NAMESCASESENSITIVE ON ;

UNITS
DATABASE MICRONS 1000 ;
END UNITS

LAYER NWELL
	TYPE MASTERSLICE ;
END NWELL
LAYER PP
	TYPE MASTERSLICE ;
END PP
LAYER NP
	TYPE MASTERSLICE ;
END NP
LAYER OD
	TYPE MASTERSLICE ;
END OD
LAYER POLY
	TYPE MASTERSLICE ;
END POLY
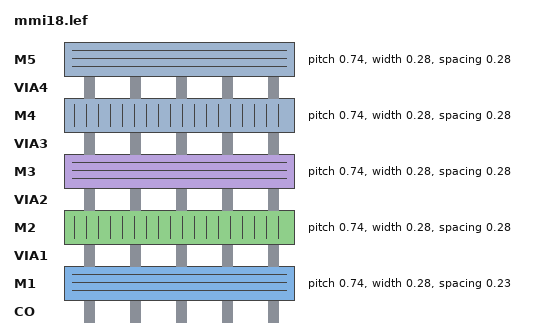
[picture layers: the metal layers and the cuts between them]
LAYER CO
	TYPE CUT ;
END CO
LAYER M1
	TYPE ROUTING ;
	PITCH 0.74 ;
	WIDTH 0.28 ;
	SPACING 0.23 ;
	DIRECTION HORIZONTAL ;
	RESISTANCE RPERSQ 0.11 ;
	CAPACITANCE CPERSQDIST .000389 ;
END M1
LAYER VIA1 
	TYPE CUT ;
END VIA1
LAYER M2
	TYPE ROUTING ;
	PITCH 0.74 ;
	WIDTH 0.28 ;
	SPACING 0.28 ;
	DIRECTION VERTICAL ;
	RESISTANCE RPERSQ 0.11 ;
	CAPACITANCE CPERSQDIST .000353 ;
END M2
LAYER VIA2
	TYPE CUT ;
END VIA2
LAYER M3
	TYPE ROUTING ;
	PITCH 0.74 ;
	WIDTH 0.28 ;
	SPACING 0.28 ;
	DIRECTION HORIZONTAL ;
	RESISTANCE RPERSQ 0.11 ;
	CAPACITANCE CPERSQDIST .000320 ;
END M3
LAYER VIA3
	TYPE CUT ;
END VIA3
LAYER M4
	TYPE ROUTING ;
	PITCH 0.74 ;
	WIDTH 0.28 ;
	SPACING 0.28 ;
	DIRECTION VERTICAL ;
	RESISTANCE RPERSQ 0.11 ;
	CAPACITANCE CPERSQDIST .000296 ;
END M4
LAYER VIA4
	TYPE CUT ;
END VIA4
LAYER M5
	TYPE ROUTING ;
	PITCH 0.74 ;
	WIDTH 0.28 ;
	SPACING 0.28 ;
	DIRECTION HORIZONTAL ;
	RESISTANCE RPERSQ 0.06 ;
	CAPACITANCE CPERSQDIST .000296 ;
END M5
VIA VIA12 DEFAULT
	RESISTANCE 1.21 ;
	LAYER M1 ; RECT -0.19 -0.19 0.19 0.19 ;
	LAYER VIA1 ; RECT -0.13 -0.13 0.13 0.13 ;
	LAYER M2 ; RECT -0.23 -0.23 0.23 0.23 ;
END VIA12
VIA VIA23 DEFAULT
	RESISTANCE 1.07 ;
	LAYER M2 ; RECT -0.23 -0.23 0.23 0.23 ;
	LAYER VIA2 ; RECT -0.13 -0.13 0.13 0.13 ;
	LAYER M3 ; RECT -0.23 -0.23 0.23 0.23 ;
END VIA23
VIA VIA34 DEFAULT
	RESISTANCE 1.19 ;
	LAYER M3 ; RECT -0.23 -0.23 0.23 0.23 ;
	LAYER VIA3 ; RECT -0.13 -0.13 0.13 0.13 ;
	LAYER M4 ; RECT -0.23 -0.23 0.23 0.23 ;
END VIA34
VIA VIA45 DEFAULT
	RESISTANCE 1.19 ;
	LAYER M4 ; RECT -0.23 -0.23 0.23 0.23 ;
	LAYER VIA4 ; RECT -0.13 -0.13 0.13 0.13 ;
	LAYER M5 ; RECT -0.23 -0.23 0.23 0.23 ;
END VIA45
VIARULE TURN1 GENERATE
	LAYER M1 ; DIRECTION HORIZONTAL ;
	LAYER M1 ; DIRECTION VERTICAL ;
END TURN1
VIARULE TURN2 GENERATE
	LAYER M2 ; DIRECTION VERTICAL ;
	LAYER M2 ; DIRECTION HORIZONTAL ;
END TURN2
VIARULE TURN3 GENERATE
	LAYER M3 ; DIRECTION HORIZONTAL ;
	LAYER M3 ; DIRECTION VERTICAL ;
END TURN3
VIARULE TURN4 GENERATE
	LAYER M4 ; DIRECTION VERTICAL ;
	LAYER M4 ; DIRECTION HORIZONTAL ;
END TURN4
VIARULE TURN5 GENERATE
	LAYER M5 ; DIRECTION HORIZONTAL ;
	LAYER M5 ; DIRECTION VERTICAL ;
END TURN5
VIARULE ONEVIA12
	LAYER M1 ; DIRECTION HORIZONTAL ; WIDTH 0.5 TO 0.9 ;
	LAYER M2 ; DIRECTION VERTICAL ; WIDTH 0.6 TO 0.9 ;
	VIA VIA12 ;
END ONEVIA12
VIARULE ONEVIA23
	LAYER M2 ; DIRECTION VERTICAL ; WIDTH 0.6 TO 0.9 ;
	LAYER M3 ; DIRECTION HORIZONTAL ; WIDTH 0.6 TO 0.9 ;
	VIA VIA23 ;
END ONEVIA23
VIARULE ONEVIA34
	LAYER M3 ; DIRECTION HORIZONTAL ; WIDTH 0.6 TO 0.9 ;
	LAYER M4 ; DIRECTION VERTICAL ; WIDTH 0.6 TO 0.9 ;
	VIA VIA34 ;
END ONEVIA34
VIARULE ONEVIA45
	LAYER M4 ; DIRECTION VERTICAL ; WIDTH 0.6 TO 0.9 ;
	LAYER M5 ; DIRECTION HORIZONTAL ; WIDTH 0.6 TO 0.9 ;
	VIA VIA45 ;
END ONEVIA45
VIARULE VIAGEN12 GENERATE
	LAYER M1 ; DIRECTION HORIZONTAL ; OVERHANG 0.06 ; METALOVERHANG 0.06 ;
	LAYER M2 ; DIRECTION VERTICAL ; OVERHANG 0.06 ; METALOVERHANG 0.06 ;
	LAYER VIA1 ; RECT  -0.13 -0.13 0.13 0.13 ; SPACING 0.74 BY 0.74 ;
END VIAGEN12
VIARULE VIAGEN23 GENERATE
	LAYER M2 ; DIRECTION VERTICAL ; OVERHANG 0.06 ; METALOVERHANG 0.06 ;
	LAYER M3 ; DIRECTION HORIZONTAL ; OVERHANG 0.06 ; METALOVERHANG 0.06 ;
	LAYER VIA2 ; RECT  -0.13 -0.13 0.13 0.13 ; SPACING 0.74 BY 0.74 ;
END VIAGEN23
VIARULE VIAGEN34 GENERATE
	LAYER M3 ; DIRECTION HORIZONTAL ; OVERHANG 0.06 ; METALOVERHANG 0.06 ;
	LAYER M4 ; DIRECTION VERTICAL ; OVERHANG 0.06 ; METALOVERHANG 0.06 ;
	LAYER VIA3 ; RECT  -0.13 -0.13 0.13 0.13 ; SPACING 0.74 BY 0.74 ;
END VIAGEN34
VIARULE VIAGEN45 GENERATE
	LAYER M4 ; DIRECTION VERTICAL ; OVERHANG 0.06 ; METALOVERHANG 0.06 ;
	LAYER M5 ; DIRECTION HORIZONTAL ; OVERHANG 0.06 ; METALOVERHANG 0.06 ;
	LAYER VIA4 ; RECT  -0.13 -0.13 0.13 0.13 ; SPACING 0.74 BY 0.74 ;
END VIAGEN45
SPACING
        SAMENET M1 M1 0.23 STACK ;
        SAMENET M2 M2 0.28 STACK ;
        SAMENET M3 M3 0.28 STACK ;
        SAMENET M4 M4 0.28 STACK ;
        SAMENET M5 M5 0.28 ;
	SAMENET VIA1 VIA1 0.26 STACK ;
        SAMENET VIA1 VIA2 0.00 STACK ;
	SAMENET VIA2 VIA2 0.26 STACK ;
        SAMENET VIA2 VIA3 0.00 STACK ;
	SAMENET VIA3 VIA3 0.26 STACK ;
        SAMENET VIA3 VIA4 0.00 STACK ;
	SAMENET VIA4 VIA4 0.26 STACK ;
END SPACING
MINFEATURE 0.005 0.005 ;
SITE CORE1
	SIZE 1.0 BY 7.4 ;
	CLASS CORE ;
	SYMMETRY Y ;
END CORE1
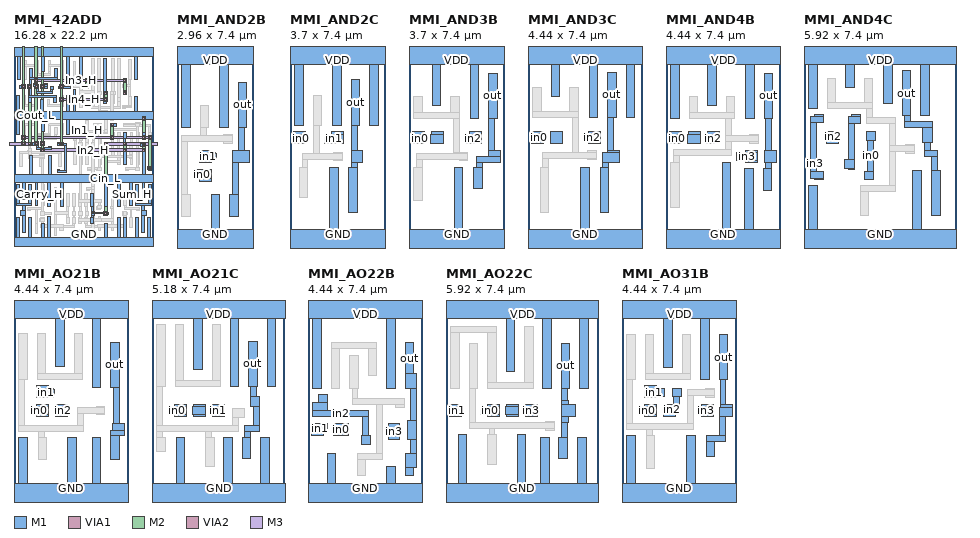
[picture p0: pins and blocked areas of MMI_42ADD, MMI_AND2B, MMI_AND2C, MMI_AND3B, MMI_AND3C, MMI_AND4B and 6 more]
MACRO MMI_42ADD
	CLASS CORE ;
	FOREIGN MMI_42ADD 0 0 ;
	SIZE 16.28 BY 22.2 ;
	SYMMETRY X Y ;
	SITE CORE1 ;
	PIN Sum_H
		DIRECTION output ;
		USE SIGNAL ;
		PORT
			LAYER M1 ;
			RECT 14.24 4.525 14.58 6.67 ;
			LAYER M1 ;
			RECT 15.68 4.525 16.02 6.67 ;
			LAYER M1 ;
			RECT 14.24 4.295 16.02 4.525 ;
			LAYER M1 ;
			RECT 14.91 3.64 15.25 4.295 ;
			LAYER M1 ;
			RECT 14.91 3.09 15.505 3.64 ;
			LAYER M1 ;
			RECT 14.91 1.1 15.25 3.09 ;
		END
		AntennaDiffArea 3.4977 ;
	END Sum_H
	PIN Carry_H
		DIRECTION output ;
		USE SIGNAL ;
		PORT
			LAYER M1 ;
			RECT 0.26 4.525 0.6 6.67 ;
			LAYER M1 ;
			RECT 1.7 4.525 2.04 6.67 ;
			LAYER M1 ;
			RECT 0.26 4.295 2.04 4.525 ;
			LAYER M1 ;
			RECT 1.03 3.64 1.37 4.295 ;
			LAYER M1 ;
			RECT 0.775 3.09 1.37 3.64 ;
			LAYER M1 ;
			RECT 1.03 1.1 1.37 3.09 ;
		END
		AntennaDiffArea 3.4977 ;
	END Carry_H
	PIN In2_H
		DIRECTION input ;
		USE SIGNAL ;
		PORT
			LAYER M1 ;
			RECT 3.59 18.355 3.93 18.51 ;
			LAYER M1 ;
			RECT 3.105 18.17 3.93 18.355 ;
			LAYER M1 ;
			RECT 3.105 17.905 3.92 18.17 ;
			LAYER M1 ;
			RECT 12.84 12.075 13.18 12.795 ;
			LAYER M1 ;
			RECT 3.105 11.245 3.555 11.695 ;
			LAYER M1 ;
			RECT 12.84 11.66 13.07 12.075 ;
			LAYER M1 ;
			RECT 12.76 11.28 13.14 11.66 ;
			LAYER M1 ;
			RECT 14.98 11.595 15.36 11.66 ;
			LAYER M1 ;
			RECT 14.97 11.545 15.375 11.595 ;
			LAYER M1 ;
			RECT 12.84 10.63 13.07 11.28 ;
			LAYER M1 ;
			RECT 14.81 11.205 15.375 11.545 ;
			LAYER M1 ;
			RECT 14.97 11.16 15.375 11.205 ;
			LAYER M1 ;
			RECT 12.84 9.11 13.18 10.63 ;
			LAYER VIA1 ;
			RECT 3.2 18 3.46 18.26 ;
			LAYER VIA1 ;
			RECT 3.2 11.34 3.46 11.6 ;
			LAYER VIA1 ;
			RECT 12.82 11.34 13.08 11.6 ;
			LAYER VIA1 ;
			RECT 15.04 11.34 15.3 11.6 ;
			LAYER M2 ;
			RECT 3.19 18.32 3.47 23.82 ;
			LAYER M2 ;
			RECT 3.14 17.94 3.52 18.32 ;
			LAYER M2 ;
			RECT 3.19 11.66 3.47 17.94 ;
			LAYER M2 ;
			RECT 3.14 11.28 3.52 11.66 ;
			LAYER M2 ;
			RECT 12.76 11.28 13.14 11.66 ;
			LAYER M2 ;
			RECT 14.98 11.28 15.36 11.66 ;
			LAYER M2 ;
			RECT 3.19 10.92 3.47 11.28 ;
			LAYER M2 ;
			RECT 12.81 10.92 13.09 11.28 ;
			LAYER M2 ;
			RECT 15.03 10.92 15.31 11.28 ;
			LAYER M2 ;
			RECT 3.14 10.54 3.52 10.92 ;
			LAYER M2 ;
			RECT 12.76 10.54 13.14 10.92 ;
			LAYER M2 ;
			RECT 14.98 10.54 15.36 10.92 ;
			LAYER VIA2 ;
			RECT 3.2 10.6 3.46 10.86 ;
			LAYER VIA2 ;
			RECT 12.82 10.6 13.08 10.86 ;
			LAYER VIA2 ;
			RECT 15.04 10.6 15.3 10.86 ;
			LAYER M3 ;
			RECT 3.14 10.87 3.52 10.92 ;
			LAYER M3 ;
			RECT 12.76 10.87 13.14 10.92 ;
			LAYER M3 ;
			RECT 14.98 10.87 15.36 10.92 ;
			LAYER M3 ;
			RECT 3.14 10.59 15.36 10.87 ;
			LAYER M3 ;
			RECT 3.14 10.54 3.52 10.59 ;
			LAYER M3 ;
			RECT 12.76 10.54 13.14 10.59 ;
			LAYER M3 ;
			RECT 14.98 10.54 15.36 10.59 ;
		END
		AntennaGateArea 2.7432 ;
		AntennaDiffArea 1.296 ;
	END In2_H
	PIN GND
		DIRECTION inout ;
		USE GROUND ;
		PORT
			LAYER M1 ;
			RECT 0.31 0.5 0.65 2.86 ;
			LAYER M1 ;
			RECT 1.75 0.5 2.09 2.86 ;
			LAYER M1 ;
			RECT 3.18 0.5 3.52 2.12 ;
			LAYER M1 ;
			RECT 3.96 0.5 4.3 2.925 ;
			LAYER M1 ;
			RECT 10.62 0.5 10.96 2.165 ;
			LAYER M1 ;
			RECT 12.06 0.5 12.4 2.875 ;
			LAYER M1 ;
			RECT 12.76 0.5 13.1 2.86 ;
			LAYER M1 ;
			RECT 14.19 0.5 14.53 2.86 ;
			LAYER M1 ;
			RECT 15.63 0.5 15.97 2.86 ;
			LAYER M1 ;
			RECT 0 -0.5 16.28 0.5 ;
			LAYER M1 ;
			RECT 0.26 15.3 0.6 17.13 ;
			LAYER M1 ;
			RECT 3.14 15.3 3.48 16.64 ;
			LAYER M1 ;
			RECT 6.14 15.3 6.48 17.13 ;
			LAYER M1 ;
			RECT 6.9 15.3 7.24 17.795 ;
			LAYER M1 ;
			RECT 14.08 15.3 14.42 16.965 ;
			LAYER M1 ;
			RECT 0 14.3 16.28 15.3 ;
			LAYER M1 ;
			RECT 0.3 12.555 0.64 14.3 ;
			LAYER M1 ;
			RECT 3.22 12.955 3.56 14.3 ;
			LAYER M1 ;
			RECT 6.14 12.555 6.48 14.3 ;
			LAYER M1 ;
			RECT 14.98 14.24 15.36 14.3 ;
			LAYER M1 ;
			RECT 15 12.4 15.34 12.795 ;
			LAYER M1 ;
			RECT 14.98 12.02 15.36 12.4 ;
			LAYER VIA1 ;
			RECT 15.04 14.3 15.3 14.56 ;
			LAYER VIA1 ;
			RECT 15.04 12.08 15.3 12.34 ;
			LAYER M2 ;
			RECT 14.98 14.24 15.36 14.62 ;
			LAYER M2 ;
			RECT 15.03 12.4 15.31 14.24 ;
			LAYER M2 ;
			RECT 14.98 12.02 15.36 12.4 ;
		END
	END GND
	PIN Cin_L
		DIRECTION input ;
		USE SIGNAL ;
		PORT
			LAYER M1 ;
			RECT 8.98 4.17 9.32 5.69 ;
			LAYER M1 ;
			RECT 9.09 3.52 9.32 4.17 ;
			LAYER M1 ;
			RECT 9.06 3.505 9.44 3.52 ;
			LAYER M1 ;
			RECT 10.505 3.505 10.955 3.555 ;
			LAYER M1 ;
			RECT 9.06 3.495 10.955 3.505 ;
			LAYER M1 ;
			RECT 9.06 3.275 11.09 3.495 ;
			LAYER M1 ;
			RECT 9.06 3.14 9.44 3.275 ;
			LAYER M1 ;
			RECT 10.505 3.155 11.09 3.275 ;
			LAYER M1 ;
			RECT 9.09 2.91 9.32 3.14 ;
			LAYER M1 ;
			RECT 10.505 3.105 10.955 3.155 ;
			LAYER M1 ;
			RECT 8.98 2.19 9.32 2.91 ;
			LAYER VIA1 ;
			RECT 10.6 3.2 10.86 3.46 ;
			LAYER M2 ;
			RECT 10.54 11.28 10.92 11.66 ;
			LAYER M2 ;
			RECT 10.59 3.52 10.87 11.28 ;
			LAYER M2 ;
			RECT 10.54 3.14 10.92 3.52 ;
			LAYER VIA2 ;
			RECT 10.6 11.34 10.86 11.6 ;
			LAYER M3 ;
			RECT 10.54 11.61 10.92 11.66 ;
			LAYER M3 ;
			RECT 10.54 11.33 16.79 11.61 ;
			LAYER M3 ;
			RECT 10.54 11.28 10.92 11.33 ;
		END
		AntennaGateArea 1.152 ;
		AntennaDiffArea 1.152 ;
	END Cin_L
	PIN In3_H
		DIRECTION input ;
		USE SIGNAL ;
		PORT
			LAYER M1 ;
			RECT 2.305 18.355 2.645 18.505 ;
			LAYER M1 ;
			RECT 2.305 18.165 2.815 18.355 ;
			LAYER M1 ;
			RECT 8.415 18.34 8.755 18.41 ;
			LAYER M1 ;
			RECT 2.365 17.905 2.815 18.165 ;
			LAYER M1 ;
			RECT 2.585 17.615 2.815 17.905 ;
			LAYER M1 ;
			RECT 4.32 17.795 4.66 18.135 ;
			LAYER M1 ;
			RECT 8.32 17.895 8.755 18.34 ;
			LAYER M1 ;
			RECT 4.32 17.615 4.55 17.795 ;
			LAYER M1 ;
			RECT 2.585 17.385 4.55 17.615 ;
			LAYER M1 ;
			RECT 12.76 17.2 13.14 17.755 ;
			LAYER M1 ;
			RECT 2.365 11.64 2.815 11.695 ;
			LAYER M1 ;
			RECT 2.16 11.585 2.815 11.64 ;
			LAYER M1 ;
			RECT 2.16 11.3 2.855 11.585 ;
			LAYER M1 ;
			RECT 2.365 11.245 2.855 11.3 ;
			LAYER M1 ;
			RECT 2.625 11.015 2.855 11.245 ;
			LAYER M1 ;
			RECT 4.01 11.015 4.35 11.2 ;
			LAYER M1 ;
			RECT 2.625 10.86 4.35 11.015 ;
			LAYER M1 ;
			RECT 2.625 10.785 4.245 10.86 ;
			LAYER VIA1 ;
			RECT 2.46 18 2.72 18.26 ;
			LAYER VIA1 ;
			RECT 8.38 18 8.64 18.26 ;
			LAYER VIA1 ;
			RECT 12.82 17.26 13.08 17.52 ;
			LAYER VIA1 ;
			RECT 2.46 11.34 2.72 11.6 ;
			LAYER M2 ;
			RECT 2.45 19.06 2.73 23.82 ;
			LAYER M2 ;
			RECT 2.4 18.68 2.78 19.06 ;
			LAYER M2 ;
			RECT 8.32 18.68 8.7 19.06 ;
			LAYER M2 ;
			RECT 12.76 18.68 13.14 19.06 ;
			LAYER M2 ;
			RECT 2.45 18.32 2.73 18.68 ;
			LAYER M2 ;
			RECT 8.37 18.32 8.65 18.68 ;
			LAYER M2 ;
			RECT 2.4 17.94 2.78 18.32 ;
			LAYER M2 ;
			RECT 8.32 17.94 8.7 18.32 ;
			LAYER M2 ;
			RECT 2.45 11.66 2.73 17.94 ;
			LAYER M2 ;
			RECT 12.81 17.58 13.09 18.68 ;
			LAYER M2 ;
			RECT 12.76 17.2 13.14 17.58 ;
			LAYER M2 ;
			RECT 2.4 11.28 2.78 11.66 ;
			LAYER VIA2 ;
			RECT 2.46 18.74 2.72 19 ;
			LAYER VIA2 ;
			RECT 8.38 18.74 8.64 19 ;
			LAYER VIA2 ;
			RECT 12.82 18.74 13.08 19 ;
			LAYER M3 ;
			RECT 2.4 19.01 2.78 19.06 ;
			LAYER M3 ;
			RECT 8.32 19.01 8.7 19.06 ;
			LAYER M3 ;
			RECT 12.76 19.01 13.14 19.06 ;
			LAYER M3 ;
			RECT 2.4 18.73 13.14 19.01 ;
			LAYER M3 ;
			RECT 2.4 18.68 2.78 18.73 ;
			LAYER M3 ;
			RECT 8.32 18.68 8.7 18.73 ;
			LAYER M3 ;
			RECT 12.76 18.68 13.14 18.73 ;
		END
		AntennaGateArea 4.6872 ;
	END In3_H
	PIN VDD
		DIRECTION inout ;
		USE POWER ;
		PORT
			LAYER M1 ;
			RECT 1.78 7.9 2.12 10.055 ;
			LAYER M1 ;
			RECT 4.08 7.9 4.42 10.055 ;
			LAYER M1 ;
			RECT 15 7.9 15.34 10.63 ;
			LAYER M1 ;
			RECT 0 6.9 16.28 7.9 ;
			LAYER M1 ;
			RECT 0.98 4.915 1.32 6.9 ;
			LAYER M1 ;
			RECT 2.46 4.27 2.8 6.9 ;
			LAYER M1 ;
			RECT 3.96 4.19 4.3 6.9 ;
			LAYER M1 ;
			RECT 5.4 4.19 5.74 6.9 ;
			LAYER M1 ;
			RECT 10.62 4.19 10.96 6.9 ;
			LAYER M1 ;
			RECT 12.06 4.19 12.4 6.9 ;
			LAYER M1 ;
			RECT 13.48 4.27 13.82 6.9 ;
			LAYER M1 ;
			RECT 14.96 4.915 15.3 6.9 ;
			LAYER M1 ;
			RECT 0 21.7 16.28 22.7 ;
			LAYER M1 ;
			RECT 0.38 18.97 0.72 21.7 ;
			LAYER M1 ;
			RECT 3.26 19.89 3.6 21.7 ;
			LAYER M1 ;
			RECT 6.14 18.97 6.48 21.7 ;
			LAYER M1 ;
			RECT 7.62 18.97 7.96 21.7 ;
			LAYER M1 ;
			RECT 14.08 18.97 14.42 21.7 ;
		END
	END VDD
	PIN Cout_L
		DIRECTION output ;
		USE SIGNAL ;
		PORT
			LAYER M1 ;
			RECT 1.82 19.2 2.16 20.25 ;
			LAYER M1 ;
			RECT 4.7 19.2 5.04 20.25 ;
			LAYER M1 ;
			RECT 1.82 18.97 5.04 19.2 ;
			LAYER M1 ;
			RECT 1.82 18.355 2.05 18.97 ;
			LAYER M1 ;
			RECT 1.625 17.905 2.075 18.355 ;
			LAYER M1 ;
			RECT 1.775 17.13 2.005 17.905 ;
			LAYER M1 ;
			RECT 1.7 17.1 2.04 17.13 ;
			LAYER M1 ;
			RECT 4.58 17.1 4.92 17.13 ;
			LAYER M1 ;
			RECT 1.7 16.87 4.925 17.1 ;
			LAYER M1 ;
			RECT 1.7 16.32 2.04 16.87 ;
			LAYER M1 ;
			RECT 4.58 16.32 4.92 16.87 ;
			LAYER VIA1 ;
			RECT 1.72 18 1.98 18.26 ;
			LAYER M2 ;
			RECT 1.66 17.94 2.04 18.32 ;
			LAYER M2 ;
			RECT 1.71 11.66 1.99 17.94 ;
			LAYER M2 ;
			RECT 1.66 11.28 2.04 11.66 ;
			LAYER VIA2 ;
			RECT 1.72 11.34 1.98 11.6 ;
			LAYER M3 ;
			RECT 1.66 11.61 2.04 11.66 ;
			LAYER M3 ;
			RECT -0.51 11.33 2.04 11.61 ;
			LAYER M3 ;
			RECT 1.66 11.28 2.04 11.33 ;
		END
		AntennaDiffArea 3.9528 ;
	END Cout_L
	PIN In4_H
		DIRECTION input ;
		USE SIGNAL ;
		PORT
			LAYER M1 ;
			RECT 5.325 18.355 5.57 18.36 ;
			LAYER M1 ;
			RECT 5.325 18.3 5.775 18.355 ;
			LAYER M1 ;
			RECT 5.325 18.225 6.635 18.3 ;
			LAYER M1 ;
			RECT 5.22 17.96 6.635 18.225 ;
			LAYER M1 ;
			RECT 5.22 17.905 5.775 17.96 ;
			LAYER M1 ;
			RECT 5.22 17.885 5.56 17.905 ;
			LAYER M1 ;
			RECT 5.325 17.88 5.56 17.885 ;
			LAYER M1 ;
			RECT 10.495 17.58 10.835 21.47 ;
			LAYER M1 ;
			RECT 10.495 17.2 10.92 17.58 ;
			LAYER M1 ;
			RECT 10.495 16.16 10.835 17.2 ;
			LAYER M1 ;
			RECT 5.36 11.645 5.74 11.66 ;
			LAYER M1 ;
			RECT 5.07 11.525 5.74 11.645 ;
			LAYER M1 ;
			RECT 5.07 11.51 5.775 11.525 ;
			LAYER M1 ;
			RECT 5.07 11.305 6.11 11.51 ;
			LAYER M1 ;
			RECT 5.36 11.28 6.11 11.305 ;
			LAYER M1 ;
			RECT 5.03 8.405 5.37 8.51 ;
			LAYER M1 ;
			RECT 5.88 8.405 6.11 11.28 ;
			LAYER M1 ;
			RECT 5.03 8.175 6.11 8.405 ;
			LAYER M1 ;
			RECT 5.03 8.17 5.37 8.175 ;
			LAYER VIA1 ;
			RECT 5.42 18 5.68 18.26 ;
			LAYER VIA1 ;
			RECT 10.6 17.26 10.86 17.52 ;
			LAYER VIA1 ;
			RECT 5.42 11.34 5.68 11.6 ;
			LAYER M2 ;
			RECT 5.41 18.32 5.69 23.82 ;
			LAYER M2 ;
			RECT 5.36 17.94 5.74 18.32 ;
			LAYER M2 ;
			RECT 5.41 16.84 5.69 17.94 ;
			LAYER M2 ;
			RECT 10.54 17.2 10.92 17.58 ;
			LAYER M2 ;
			RECT 10.59 16.84 10.87 17.2 ;
			LAYER M2 ;
			RECT 5.36 16.46 5.74 16.84 ;
			LAYER M2 ;
			RECT 10.54 16.46 10.92 16.84 ;
			LAYER M2 ;
			RECT 5.41 11.66 5.69 16.46 ;
			LAYER M2 ;
			RECT 5.36 11.28 5.74 11.66 ;
			LAYER VIA2 ;
			RECT 5.42 16.52 5.68 16.78 ;
			LAYER VIA2 ;
			RECT 10.6 16.52 10.86 16.78 ;
			LAYER M3 ;
			RECT 5.36 16.79 5.74 16.84 ;
			LAYER M3 ;
			RECT 10.54 16.79 10.92 16.84 ;
			LAYER M3 ;
			RECT 5.36 16.51 10.92 16.79 ;
			LAYER M3 ;
			RECT 5.36 16.46 5.74 16.51 ;
			LAYER M3 ;
			RECT 10.54 16.46 10.92 16.51 ;
		END
		AntennaGateArea 3.4992 ;
		AntennaDiffArea 3.312 ;
	END In4_H
	PIN In1_H
		DIRECTION input ;
		USE SIGNAL ;
		PORT
			LAYER M1 ;
			RECT 0.885 18.3 1.335 18.355 ;
			LAYER M1 ;
			RECT 0.7 17.96 1.335 18.3 ;
			LAYER M1 ;
			RECT 0.885 17.905 1.335 17.96 ;
			LAYER M1 ;
			RECT 11.28 13.855 11.66 13.88 ;
			LAYER M1 ;
			RECT 11.28 13.515 11.98 13.855 ;
			LAYER M1 ;
			RECT 11.28 13.5 11.66 13.515 ;
			LAYER M1 ;
			RECT 0.885 11.245 1.335 11.695 ;
			LAYER M1 ;
			RECT 15.57 8.7 15.91 8.765 ;
			LAYER M1 ;
			RECT 15.57 8.425 16.1 8.7 ;
			LAYER M1 ;
			RECT 15.72 8.32 16.1 8.425 ;
			LAYER VIA1 ;
			RECT 0.98 18 1.24 18.26 ;
			LAYER VIA1 ;
			RECT 11.34 13.56 11.6 13.82 ;
			LAYER VIA1 ;
			RECT 0.98 11.34 1.24 11.6 ;
			LAYER VIA1 ;
			RECT 15.78 8.38 16.04 8.64 ;
			LAYER M2 ;
			RECT 0.97 18.32 1.25 23.82 ;
			LAYER M2 ;
			RECT 0.92 17.94 1.3 18.32 ;
			LAYER M2 ;
			RECT 0.97 12.4 1.25 17.94 ;
			LAYER M2 ;
			RECT 11.28 13.5 11.66 13.88 ;
			LAYER M2 ;
			RECT 11.33 12.4 11.61 13.5 ;
			LAYER M2 ;
			RECT 0.92 12.02 1.3 12.4 ;
			LAYER M2 ;
			RECT 11.28 12.02 11.66 12.4 ;
			LAYER M2 ;
			RECT 15.72 12.02 16.1 12.4 ;
			LAYER M2 ;
			RECT 0.97 11.66 1.25 12.02 ;
			LAYER M2 ;
			RECT 0.92 11.28 1.3 11.66 ;
			LAYER M2 ;
			RECT 15.77 8.7 16.05 12.02 ;
			LAYER M2 ;
			RECT 15.72 8.32 16.1 8.7 ;
			LAYER VIA2 ;
			RECT 0.98 12.08 1.24 12.34 ;
			LAYER VIA2 ;
			RECT 11.34 12.08 11.6 12.34 ;
			LAYER VIA2 ;
			RECT 15.78 12.08 16.04 12.34 ;
			LAYER M3 ;
			RECT 0.92 12.35 1.3 12.4 ;
			LAYER M3 ;
			RECT 11.28 12.35 11.66 12.4 ;
			LAYER M3 ;
			RECT 15.72 12.35 16.1 12.4 ;
			LAYER M3 ;
			RECT 0.92 12.07 16.1 12.35 ;
			LAYER M3 ;
			RECT 0.92 12.02 1.3 12.07 ;
			LAYER M3 ;
			RECT 11.28 12.02 11.66 12.07 ;
			LAYER M3 ;
			RECT 15.72 12.02 16.1 12.07 ;
		END
		AntennaGateArea 3.6072 ;
	END In1_H
	OBS
		LAYER M1 ;
		RECT 1.1 20.72 1.44 21.17 ;
		LAYER M1 ;
		RECT 2.54 20.72 2.88 21.17 ;
		LAYER M1 ;
		RECT 1.1 20.49 2.88 20.72 ;
		LAYER M1 ;
		RECT 1.1 18.97 1.44 20.49 ;
		LAYER M1 ;
		RECT 2.54 19.89 2.88 20.49 ;
		LAYER M1 ;
		RECT 3.98 20.715 4.32 21.17 ;
		LAYER M1 ;
		RECT 5.42 20.715 5.76 21.17 ;
		LAYER M1 ;
		RECT 3.98 20.485 5.76 20.715 ;
		LAYER M1 ;
		RECT 3.98 19.89 4.32 20.485 ;
		LAYER M1 ;
		RECT 2.59 19.66 2.82 19.89 ;
		LAYER M1 ;
		RECT 4.03 19.66 4.26 19.89 ;
		LAYER M1 ;
		RECT 2.59 19.43 4.26 19.66 ;
		LAYER M1 ;
		RECT 5.42 18.97 5.76 20.485 ;
		LAYER M1 ;
		RECT 6.9 18.43 7.24 21.09 ;
		LAYER M1 ;
		RECT 6.9 18.035 7.96 18.43 ;
		LAYER M1 ;
		RECT 0.98 16.08 1.32 17.13 ;
		LAYER M1 ;
		RECT 2.42 16.08 2.76 16.64 ;
		LAYER M1 ;
		RECT 0.98 15.85 2.76 16.08 ;
		LAYER M1 ;
		RECT 0.98 15.83 1.32 15.85 ;
		LAYER M1 ;
		RECT 2.42 15.83 2.76 15.85 ;
		LAYER M1 ;
		RECT 3.86 16.07 4.2 16.64 ;
		LAYER M1 ;
		RECT 5.42 16.07 5.76 17.13 ;
		LAYER M1 ;
		RECT 3.86 15.84 5.76 16.07 ;
		LAYER M1 ;
		RECT 3.86 15.83 4.2 15.84 ;
		LAYER M1 ;
		RECT 5.42 15.83 5.76 15.84 ;
		LAYER M1 ;
		RECT 7.62 17.665 7.96 18.035 ;
		LAYER M1 ;
		RECT 9.055 17.665 9.395 21.47 ;
		LAYER M1 ;
		RECT 7.62 17.385 9.395 17.665 ;
		LAYER M1 ;
		RECT 7.62 15.675 7.96 17.385 ;
		LAYER M1 ;
		RECT 9.055 16.885 9.395 17.385 ;
		LAYER M1 ;
		RECT 9.05 15.89 9.395 16.885 ;
		LAYER M1 ;
		RECT 9.775 17.58 10.115 21.47 ;
		LAYER M1 ;
		RECT 11.365 17.58 11.705 21.47 ;
		LAYER M1 ;
		RECT 9.775 17.2 10.18 17.58 ;
		LAYER M1 ;
		RECT 11.28 17.2 11.81 17.58 ;
		LAYER M1 ;
		RECT 9.775 16.16 10.115 17.2 ;
		LAYER M1 ;
		RECT 11.365 16.16 11.705 17.2 ;
		LAYER M1 ;
		RECT 12.085 16.88 12.425 21.47 ;
		LAYER M1 ;
		RECT 13.36 18.97 13.7 21.29 ;
		LAYER M1 ;
		RECT 12.665 18.36 13.005 18.41 ;
		LAYER M1 ;
		RECT 13.42 18.36 13.65 18.97 ;
		LAYER M1 ;
		RECT 12.665 18.13 13.65 18.36 ;
		LAYER M1 ;
		RECT 12.665 18.07 13.005 18.13 ;
		LAYER M1 ;
		RECT 13.42 16.965 13.65 18.13 ;
		LAYER M1 ;
		RECT 12.085 16.36 12.49 16.88 ;
		LAYER M1 ;
		RECT 12.15 15.89 12.49 16.36 ;
		LAYER M1 ;
		RECT 13.36 15.95 13.7 16.965 ;
		LAYER M1 ;
		RECT 9.05 15.605 12.49 15.89 ;
		LAYER M1 ;
		RECT 12.72 15.845 13.7 15.95 ;
		LAYER M1 ;
		RECT 12.72 15.72 13.695 15.845 ;
		LAYER M1 ;
		RECT 12.72 15.61 13.06 15.72 ;
		LAYER M1 ;
		RECT 9.055 15.6 12.49 15.605 ;
		LAYER M1 ;
		RECT 9.055 15.59 12.37 15.6 ;
		LAYER M1 ;
		RECT 1.02 13.625 2.8 13.855 ;
		LAYER M1 ;
		RECT 1.02 12.555 1.36 13.625 ;
		LAYER M1 ;
		RECT 1.74 12.555 2.08 13.395 ;
		LAYER M1 ;
		RECT 2.46 12.625 2.8 13.625 ;
		LAYER M1 ;
		RECT 3.98 13.625 5.76 13.855 ;
		LAYER M1 ;
		RECT 3.98 12.625 4.32 13.625 ;
		LAYER M1 ;
		RECT 2.46 12.555 4.32 12.625 ;
		LAYER M1 ;
		RECT 4.7 12.555 5.04 13.395 ;
		LAYER M1 ;
		RECT 5.42 12.555 5.76 13.625 ;
		LAYER M1 ;
		RECT 9.675 13.795 10.18 13.88 ;
		LAYER M1 ;
		RECT 9.34 13.5 10.18 13.795 ;
		LAYER M1 ;
		RECT 14.18 13.85 14.75 13.91 ;
		LAYER M1 ;
		RECT 12.75 13.77 14.75 13.85 ;
		LAYER M1 ;
		RECT 12.75 13.54 16 13.77 ;
		LAYER M1 ;
		RECT 12.75 13.51 14.75 13.54 ;
		LAYER M1 ;
		RECT 14.18 13.5 14.75 13.51 ;
		LAYER M1 ;
		RECT 9.34 13.455 9.68 13.5 ;
		LAYER M1 ;
		RECT 10.54 13.075 10.92 13.14 ;
		LAYER M1 ;
		RECT 7.005 12.845 10.92 13.075 ;
		LAYER M1 ;
		RECT 7.005 12.615 7.235 12.845 ;
		LAYER M1 ;
		RECT 9.95 12.76 10.92 12.845 ;
		LAYER M1 ;
		RECT 11.445 13.025 14.57 13.255 ;
		LAYER M1 ;
		RECT 11.445 12.795 11.675 13.025 ;
		LAYER M1 ;
		RECT 14.34 12.795 14.57 13.025 ;
		LAYER M1 ;
		RECT 15.77 12.795 16 13.54 ;
		LAYER M1 ;
		RECT 9.95 12.695 10.875 12.76 ;
		LAYER M1 ;
		RECT 9.95 12.615 10.18 12.695 ;
		LAYER M1 ;
		RECT 1.85 12.155 2.08 12.555 ;
		LAYER M1 ;
		RECT 2.57 12.395 4.21 12.555 ;
		LAYER M1 ;
		RECT 4.7 12.155 4.93 12.555 ;
		LAYER M1 ;
		RECT 1.7 11.925 4.93 12.155 ;
		LAYER M1 ;
		RECT 1.7 10.92 1.93 11.925 ;
		LAYER M1 ;
		RECT 6.96 11.895 7.3 12.615 ;
		LAYER M1 ;
		RECT 7.68 11.895 8.02 12.615 ;
		LAYER M1 ;
		RECT 8.4 11.895 8.74 12.615 ;
		LAYER M1 ;
		RECT 9.12 11.895 9.46 12.615 ;
		LAYER M1 ;
		RECT 9.84 11.895 10.18 12.615 ;
		LAYER M1 ;
		RECT 1.66 10.72 2.04 10.92 ;
		LAYER M1 ;
		RECT 1.53 10.545 2.04 10.72 ;
		LAYER M1 ;
		RECT 0.63 10.315 5.57 10.545 ;
		LAYER M1 ;
		RECT 0.63 8.775 0.97 10.315 ;
		LAYER M1 ;
		RECT 2.93 8.775 3.27 10.315 ;
		LAYER M1 ;
		RECT 5.23 8.775 5.57 10.315 ;
		LAYER M1 ;
		RECT 7.015 10.63 7.245 11.895 ;
		LAYER M1 ;
		RECT 7.685 11.66 7.915 11.895 ;
		LAYER M1 ;
		RECT 8.4 11.66 8.63 11.895 ;
		LAYER M1 ;
		RECT 9.155 11.66 9.385 11.895 ;
		LAYER M1 ;
		RECT 7.58 11.28 7.96 11.66 ;
		LAYER M1 ;
		RECT 8.32 11.28 8.7 11.66 ;
		LAYER M1 ;
		RECT 9.06 11.28 9.44 11.66 ;
		LAYER M1 ;
		RECT 7.685 10.63 7.915 11.28 ;
		LAYER M1 ;
		RECT 8.4 10.63 8.63 11.28 ;
		LAYER M1 ;
		RECT 9.155 10.63 9.385 11.28 ;
		LAYER M1 ;
		RECT 9.95 10.63 10.18 11.895 ;
		LAYER M1 ;
		RECT 11.4 12.075 11.74 12.795 ;
		LAYER M1 ;
		RECT 12.12 12.075 12.46 12.795 ;
		LAYER M1 ;
		RECT 13.56 12.075 13.9 12.795 ;
		LAYER M1 ;
		RECT 14.28 12.075 14.62 12.795 ;
		LAYER M1 ;
		RECT 10.54 11.265 10.92 11.29 ;
		LAYER M1 ;
		RECT 10.415 10.925 10.92 11.265 ;
		LAYER M1 ;
		RECT 10.54 10.91 10.92 10.925 ;
		LAYER M1 ;
		RECT 6.96 9.11 7.3 10.63 ;
		LAYER M1 ;
		RECT 7.68 9.11 8.02 10.63 ;
		LAYER M1 ;
		RECT 8.4 9.11 8.74 10.63 ;
		LAYER M1 ;
		RECT 9.12 9.11 9.46 10.63 ;
		LAYER M1 ;
		RECT 9.84 9.11 10.18 10.63 ;
		LAYER M1 ;
		RECT 10.615 9.575 10.845 10.91 ;
		LAYER M1 ;
		RECT 11.4 10.63 11.63 12.075 ;
		LAYER M1 ;
		RECT 12.125 11.66 12.355 12.075 ;
		LAYER M1 ;
		RECT 13.595 11.66 13.825 12.075 ;
		LAYER M1 ;
		RECT 12.02 11.28 12.4 11.66 ;
		LAYER M1 ;
		RECT 13.5 11.28 13.88 11.66 ;
		LAYER M1 ;
		RECT 12.125 10.63 12.355 11.28 ;
		LAYER M1 ;
		RECT 13.595 10.63 13.825 11.28 ;
		LAYER M1 ;
		RECT 14.35 10.63 14.58 12.075 ;
		LAYER M1 ;
		RECT 15.72 12.075 16.06 12.795 ;
		LAYER M1 ;
		RECT 15.83 10.63 16.06 12.075 ;
		LAYER M1 ;
		RECT 11.4 9.82 11.74 10.63 ;
		LAYER M1 ;
		RECT 12.12 9.575 12.46 10.63 ;
		LAYER M1 ;
		RECT 10.615 9.345 12.46 9.575 ;
		LAYER M1 ;
		RECT 12.12 9.11 12.46 9.345 ;
		LAYER M1 ;
		RECT 13.56 9.11 13.9 10.63 ;
		LAYER M1 ;
		RECT 14.28 9.11 14.62 10.63 ;
		LAYER M1 ;
		RECT 8.64 8.675 8.98 8.725 ;
		LAYER M1 ;
		RECT 9.675 8.675 10.18 8.7 ;
		LAYER M1 ;
		RECT 8.64 8.445 10.18 8.675 ;
		LAYER M1 ;
		RECT 8.64 8.385 8.98 8.445 ;
		LAYER M1 ;
		RECT 9.675 8.32 10.18 8.445 ;
		LAYER M1 ;
		RECT 13.08 8.675 13.42 8.725 ;
		LAYER M1 ;
		RECT 14.24 8.675 14.62 8.7 ;
		LAYER M1 ;
		RECT 13.08 8.445 14.64 8.675 ;
		LAYER M1 ;
		RECT 13.08 8.385 13.42 8.445 ;
		LAYER M1 ;
		RECT 14.24 8.32 14.62 8.445 ;
		LAYER M1 ;
		RECT 15.72 9.11 16.06 10.63 ;
		LAYER M1 ;
		RECT 3.18 4.27 3.52 6.67 ;
		LAYER M1 ;
		RECT 1.61 4.02 1.95 4.025 ;
		LAYER M1 ;
		RECT 3.265 4.02 3.495 4.27 ;
		LAYER M1 ;
		RECT 1.61 3.79 3.495 4.02 ;
		LAYER M1 ;
		RECT 1.61 3.685 1.95 3.79 ;
		LAYER M1 ;
		RECT 2.46 2.12 2.69 3.79 ;
		LAYER M1 ;
		RECT 4.68 3.57 5.02 6.31 ;
		LAYER M1 ;
		RECT 8.46 6.405 8.8 6.415 ;
		LAYER M1 ;
		RECT 9.06 6.405 9.44 6.48 ;
		LAYER M1 ;
		RECT 8.46 6.175 9.44 6.405 ;
		LAYER M1 ;
		RECT 8.46 6.075 8.8 6.175 ;
		LAYER M1 ;
		RECT 9.06 6.1 9.44 6.175 ;
		LAYER M1 ;
		RECT 6.1 4.17 6.44 5.69 ;
		LAYER M1 ;
		RECT 6.82 4.17 7.16 5.69 ;
		LAYER M1 ;
		RECT 7.54 4.17 7.88 5.69 ;
		LAYER M1 ;
		RECT 8.26 4.17 8.6 5.69 ;
		LAYER M1 ;
		RECT 6.1 3.57 6.33 4.17 ;
		LAYER M1 ;
		RECT 3.105 3.445 3.555 3.555 ;
		LAYER M1 ;
		RECT 4.02 3.445 4.36 3.5 ;
		LAYER M1 ;
		RECT 3.105 3.215 4.36 3.445 ;
		LAYER M1 ;
		RECT 3.105 3.105 3.555 3.215 ;
		LAYER M1 ;
		RECT 4.02 3.16 4.36 3.215 ;
		LAYER M1 ;
		RECT 4.68 3.23 6.33 3.57 ;
		LAYER M1 ;
		RECT 6.895 3.52 7.125 4.17 ;
		LAYER M1 ;
		RECT 7.65 3.52 7.88 4.17 ;
		LAYER M1 ;
		RECT 8.365 3.52 8.595 4.17 ;
		LAYER M1 ;
		RECT 9.8 4.09 10.18 4.26 ;
		LAYER M1 ;
		RECT 11.34 4.185 11.68 5.71 ;
		LAYER M1 ;
		RECT 12.76 4.27 13.1 6.05 ;
		LAYER M1 ;
		RECT 9.69 3.88 10.18 4.09 ;
		LAYER M1 ;
		RECT 11.33 3.955 11.68 4.185 ;
		LAYER M1 ;
		RECT 9.69 3.75 10.16 3.88 ;
		LAYER M1 ;
		RECT 3.12 2.76 3.57 2.815 ;
		LAYER M1 ;
		RECT 2.94 2.42 3.57 2.76 ;
		LAYER M1 ;
		RECT 3.12 2.365 3.57 2.42 ;
		LAYER M1 ;
		RECT 2.46 0.96 2.8 2.12 ;
		LAYER M1 ;
		RECT 4.68 0.805 5.02 3.23 ;
		LAYER M1 ;
		RECT 6.1 2.91 6.33 3.23 ;
		LAYER M1 ;
		RECT 6.84 3.14 7.22 3.52 ;
		LAYER M1 ;
		RECT 7.58 3.14 7.96 3.52 ;
		LAYER M1 ;
		RECT 8.32 3.14 8.7 3.52 ;
		LAYER M1 ;
		RECT 6.895 2.91 7.125 3.14 ;
		LAYER M1 ;
		RECT 7.65 2.91 7.88 3.14 ;
		LAYER M1 ;
		RECT 8.365 2.91 8.595 3.14 ;
		LAYER M1 ;
		RECT 6.1 2.19 6.44 2.91 ;
		LAYER M1 ;
		RECT 6.82 2.19 7.16 2.91 ;
		LAYER M1 ;
		RECT 7.54 2.19 7.88 2.91 ;
		LAYER M1 ;
		RECT 8.26 2.19 8.6 2.91 ;
		LAYER M1 ;
		RECT 9.8 2.76 10.18 2.78 ;
		LAYER M1 ;
		RECT 11.34 2.76 11.68 3.955 ;
		LAYER M1 ;
		RECT 12.87 4.025 13.1 4.27 ;
		LAYER M1 ;
		RECT 12.87 3.795 14.67 4.025 ;
		LAYER M1 ;
		RECT 12.725 3.495 13.175 3.555 ;
		LAYER M1 ;
		RECT 12.725 3.155 13.21 3.495 ;
		LAYER M1 ;
		RECT 12.725 3.105 13.175 3.155 ;
		LAYER M1 ;
		RECT 9.8 2.42 11.68 2.76 ;
		LAYER M1 ;
		RECT 9.8 2.4 10.18 2.42 ;
		LAYER M1 ;
		RECT 6.89 1.89 7.12 2.19 ;
		LAYER M1 ;
		RECT 5.365 1.705 7.12 1.89 ;
		LAYER M1 ;
		RECT 8.365 1.955 8.595 2.19 ;
		LAYER M1 ;
		RECT 9.765 1.955 10.215 2.075 ;
		LAYER M1 ;
		RECT 8.365 1.725 10.215 1.955 ;
		LAYER M1 ;
		RECT 5.36 1.66 7.12 1.705 ;
		LAYER M1 ;
		RECT 9.8 1.66 10.18 1.725 ;
		LAYER M1 ;
		RECT 5.36 1.325 5.74 1.66 ;
		LAYER M1 ;
		RECT 7.68 1.44 8.02 1.495 ;
		LAYER M1 ;
		RECT 9.06 1.44 9.44 1.48 ;
		LAYER M1 ;
		RECT 7.68 1.21 9.44 1.44 ;
		LAYER M1 ;
		RECT 7.68 1.155 8.02 1.21 ;
		LAYER M1 ;
		RECT 9.06 1.1 9.44 1.21 ;
		LAYER M1 ;
		RECT 11.34 1.355 11.68 2.42 ;
		LAYER M1 ;
		RECT 13.555 2.86 13.785 3.795 ;
		LAYER M1 ;
		RECT 14.33 3.685 14.67 3.795 ;
		LAYER M1 ;
		RECT 13.48 1.7 13.82 2.86 ;
		LAYER VIA1 ;
		RECT 9.86 17.26 10.12 17.52 ;
		LAYER VIA1 ;
		RECT 11.34 17.26 11.6 17.52 ;
		LAYER VIA1 ;
		RECT 9.86 13.56 10.12 13.82 ;
		LAYER VIA1 ;
		RECT 14.3 13.56 14.56 13.82 ;
		LAYER VIA1 ;
		RECT 10.6 12.82 10.86 13.08 ;
		LAYER VIA1 ;
		RECT 7.64 11.34 7.9 11.6 ;
		LAYER VIA1 ;
		RECT 8.38 11.34 8.64 11.6 ;
		LAYER VIA1 ;
		RECT 9.12 11.34 9.38 11.6 ;
		LAYER VIA1 ;
		RECT 13.56 11.34 13.82 11.6 ;
		LAYER VIA1 ;
		RECT 1.72 10.6 1.98 10.86 ;
		LAYER VIA1 ;
		RECT 9.86 8.38 10.12 8.64 ;
		LAYER VIA1 ;
		RECT 14.3 8.38 14.56 8.64 ;
		LAYER VIA1 ;
		RECT 9.12 6.16 9.38 6.42 ;
		LAYER VIA1 ;
		RECT 9.86 3.94 10.12 4.2 ;
		LAYER VIA1 ;
		RECT 3.2 3.2 3.46 3.46 ;
		LAYER VIA1 ;
		RECT 7.64 3.2 7.9 3.46 ;
		LAYER VIA1 ;
		RECT 12.82 3.2 13.08 3.46 ;
		LAYER VIA1 ;
		RECT 3.2 2.46 3.46 2.72 ;
		LAYER VIA1 ;
		RECT 9.86 2.46 10.12 2.72 ;
		LAYER VIA1 ;
		RECT 9.86 1.72 10.12 1.98 ;
		LAYER VIA1 ;
		RECT 5.42 1.385 5.68 1.645 ;
		LAYER VIA1 ;
		RECT 9.12 1.16 9.38 1.42 ;
		LAYER M2 ;
		RECT 9.8 17.2 10.18 17.58 ;
		LAYER M2 ;
		RECT 11.28 17.2 11.66 17.58 ;
		LAYER M2 ;
		RECT 9.85 15.31 10.13 17.2 ;
		LAYER M2 ;
		RECT 9.85 15.03 10.87 15.31 ;
		LAYER M2 ;
		RECT 8.32 14.24 8.7 14.62 ;
		LAYER M2 ;
		RECT 8.37 11.66 8.65 14.24 ;
		LAYER M2 ;
		RECT 9.8 13.5 10.18 13.88 ;
		LAYER M2 ;
		RECT 7.58 11.28 7.96 11.66 ;
		LAYER M2 ;
		RECT 8.32 11.28 8.7 11.66 ;
		LAYER M2 ;
		RECT 9.06 11.28 9.44 11.66 ;
		LAYER M2 ;
		RECT 1.66 10.54 2.04 10.92 ;
		LAYER M2 ;
		RECT 1.71 10.18 1.99 10.54 ;
		LAYER M2 ;
		RECT 1.66 9.8 2.04 10.18 ;
		LAYER M2 ;
		RECT 3.14 9.8 3.52 10.18 ;
		LAYER M2 ;
		RECT 3.19 3.52 3.47 9.8 ;
		LAYER M2 ;
		RECT 7.63 5 7.91 11.28 ;
		LAYER M2 ;
		RECT 9.11 6.48 9.39 11.28 ;
		LAYER M2 ;
		RECT 9.85 10.18 10.13 13.5 ;
		LAYER M2 ;
		RECT 10.59 13.14 10.87 15.03 ;
		LAYER M2 ;
		RECT 11.33 14.62 11.61 17.2 ;
		LAYER M2 ;
		RECT 11.28 14.24 11.66 14.62 ;
		LAYER M2 ;
		RECT 14.24 13.5 14.62 13.88 ;
		LAYER M2 ;
		RECT 10.54 12.76 10.92 13.14 ;
		LAYER M2 ;
		RECT 13.5 11.28 13.88 11.66 ;
		LAYER M2 ;
		RECT 9.8 9.8 10.18 10.18 ;
		LAYER M2 ;
		RECT 9.85 8.7 10.13 9.8 ;
		LAYER M2 ;
		RECT 9.8 8.32 10.18 8.7 ;
		LAYER M2 ;
		RECT 9.06 6.1 9.44 6.48 ;
		LAYER M2 ;
		RECT 7.58 4.62 7.96 5 ;
		LAYER M2 ;
		RECT 3.14 3.14 3.52 3.52 ;
		LAYER M2 ;
		RECT 7.58 3.14 7.96 3.52 ;
		LAYER M2 ;
		RECT 7.63 2.78 7.91 3.14 ;
		LAYER M2 ;
		RECT 3.14 2.4 3.52 2.78 ;
		LAYER M2 ;
		RECT 7.58 2.4 7.96 2.78 ;
		LAYER M2 ;
		RECT 3.19 2.04 3.47 2.4 ;
		LAYER M2 ;
		RECT 3.14 1.66 3.52 2.04 ;
		LAYER M2 ;
		RECT 5.36 1.325 5.74 2.04 ;
		LAYER M2 ;
		RECT 9.11 1.48 9.39 6.1 ;
		LAYER M2 ;
		RECT 9.8 4.62 10.18 5 ;
		LAYER M2 ;
		RECT 9.85 4.26 10.13 4.62 ;
		LAYER M2 ;
		RECT 9.8 3.88 10.18 4.26 ;
		LAYER M2 ;
		RECT 13.55 10.18 13.83 11.28 ;
		LAYER M2 ;
		RECT 13.5 9.8 13.88 10.18 ;
		LAYER M2 ;
		RECT 14.29 8.7 14.57 13.5 ;
		LAYER M2 ;
		RECT 14.24 8.32 14.62 8.7 ;
		LAYER M2 ;
		RECT 12.76 3.14 13.14 3.52 ;
		LAYER M2 ;
		RECT 9.85 2.78 10.13 3.035 ;
		LAYER M2 ;
		RECT 9.8 2.4 10.18 2.78 ;
		LAYER M2 ;
		RECT 9.85 2.385 10.13 2.4 ;
		LAYER M2 ;
		RECT 12.81 2.04 13.09 3.14 ;
		LAYER M2 ;
		RECT 9.8 1.66 10.18 2.04 ;
		LAYER M2 ;
		RECT 12.76 1.66 13.14 2.04 ;
		LAYER M2 ;
		RECT 9.06 1.1 9.44 1.48 ;
		LAYER M2 ;
		RECT 9.85 1.34 10.13 1.66 ;
		LAYER VIA2 ;
		RECT 8.38 14.3 8.64 14.56 ;
		LAYER VIA2 ;
		RECT 11.34 14.3 11.6 14.56 ;
		LAYER VIA2 ;
		RECT 1.72 9.86 1.98 10.12 ;
		LAYER VIA2 ;
		RECT 3.2 9.86 3.46 10.12 ;
		LAYER VIA2 ;
		RECT 9.86 9.86 10.12 10.12 ;
		LAYER VIA2 ;
		RECT 13.56 9.86 13.82 10.12 ;
		LAYER VIA2 ;
		RECT 7.64 4.68 7.9 4.94 ;
		LAYER VIA2 ;
		RECT 9.86 4.68 10.12 4.94 ;
		LAYER VIA2 ;
		RECT 7.64 2.46 7.9 2.72 ;
		LAYER VIA2 ;
		RECT 9.86 2.46 10.12 2.72 ;
		LAYER VIA2 ;
		RECT 3.2 1.72 3.46 1.98 ;
		LAYER VIA2 ;
		RECT 5.42 1.72 5.68 1.98 ;
		LAYER VIA2 ;
		RECT 9.86 1.72 10.12 1.98 ;
		LAYER VIA2 ;
		RECT 12.82 1.72 13.08 1.98 ;
		LAYER M3 ;
		RECT 8.32 14.57 8.7 14.62 ;
		LAYER M3 ;
		RECT 11.28 14.57 11.66 14.62 ;
		LAYER M3 ;
		RECT 8.32 14.29 11.66 14.57 ;
		LAYER M3 ;
		RECT 8.32 14.24 8.7 14.29 ;
		LAYER M3 ;
		RECT 11.28 14.24 11.66 14.29 ;
		LAYER M3 ;
		RECT 1.66 10.13 2.04 10.18 ;
		LAYER M3 ;
		RECT 3.14 10.13 3.52 10.18 ;
		LAYER M3 ;
		RECT 1.66 9.85 3.52 10.13 ;
		LAYER M3 ;
		RECT 1.66 9.8 2.04 9.85 ;
		LAYER M3 ;
		RECT 3.14 9.8 3.52 9.85 ;
		LAYER M3 ;
		RECT 9.8 10.13 10.18 10.18 ;
		LAYER M3 ;
		RECT 13.5 10.13 13.88 10.18 ;
		LAYER M3 ;
		RECT 9.8 9.85 13.88 10.13 ;
		LAYER M3 ;
		RECT 9.8 9.8 10.18 9.85 ;
		LAYER M3 ;
		RECT 13.5 9.8 13.88 9.85 ;
		LAYER M3 ;
		RECT 7.58 4.95 7.96 5 ;
		LAYER M3 ;
		RECT 9.8 4.95 10.18 5 ;
		LAYER M3 ;
		RECT 7.58 4.67 10.18 4.95 ;
		LAYER M3 ;
		RECT 7.58 4.62 7.96 4.67 ;
		LAYER M3 ;
		RECT 9.8 4.62 10.18 4.67 ;
		LAYER M3 ;
		RECT 7.58 2.73 7.96 2.78 ;
		LAYER M3 ;
		RECT 9.8 2.73 10.18 2.78 ;
		LAYER M3 ;
		RECT 7.58 2.45 10.18 2.73 ;
		LAYER M3 ;
		RECT 7.58 2.4 7.96 2.45 ;
		LAYER M3 ;
		RECT 9.8 2.4 10.18 2.45 ;
		LAYER M3 ;
		RECT 3.14 1.99 3.52 2.04 ;
		LAYER M3 ;
		RECT 5.36 1.99 5.74 2.04 ;
		LAYER M3 ;
		RECT 3.14 1.71 5.74 1.99 ;
		LAYER M3 ;
		RECT 3.14 1.66 3.52 1.71 ;
		LAYER M3 ;
		RECT 5.36 1.66 5.74 1.71 ;
		LAYER M3 ;
		RECT 9.8 1.99 10.18 2.04 ;
		LAYER M3 ;
		RECT 12.76 1.99 13.14 2.04 ;
		LAYER M3 ;
		RECT 9.8 1.71 13.14 1.99 ;
		LAYER M3 ;
		RECT 9.8 1.66 10.18 1.71 ;
		LAYER M3 ;
		RECT 12.76 1.66 13.14 1.71 ;
	END
END MMI_42ADD
MACRO MMI_AND2B
	CLASS CORE ;
	FOREIGN MMI_AND2B 0 0 ;
	SIZE 2.96 BY 7.4 ;
	SYMMETRY X Y ;
	SITE CORE1 ;
	PIN out
		DIRECTION output ;
		USE SIGNAL ;
		PORT
			LAYER M1 ;
			RECT 2.38 4.465 2.72 6.225 ;
			LAYER M1 ;
			RECT 2.38 3.555 2.61 4.465 ;
			LAYER M1 ;
			RECT 2.16 3.105 2.815 3.555 ;
			LAYER M1 ;
			RECT 2.16 1.85 2.39 3.105 ;
			LAYER M1 ;
			RECT 2.05 1.01 2.39 1.85 ;
		END
		AntennaDiffArea 1.3248 ;
	END out
	PIN in1
		DIRECTION input ;
		USE SIGNAL ;
		PORT
			LAYER M1 ;
			RECT 0.885 3.5 1.335 3.555 ;
			LAYER M1 ;
			RECT 0.885 3.445 1.48 3.5 ;
			LAYER M1 ;
			RECT 0.885 3.215 1.545 3.445 ;
			LAYER M1 ;
			RECT 0.885 3.16 1.48 3.215 ;
			LAYER M1 ;
			RECT 0.885 3.105 1.335 3.16 ;
		END
		AntennaGateArea 0.3312 ;
	END in1
	PIN GND
		DIRECTION inout ;
		USE GROUND ;
		PORT
			LAYER M1 ;
			RECT 1.33 0.5 1.67 1.85 ;
			LAYER M1 ;
			RECT 0 -0.5 2.96 0.5 ;
		END
	END GND
	PIN VDD
		DIRECTION inout ;
		USE POWER ;
		PORT
			LAYER M1 ;
			RECT 0 6.9 2.96 7.9 ;
			LAYER M1 ;
			RECT 0.18 4.465 0.52 6.9 ;
			LAYER M1 ;
			RECT 1.66 4.465 2 6.9 ;
		END
	END VDD
	PIN in0
		DIRECTION input ;
		USE SIGNAL ;
		PORT
			LAYER M1 ;
			RECT 0.885 2.81 1.335 2.815 ;
			LAYER M1 ;
			RECT 0.64 2.47 1.335 2.81 ;
			LAYER M1 ;
			RECT 0.885 2.365 1.335 2.47 ;
		END
		AntennaGateArea 0.3312 ;
	END in0
	OBS
		LAYER M1 ;
		RECT 0.9 4.465 1.24 5.305 ;
		LAYER M1 ;
		RECT 0.9 4.135 1.13 4.465 ;
		LAYER M1 ;
		RECT 1.81 4.135 2.15 4.19 ;
		LAYER M1 ;
		RECT 0.18 3.905 2.15 4.135 ;
		LAYER M1 ;
		RECT 0.18 1.85 0.41 3.905 ;
		LAYER M1 ;
		RECT 1.81 3.85 2.15 3.905 ;
		LAYER M1 ;
		RECT 0.18 1.01 0.52 1.85 ;
	END
END MMI_AND2B
MACRO MMI_AND2C
	CLASS CORE ;
	FOREIGN MMI_AND2C 0 0 ;
	SIZE 3.7 BY 7.4 ;
	SYMMETRY X Y ;
	SITE CORE1 ;
	PIN out
		DIRECTION output ;
		USE SIGNAL ;
		PORT
			LAYER M1 ;
			RECT 2.38 4.555 2.72 6.315 ;
			LAYER M1 ;
			RECT 2.38 3.555 2.61 4.555 ;
			LAYER M1 ;
			RECT 2.38 3.105 2.815 3.555 ;
			LAYER M1 ;
			RECT 2.38 2.905 2.61 3.105 ;
			LAYER M1 ;
			RECT 2.27 1.145 2.61 2.905 ;
		END
		AntennaDiffArea 1.8768 ;
	END out
	PIN in1
		DIRECTION input ;
		USE SIGNAL ;
		PORT
			LAYER M1 ;
			RECT 1.625 4.19 2.075 4.295 ;
			LAYER M1 ;
			RECT 1.36 3.85 2.075 4.19 ;
			LAYER M1 ;
			RECT 1.625 3.845 2.075 3.85 ;
		END
		AntennaGateArea 0.4464 ;
	END in1
	PIN GND
		DIRECTION inout ;
		USE GROUND ;
		PORT
			LAYER M1 ;
			RECT 1.55 0.5 1.89 2.905 ;
			LAYER M1 ;
			RECT 0 -0.5 3.7 0.5 ;
		END
	END GND
	PIN VDD
		DIRECTION inout ;
		USE POWER ;
		PORT
			LAYER M1 ;
			RECT 0 6.9 3.7 7.9 ;
			LAYER M1 ;
			RECT 0.18 4.555 0.52 6.9 ;
			LAYER M1 ;
			RECT 1.66 4.555 2 6.9 ;
			LAYER M1 ;
			RECT 3.1 4.555 3.44 6.9 ;
		END
	END VDD
	PIN in0
		DIRECTION input ;
		USE SIGNAL ;
		PORT
			LAYER M1 ;
			RECT 0.145 4.19 0.595 4.295 ;
			LAYER M1 ;
			RECT 0.12 3.85 0.595 4.19 ;
			LAYER M1 ;
			RECT 0.145 3.845 0.595 3.85 ;
		END
		AntennaGateArea 0.4464 ;
	END in0
	OBS
		LAYER M1 ;
		RECT 0.9 4.555 1.24 5.715 ;
		LAYER M1 ;
		RECT 0.9 3.445 1.13 4.555 ;
		LAYER M1 ;
		RECT 1.7 3.445 2.04 3.5 ;
		LAYER M1 ;
		RECT 0.47 3.215 2.04 3.445 ;
		LAYER M1 ;
		RECT 0.47 2.905 0.7 3.215 ;
		LAYER M1 ;
		RECT 1.7 3.16 2.04 3.215 ;
		LAYER M1 ;
		RECT 0.36 1.745 0.7 2.905 ;
	END
END MMI_AND2C
MACRO MMI_AND3B
	CLASS CORE ;
	FOREIGN MMI_AND3B 0 0 ;
	SIZE 3.7 BY 7.4 ;
	SYMMETRY X Y ;
	SITE CORE1 ;
	PIN out
		DIRECTION output ;
		USE SIGNAL ;
		PORT
			LAYER M1 ;
			RECT 3.1 4.82 3.44 6.58 ;
			LAYER M1 ;
			RECT 3.1 3.555 3.33 4.82 ;
			LAYER M1 ;
			RECT 3.1 3.335 3.555 3.555 ;
			LAYER M1 ;
			RECT 2.63 3.105 3.555 3.335 ;
			LAYER M1 ;
			RECT 2.63 2.92 2.86 3.105 ;
			LAYER M1 ;
			RECT 2.52 2.08 2.86 2.92 ;
		END
		AntennaDiffArea 1.3248 ;
	END out
	PIN in1
		DIRECTION input ;
		USE SIGNAL ;
		PORT
			LAYER M1 ;
			RECT 0.885 4.19 1.335 4.295 ;
			LAYER M1 ;
			RECT 0.85 3.85 1.335 4.19 ;
			LAYER M1 ;
			RECT 0.885 3.845 1.335 3.85 ;
		END
		AntennaGateArea 0.414 ;
	END in1
	PIN GND
		DIRECTION inout ;
		USE GROUND ;
		PORT
			LAYER M1 ;
			RECT 1.76 0.5 2.1 2.92 ;
			LAYER M1 ;
			RECT 0 -0.5 3.7 0.5 ;
		END
	END GND
	PIN in2
		DIRECTION input ;
		USE SIGNAL ;
		PORT
			LAYER M1 ;
			RECT 2.365 4.19 2.815 4.295 ;
			LAYER M1 ;
			RECT 2.19 3.85 2.815 4.19 ;
			LAYER M1 ;
			RECT 2.365 3.845 2.815 3.85 ;
		END
		AntennaGateArea 0.414 ;
	END in2
	PIN VDD
		DIRECTION inout ;
		USE POWER ;
		PORT
			LAYER M1 ;
			RECT 0 6.9 3.7 7.9 ;
			LAYER M1 ;
			RECT 0.9 5.32 1.24 6.9 ;
			LAYER M1 ;
			RECT 2.38 4.82 2.72 6.9 ;
		END
	END VDD
	PIN in0
		DIRECTION input ;
		USE SIGNAL ;
		PORT
			LAYER M1 ;
			RECT 0.145 4.19 0.595 4.295 ;
			LAYER M1 ;
			RECT 0.12 3.85 0.595 4.19 ;
			LAYER M1 ;
			RECT 0.145 3.845 0.595 3.85 ;
		END
		AntennaGateArea 0.414 ;
	END in0
	OBS
		LAYER M1 ;
		RECT 0.18 5.05 0.52 5.66 ;
		LAYER M1 ;
		RECT 1.62 5.05 1.96 5.66 ;
		LAYER M1 ;
		RECT 0.18 4.82 1.96 5.05 ;
		LAYER M1 ;
		RECT 1.73 3.5 1.96 4.82 ;
		LAYER M1 ;
		RECT 1.73 3.445 2.29 3.5 ;
		LAYER M1 ;
		RECT 0.29 3.215 2.29 3.445 ;
		LAYER M1 ;
		RECT 0.29 2.92 0.52 3.215 ;
		LAYER M1 ;
		RECT 1.95 3.16 2.29 3.215 ;
		LAYER M1 ;
		RECT 0.18 1.62 0.52 2.92 ;
	END
END MMI_AND3B
MACRO MMI_AND3C
	CLASS CORE ;
	FOREIGN MMI_AND3C 0 0 ;
	SIZE 4.44 BY 7.4 ;
	SYMMETRY X Y ;
	SITE CORE1 ;
	PIN out
		DIRECTION output ;
		USE SIGNAL ;
		PORT
			LAYER M1 ;
			RECT 3.1 4.855 3.44 6.615 ;
			LAYER M1 ;
			RECT 3.1 3.555 3.33 4.855 ;
			LAYER M1 ;
			RECT 3.1 3.495 3.555 3.555 ;
			LAYER M1 ;
			RECT 2.92 3.105 3.555 3.495 ;
			LAYER M1 ;
			RECT 2.92 2.92 3.15 3.105 ;
			LAYER M1 ;
			RECT 2.81 1.16 3.15 2.92 ;
		END
		AntennaDiffArea 1.8768 ;
	END out
	PIN in1
		DIRECTION input ;
		USE SIGNAL ;
		PORT
			LAYER M1 ;
			RECT 0.885 3.845 1.335 4.295 ;
		END
		AntennaGateArea 0.558 ;
	END in1
	PIN GND
		DIRECTION inout ;
		USE GROUND ;
		PORT
			LAYER M1 ;
			RECT 2.05 0.5 2.39 2.92 ;
			LAYER M1 ;
			RECT 0 -0.5 4.44 0.5 ;
		END
	END GND
	PIN in2
		DIRECTION input ;
		USE SIGNAL ;
		PORT
			LAYER M1 ;
			RECT 2.365 4.24 2.815 4.295 ;
			LAYER M1 ;
			RECT 2.19 3.9 2.815 4.24 ;
			LAYER M1 ;
			RECT 2.365 3.845 2.815 3.9 ;
		END
		AntennaGateArea 0.558 ;
	END in2
	PIN VDD
		DIRECTION inout ;
		USE POWER ;
		PORT
			LAYER M1 ;
			RECT 0 6.9 4.44 7.9 ;
			LAYER M1 ;
			RECT 0.9 5.675 1.24 6.9 ;
			LAYER M1 ;
			RECT 2.38 4.855 2.72 6.9 ;
			LAYER M1 ;
			RECT 3.82 4.855 4.16 6.9 ;
		END
	END VDD
	PIN in0
		DIRECTION input ;
		USE SIGNAL ;
		PORT
			LAYER M1 ;
			RECT 0.145 4.24 0.595 4.295 ;
			LAYER M1 ;
			RECT 0.12 3.9 0.595 4.24 ;
			LAYER M1 ;
			RECT 0.145 3.845 0.595 3.9 ;
		END
		AntennaGateArea 0.558 ;
	END in0
	OBS
		LAYER M1 ;
		RECT 0.18 5.085 0.52 6.015 ;
		LAYER M1 ;
		RECT 1.62 5.085 1.96 6.015 ;
		LAYER M1 ;
		RECT 0.18 4.855 1.96 5.085 ;
		LAYER M1 ;
		RECT 1.73 3.495 1.96 4.855 ;
		LAYER M1 ;
		RECT 2.325 3.495 2.665 3.55 ;
		LAYER M1 ;
		RECT 0.58 3.265 2.665 3.495 ;
		LAYER M1 ;
		RECT 0.58 2.92 0.81 3.265 ;
		LAYER M1 ;
		RECT 2.325 3.21 2.665 3.265 ;
		LAYER M1 ;
		RECT 0.47 1.14 0.81 2.92 ;
	END
END MMI_AND3C
MACRO MMI_AND4B
	CLASS CORE ;
	FOREIGN MMI_AND4B 0 0 ;
	SIZE 4.44 BY 7.4 ;
	SYMMETRY X Y ;
	SITE CORE1 ;
	PIN out
		DIRECTION output ;
		USE SIGNAL ;
		PORT
			LAYER M1 ;
			RECT 3.82 4.81 4.16 6.57 ;
			LAYER M1 ;
			RECT 3.89 3.555 4.12 4.81 ;
			LAYER M1 ;
			RECT 3.845 3.105 4.295 3.555 ;
			LAYER M1 ;
			RECT 3.89 2.865 4.12 3.105 ;
			LAYER M1 ;
			RECT 3.78 2.025 4.12 2.865 ;
		END
		AntennaDiffArea 1.3248 ;
	END out
	PIN in1
		DIRECTION input ;
		USE SIGNAL ;
		PORT
			LAYER M1 ;
			RECT 0.885 4.19 1.335 4.295 ;
			LAYER M1 ;
			RECT 0.85 3.85 1.335 4.19 ;
			LAYER M1 ;
			RECT 0.885 3.845 1.335 3.85 ;
		END
		AntennaGateArea 0.4968 ;
	END in1
	PIN GND
		DIRECTION inout ;
		USE GROUND ;
		PORT
			LAYER M1 ;
			RECT 2.19 0.5 2.53 3.11 ;
			LAYER M1 ;
			RECT 3.06 0.5 3.4 2.865 ;
			LAYER M1 ;
			RECT 0 -0.5 4.44 0.5 ;
		END
	END GND
	PIN in2
		DIRECTION input ;
		USE SIGNAL ;
		PORT
			LAYER M1 ;
			RECT 1.625 4.19 2.075 4.295 ;
			LAYER M1 ;
			RECT 1.57 3.85 2.075 4.19 ;
			LAYER M1 ;
			RECT 1.625 3.845 2.075 3.85 ;
		END
		AntennaGateArea 0.4968 ;
	END in2
	PIN VDD
		DIRECTION inout ;
		USE POWER ;
		PORT
			LAYER M1 ;
			RECT 0 6.9 4.44 7.9 ;
			LAYER M1 ;
			RECT 0.18 4.81 0.52 6.9 ;
			LAYER M1 ;
			RECT 1.62 5.31 1.96 6.9 ;
			LAYER M1 ;
			RECT 3.1 4.81 3.44 6.9 ;
		END
	END VDD
	PIN in3
		DIRECTION input ;
		USE SIGNAL ;
		PORT
			LAYER M1 ;
			RECT 3.105 3.5 3.555 3.555 ;
			LAYER M1 ;
			RECT 2.765 3.16 3.555 3.5 ;
			LAYER M1 ;
			RECT 3.105 3.105 3.555 3.16 ;
		END
		AntennaGateArea 0.4968 ;
	END in3
	PIN in0
		DIRECTION input ;
		USE SIGNAL ;
		PORT
			LAYER M1 ;
			RECT 0.145 4.19 0.595 4.295 ;
			LAYER M1 ;
			RECT 0.12 3.85 0.595 4.19 ;
			LAYER M1 ;
			RECT 0.145 3.845 0.595 3.85 ;
		END
		AntennaGateArea 0.4968 ;
	END in0
	OBS
		LAYER M1 ;
		RECT 0.9 5.04 1.24 5.65 ;
		LAYER M1 ;
		RECT 2.34 5.04 2.68 5.65 ;
		LAYER M1 ;
		RECT 0.9 4.81 2.68 5.04 ;
		LAYER M1 ;
		RECT 2.305 4.135 2.535 4.81 ;
		LAYER M1 ;
		RECT 3.25 4.135 3.59 4.19 ;
		LAYER M1 ;
		RECT 2.305 3.905 3.59 4.135 ;
		LAYER M1 ;
		RECT 2.305 3.595 2.535 3.905 ;
		LAYER M1 ;
		RECT 3.25 3.85 3.59 3.905 ;
		LAYER M1 ;
		RECT 0.29 3.365 2.535 3.595 ;
		LAYER M1 ;
		RECT 0.29 3.11 0.52 3.365 ;
		LAYER M1 ;
		RECT 0.18 1.35 0.52 3.11 ;
	END
END MMI_AND4B
MACRO MMI_AND4C
	CLASS CORE ;
	FOREIGN MMI_AND4C 0 0 ;
	SIZE 5.92 BY 7.4 ;
	SYMMETRY X Y ;
	SITE CORE1 ;
	PIN out
		DIRECTION output ;
		USE SIGNAL ;
		PORT
			LAYER M1 ;
			RECT 3.82 4.91 4.16 6.67 ;
			LAYER M1 ;
			RECT 3.93 4.675 4.16 4.91 ;
			LAYER M1 ;
			RECT 3.93 4.445 5 4.675 ;
			LAYER M1 ;
			RECT 4.61 3.885 5 4.445 ;
			LAYER M1 ;
			RECT 4.695 3.56 4.925 3.885 ;
			LAYER M1 ;
			RECT 4.695 3.33 5.19 3.56 ;
			LAYER M1 ;
			RECT 4.96 2.79 5.19 3.33 ;
			LAYER M1 ;
			RECT 4.96 1.03 5.3 2.79 ;
		END
		AntennaDiffArea 1.8768 ;
	END out
	PIN in1
		DIRECTION input ;
		USE SIGNAL ;
		PORT
			LAYER M1 ;
			RECT 1.86 4.87 2.2 4.965 ;
			LAYER M1 ;
			RECT 1.735 4.625 2.2 4.87 ;
			LAYER M1 ;
			RECT 1.735 3.195 1.965 4.625 ;
			LAYER M1 ;
			RECT 1.585 2.855 1.965 3.195 ;
			LAYER M1 ;
			RECT 1.735 2.805 1.965 2.855 ;
		END
		AntennaGateArea 0.6696 ;
	END in1
	PIN GND
		DIRECTION inout ;
		USE GROUND ;
		PORT
			LAYER M1 ;
			RECT 0.18 0.5 0.52 2.19 ;
			LAYER M1 ;
			RECT 4.24 0.5 4.58 2.79 ;
			LAYER M1 ;
			RECT 0 -0.5 5.92 0.5 ;
		END
	END GND
	PIN in2
		DIRECTION input ;
		USE SIGNAL ;
		PORT
			LAYER M1 ;
			RECT 0.885 3.955 1.39 4.295 ;
			LAYER M1 ;
			RECT 0.885 3.845 1.335 3.955 ;
		END
		AntennaGateArea 0.6696 ;
	END in2
	PIN VDD
		DIRECTION inout ;
		USE POWER ;
		PORT
			LAYER M1 ;
			RECT 0 6.9 5.92 7.9 ;
			LAYER M1 ;
			RECT 0.18 5.205 0.52 6.9 ;
			LAYER M1 ;
			RECT 1.62 6.025 1.96 6.9 ;
			LAYER M1 ;
			RECT 3.1 5.39 3.44 6.9 ;
			LAYER M1 ;
			RECT 4.54 4.91 4.88 6.9 ;
		END
	END VDD
	PIN in3
		DIRECTION input ;
		USE SIGNAL ;
		PORT
			LAYER M1 ;
			RECT 0.42 4.885 0.76 4.975 ;
			LAYER M1 ;
			RECT 0.255 4.635 0.76 4.885 ;
			LAYER M1 ;
			RECT 0.255 2.76 0.485 4.635 ;
			LAYER M1 ;
			RECT 0.255 2.475 0.76 2.76 ;
			LAYER M1 ;
			RECT 0.42 2.42 0.76 2.475 ;
		END
		AntennaGateArea 0.6696 ;
	END in3
	PIN in0
		DIRECTION input ;
		USE SIGNAL ;
		PORT
			LAYER M1 ;
			RECT 2.435 3.955 2.775 4.295 ;
			LAYER M1 ;
			RECT 2.475 2.765 2.705 3.955 ;
			LAYER M1 ;
			RECT 2.365 2.425 2.705 2.765 ;
		END
		AntennaGateArea 0.6696 ;
	END in0
	OBS
		LAYER M1 ;
		RECT 0.9 5.435 1.24 6.365 ;
		LAYER M1 ;
		RECT 2.34 5.435 2.68 6.365 ;
		LAYER M1 ;
		RECT 0.9 5.205 2.68 5.435 ;
		LAYER M1 ;
		RECT 2.45 4.845 2.68 5.205 ;
		LAYER M1 ;
		RECT 2.45 4.615 3.57 4.845 ;
		LAYER M1 ;
		RECT 3.34 3.745 3.57 4.615 ;
		LAYER M1 ;
		RECT 3.97 3.745 4.31 3.8 ;
		LAYER M1 ;
		RECT 3.34 3.515 4.31 3.745 ;
		LAYER M1 ;
		RECT 3.34 2.19 3.57 3.515 ;
		LAYER M1 ;
		RECT 3.97 3.46 4.31 3.515 ;
		LAYER M1 ;
		RECT 2.19 1.96 3.57 2.19 ;
		LAYER M1 ;
		RECT 2.19 1.03 2.53 1.96 ;
	END
END MMI_AND4C
MACRO MMI_AO21B
	CLASS CORE ;
	FOREIGN MMI_AO21B 0 0 ;
	SIZE 4.44 BY 7.4 ;
	SYMMETRY X Y ;
	SITE CORE1 ;
	PIN out
		DIRECTION output ;
		USE SIGNAL ;
		PORT
			LAYER M1 ;
			RECT 3.76 4.225 4.1 5.985 ;
			LAYER M1 ;
			RECT 3.87 2.815 4.1 4.225 ;
			LAYER M1 ;
			RECT 3.845 2.54 4.295 2.815 ;
			LAYER M1 ;
			RECT 3.76 2.365 4.295 2.54 ;
			LAYER M1 ;
			RECT 3.76 1.435 4.1 2.365 ;
		END
		AntennaDiffArea 1.3248 ;
	END out
	PIN in1
		DIRECTION input ;
		USE SIGNAL ;
		PORT
			LAYER M1 ;
			RECT 0.885 4.19 1.335 4.295 ;
			LAYER M1 ;
			RECT 0.885 4.135 1.52 4.19 ;
			LAYER M1 ;
			RECT 0.885 3.905 1.585 4.135 ;
			LAYER M1 ;
			RECT 0.885 3.85 1.52 3.905 ;
			LAYER M1 ;
			RECT 0.885 3.845 1.335 3.85 ;
		END
		AntennaGateArea 0.4968 ;
	END in1
	PIN GND
		DIRECTION inout ;
		USE GROUND ;
		PORT
			LAYER M1 ;
			RECT 0.18 0.5 0.52 2.275 ;
			LAYER M1 ;
			RECT 2.09 0.5 2.43 2.275 ;
			LAYER M1 ;
			RECT 3.04 0.5 3.38 2.275 ;
			LAYER M1 ;
			RECT 0 -0.5 4.44 0.5 ;
		END
	END GND
	PIN in2
		DIRECTION input ;
		USE SIGNAL ;
		PORT
			LAYER M1 ;
			RECT 1.625 3.5 2.075 3.555 ;
			LAYER M1 ;
			RECT 1.625 3.16 2.2 3.5 ;
			LAYER M1 ;
			RECT 1.625 3.105 2.075 3.16 ;
		END
		AntennaGateArea 0.4968 ;
	END in2
	PIN VDD
		DIRECTION inout ;
		USE POWER ;
		PORT
			LAYER M1 ;
			RECT 0 6.9 4.44 7.9 ;
			LAYER M1 ;
			RECT 1.62 5.03 1.96 6.9 ;
			LAYER M1 ;
			RECT 3.04 4.225 3.38 6.9 ;
		END
	END VDD
	PIN in0
		DIRECTION input ;
		USE SIGNAL ;
		PORT
			LAYER M1 ;
			RECT 0.885 3.5 1.335 3.555 ;
			LAYER M1 ;
			RECT 0.64 3.16 1.335 3.5 ;
			LAYER M1 ;
			RECT 0.885 3.105 1.335 3.16 ;
		END
		AntennaGateArea 0.414 ;
	END in0
	OBS
		LAYER M1 ;
		RECT 0.18 4.55 0.52 6.31 ;
		LAYER M1 ;
		RECT 0.9 4.78 1.24 6.31 ;
		LAYER M1 ;
		RECT 2.34 4.78 2.68 6.31 ;
		LAYER M1 ;
		RECT 0.9 4.55 2.68 4.78 ;
		LAYER M1 ;
		RECT 0.18 2.755 0.41 4.55 ;
		LAYER M1 ;
		RECT 3.195 3.445 3.535 3.5 ;
		LAYER M1 ;
		RECT 2.475 3.215 3.535 3.445 ;
		LAYER M1 ;
		RECT 2.475 2.755 2.705 3.215 ;
		LAYER M1 ;
		RECT 3.195 3.16 3.535 3.215 ;
		LAYER M1 ;
		RECT 0.18 2.525 2.705 2.755 ;
		LAYER M1 ;
		RECT 0.94 2.275 1.17 2.525 ;
		LAYER M1 ;
		RECT 0.94 1.435 1.28 2.275 ;
	END
END MMI_AO21B
MACRO MMI_AO21C
	CLASS CORE ;
	FOREIGN MMI_AO21C 0 0 ;
	SIZE 5.18 BY 7.4 ;
	SYMMETRY X Y ;
	SITE CORE1 ;
	PIN out
		DIRECTION output ;
		USE SIGNAL ;
		PORT
			LAYER M1 ;
			RECT 3.76 4.27 4.1 6.03 ;
			LAYER M1 ;
			RECT 3.85 3.865 4.08 4.27 ;
			LAYER M1 ;
			RECT 3.85 3.48 4.195 3.865 ;
			LAYER M1 ;
			RECT 3.965 2.76 4.195 3.48 ;
			LAYER M1 ;
			RECT 3.62 2.53 4.195 2.76 ;
			LAYER M1 ;
			RECT 3.62 2.29 3.85 2.53 ;
			LAYER M1 ;
			RECT 3.51 1.45 3.85 2.29 ;
		END
		AntennaDiffArea 1.4904 ;
	END out
	PIN in1
		DIRECTION input ;
		USE SIGNAL ;
		PORT
			LAYER M1 ;
			RECT 2.365 3.5 2.815 3.555 ;
			LAYER M1 ;
			RECT 2.305 3.16 2.815 3.5 ;
			LAYER M1 ;
			RECT 2.365 3.105 2.815 3.16 ;
		END
		AntennaGateArea 0.6696 ;
	END in1
	PIN GND
		DIRECTION inout ;
		USE GROUND ;
		PORT
			LAYER M1 ;
			RECT 0.94 0.5 1.28 2.29 ;
			LAYER M1 ;
			RECT 2.79 0.5 3.13 2.29 ;
			LAYER M1 ;
			RECT 4.23 0.5 4.57 2.29 ;
			LAYER M1 ;
			RECT 0 -0.5 5.18 0.5 ;
		END
	END GND
	PIN in2
		DIRECTION input ;
		USE SIGNAL ;
		PORT
			LAYER M1 ;
			RECT 1.625 3.5 2.075 3.555 ;
			LAYER M1 ;
			RECT 1.565 3.16 2.075 3.5 ;
			LAYER M1 ;
			RECT 1.625 3.105 2.075 3.16 ;
		END
		AntennaGateArea 0.6696 ;
	END in2
	PIN VDD
		DIRECTION inout ;
		USE POWER ;
		PORT
			LAYER M1 ;
			RECT 0 6.9 5.18 7.9 ;
			LAYER M1 ;
			RECT 1.62 4.92 1.96 6.9 ;
			LAYER M1 ;
			RECT 3.04 4.27 3.38 6.9 ;
			LAYER M1 ;
			RECT 4.48 4.27 4.82 6.9 ;
		END
	END VDD
	PIN in0
		DIRECTION input ;
		USE SIGNAL ;
		PORT
			LAYER M1 ;
			RECT 0.885 3.5 1.335 3.555 ;
			LAYER M1 ;
			RECT 0.64 3.16 1.335 3.5 ;
			LAYER M1 ;
			RECT 0.885 3.105 1.335 3.16 ;
		END
		AntennaGateArea 0.558 ;
	END in0
	OBS
		LAYER M1 ;
		RECT 0.18 4.27 0.52 6.67 ;
		LAYER M1 ;
		RECT 0.9 4.5 1.24 6.67 ;
		LAYER M1 ;
		RECT 2.34 4.5 2.68 6.67 ;
		LAYER M1 ;
		RECT 0.9 4.27 2.68 4.5 ;
		LAYER M1 ;
		RECT 0.18 2.755 0.41 4.27 ;
		LAYER M1 ;
		RECT 3.28 3.395 3.62 3.4 ;
		LAYER M1 ;
		RECT 3.125 3.06 3.62 3.395 ;
		LAYER M1 ;
		RECT 3.125 2.755 3.355 3.06 ;
		LAYER M1 ;
		RECT 0.18 2.525 3.355 2.755 ;
		LAYER M1 ;
		RECT 0.18 2.29 0.41 2.525 ;
		LAYER M1 ;
		RECT 2.09 2.29 2.32 2.525 ;
		LAYER M1 ;
		RECT 0.18 1.75 0.52 2.29 ;
		LAYER M1 ;
		RECT 2.09 1.13 2.43 2.29 ;
	END
END MMI_AO21C
MACRO MMI_AO22B
	CLASS CORE ;
	FOREIGN MMI_AO22B 0 0 ;
	SIZE 4.44 BY 7.4 ;
	SYMMETRY X Y ;
	SITE CORE1 ;
	PIN out
		DIRECTION output ;
		USE SIGNAL ;
		PORT
			LAYER M1 ;
			RECT 3.78 4.785 4.12 5.96 ;
			LAYER M1 ;
			RECT 3.78 4.2 4.24 4.785 ;
			LAYER M1 ;
			RECT 4.01 2.96 4.24 4.2 ;
			LAYER M1 ;
			RECT 3.87 2.22 4.24 2.96 ;
			LAYER M1 ;
			RECT 4.01 1.655 4.24 2.22 ;
			LAYER M1 ;
			RECT 3.78 1.115 4.24 1.655 ;
			LAYER M1 ;
			RECT 3.78 0.815 4.12 1.115 ;
		END
		AntennaDiffArea 1.3248 ;
	END out
	PIN in1
		DIRECTION input ;
		USE SIGNAL ;
		PORT
			LAYER M1 ;
			RECT 0.145 2.81 0.595 2.815 ;
			LAYER M1 ;
			RECT 0.145 2.47 0.76 2.81 ;
			LAYER M1 ;
			RECT 0.145 2.365 0.595 2.47 ;
		END
		AntennaGateArea 0.4968 ;
	END in1
	PIN GND
		DIRECTION inout ;
		USE GROUND ;
		PORT
			LAYER M1 ;
			RECT 0.75 0.5 1.09 1.655 ;
			LAYER M1 ;
			RECT 3.06 0.5 3.4 1.155 ;
			LAYER M1 ;
			RECT 0 -0.5 4.44 0.5 ;
		END
	END GND
	PIN in2
		DIRECTION input ;
		USE SIGNAL ;
		PORT
			LAYER M1 ;
			RECT 0.42 3.63 0.76 3.97 ;
			LAYER M1 ;
			RECT 0.19 3.34 0.76 3.63 ;
			LAYER M1 ;
			RECT 0.19 3.11 2.35 3.34 ;
			LAYER M1 ;
			RECT 2.12 2.365 2.35 3.11 ;
			LAYER M1 ;
			RECT 2.09 2.025 2.43 2.365 ;
		END
		AntennaGateArea 0.4968 ;
	END in2
	PIN VDD
		DIRECTION inout ;
		USE POWER ;
		PORT
			LAYER M1 ;
			RECT 0 6.9 4.44 7.9 ;
			LAYER M1 ;
			RECT 0.18 4.2 0.52 6.9 ;
			LAYER M1 ;
			RECT 3.06 4.2 3.4 6.9 ;
		END
	END VDD
	PIN in3
		DIRECTION input ;
		USE SIGNAL ;
		PORT
			LAYER M1 ;
			RECT 3.13 2.2 3.555 2.815 ;
		END
		AntennaGateArea 0.4968 ;
	END in3
	PIN in0
		DIRECTION input ;
		USE SIGNAL ;
		PORT
			LAYER M1 ;
			RECT 0.99 2.365 1.585 2.815 ;
		END
		AntennaGateArea 0.4968 ;
	END in0
	OBS
		LAYER M1 ;
		RECT 0.9 5.73 2.68 5.96 ;
		LAYER M1 ;
		RECT 0.9 4.2 1.24 5.73 ;
		LAYER M1 ;
		RECT 1.62 4.2 1.96 5.48 ;
		LAYER M1 ;
		RECT 2.34 4.68 2.68 5.73 ;
		LAYER M1 ;
		RECT 1.715 3.8 1.945 4.2 ;
		LAYER M1 ;
		RECT 3.42 3.8 3.76 3.805 ;
		LAYER M1 ;
		RECT 1.715 3.57 3.76 3.8 ;
		LAYER M1 ;
		RECT 2.66 1.655 2.89 3.57 ;
		LAYER M1 ;
		RECT 3.42 3.465 3.76 3.57 ;
		LAYER M1 ;
		RECT 1.91 1.425 2.89 1.655 ;
		LAYER M1 ;
		RECT 1.91 0.815 2.25 1.425 ;
	END
END MMI_AO22B
MACRO MMI_AO22C
	CLASS CORE ;
	FOREIGN MMI_AO22C 0 0 ;
	SIZE 5.92 BY 7.4 ;
	SYMMETRY X Y ;
	SITE CORE1 ;
	PIN out
		DIRECTION output ;
		USE SIGNAL ;
		PORT
			LAYER M1 ;
			RECT 4.48 4.19 4.82 5.95 ;
			LAYER M1 ;
			RECT 4.51 3.735 4.74 4.19 ;
			LAYER M1 ;
			RECT 4.51 3.555 4.755 3.735 ;
			LAYER M1 ;
			RECT 4.51 3.105 5.035 3.555 ;
			LAYER M1 ;
			RECT 4.51 2.85 4.755 3.105 ;
			LAYER M1 ;
			RECT 4.51 2.285 4.74 2.85 ;
			LAYER M1 ;
			RECT 4.4 1.445 4.74 2.285 ;
		END
		AntennaDiffArea 1.4904 ;
	END out
	PIN in1
		DIRECTION input ;
		USE SIGNAL ;
		PORT
			LAYER M1 ;
			RECT 0.145 3.5 0.595 3.555 ;
			LAYER M1 ;
			RECT 0.12 3.16 0.595 3.5 ;
			LAYER M1 ;
			RECT 0.145 3.105 0.595 3.16 ;
		END
		AntennaGateArea 0.6696 ;
	END in1
	PIN GND
		DIRECTION inout ;
		USE GROUND ;
		PORT
			LAYER M1 ;
			RECT 0.47 0.5 0.81 2.4 ;
			LAYER M1 ;
			RECT 2.77 0.5 3.11 2.4 ;
			LAYER M1 ;
			RECT 3.68 0.5 4.02 2.285 ;
			LAYER M1 ;
			RECT 5.12 0.5 5.46 2.285 ;
			LAYER M1 ;
			RECT 0 -0.5 5.92 0.5 ;
		END
	END GND
	PIN in2
		DIRECTION input ;
		USE SIGNAL ;
		PORT
			LAYER M1 ;
			RECT 2.365 3.5 2.815 3.555 ;
			LAYER M1 ;
			RECT 2.305 3.16 2.815 3.5 ;
			LAYER M1 ;
			RECT 2.365 3.105 2.815 3.16 ;
		END
		AntennaGateArea 0.6696 ;
	END in2
	PIN VDD
		DIRECTION inout ;
		USE POWER ;
		PORT
			LAYER M1 ;
			RECT 0 6.9 5.92 7.9 ;
			LAYER M1 ;
			RECT 2.34 4.84 2.68 6.9 ;
			LAYER M1 ;
			RECT 3.76 4.19 4.1 6.9 ;
			LAYER M1 ;
			RECT 5.2 4.19 5.54 6.9 ;
		END
	END VDD
	PIN in3
		DIRECTION input ;
		USE SIGNAL ;
		PORT
			LAYER M1 ;
			RECT 3.105 3.505 3.555 3.555 ;
			LAYER M1 ;
			RECT 3.065 3.165 3.555 3.505 ;
			LAYER M1 ;
			RECT 3.105 3.105 3.555 3.165 ;
		END
		AntennaGateArea 0.6696 ;
	END in3
	PIN in0
		DIRECTION input ;
		USE SIGNAL ;
		PORT
			LAYER M1 ;
			RECT 1.625 3.5 2.075 3.555 ;
			LAYER M1 ;
			RECT 1.36 3.16 2.075 3.5 ;
			LAYER M1 ;
			RECT 1.625 3.105 2.075 3.16 ;
		END
		AntennaGateArea 0.6696 ;
	END in0
	OBS
		LAYER M1 ;
		RECT 0.18 6.36 1.96 6.59 ;
		LAYER M1 ;
		RECT 0.18 4.19 0.52 6.36 ;
		LAYER M1 ;
		RECT 0.9 4.19 1.24 5.94 ;
		LAYER M1 ;
		RECT 1.62 4.42 1.96 6.36 ;
		LAYER M1 ;
		RECT 3.06 4.42 3.4 6.59 ;
		LAYER M1 ;
		RECT 1.62 4.19 3.4 4.42 ;
		LAYER M1 ;
		RECT 0.9 2.86 1.13 4.19 ;
		LAYER M1 ;
		RECT 3.875 2.86 4.215 2.91 ;
		LAYER M1 ;
		RECT 0.9 2.63 4.215 2.86 ;
		LAYER M1 ;
		RECT 1.675 2.4 1.905 2.63 ;
		LAYER M1 ;
		RECT 3.875 2.57 4.215 2.63 ;
		LAYER M1 ;
		RECT 1.62 1.24 1.96 2.4 ;
	END
END MMI_AO22C
MACRO MMI_AO31B
	CLASS CORE ;
	FOREIGN MMI_AO31B 0 0 ;
	SIZE 4.44 BY 7.4 ;
	SYMMETRY X Y ;
	SITE CORE1 ;
	PIN out
		DIRECTION output ;
		USE SIGNAL ;
		PORT
			LAYER M1 ;
			RECT 3.78 4.53 4.12 6.29 ;
			LAYER M1 ;
			RECT 3.82 3.555 4.05 4.53 ;
			LAYER M1 ;
			RECT 3.82 3.445 4.295 3.555 ;
			LAYER M1 ;
			RECT 3.785 3.105 4.295 3.445 ;
			LAYER M1 ;
			RECT 3.785 2.36 4.015 3.105 ;
			LAYER M1 ;
			RECT 3.28 2.13 4.015 2.36 ;
			LAYER M1 ;
			RECT 3.28 1.52 3.62 2.13 ;
		END
		AntennaDiffArea 1.3248 ;
	END out
	PIN in1
		DIRECTION input ;
		USE SIGNAL ;
		PORT
			LAYER M1 ;
			RECT 0.885 4.2 1.335 4.295 ;
			LAYER M1 ;
			RECT 0.885 3.86 1.64 4.2 ;
			LAYER M1 ;
			RECT 0.885 3.845 1.335 3.86 ;
		END
		AntennaGateArea 0.5796 ;
	END in1
	PIN GND
		DIRECTION inout ;
		USE GROUND ;
		PORT
			LAYER M1 ;
			RECT 0.18 0.5 0.52 2.36 ;
			LAYER M1 ;
			RECT 2.52 0.5 2.86 2.36 ;
			LAYER M1 ;
			RECT 0 -0.5 4.44 0.5 ;
		END
	END GND
	PIN in2
		DIRECTION input ;
		USE SIGNAL ;
		PORT
			LAYER M1 ;
			RECT 1.97 3.86 2.31 4.2 ;
			LAYER M1 ;
			RECT 2.025 3.555 2.255 3.86 ;
			LAYER M1 ;
			RECT 1.625 3.215 2.255 3.555 ;
			LAYER M1 ;
			RECT 1.625 3.105 2.075 3.215 ;
		END
		AntennaGateArea 0.5796 ;
	END in2
	PIN VDD
		DIRECTION inout ;
		USE POWER ;
		PORT
			LAYER M1 ;
			RECT 0 6.9 4.44 7.9 ;
			LAYER M1 ;
			RECT 1.62 5.01 1.96 6.9 ;
			LAYER M1 ;
			RECT 3.06 4.53 3.4 6.9 ;
		END
	END VDD
	PIN in3
		DIRECTION input ;
		USE SIGNAL ;
		PORT
			LAYER M1 ;
			RECT 3.105 3.5 3.555 3.555 ;
			LAYER M1 ;
			RECT 3 3.16 3.555 3.5 ;
			LAYER M1 ;
			RECT 3.105 3.105 3.555 3.16 ;
		END
		AntennaGateArea 0.5796 ;
	END in3
	PIN in0
		DIRECTION input ;
		USE SIGNAL ;
		PORT
			LAYER M1 ;
			RECT 0.885 3.5 1.335 3.555 ;
			LAYER M1 ;
			RECT 0.64 3.16 1.335 3.5 ;
			LAYER M1 ;
			RECT 0.885 3.105 1.335 3.16 ;
		END
		AntennaGateArea 0.414 ;
	END in0
	OBS
		LAYER M1 ;
		RECT 0.18 4.53 0.52 6.29 ;
		LAYER M1 ;
		RECT 0.9 4.76 1.24 6.29 ;
		LAYER M1 ;
		RECT 2.34 4.76 2.68 6.29 ;
		LAYER M1 ;
		RECT 0.9 4.53 2.68 4.76 ;
		LAYER M1 ;
		RECT 0.18 2.835 0.41 4.53 ;
		LAYER M1 ;
		RECT 3.25 4.135 3.59 4.19 ;
		LAYER M1 ;
		RECT 2.54 3.905 3.59 4.135 ;
		LAYER M1 ;
		RECT 2.54 2.835 2.77 3.905 ;
		LAYER M1 ;
		RECT 3.25 3.85 3.59 3.905 ;
		LAYER M1 ;
		RECT 0.18 2.605 2.77 2.835 ;
		LAYER M1 ;
		RECT 0.94 2.36 1.17 2.605 ;
		LAYER M1 ;
		RECT 0.94 1.06 1.28 2.36 ;
	END
END MMI_AO31B
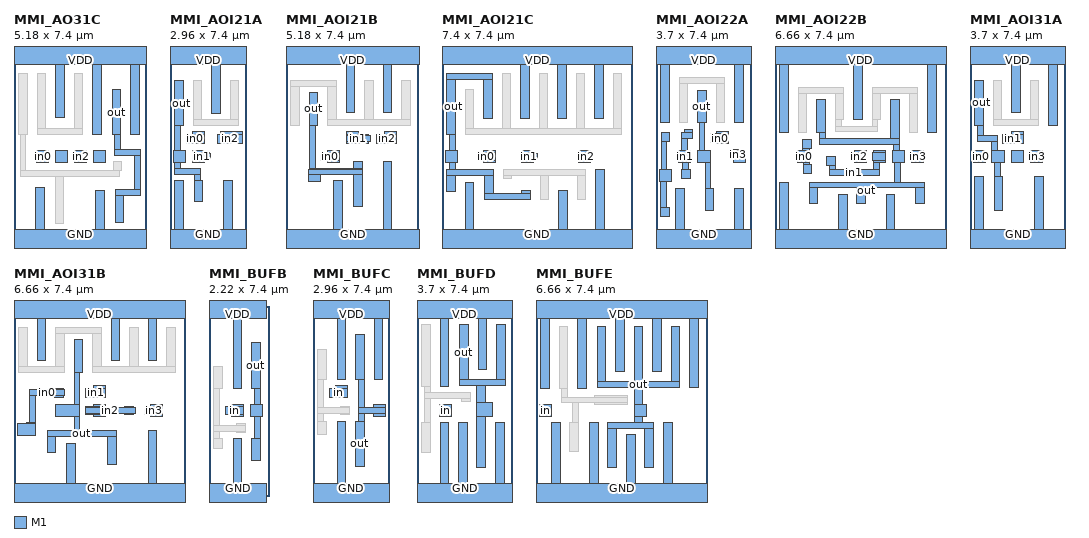
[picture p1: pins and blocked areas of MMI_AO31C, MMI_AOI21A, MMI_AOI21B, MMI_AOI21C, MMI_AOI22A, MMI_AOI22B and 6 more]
MACRO MMI_AO31C
	CLASS CORE ;
	FOREIGN MMI_AO31C 0 0 ;
	SIZE 5.18 BY 7.4 ;
	SYMMETRY X Y ;
	SITE CORE1 ;
	PIN out
		DIRECTION output ;
		USE SIGNAL ;
		PORT
			LAYER M1 ;
			RECT 3.82 4.18 4.16 5.94 ;
			LAYER M1 ;
			RECT 3.93 3.615 4.16 4.18 ;
			LAYER M1 ;
			RECT 3.93 3.385 4.925 3.615 ;
			LAYER M1 ;
			RECT 4.695 2.03 4.925 3.385 ;
			LAYER M1 ;
			RECT 3.94 1.8 4.925 2.03 ;
			LAYER M1 ;
			RECT 3.94 0.75 4.28 1.8 ;
		END
		AntennaDiffArea 1.8768 ;
	END out
	PIN in1
		DIRECTION input ;
		USE SIGNAL ;
		PORT
			LAYER M1 ;
			RECT 1.625 3.105 2.075 3.555 ;
		END
		AntennaGateArea 0.7812 ;
	END in1
	PIN GND
		DIRECTION inout ;
		USE GROUND ;
		PORT
			LAYER M1 ;
			RECT 0.84 0.5 1.18 2.115 ;
			LAYER M1 ;
			RECT 3.18 0.5 3.52 2.01 ;
			LAYER M1 ;
			RECT 0 -0.5 5.18 0.5 ;
		END
	END GND
	PIN in2
		DIRECTION input ;
		USE SIGNAL ;
		PORT
			LAYER M1 ;
			RECT 2.365 3.105 2.815 3.555 ;
		END
		AntennaGateArea 0.7812 ;
	END in2
	PIN VDD
		DIRECTION inout ;
		USE POWER ;
		PORT
			LAYER M1 ;
			RECT 0 6.9 5.18 7.9 ;
			LAYER M1 ;
			RECT 1.62 4.83 1.96 6.9 ;
			LAYER M1 ;
			RECT 3.06 4.18 3.4 6.9 ;
			LAYER M1 ;
			RECT 4.54 4.18 4.88 6.9 ;
		END
	END VDD
	PIN in3
		DIRECTION input ;
		USE SIGNAL ;
		PORT
			LAYER M1 ;
			RECT 3.105 3.105 3.555 3.555 ;
		END
		AntennaGateArea 0.7812 ;
	END in3
	PIN in0
		DIRECTION input ;
		USE SIGNAL ;
		PORT
			LAYER M1 ;
			RECT 0.885 3.105 1.335 3.555 ;
		END
		AntennaGateArea 0.558 ;
	END in0
	OBS
		LAYER M1 ;
		RECT 0.18 4.18 0.52 6.58 ;
		LAYER M1 ;
		RECT 0.9 4.41 1.24 6.58 ;
		LAYER M1 ;
		RECT 2.34 4.41 2.68 6.58 ;
		LAYER M1 ;
		RECT 0.9 4.18 2.68 4.41 ;
		LAYER M1 ;
		RECT 0.235 2.775 0.465 4.18 ;
		LAYER M1 ;
		RECT 3.86 2.78 4.2 3.12 ;
		LAYER M1 ;
		RECT 3.86 2.775 4.09 2.78 ;
		LAYER M1 ;
		RECT 0.235 2.545 4.09 2.775 ;
		LAYER M1 ;
		RECT 1.6 0.73 1.94 2.545 ;
	END
END MMI_AO31C
MACRO MMI_AOI21A
	CLASS CORE ;
	FOREIGN MMI_AOI21A 0 0 ;
	SIZE 2.96 BY 7.4 ;
	SYMMETRY X Y ;
	SITE CORE1 ;
	PIN out
		DIRECTION output ;
		USE SIGNAL ;
		PORT
			LAYER M1 ;
			RECT 0.18 4.525 0.52 6.285 ;
			LAYER M1 ;
			RECT 0.18 3.555 0.41 4.525 ;
			LAYER M1 ;
			RECT 0.145 3.105 0.595 3.555 ;
			LAYER M1 ;
			RECT 0.18 2.87 0.41 3.105 ;
			LAYER M1 ;
			RECT 0.18 2.64 1.17 2.87 ;
			LAYER M1 ;
			RECT 0.94 2.41 1.17 2.64 ;
			LAYER M1 ;
			RECT 0.94 1.57 1.28 2.41 ;
		END
		AntennaDiffArea 1.3708 ;
	END out
	PIN in1
		DIRECTION input ;
		USE SIGNAL ;
		PORT
			LAYER M1 ;
			RECT 0.885 3.5 1.335 3.555 ;
			LAYER M1 ;
			RECT 0.885 3.445 1.52 3.5 ;
			LAYER M1 ;
			RECT 0.885 3.215 1.585 3.445 ;
			LAYER M1 ;
			RECT 0.885 3.16 1.52 3.215 ;
			LAYER M1 ;
			RECT 0.885 3.105 1.335 3.16 ;
		END
		AntennaGateArea 0.4968 ;
	END in1
	PIN GND
		DIRECTION inout ;
		USE GROUND ;
		PORT
			LAYER M1 ;
			RECT 0.18 0.5 0.52 2.41 ;
			LAYER M1 ;
			RECT 2.09 0.5 2.43 2.41 ;
			LAYER M1 ;
			RECT 0 -0.5 2.96 0.5 ;
		END
	END GND
	PIN in2
		DIRECTION input ;
		USE SIGNAL ;
		PORT
			LAYER M1 ;
			RECT 1.97 4.195 2.815 4.295 ;
			LAYER M1 ;
			RECT 1.86 3.855 2.815 4.195 ;
			LAYER M1 ;
			RECT 1.97 3.845 2.815 3.855 ;
		END
		AntennaGateArea 0.4968 ;
	END in2
	PIN VDD
		DIRECTION inout ;
		USE POWER ;
		PORT
			LAYER M1 ;
			RECT 0 6.9 2.96 7.9 ;
			LAYER M1 ;
			RECT 1.62 5.005 1.96 6.9 ;
		END
	END VDD
	PIN in0
		DIRECTION input ;
		USE SIGNAL ;
		PORT
			LAYER M1 ;
			RECT 0.885 4.19 1.335 4.295 ;
			LAYER M1 ;
			RECT 0.64 3.85 1.335 4.19 ;
			LAYER M1 ;
			RECT 0.885 3.845 1.335 3.85 ;
		END
		AntennaGateArea 0.414 ;
	END in0
	OBS
		LAYER M1 ;
		RECT 0.9 4.755 1.24 6.285 ;
		LAYER M1 ;
		RECT 2.34 4.755 2.68 6.285 ;
		LAYER M1 ;
		RECT 0.9 4.525 2.68 4.755 ;
	END
END MMI_AOI21A
MACRO MMI_AOI21B
	CLASS CORE ;
	FOREIGN MMI_AOI21B 0 0 ;
	SIZE 5.18 BY 7.4 ;
	SYMMETRY X Y ;
	SITE CORE1 ;
	PIN out
		DIRECTION output ;
		USE SIGNAL ;
		PORT
			LAYER M1 ;
			RECT 0.9 4.545 1.24 5.825 ;
			LAYER M1 ;
			RECT 0.9 2.85 1.13 4.545 ;
			LAYER M1 ;
			RECT 2.63 2.85 2.97 3.13 ;
			LAYER M1 ;
			RECT 0.9 2.815 2.97 2.85 ;
			LAYER M1 ;
			RECT 0.885 2.62 2.97 2.815 ;
			LAYER M1 ;
			RECT 0.885 2.365 1.335 2.62 ;
			LAYER M1 ;
			RECT 2.63 1.37 2.97 2.62 ;
		END
		AntennaDiffArea 1.978 ;
	END out
	PIN in1
		DIRECTION input ;
		USE SIGNAL ;
		PORT
			LAYER M1 ;
			RECT 2.365 4.19 2.815 4.295 ;
			LAYER M1 ;
			RECT 2.365 4.135 3.21 4.19 ;
			LAYER M1 ;
			RECT 2.365 3.905 3.275 4.135 ;
			LAYER M1 ;
			RECT 2.365 3.85 3.21 3.905 ;
			LAYER M1 ;
			RECT 2.365 3.845 2.815 3.85 ;
		END
		AntennaGateArea 0.9936 ;
	END in1
	PIN GND
		DIRECTION inout ;
		USE GROUND ;
		PORT
			LAYER M1 ;
			RECT 1.86 0.5 2.2 2.385 ;
			LAYER M1 ;
			RECT 3.78 0.5 4.12 3.13 ;
			LAYER M1 ;
			RECT 0 -0.5 5.18 0.5 ;
		END
	END GND
	PIN in2
		DIRECTION input ;
		USE SIGNAL ;
		PORT
			LAYER M1 ;
			RECT 3.845 4.19 4.295 4.295 ;
			LAYER M1 ;
			RECT 3.54 3.85 4.295 4.19 ;
			LAYER M1 ;
			RECT 3.845 3.845 4.295 3.85 ;
		END
		AntennaGateArea 0.9936 ;
	END in2
	PIN VDD
		DIRECTION inout ;
		USE POWER ;
		PORT
			LAYER M1 ;
			RECT 0 6.9 5.18 7.9 ;
			LAYER M1 ;
			RECT 2.34 5.025 2.68 6.9 ;
			LAYER M1 ;
			RECT 3.78 5.025 4.12 6.9 ;
		END
	END VDD
	PIN in0
		DIRECTION input ;
		USE SIGNAL ;
		PORT
			LAYER M1 ;
			RECT 1.625 3.5 2.075 3.555 ;
			LAYER M1 ;
			RECT 1.36 3.16 2.075 3.5 ;
			LAYER M1 ;
			RECT 1.625 3.105 2.075 3.16 ;
		END
		AntennaGateArea 0.828 ;
	END in0
	OBS
		LAYER M1 ;
		RECT 0.18 6.075 1.96 6.305 ;
		LAYER M1 ;
		RECT 0.18 4.545 0.52 6.075 ;
		LAYER M1 ;
		RECT 1.62 4.775 1.96 6.075 ;
		LAYER M1 ;
		RECT 3.06 4.775 3.4 6.305 ;
		LAYER M1 ;
		RECT 4.5 4.775 4.84 6.305 ;
		LAYER M1 ;
		RECT 1.62 4.545 4.84 4.775 ;
	END
END MMI_AOI21B
MACRO MMI_AOI21C
	CLASS CORE ;
	FOREIGN MMI_AOI21C 0 0 ;
	SIZE 7.4 BY 7.4 ;
	SYMMETRY X Y ;
	SITE CORE1 ;
	PIN out
		DIRECTION output ;
		USE SIGNAL ;
		PORT
			LAYER M1 ;
			RECT 0.18 6.34 1.96 6.57 ;
			LAYER M1 ;
			RECT 0.18 4.195 0.52 6.34 ;
			LAYER M1 ;
			RECT 1.62 4.815 1.96 6.34 ;
			LAYER M1 ;
			RECT 0.29 3.555 0.52 4.195 ;
			LAYER M1 ;
			RECT 0.145 3.105 0.595 3.555 ;
			LAYER M1 ;
			RECT 0.29 2.805 0.52 3.105 ;
			LAYER M1 ;
			RECT 0.18 2.575 2 2.805 ;
			LAYER M1 ;
			RECT 0.18 1.965 0.52 2.575 ;
			LAYER M1 ;
			RECT 1.66 1.89 2 2.575 ;
			LAYER M1 ;
			RECT 3.1 1.89 3.44 2 ;
			LAYER M1 ;
			RECT 1.66 1.66 3.44 1.89 ;
		END
		AntennaDiffArea 4.2872 ;
	END out
	PIN in1
		DIRECTION input ;
		USE SIGNAL ;
		PORT
			LAYER M1 ;
			RECT 3.105 3.5 3.555 3.555 ;
			LAYER M1 ;
			RECT 3.105 3.445 3.64 3.5 ;
			LAYER M1 ;
			RECT 3.105 3.215 3.705 3.445 ;
			LAYER M1 ;
			RECT 3.105 3.16 3.64 3.215 ;
			LAYER M1 ;
			RECT 3.105 3.105 3.555 3.16 ;
		END
		AntennaGateArea 1.9872 ;
	END in1
	PIN GND
		DIRECTION inout ;
		USE GROUND ;
		PORT
			LAYER M1 ;
			RECT 0.9 0.5 1.24 2.305 ;
			LAYER M1 ;
			RECT 4.54 0.5 4.88 2 ;
			LAYER M1 ;
			RECT 5.98 0.5 6.32 2.805 ;
			LAYER M1 ;
			RECT 0 -0.5 7.4 0.5 ;
		END
	END GND
	PIN in2
		DIRECTION input ;
		USE SIGNAL ;
		PORT
			LAYER M1 ;
			RECT 5.325 3.5 5.775 3.555 ;
			LAYER M1 ;
			RECT 5.325 3.445 5.8 3.5 ;
			LAYER M1 ;
			RECT 5.325 3.215 5.865 3.445 ;
			LAYER M1 ;
			RECT 5.325 3.16 5.8 3.215 ;
			LAYER M1 ;
			RECT 5.325 3.105 5.775 3.16 ;
		END
		AntennaGateArea 1.9872 ;
	END in2
	PIN VDD
		DIRECTION inout ;
		USE POWER ;
		PORT
			LAYER M1 ;
			RECT 0 6.9 7.4 7.9 ;
			LAYER M1 ;
			RECT 3.06 4.815 3.4 6.9 ;
			LAYER M1 ;
			RECT 4.5 4.815 4.84 6.9 ;
			LAYER M1 ;
			RECT 5.94 4.815 6.28 6.9 ;
		END
	END VDD
	PIN in0
		DIRECTION input ;
		USE SIGNAL ;
		PORT
			LAYER M1 ;
			RECT 1.625 3.5 2.075 3.555 ;
			LAYER M1 ;
			RECT 1.38 3.16 2.075 3.5 ;
			LAYER M1 ;
			RECT 1.625 3.105 2.075 3.16 ;
		END
		AntennaGateArea 1.6569 ;
	END in0
	OBS
		LAYER M1 ;
		RECT 0.9 4.425 1.24 5.945 ;
		LAYER M1 ;
		RECT 2.34 4.425 2.68 6.57 ;
		LAYER M1 ;
		RECT 3.78 4.425 4.12 6.57 ;
		LAYER M1 ;
		RECT 5.22 4.425 5.56 6.57 ;
		LAYER M1 ;
		RECT 6.66 4.425 7 6.57 ;
		LAYER M1 ;
		RECT 0.9 4.195 7 4.425 ;
		LAYER M1 ;
		RECT 2.38 2.575 5.6 2.805 ;
		LAYER M1 ;
		RECT 2.38 2.46 2.72 2.575 ;
		LAYER M1 ;
		RECT 3.82 1.66 4.16 2.575 ;
		LAYER M1 ;
		RECT 5.26 1.66 5.6 2.575 ;
	END
END MMI_AOI21C
MACRO MMI_AOI22A
	CLASS CORE ;
	FOREIGN MMI_AOI22A 0 0 ;
	SIZE 3.7 BY 7.4 ;
	SYMMETRY X Y ;
	SITE CORE1 ;
	PIN out
		DIRECTION output ;
		USE SIGNAL ;
		PORT
			LAYER M1 ;
			RECT 1.62 4.635 1.96 5.915 ;
			LAYER M1 ;
			RECT 1.675 3.555 1.905 4.635 ;
			LAYER M1 ;
			RECT 1.625 3.55 2.075 3.555 ;
			LAYER M1 ;
			RECT 1.625 3.105 2.14 3.55 ;
			LAYER M1 ;
			RECT 1.91 2.07 2.14 3.105 ;
			LAYER M1 ;
			RECT 1.91 1.23 2.25 2.07 ;
		END
		AntennaDiffArea 1.4904 ;
	END out
	PIN in1
		DIRECTION input ;
		USE SIGNAL ;
		PORT
			LAYER M1 ;
			RECT 1.095 4.27 1.435 4.38 ;
			LAYER M1 ;
			RECT 0.98 4.04 1.435 4.27 ;
			LAYER M1 ;
			RECT 0.98 3.555 1.21 4.04 ;
			LAYER M1 ;
			RECT 0.885 3.105 1.335 3.555 ;
			LAYER M1 ;
			RECT 1.045 2.81 1.275 3.105 ;
			LAYER M1 ;
			RECT 1 2.47 1.34 2.81 ;
		END
		AntennaGateArea 0.4968 ;
	END in1
	PIN GND
		DIRECTION inout ;
		USE GROUND ;
		PORT
			LAYER M1 ;
			RECT 0.76 0.5 1.1 2.07 ;
			LAYER M1 ;
			RECT 3.06 0.5 3.4 2.07 ;
			LAYER M1 ;
			RECT 0 -0.5 3.7 0.5 ;
		END
	END GND
	PIN in2
		DIRECTION input ;
		USE SIGNAL ;
		PORT
			LAYER M1 ;
			RECT 0.195 3.93 0.535 4.27 ;
			LAYER M1 ;
			RECT 0.195 2.815 0.425 3.93 ;
			LAYER M1 ;
			RECT 0.145 2.365 0.595 2.815 ;
			LAYER M1 ;
			RECT 0.185 1.34 0.415 2.365 ;
			LAYER M1 ;
			RECT 0.185 1 0.525 1.34 ;
		END
		AntennaGateArea 0.4968 ;
	END in2
	PIN VDD
		DIRECTION inout ;
		USE POWER ;
		PORT
			LAYER M1 ;
			RECT 0 6.9 3.7 7.9 ;
			LAYER M1 ;
			RECT 0.18 4.635 0.52 6.9 ;
			LAYER M1 ;
			RECT 3.06 4.635 3.4 6.9 ;
		END
	END VDD
	PIN in3
		DIRECTION input ;
		USE SIGNAL ;
		PORT
			LAYER M1 ;
			RECT 2.9 3.55 3.24 3.61 ;
			LAYER M1 ;
			RECT 2.9 3.27 3.475 3.55 ;
			LAYER M1 ;
			RECT 3.02 3.265 3.475 3.27 ;
			LAYER M1 ;
			RECT 3.025 3.105 3.475 3.265 ;
		END
		AntennaGateArea 0.4968 ;
	END in3
	PIN in0
		DIRECTION input ;
		USE SIGNAL ;
		PORT
			LAYER M1 ;
			RECT 2.365 4.215 2.815 4.295 ;
			LAYER M1 ;
			RECT 2.14 3.875 2.815 4.215 ;
			LAYER M1 ;
			RECT 2.365 3.845 2.815 3.875 ;
		END
		AntennaGateArea 0.4968 ;
	END in0
	OBS
		LAYER M1 ;
		RECT 0.9 6.165 2.68 6.395 ;
		LAYER M1 ;
		RECT 0.9 4.635 1.24 6.165 ;
		LAYER M1 ;
		RECT 2.34 4.635 2.68 6.165 ;
	END
END MMI_AOI22A
MACRO MMI_AOI22B
	CLASS CORE ;
	FOREIGN MMI_AOI22B 0 0 ;
	SIZE 6.66 BY 7.4 ;
	SYMMETRY X Y ;
	SITE CORE1 ;
	PIN out
		DIRECTION output ;
		USE SIGNAL ;
		PORT
			LAYER M1 ;
			RECT 1.62 4.275 1.96 5.555 ;
			LAYER M1 ;
			RECT 1.73 4.025 1.96 4.275 ;
			LAYER M1 ;
			RECT 4.5 4.025 4.84 5.555 ;
			LAYER M1 ;
			RECT 1.73 3.795 4.84 4.025 ;
			LAYER M1 ;
			RECT 4.61 3.555 4.84 3.795 ;
			LAYER M1 ;
			RECT 4.585 3.105 5.035 3.555 ;
			LAYER M1 ;
			RECT 4.655 2.335 4.885 3.105 ;
			LAYER M1 ;
			RECT 1.33 2.105 5.82 2.335 ;
			LAYER M1 ;
			RECT 1.33 1.495 1.67 2.105 ;
			LAYER M1 ;
			RECT 3.18 1.495 3.52 2.105 ;
			LAYER M1 ;
			RECT 5.48 1.495 5.82 2.105 ;
		END
		AntennaDiffArea 3.3672 ;
	END out
	PIN in1
		DIRECTION input ;
		USE SIGNAL ;
		PORT
			LAYER M1 ;
			RECT 3.845 3.5 4.295 3.555 ;
			LAYER M1 ;
			RECT 2 2.995 2.34 3.335 ;
			LAYER M1 ;
			RECT 3.785 3.16 4.295 3.5 ;
			LAYER M1 ;
			RECT 2.11 2.815 2.34 2.995 ;
			LAYER M1 ;
			RECT 3.835 3.105 4.295 3.16 ;
			LAYER M1 ;
			RECT 3.835 2.815 4.065 3.105 ;
			LAYER M1 ;
			RECT 2.11 2.585 4.065 2.815 ;
		END
		AntennaGateArea 0.9936 ;
	END in1
	PIN GND
		DIRECTION inout ;
		USE GROUND ;
		PORT
			LAYER M1 ;
			RECT 0.18 0.5 0.52 2.335 ;
			LAYER M1 ;
			RECT 2.48 0.5 2.82 1.835 ;
			LAYER M1 ;
			RECT 4.33 0.5 4.67 1.835 ;
			LAYER M1 ;
			RECT 0 -0.5 6.66 0.5 ;
		END
	END GND
	PIN in2
		DIRECTION input ;
		USE SIGNAL ;
		PORT
			LAYER M1 ;
			RECT 3.105 3.5 3.555 3.555 ;
			LAYER M1 ;
			RECT 3.015 3.16 3.555 3.5 ;
			LAYER M1 ;
			RECT 3.105 3.105 3.555 3.16 ;
		END
		AntennaGateArea 0.9936 ;
	END in2
	PIN VDD
		DIRECTION inout ;
		USE POWER ;
		PORT
			LAYER M1 ;
			RECT 0 6.9 6.66 7.9 ;
			LAYER M1 ;
			RECT 0.18 4.275 0.52 6.9 ;
			LAYER M1 ;
			RECT 3.06 4.755 3.4 6.9 ;
			LAYER M1 ;
			RECT 5.94 4.275 6.28 6.9 ;
		END
	END VDD
	PIN in3
		DIRECTION input ;
		USE SIGNAL ;
		PORT
			LAYER M1 ;
			RECT 5.325 3.105 5.775 3.555 ;
		END
		AntennaGateArea 0.9936 ;
	END in3
	PIN in0
		DIRECTION input ;
		USE SIGNAL ;
		PORT
			LAYER M1 ;
			RECT 1.09 3.65 1.43 3.99 ;
			LAYER M1 ;
			RECT 1.09 3.555 1.335 3.65 ;
			LAYER M1 ;
			RECT 0.885 3.105 1.335 3.555 ;
			LAYER M1 ;
			RECT 1.1 3 1.335 3.105 ;
			LAYER M1 ;
			RECT 1.1 2.66 1.44 3 ;
		END
		AntennaGateArea 0.9936 ;
	END in0
	OBS
		LAYER M1 ;
		RECT 0.9 6.02 1.24 6.035 ;
		LAYER M1 ;
		RECT 2.34 6.02 2.68 6.035 ;
		LAYER M1 ;
		RECT 0.9 5.79 2.68 6.02 ;
		LAYER M1 ;
		RECT 0.9 4.275 1.24 5.79 ;
		LAYER M1 ;
		RECT 2.34 4.755 2.68 5.79 ;
		LAYER M1 ;
		RECT 3.78 6.025 4.12 6.035 ;
		LAYER M1 ;
		RECT 5.22 6.025 5.56 6.035 ;
		LAYER M1 ;
		RECT 3.78 5.795 5.56 6.025 ;
		LAYER M1 ;
		RECT 3.78 4.755 4.12 5.795 ;
		LAYER M1 ;
		RECT 2.365 4.515 2.595 4.755 ;
		LAYER M1 ;
		RECT 3.78 4.515 4.01 4.755 ;
		LAYER M1 ;
		RECT 2.365 4.285 4.01 4.515 ;
		LAYER M1 ;
		RECT 5.22 4.275 5.56 5.795 ;
	END
END MMI_AOI22B
MACRO MMI_AOI31A
	CLASS CORE ;
	FOREIGN MMI_AOI31A 0 0 ;
	SIZE 3.7 BY 7.4 ;
	SYMMETRY X Y ;
	SITE CORE1 ;
	PIN out
		DIRECTION output ;
		USE SIGNAL ;
		PORT
			LAYER M1 ;
			RECT 0.18 4.545 0.52 6.305 ;
			LAYER M1 ;
			RECT 0.29 4.135 0.52 4.545 ;
			LAYER M1 ;
			RECT 0.29 3.905 1.055 4.135 ;
			LAYER M1 ;
			RECT 0.825 3.555 1.055 3.905 ;
			LAYER M1 ;
			RECT 0.825 3.105 1.335 3.555 ;
			LAYER M1 ;
			RECT 0.94 2.54 1.17 3.105 ;
			LAYER M1 ;
			RECT 0.94 1.24 1.28 2.54 ;
		END
		AntennaDiffArea 1.5916 ;
	END out
	PIN in1
		DIRECTION input ;
		USE SIGNAL ;
		PORT
			LAYER M1 ;
			RECT 1.625 4.19 2.075 4.295 ;
			LAYER M1 ;
			RECT 1.285 3.85 2.075 4.19 ;
			LAYER M1 ;
			RECT 1.625 3.845 2.075 3.85 ;
		END
		AntennaGateArea 0.5796 ;
	END in1
	PIN GND
		DIRECTION inout ;
		USE GROUND ;
		PORT
			LAYER M1 ;
			RECT 0.18 0.5 0.52 2.54 ;
			LAYER M1 ;
			RECT 2.52 0.5 2.86 2.54 ;
			LAYER M1 ;
			RECT 0 -0.5 3.7 0.5 ;
		END
	END GND
	PIN in2
		DIRECTION input ;
		USE SIGNAL ;
		PORT
			LAYER M1 ;
			RECT 1.625 3.105 2.075 3.555 ;
		END
		AntennaGateArea 0.5796 ;
	END in2
	PIN VDD
		DIRECTION inout ;
		USE POWER ;
		PORT
			LAYER M1 ;
			RECT 0 6.9 3.7 7.9 ;
			LAYER M1 ;
			RECT 1.62 5.025 1.96 6.9 ;
			LAYER M1 ;
			RECT 3.06 4.545 3.4 6.9 ;
		END
	END VDD
	PIN in3
		DIRECTION input ;
		USE SIGNAL ;
		PORT
			LAYER M1 ;
			RECT 2.365 3.105 2.815 3.555 ;
		END
		AntennaGateArea 0.5796 ;
	END in3
	PIN in0
		DIRECTION input ;
		USE SIGNAL ;
		PORT
			LAYER M1 ;
			RECT 0.145 3.105 0.595 3.555 ;
		END
		AntennaGateArea 0.414 ;
	END in0
	OBS
		LAYER M1 ;
		RECT 0.9 4.775 1.24 6.305 ;
		LAYER M1 ;
		RECT 2.34 4.775 2.68 6.305 ;
		LAYER M1 ;
		RECT 0.9 4.545 2.68 4.775 ;
	END
END MMI_AOI31A
MACRO MMI_AOI31B
	CLASS CORE ;
	FOREIGN MMI_AOI31B 0 0 ;
	SIZE 6.66 BY 7.4 ;
	SYMMETRY X Y ;
	SITE CORE1 ;
	PIN out
		DIRECTION output ;
		USE SIGNAL ;
		PORT
			LAYER M1 ;
			RECT 2.34 4.81 2.68 6.09 ;
			LAYER M1 ;
			RECT 2.34 3.555 2.57 4.81 ;
			LAYER M1 ;
			RECT 1.625 3.105 2.57 3.555 ;
			LAYER M1 ;
			RECT 2.34 2.545 2.57 3.105 ;
			LAYER M1 ;
			RECT 1.295 2.315 3.98 2.545 ;
			LAYER M1 ;
			RECT 1.295 1.705 1.635 2.315 ;
			LAYER M1 ;
			RECT 3.64 1.245 3.98 2.315 ;
		END
		AntennaDiffArea 2.1804 ;
	END out
	PIN in1
		DIRECTION input ;
		USE SIGNAL ;
		PORT
			LAYER M1 ;
			RECT 3.105 4.19 3.555 4.295 ;
			LAYER M1 ;
			RECT 2.8 3.85 3.555 4.19 ;
			LAYER M1 ;
			RECT 3.105 3.845 3.555 3.85 ;
		END
		AntennaGateArea 1.1592 ;
	END in1
	PIN GND
		DIRECTION inout ;
		USE GROUND ;
		PORT
			LAYER M1 ;
			RECT 2.06 0.5 2.4 2.055 ;
			LAYER M1 ;
			RECT 5.22 0.5 5.56 2.545 ;
			LAYER M1 ;
			RECT 0 -0.5 6.66 0.5 ;
		END
	END GND
	PIN in2
		DIRECTION input ;
		USE SIGNAL ;
		PORT
			LAYER M1 ;
			RECT 3.105 3.5 3.555 3.555 ;
			LAYER M1 ;
			RECT 2.8 3.445 3.555 3.5 ;
			LAYER M1 ;
			RECT 4.31 3.445 4.65 3.5 ;
			LAYER M1 ;
			RECT 2.8 3.215 4.715 3.445 ;
			LAYER M1 ;
			RECT 2.8 3.16 3.555 3.215 ;
			LAYER M1 ;
			RECT 4.31 3.16 4.65 3.215 ;
			LAYER M1 ;
			RECT 3.105 3.105 3.555 3.16 ;
		END
		AntennaGateArea 1.1592 ;
	END in2
	PIN VDD
		DIRECTION inout ;
		USE POWER ;
		PORT
			LAYER M1 ;
			RECT 0 6.9 6.66 7.9 ;
			LAYER M1 ;
			RECT 0.9 5.29 1.24 6.9 ;
			LAYER M1 ;
			RECT 3.78 5.29 4.12 6.9 ;
			LAYER M1 ;
			RECT 5.22 5.29 5.56 6.9 ;
		END
	END VDD
	PIN in3
		DIRECTION input ;
		USE SIGNAL ;
		PORT
			LAYER M1 ;
			RECT 5.325 3.5 5.775 3.555 ;
			LAYER M1 ;
			RECT 5.1 3.16 5.775 3.5 ;
			LAYER M1 ;
			RECT 5.325 3.105 5.775 3.16 ;
		END
		AntennaGateArea 1.1592 ;
	END in3
	PIN in0
		DIRECTION input ;
		USE SIGNAL ;
		PORT
			LAYER M1 ;
			RECT 1.57 4.135 1.91 4.19 ;
			LAYER M1 ;
			RECT 0.595 3.905 1.975 4.135 ;
			LAYER M1 ;
			RECT 0.595 2.87 0.825 3.905 ;
			LAYER M1 ;
			RECT 1.57 3.85 1.91 3.905 ;
			LAYER M1 ;
			RECT 0.485 2.815 0.825 2.87 ;
			LAYER M1 ;
			RECT 0.145 2.365 0.825 2.815 ;
		END
		AntennaGateArea 0.828 ;
	END in0
	OBS
		LAYER M1 ;
		RECT 0.18 5.04 0.52 6.57 ;
		LAYER M1 ;
		RECT 1.62 6.34 3.4 6.57 ;
		LAYER M1 ;
		RECT 1.62 5.04 1.96 6.34 ;
		LAYER M1 ;
		RECT 0.18 4.81 1.96 5.04 ;
		LAYER M1 ;
		RECT 3.06 5.04 3.4 6.34 ;
		LAYER M1 ;
		RECT 4.5 5.04 4.84 6.57 ;
		LAYER M1 ;
		RECT 5.94 5.04 6.28 6.57 ;
		LAYER M1 ;
		RECT 3.06 4.81 6.28 5.04 ;
	END
END MMI_AOI31B
MACRO MMI_BUFB
	CLASS CORE ;
	FOREIGN MMI_BUFB 0 0 ;
	SIZE 2.22 BY 7.4 ;
	SYMMETRY X Y ;
	SITE CORE1 ;
	PIN out
		DIRECTION output ;
		USE SIGNAL ;
		PORT
			LAYER M1 ;
			RECT 1.66 4.2 2 5.96 ;
			LAYER M1 ;
			RECT 1.77 3.555 2 4.2 ;
			LAYER M1 ;
			RECT 1.625 3.105 2.075 3.555 ;
			LAYER M1 ;
			RECT 1.77 2.23 2 3.105 ;
			LAYER M1 ;
			RECT 1.66 1.39 2 2.23 ;
		END
		AntennaDiffArea 1.3248 ;
	END out
	PIN GND
		DIRECTION inout ;
		USE GROUND ;
		PORT
			LAYER M1 ;
			RECT 0.94 0.5 1.28 2.23 ;
			LAYER M1 ;
			RECT 0 -0.5 2.22 0.5 ;
		END
	END GND
	PIN VDD
		DIRECTION inout ;
		USE POWER ;
		PORT
			LAYER M1 ;
			RECT 0 6.9 2.22 7.9 ;
			LAYER M1 ;
			RECT 0.94 4.2 1.28 6.9 ;
		END
	END VDD
	PIN in
		DIRECTION input ;
		USE SIGNAL ;
		PORT
			LAYER M1 ;
			RECT 0.885 3.5 1.335 3.555 ;
			LAYER M1 ;
			RECT 0.64 3.16 1.335 3.5 ;
			LAYER M1 ;
			RECT 0.885 3.105 1.335 3.16 ;
		END
		AntennaGateArea 0.2484 ;
	END in
	OBS
		LAYER M1 ;
		RECT 0.18 4.2 0.52 5.04 ;
		LAYER M1 ;
		RECT 0.18 2.755 0.41 4.2 ;
		LAYER M1 ;
		RECT 1.09 2.755 1.43 2.81 ;
		LAYER M1 ;
		RECT 0.18 2.525 1.43 2.755 ;
		LAYER M1 ;
		RECT 0.18 2.23 0.41 2.525 ;
		LAYER M1 ;
		RECT 1.09 2.47 1.43 2.525 ;
		LAYER M1 ;
		RECT 0.18 1.85 0.52 2.23 ;
	END
END MMI_BUFB
MACRO MMI_BUFC
	CLASS CORE ;
	FOREIGN MMI_BUFC 0 0 ;
	SIZE 2.96 BY 7.4 ;
	SYMMETRY X Y ;
	SITE CORE1 ;
	PIN out
		DIRECTION output ;
		USE SIGNAL ;
		PORT
			LAYER M1 ;
			RECT 1.66 4.53 2 6.29 ;
			LAYER M1 ;
			RECT 1.77 3.445 2 4.53 ;
			LAYER M1 ;
			RECT 2.365 3.445 2.815 3.555 ;
			LAYER M1 ;
			RECT 1.77 3.215 2.815 3.445 ;
			LAYER M1 ;
			RECT 1.77 2.92 2 3.215 ;
			LAYER M1 ;
			RECT 2.365 3.105 2.815 3.215 ;
			LAYER M1 ;
			RECT 1.66 1.16 2 2.92 ;
		END
		AntennaDiffArea 1.8768 ;
	END out
	PIN GND
		DIRECTION inout ;
		USE GROUND ;
		PORT
			LAYER M1 ;
			RECT 0.94 0.5 1.28 2.92 ;
			LAYER M1 ;
			RECT 0 -0.5 2.96 0.5 ;
		END
	END GND
	PIN VDD
		DIRECTION inout ;
		USE POWER ;
		PORT
			LAYER M1 ;
			RECT 0 6.9 2.96 7.9 ;
			LAYER M1 ;
			RECT 0.94 4.53 1.28 6.9 ;
			LAYER M1 ;
			RECT 2.38 4.53 2.72 6.9 ;
		END
	END VDD
	PIN in
		DIRECTION input ;
		USE SIGNAL ;
		PORT
			LAYER M1 ;
			RECT 0.885 4.19 1.335 4.295 ;
			LAYER M1 ;
			RECT 0.64 3.85 1.335 4.19 ;
			LAYER M1 ;
			RECT 0.885 3.845 1.335 3.85 ;
		END
		AntennaGateArea 0.3348 ;
	END in
	OBS
		LAYER M1 ;
		RECT 0.18 4.53 0.52 5.69 ;
		LAYER M1 ;
		RECT 0.18 3.445 0.41 4.53 ;
		LAYER M1 ;
		RECT 1.09 3.445 1.43 3.5 ;
		LAYER M1 ;
		RECT 0.18 3.215 1.43 3.445 ;
		LAYER M1 ;
		RECT 0.18 2.92 0.41 3.215 ;
		LAYER M1 ;
		RECT 1.09 3.16 1.43 3.215 ;
		LAYER M1 ;
		RECT 0.18 2.38 0.52 2.92 ;
	END
END MMI_BUFC
MACRO MMI_BUFD
	CLASS CORE ;
	FOREIGN MMI_BUFD 0 0 ;
	SIZE 3.7 BY 7.4 ;
	SYMMETRY X Y ;
	SITE CORE1 ;
	PIN out
		DIRECTION output ;
		USE SIGNAL ;
		PORT
			LAYER M1 ;
			RECT 1.66 4.525 2 6.67 ;
			LAYER M1 ;
			RECT 3.1 4.525 3.44 6.67 ;
			LAYER M1 ;
			RECT 1.66 4.295 3.44 4.525 ;
			LAYER M1 ;
			RECT 2.33 3.64 2.67 4.295 ;
			LAYER M1 ;
			RECT 2.33 3.09 2.925 3.64 ;
			LAYER M1 ;
			RECT 2.33 1.1 2.67 3.09 ;
		END
		AntennaDiffArea 3.4977 ;
	END out
	PIN GND
		DIRECTION inout ;
		USE GROUND ;
		PORT
			LAYER M1 ;
			RECT 0.9 0.5 1.24 2.86 ;
			LAYER M1 ;
			RECT 1.61 0.5 1.95 2.86 ;
			LAYER M1 ;
			RECT 3.05 0.5 3.39 2.86 ;
			LAYER M1 ;
			RECT 0 -0.5 3.7 0.5 ;
		END
	END GND
	PIN VDD
		DIRECTION inout ;
		USE POWER ;
		PORT
			LAYER M1 ;
			RECT 0 6.9 3.7 7.9 ;
			LAYER M1 ;
			RECT 0.9 4.27 1.24 6.9 ;
			LAYER M1 ;
			RECT 2.38 4.915 2.72 6.9 ;
		END
	END VDD
	PIN in
		DIRECTION input ;
		USE SIGNAL ;
		PORT
			LAYER M1 ;
			RECT 0.885 3.105 1.335 3.555 ;
		END
		AntennaGateArea 0.6696 ;
	END in
	OBS
		LAYER M1 ;
		RECT 0.18 4.27 0.52 6.67 ;
		LAYER M1 ;
		RECT 0.29 4.025 0.52 4.27 ;
		LAYER M1 ;
		RECT 0.29 3.795 2.09 4.025 ;
		LAYER M1 ;
		RECT 0.29 2.86 0.52 3.795 ;
		LAYER M1 ;
		RECT 1.75 3.685 2.09 3.795 ;
		LAYER M1 ;
		RECT 0.18 1.7 0.52 2.86 ;
	END
END MMI_BUFD
MACRO MMI_BUFE
	CLASS CORE ;
	FOREIGN MMI_BUFE 0 0 ;
	SIZE 6.66 BY 7.4 ;
	SYMMETRY X Y ;
	SITE CORE1 ;
	PIN out
		DIRECTION output ;
		USE SIGNAL ;
		PORT
			LAYER M1 ;
			RECT 2.38 4.445 2.72 6.59 ;
			LAYER M1 ;
			RECT 3.82 4.445 4.16 6.59 ;
			LAYER M1 ;
			RECT 5.26 4.445 5.6 6.59 ;
			LAYER M1 ;
			RECT 2.38 4.215 5.6 4.445 ;
			LAYER M1 ;
			RECT 3.82 3.555 4.16 4.215 ;
			LAYER M1 ;
			RECT 3.82 3.105 4.295 3.555 ;
			LAYER M1 ;
			RECT 3.82 2.875 4.16 3.105 ;
			LAYER M1 ;
			RECT 2.8 2.645 4.58 2.875 ;
			LAYER M1 ;
			RECT 2.8 1.115 3.14 2.645 ;
			LAYER M1 ;
			RECT 4.24 1.115 4.58 2.645 ;
		END
		AntennaDiffArea 5.9643 ;
	END out
	PIN GND
		DIRECTION inout ;
		USE GROUND ;
		PORT
			LAYER M1 ;
			RECT 0.6 0.5 0.94 2.875 ;
			LAYER M1 ;
			RECT 2.08 0.5 2.42 2.875 ;
			LAYER M1 ;
			RECT 3.52 0.5 3.86 2.395 ;
			LAYER M1 ;
			RECT 4.96 0.5 5.3 2.875 ;
			LAYER M1 ;
			RECT 0 -0.5 6.66 0.5 ;
		END
	END GND
	PIN VDD
		DIRECTION inout ;
		USE POWER ;
		PORT
			LAYER M1 ;
			RECT 0 6.9 6.66 7.9 ;
			LAYER M1 ;
			RECT 0.18 4.19 0.52 6.9 ;
			LAYER M1 ;
			RECT 1.62 4.19 1.96 6.9 ;
			LAYER M1 ;
			RECT 3.1 4.835 3.44 6.9 ;
			LAYER M1 ;
			RECT 4.54 4.835 4.88 6.9 ;
			LAYER M1 ;
			RECT 5.98 4.215 6.32 6.9 ;
		END
	END VDD
	PIN in
		DIRECTION input ;
		USE SIGNAL ;
		PORT
			LAYER M1 ;
			RECT 0.145 3.105 0.595 3.555 ;
		END
		AntennaGateArea 1.3392 ;
	END in
	OBS
		LAYER M1 ;
		RECT 0.9 4.19 1.24 6.59 ;
		LAYER M1 ;
		RECT 1.01 3.855 1.24 4.19 ;
		LAYER M1 ;
		RECT 2.285 3.855 3.565 3.91 ;
		LAYER M1 ;
		RECT 1.01 3.625 3.565 3.855 ;
		LAYER M1 ;
		RECT 1.43 2.875 1.66 3.625 ;
		LAYER M1 ;
		RECT 2.285 3.57 3.565 3.625 ;
		LAYER M1 ;
		RECT 1.32 1.715 1.66 2.875 ;
	END
END MMI_BUFE
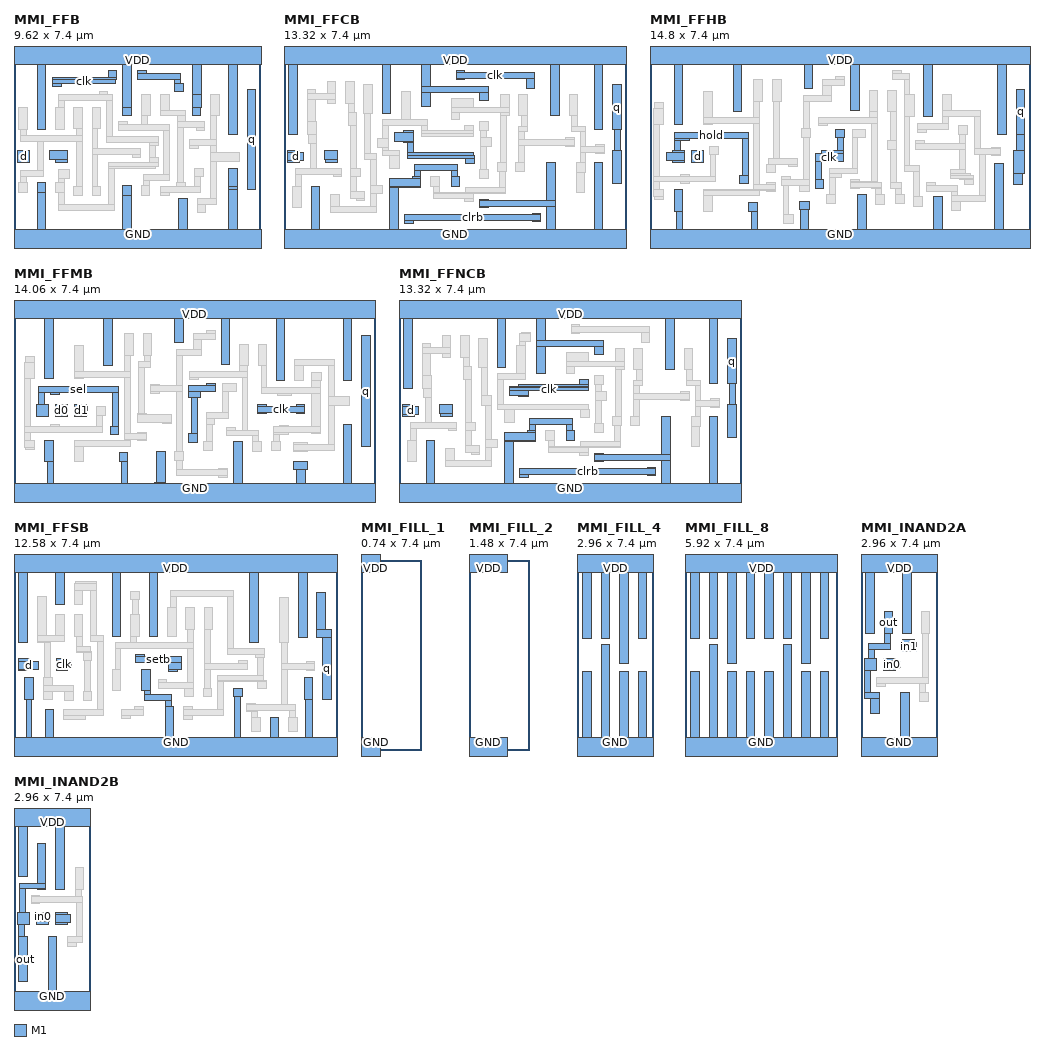
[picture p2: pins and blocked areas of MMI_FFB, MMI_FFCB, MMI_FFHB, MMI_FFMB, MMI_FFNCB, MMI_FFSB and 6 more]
MACRO MMI_FFB
	CLASS CORE ;
	FOREIGN MMI_FFB 0 0 ;
	SIZE 9.62 BY 7.4 ;
	SYMMETRY X Y ;
	SITE CORE1 ;
	PIN d
		DIRECTION input ;
		USE SIGNAL ;
		PORT
			LAYER M1 ;
			RECT 0.145 3.085 0.595 3.565 ;
		END
		AntennaGateArea 0.2484 ;
	END d
	PIN GND
		DIRECTION inout ;
		USE GROUND ;
		PORT
			LAYER M1 ;
			RECT 0.9 1.925 1.24 2.305 ;
			LAYER M1 ;
			RECT 0.905 0.5 1.245 1.925 ;
			LAYER M1 ;
			RECT 4.23 1.81 4.57 2.19 ;
			LAYER M1 ;
			RECT 8.36 2.18 8.7 2.88 ;
			LAYER M1 ;
			RECT 8.36 2.04 8.705 2.18 ;
			LAYER M1 ;
			RECT 4.235 0.5 4.575 1.81 ;
			LAYER M1 ;
			RECT 6.41 0.5 6.75 1.685 ;
			LAYER M1 ;
			RECT 8.365 0.5 8.705 2.04 ;
			LAYER M1 ;
			RECT 0.005 -0.5 9.625 0.5 ;
		END
	END GND
	PIN q
		DIRECTION output ;
		USE SIGNAL ;
		PORT
			LAYER M1 ;
			RECT 9.08 2.04 9.42 5.945 ;
		END
		AntennaDiffArea 1.3248 ;
	END q
	PIN VDD
		DIRECTION inout ;
		USE POWER ;
		PORT
			LAYER M1 ;
			RECT 0.005 6.9 9.625 7.9 ;
			LAYER M1 ;
			RECT 0.9 4.395 1.24 6.9 ;
			LAYER M1 ;
			RECT 4.235 5.25 4.575 6.9 ;
			LAYER M1 ;
			RECT 6.945 5.75 7.285 6.9 ;
			LAYER M1 ;
			RECT 4.23 4.91 4.575 5.25 ;
			LAYER M1 ;
			RECT 6.94 5.25 7.285 5.75 ;
			LAYER M1 ;
			RECT 6.94 4.91 7.28 5.25 ;
			LAYER M1 ;
			RECT 8.36 4.185 8.7 6.9 ;
		END
	END VDD
	PIN clk
		DIRECTION input ;
		USE CLOCK ;
		PORT
			LAYER M1 ;
			RECT 3.665 6.4 4.005 6.67 ;
			LAYER M1 ;
			RECT 1.51 6.33 4.005 6.4 ;
			LAYER M1 ;
			RECT 4.805 6.565 5.145 6.67 ;
			LAYER M1 ;
			RECT 4.805 6.335 6.5 6.565 ;
			LAYER M1 ;
			RECT 4.805 6.33 5.145 6.335 ;
			LAYER M1 ;
			RECT 1.51 6.17 3.95 6.33 ;
			LAYER M1 ;
			RECT 6.27 6.185 6.5 6.335 ;
			LAYER M1 ;
			RECT 1.51 6.06 1.85 6.17 ;
			LAYER M1 ;
			RECT 6.27 5.845 6.61 6.185 ;
			LAYER M1 ;
			RECT 1.38 3.215 2.08 3.555 ;
			LAYER M1 ;
			RECT 1.63 3.105 2.08 3.215 ;
		END
		AntennaGateArea 0.6408 ;
	END clk
	OBS
		LAYER M1 ;
		RECT 0.18 4.395 0.52 5.235 ;
		LAYER M1 ;
		RECT 3.32 5.735 3.66 5.875 ;
		LAYER M1 ;
		RECT 1.73 5.505 3.84 5.735 ;
		LAYER M1 ;
		RECT 1.73 5.235 1.96 5.505 ;
		LAYER M1 ;
		RECT 1.62 4.395 1.96 5.235 ;
		LAYER M1 ;
		RECT 2.32 4.405 2.66 5.245 ;
		LAYER M1 ;
		RECT 3.04 4.405 3.38 5.245 ;
		LAYER M1 ;
		RECT 0.24 4.145 0.47 4.395 ;
		LAYER M1 ;
		RECT 2.425 4.145 2.655 4.405 ;
		LAYER M1 ;
		RECT 0.24 3.915 2.655 4.145 ;
		LAYER M1 ;
		RECT 0.91 2.77 1.14 3.915 ;
		LAYER M1 ;
		RECT 1.83 2.82 2.17 2.825 ;
		LAYER M1 ;
		RECT 0.25 2.54 1.14 2.77 ;
		LAYER M1 ;
		RECT 0.25 2.305 0.48 2.54 ;
		LAYER M1 ;
		RECT 1.73 2.485 2.17 2.82 ;
		LAYER M1 ;
		RECT 1.73 2.305 1.96 2.485 ;
		LAYER M1 ;
		RECT 0.18 1.925 0.52 2.305 ;
		LAYER M1 ;
		RECT 1.62 1.925 1.96 2.305 ;
		LAYER M1 ;
		RECT 2.425 2.15 2.655 3.915 ;
		LAYER M1 ;
		RECT 3.04 3.645 3.27 4.405 ;
		LAYER M1 ;
		RECT 3.61 4.11 3.84 5.505 ;
		LAYER M1 ;
		RECT 4.98 4.91 5.32 5.75 ;
		LAYER M1 ;
		RECT 5.7 5.14 6.04 5.75 ;
		LAYER M1 ;
		RECT 5.7 4.91 6.68 5.14 ;
		LAYER M1 ;
		RECT 7.66 4.91 8 5.75 ;
		LAYER M1 ;
		RECT 4.07 4.57 4.41 4.68 ;
		LAYER M1 ;
		RECT 4.985 4.57 5.215 4.91 ;
		LAYER M1 ;
		RECT 6.375 4.68 6.68 4.91 ;
		LAYER M1 ;
		RECT 4.07 4.34 6.07 4.57 ;
		LAYER M1 ;
		RECT 3.61 4.105 5.515 4.11 ;
		LAYER M1 ;
		RECT 3.61 3.88 5.61 4.105 ;
		LAYER M1 ;
		RECT 5.27 3.765 5.61 3.88 ;
		LAYER M1 ;
		RECT 4.6 3.645 4.94 3.65 ;
		LAYER M1 ;
		RECT 3.04 3.415 4.94 3.645 ;
		LAYER M1 ;
		RECT 3.04 2.15 3.27 3.415 ;
		LAYER M1 ;
		RECT 4.6 3.31 4.94 3.415 ;
		LAYER M1 ;
		RECT 5.285 3.3 5.515 3.765 ;
		LAYER M1 ;
		RECT 5.27 3.08 5.61 3.3 ;
		LAYER M1 ;
		RECT 3.68 2.96 5.61 3.08 ;
		LAYER M1 ;
		RECT 3.68 2.85 5.515 2.96 ;
		LAYER M1 ;
		RECT 1.73 1.445 1.96 1.925 ;
		LAYER M1 ;
		RECT 2.32 1.81 2.66 2.15 ;
		LAYER M1 ;
		RECT 3.04 1.81 3.38 2.15 ;
		LAYER M1 ;
		RECT 3.68 1.445 3.91 2.85 ;
		LAYER M1 ;
		RECT 5.84 2.615 6.07 4.34 ;
		LAYER M1 ;
		RECT 5.06 2.38 6.07 2.615 ;
		LAYER M1 ;
		RECT 6.375 4.45 7.43 4.68 ;
		LAYER M1 ;
		RECT 5.06 2.19 5.29 2.38 ;
		LAYER M1 ;
		RECT 6.375 2.305 6.605 4.45 ;
		LAYER M1 ;
		RECT 7.09 4.34 7.43 4.45 ;
		LAYER M1 ;
		RECT 7.66 3.985 7.89 4.91 ;
		LAYER M1 ;
		RECT 6.835 3.755 7.89 3.985 ;
		LAYER M1 ;
		RECT 6.835 3.645 7.175 3.755 ;
		LAYER M1 ;
		RECT 7.66 3.475 7.89 3.755 ;
		LAYER M1 ;
		RECT 7.66 3.135 8.765 3.475 ;
		LAYER M1 ;
		RECT 7.03 2.54 7.37 2.88 ;
		LAYER M1 ;
		RECT 4.95 1.81 5.29 2.19 ;
		LAYER M1 ;
		RECT 6.33 2.15 6.67 2.305 ;
		LAYER M1 ;
		RECT 7.03 2.15 7.26 2.54 ;
		LAYER M1 ;
		RECT 5.71 1.92 7.26 2.15 ;
		LAYER M1 ;
		RECT 5.71 1.81 6.05 1.92 ;
		LAYER M1 ;
		RECT 1.73 1.215 3.91 1.445 ;
		LAYER M1 ;
		RECT 7.66 1.685 7.89 3.135 ;
		LAYER M1 ;
		RECT 7.13 1.455 7.89 1.685 ;
		LAYER M1 ;
		RECT 7.13 1.145 7.47 1.455 ;
	END
END MMI_FFB
MACRO MMI_FFCB
	CLASS CORE ;
	FOREIGN MMI_FFCB 0 0 ;
	SIZE 13.32 BY 7.4 ;
	SYMMETRY X Y ;
	SITE CORE1 ;
	PIN d
		DIRECTION input ;
		USE SIGNAL ;
		PORT
			LAYER M1 ;
			RECT 0.145 3.495 0.595 3.555 ;
			LAYER M1 ;
			RECT 0.145 3.155 0.76 3.495 ;
			LAYER M1 ;
			RECT 0.145 3.105 0.595 3.155 ;
		END
		AntennaGateArea 0.4968 ;
	END d
	PIN GND
		DIRECTION inout ;
		USE GROUND ;
		PORT
			LAYER M1 ;
			RECT 5.1 2.79 6.74 3.02 ;
			LAYER M1 ;
			RECT 5.1 2.56 5.33 2.79 ;
			LAYER M1 ;
			RECT 4.1 2.48 4.48 2.49 ;
			LAYER M1 ;
			RECT 4.99 2.48 5.33 2.56 ;
			LAYER M1 ;
			RECT 1.06 0.5 1.4 2.175 ;
			LAYER M1 ;
			RECT 4.1 2.15 5.33 2.48 ;
			LAYER M1 ;
			RECT 6.51 2.56 6.74 2.79 ;
			LAYER M1 ;
			RECT 6.51 2.18 6.85 2.56 ;
			LAYER M1 ;
			RECT 4.115 2.14 5.33 2.15 ;
			LAYER M1 ;
			RECT 4.115 0.5 4.455 2.14 ;
			LAYER M1 ;
			RECT 7.61 1.605 7.95 1.665 ;
			LAYER M1 ;
			RECT 10.23 1.605 10.57 3.095 ;
			LAYER M1 ;
			RECT 7.61 1.375 10.57 1.605 ;
			LAYER M1 ;
			RECT 7.61 1.325 7.95 1.375 ;
			LAYER M1 ;
			RECT 10.23 0.5 10.57 1.375 ;
			LAYER M1 ;
			RECT 12.08 0.5 12.42 3.105 ;
			LAYER M1 ;
			RECT 0 -0.5 13.32 0.5 ;
		END
	END GND
	PIN q
		DIRECTION output ;
		USE SIGNAL ;
		PORT
			LAYER M1 ;
			RECT 12.8 4.365 13.14 6.125 ;
			LAYER M1 ;
			RECT 12.86 3.555 13.09 4.365 ;
			LAYER M1 ;
			RECT 12.8 2.265 13.14 3.555 ;
		END
		AntennaDiffArea 1.3248 ;
	END q
	PIN VDD
		DIRECTION inout ;
		USE POWER ;
		PORT
			LAYER M1 ;
			RECT 0 6.9 13.32 7.9 ;
			LAYER M1 ;
			RECT 0.18 4.19 0.52 6.9 ;
			LAYER M1 ;
			RECT 3.825 5.015 4.165 6.9 ;
			LAYER M1 ;
			RECT 5.36 6.055 5.7 6.9 ;
			LAYER M1 ;
			RECT 5.36 5.825 7.955 6.055 ;
			LAYER M1 ;
			RECT 5.36 5.26 5.7 5.825 ;
			LAYER M1 ;
			RECT 7.615 5.495 7.955 5.825 ;
			LAYER M1 ;
			RECT 10.38 4.91 10.72 6.9 ;
			LAYER M1 ;
			RECT 12.08 4.365 12.42 6.9 ;
		END
	END VDD
	PIN clk
		DIRECTION input ;
		USE CLOCK ;
		PORT
			LAYER M1 ;
			RECT 6.7 6.61 7.04 6.67 ;
			LAYER M1 ;
			RECT 6.7 6.38 9.77 6.61 ;
			LAYER M1 ;
			RECT 6.7 6.33 7.04 6.38 ;
			LAYER M1 ;
			RECT 9.43 5.985 9.77 6.38 ;
			LAYER M1 ;
			RECT 4.64 4.255 5.04 4.325 ;
			LAYER M1 ;
			RECT 4.3 3.915 5.04 4.255 ;
			LAYER M1 ;
			RECT 4.64 3.88 5.04 3.915 ;
			LAYER M1 ;
			RECT 4.81 3.48 5.04 3.88 ;
			LAYER M1 ;
			RECT 4.81 3.385 7.385 3.48 ;
			LAYER M1 ;
			RECT 4.81 3.25 7.42 3.385 ;
			LAYER M1 ;
			RECT 7.08 3.045 7.42 3.25 ;
		END
		AntennaGateArea 0.6408 ;
	END clk
	PIN clrb
		DIRECTION input ;
		USE SIGNAL ;
		PORT
			LAYER M1 ;
			RECT 1.58 3.215 2.075 3.555 ;
			LAYER M1 ;
			RECT 1.625 3.105 2.075 3.215 ;
			LAYER M1 ;
			RECT 4.695 1.055 5.035 1.07 ;
			LAYER M1 ;
			RECT 9.66 1.055 10 1.12 ;
			LAYER M1 ;
			RECT 4.695 0.825 10 1.055 ;
			LAYER M1 ;
			RECT 4.695 0.73 5.035 0.825 ;
			LAYER M1 ;
			RECT 9.66 0.78 10 0.825 ;
		END
		AntennaGateArea 0.7128 ;
	END clrb
	OBS
		LAYER M1 ;
		RECT 0.9 5.785 1.24 5.95 ;
		LAYER M1 ;
		RECT 1.685 5.785 2.025 6.25 ;
		LAYER M1 ;
		RECT 0.9 5.555 2.025 5.785 ;
		LAYER M1 ;
		RECT 0.9 4.685 1.24 5.555 ;
		LAYER M1 ;
		RECT 1.685 5.41 2.025 5.555 ;
		LAYER M1 ;
		RECT 2.405 5.41 2.745 6.25 ;
		LAYER M1 ;
		RECT 2.515 5.05 2.745 5.41 ;
		LAYER M1 ;
		RECT 0.9 4.19 1.27 4.685 ;
		LAYER M1 ;
		RECT 2.515 4.54 2.82 5.05 ;
		LAYER M1 ;
		RECT 3.105 5.015 3.445 6.135 ;
		LAYER M1 ;
		RECT 0.96 3.825 1.27 4.19 ;
		LAYER M1 ;
		RECT 1.04 2.875 1.27 3.825 ;
		LAYER M1 ;
		RECT 2.59 2.875 2.82 4.54 ;
		LAYER M1 ;
		RECT 3.15 3.44 3.38 5.015 ;
		LAYER M1 ;
		RECT 4.585 4.785 4.925 5.85 ;
		LAYER M1 ;
		RECT 6.51 5.255 7.385 5.595 ;
		LAYER M1 ;
		RECT 8.425 5.255 8.765 5.75 ;
		LAYER M1 ;
		RECT 6.51 5.025 8.765 5.255 ;
		LAYER M1 ;
		RECT 6.51 4.785 6.85 5.025 ;
		LAYER M1 ;
		RECT 8.425 4.91 8.765 5.025 ;
		LAYER M1 ;
		RECT 9.145 4.91 9.485 5.75 ;
		LAYER M1 ;
		RECT 11.1 4.91 11.44 5.75 ;
		LAYER M1 ;
		RECT 3.84 4.555 5.6 4.785 ;
		LAYER M1 ;
		RECT 3.84 4.02 4.07 4.555 ;
		LAYER M1 ;
		RECT 5.37 4.325 5.6 4.555 ;
		LAYER M1 ;
		RECT 7.045 4.325 7.385 4.555 ;
		LAYER M1 ;
		RECT 7.615 4.345 7.955 4.685 ;
		LAYER M1 ;
		RECT 3.625 3.68 4.07 4.02 ;
		LAYER M1 ;
		RECT 5.37 4.215 7.385 4.325 ;
		LAYER M1 ;
		RECT 5.37 4.095 7.375 4.215 ;
		LAYER M1 ;
		RECT 3.84 3.58 4.07 3.68 ;
		LAYER M1 ;
		RECT 3.15 3.195 3.61 3.44 ;
		LAYER M1 ;
		RECT 3.84 3.35 4.48 3.58 ;
		LAYER M1 ;
		RECT 0.45 2.645 2.25 2.875 ;
		LAYER M1 ;
		RECT 0.45 2.175 0.68 2.645 ;
		LAYER M1 ;
		RECT 1.91 2.535 2.25 2.645 ;
		LAYER M1 ;
		RECT 2.59 2.535 2.97 2.875 ;
		LAYER M1 ;
		RECT 0.34 1.335 0.68 2.175 ;
		LAYER M1 ;
		RECT 2.59 1.95 2.82 2.535 ;
		LAYER M1 ;
		RECT 3.38 2.21 3.61 3.195 ;
		LAYER M1 ;
		RECT 4.1 2.87 4.48 3.35 ;
		LAYER M1 ;
		RECT 7.67 4.055 7.9 4.345 ;
		LAYER M1 ;
		RECT 7.67 3.715 8.065 4.055 ;
		LAYER M1 ;
		RECT 7.67 2.815 7.9 3.715 ;
		LAYER M1 ;
		RECT 8.425 3.095 8.655 4.91 ;
		LAYER M1 ;
		RECT 9.255 4.515 9.485 4.91 ;
		LAYER M1 ;
		RECT 9.145 4.285 9.485 4.515 ;
		LAYER M1 ;
		RECT 11.21 4.515 11.44 4.91 ;
		LAYER M1 ;
		RECT 11.21 4.285 11.76 4.515 ;
		LAYER M1 ;
		RECT 9.145 4.005 9.375 4.285 ;
		LAYER M1 ;
		RECT 10.96 4.005 11.3 4.055 ;
		LAYER M1 ;
		RECT 9.145 3.775 11.3 4.005 ;
		LAYER M1 ;
		RECT 9.145 3.095 9.375 3.775 ;
		LAYER M1 ;
		RECT 10.96 3.715 11.3 3.775 ;
		LAYER M1 ;
		RECT 11.53 3.735 11.76 4.285 ;
		LAYER M1 ;
		RECT 12.14 3.735 12.48 3.78 ;
		LAYER M1 ;
		RECT 11.53 3.505 12.48 3.735 ;
		LAYER M1 ;
		RECT 11.53 3.095 11.76 3.505 ;
		LAYER M1 ;
		RECT 12.14 3.44 12.48 3.505 ;
		LAYER M1 ;
		RECT 1.82 1.38 2.16 1.855 ;
		LAYER M1 ;
		RECT 2.59 1.71 3.15 1.95 ;
		LAYER M1 ;
		RECT 2.81 1.61 3.15 1.71 ;
		LAYER M1 ;
		RECT 3.38 1.87 3.855 2.21 ;
		LAYER M1 ;
		RECT 5.71 2.18 6.05 2.56 ;
		LAYER M1 ;
		RECT 7.61 2.475 7.95 2.815 ;
		LAYER M1 ;
		RECT 8.315 2.755 8.655 3.095 ;
		LAYER M1 ;
		RECT 9.035 2.755 9.375 3.095 ;
		LAYER M1 ;
		RECT 3.38 1.38 3.61 1.87 ;
		LAYER M1 ;
		RECT 1.82 1.15 3.61 1.38 ;
		LAYER M1 ;
		RECT 5.815 1.93 6.045 2.18 ;
		LAYER M1 ;
		RECT 8.4 2.13 8.63 2.755 ;
		LAYER M1 ;
		RECT 7.08 1.93 8.63 2.13 ;
		LAYER M1 ;
		RECT 5.815 1.9 8.63 1.93 ;
		LAYER M1 ;
		RECT 5.815 1.7 7.38 1.9 ;
		LAYER M1 ;
		RECT 7.04 1.565 7.38 1.7 ;
		LAYER M1 ;
		RECT 11.38 2.715 11.76 3.095 ;
		LAYER M1 ;
		RECT 11.38 1.935 11.72 2.715 ;
	END
END MMI_FFCB
MACRO MMI_FFHB
	CLASS CORE ;
	FOREIGN MMI_FFHB 0 0 ;
	SIZE 14.8 BY 7.4 ;
	SYMMETRY X Y ;
	SITE CORE1 ;
	PIN d
		DIRECTION input ;
		USE SIGNAL ;
		PORT
			LAYER M1 ;
			RECT 1.625 3.105 2.075 3.555 ;
		END
		AntennaGateArea 0.4968 ;
	END d
	PIN GND
		DIRECTION inout ;
		USE GROUND ;
		PORT
			LAYER M1 ;
			RECT 0.94 1.19 1.28 2.03 ;
			LAYER M1 ;
			RECT 3.83 1.195 4.17 1.535 ;
			LAYER M1 ;
			RECT 5.82 1.255 6.2 1.595 ;
			LAYER M1 ;
			RECT 1.05 0.5 1.28 1.19 ;
			LAYER M1 ;
			RECT 3.94 0.5 4.17 1.195 ;
			LAYER M1 ;
			RECT 5.85 0.5 6.19 1.255 ;
			LAYER M1 ;
			RECT 8.08 0.5 8.42 1.84 ;
			LAYER M1 ;
			RECT 11.04 0.5 11.38 1.755 ;
			LAYER M1 ;
			RECT 13.43 0.5 13.77 3.075 ;
			LAYER M1 ;
			RECT 0 -0.5 14.8 0.5 ;
		END
	END GND
	PIN q
		DIRECTION output ;
		USE SIGNAL ;
		PORT
			LAYER M1 ;
			RECT 14.265 4.19 14.605 5.95 ;
			LAYER M1 ;
			RECT 14.265 3.55 14.595 4.19 ;
			LAYER M1 ;
			RECT 14.15 2.675 14.595 3.55 ;
			LAYER M1 ;
			RECT 14.15 2.235 14.49 2.675 ;
		END
		AntennaDiffArea 1.3248 ;
	END q
	PIN VDD
		DIRECTION inout ;
		USE POWER ;
		PORT
			LAYER M1 ;
			RECT 0 6.9 14.8 7.9 ;
			LAYER M1 ;
			RECT 0.94 4.585 1.28 6.9 ;
			LAYER M1 ;
			RECT 3.24 5.075 3.58 6.9 ;
			LAYER M1 ;
			RECT 6 5.975 6.34 6.9 ;
			LAYER M1 ;
			RECT 7.81 5.105 8.15 6.9 ;
			LAYER M1 ;
			RECT 10.67 4.9 11.01 6.9 ;
			LAYER M1 ;
			RECT 13.545 4.19 13.885 6.9 ;
		END
	END VDD
	PIN clk
		DIRECTION input ;
		USE CLOCK ;
		PORT
			LAYER M1 ;
			RECT 7.24 4.06 7.58 4.4 ;
			LAYER M1 ;
			RECT 7.29 3.57 7.52 4.06 ;
			LAYER M1 ;
			RECT 6.66 3.445 7.52 3.57 ;
			LAYER M1 ;
			RECT 6.43 3.135 7.52 3.445 ;
			LAYER M1 ;
			RECT 6.43 2.415 6.66 3.135 ;
			LAYER M1 ;
			RECT 6.43 2.075 6.77 2.415 ;
		END
		AntennaGateArea 0.6408 ;
	END clk
	PIN hold
		DIRECTION input ;
		USE SIGNAL ;
		PORT
			LAYER M1 ;
			RECT 1.18 4.265 1.52 4.275 ;
			LAYER M1 ;
			RECT 0.95 4.035 3.82 4.265 ;
			LAYER M1 ;
			RECT 0.95 3.935 1.52 4.035 ;
			LAYER M1 ;
			RECT 0.95 3.555 1.18 3.935 ;
			LAYER M1 ;
			RECT 0.875 3.495 1.325 3.555 ;
			LAYER M1 ;
			RECT 0.66 3.155 1.325 3.495 ;
			LAYER M1 ;
			RECT 0.875 3.105 1.325 3.155 ;
			LAYER M1 ;
			RECT 3.59 2.6 3.82 4.035 ;
			LAYER M1 ;
			RECT 3.48 2.26 3.82 2.6 ;
		END
		AntennaGateArea 0.7452 ;
	END hold
	OBS
		LAYER M1 ;
		RECT 0.18 5.21 0.52 5.425 ;
		LAYER M1 ;
		RECT 0.155 4.585 0.52 5.21 ;
		LAYER M1 ;
		RECT 2.09 4.84 2.43 5.865 ;
		LAYER M1 ;
		RECT 4.05 5.475 4.39 6.315 ;
		LAYER M1 ;
		RECT 4.77 5.475 5.11 6.315 ;
		LAYER M1 ;
		RECT 7.24 6.32 7.58 6.43 ;
		LAYER M1 ;
		RECT 6.72 6.09 7.58 6.32 ;
		LAYER M1 ;
		RECT 6.72 5.705 7.06 6.09 ;
		LAYER M1 ;
		RECT 5.97 5.475 7.06 5.705 ;
		LAYER M1 ;
		RECT 4.05 4.84 4.28 5.475 ;
		LAYER M1 ;
		RECT 2.09 4.61 4.28 4.84 ;
		LAYER M1 ;
		RECT 2.09 4.585 2.43 4.61 ;
		LAYER M1 ;
		RECT 0.155 2.57 0.385 4.585 ;
		LAYER M1 ;
		RECT 2.325 3.39 2.665 3.73 ;
		LAYER M1 ;
		RECT 1.18 2.57 1.52 2.625 ;
		LAYER M1 ;
		RECT 2.34 2.57 2.57 3.39 ;
		LAYER M1 ;
		RECT 0.155 2.34 2.57 2.57 ;
		LAYER M1 ;
		RECT 0.155 2.03 0.385 2.34 ;
		LAYER M1 ;
		RECT 1.18 2.285 1.52 2.34 ;
		LAYER M1 ;
		RECT 4.05 2.225 4.28 4.61 ;
		LAYER M1 ;
		RECT 4.795 3.265 5.025 5.475 ;
		LAYER M1 ;
		RECT 5.97 4.425 6.2 5.475 ;
		LAYER M1 ;
		RECT 9.45 6.56 9.79 6.67 ;
		LAYER M1 ;
		RECT 9.45 6.33 10.125 6.56 ;
		LAYER M1 ;
		RECT 8.53 5.075 8.87 5.915 ;
		LAYER M1 ;
		RECT 9.25 5.075 9.59 5.915 ;
		LAYER M1 ;
		RECT 6.57 4.86 6.91 4.865 ;
		LAYER M1 ;
		RECT 8.53 4.86 8.85 5.075 ;
		LAYER M1 ;
		RECT 6.57 4.63 8.85 4.86 ;
		LAYER M1 ;
		RECT 6.57 4.525 6.91 4.63 ;
		LAYER M1 ;
		RECT 5.895 4.085 6.235 4.425 ;
		LAYER M1 ;
		RECT 5.4 3.265 5.74 3.27 ;
		LAYER M1 ;
		RECT 4.615 3.035 5.74 3.265 ;
		LAYER M1 ;
		RECT 4.555 2.695 4.895 3.035 ;
		LAYER M1 ;
		RECT 5.4 2.93 5.74 3.035 ;
		LAYER M1 ;
		RECT 5.135 2.445 5.475 2.555 ;
		LAYER M1 ;
		RECT 5.97 2.445 6.2 4.085 ;
		LAYER M1 ;
		RECT 7.87 4.06 8.39 4.4 ;
		LAYER M1 ;
		RECT 4.555 2.225 4.895 2.315 ;
		LAYER M1 ;
		RECT 4.05 2.03 4.895 2.225 ;
		LAYER M1 ;
		RECT 5.135 2.215 6.2 2.445 ;
		LAYER M1 ;
		RECT 0.155 1.755 0.52 2.03 ;
		LAYER M1 ;
		RECT 0.18 1.65 0.52 1.755 ;
		LAYER M1 ;
		RECT 2.09 1.995 4.895 2.03 ;
		LAYER M1 ;
		RECT 2.09 1.8 4.28 1.995 ;
		LAYER M1 ;
		RECT 4.555 1.975 4.895 1.995 ;
		LAYER M1 ;
		RECT 2.09 1.19 2.43 1.8 ;
		LAYER M1 ;
		RECT 5.18 1.08 5.41 2.215 ;
		LAYER M1 ;
		RECT 5.82 1.975 6.2 2.215 ;
		LAYER M1 ;
		RECT 7.87 2.88 8.1 4.06 ;
		LAYER M1 ;
		RECT 7 2.65 8.1 2.88 ;
		LAYER M1 ;
		RECT 7 2.505 7.44 2.65 ;
		LAYER M1 ;
		RECT 7 1.84 7.23 2.505 ;
		LAYER M1 ;
		RECT 7.8 2.355 8.14 2.415 ;
		LAYER M1 ;
		RECT 8.62 2.355 8.85 4.63 ;
		LAYER M1 ;
		RECT 9.36 3.95 9.59 5.075 ;
		LAYER M1 ;
		RECT 9.25 3.61 9.59 3.95 ;
		LAYER M1 ;
		RECT 7.8 2.305 8.875 2.355 ;
		LAYER M1 ;
		RECT 9.36 2.315 9.59 3.61 ;
		LAYER M1 ;
		RECT 9.895 5.74 10.125 6.33 ;
		LAYER M1 ;
		RECT 9.895 4.9 10.29 5.74 ;
		LAYER M1 ;
		RECT 11.39 5.13 11.73 5.74 ;
		LAYER M1 ;
		RECT 11.39 4.9 12.885 5.13 ;
		LAYER M1 ;
		RECT 9.895 2.965 10.125 4.9 ;
		LAYER M1 ;
		RECT 11.39 4.62 11.62 4.9 ;
		LAYER M1 ;
		RECT 10.43 4.39 11.62 4.62 ;
		LAYER M1 ;
		RECT 10.43 4.28 10.77 4.39 ;
		LAYER M1 ;
		RECT 12.03 4.19 12.37 4.53 ;
		LAYER M1 ;
		RECT 10.355 3.84 10.695 3.95 ;
		LAYER M1 ;
		RECT 12.05 3.84 12.28 4.19 ;
		LAYER M1 ;
		RECT 10.355 3.61 12.28 3.84 ;
		LAYER M1 ;
		RECT 9.895 2.735 10.51 2.965 ;
		LAYER M1 ;
		RECT 12.05 2.805 12.28 3.61 ;
		LAYER M1 ;
		RECT 12.655 3.635 12.885 4.9 ;
		LAYER M1 ;
		RECT 13.31 3.635 13.65 3.69 ;
		LAYER M1 ;
		RECT 12.655 3.405 13.65 3.635 ;
		LAYER M1 ;
		RECT 7.8 2.125 9.03 2.305 ;
		LAYER M1 ;
		RECT 7.8 2.075 8.14 2.125 ;
		LAYER M1 ;
		RECT 8.62 2.075 9.03 2.125 ;
		LAYER M1 ;
		RECT 9.36 2.085 9.79 2.315 ;
		LAYER M1 ;
		RECT 8.8 1.84 9.03 2.075 ;
		LAYER M1 ;
		RECT 9.56 1.84 9.79 2.085 ;
		LAYER M1 ;
		RECT 6.89 1.5 7.23 1.84 ;
		LAYER M1 ;
		RECT 5.18 0.74 5.585 1.08 ;
		LAYER M1 ;
		RECT 8.8 1.46 9.14 1.84 ;
		LAYER M1 ;
		RECT 9.56 1.5 9.9 1.84 ;
		LAYER M1 ;
		RECT 10.28 1.755 10.51 2.735 ;
		LAYER M1 ;
		RECT 11.715 2.675 12.28 2.805 ;
		LAYER M1 ;
		RECT 11.715 2.575 12.495 2.675 ;
		LAYER M1 ;
		RECT 11.715 2.465 12.58 2.575 ;
		LAYER M1 ;
		RECT 12.05 2.445 12.58 2.465 ;
		LAYER M1 ;
		RECT 10.76 2.215 11.1 2.325 ;
		LAYER M1 ;
		RECT 12.24 2.235 12.58 2.445 ;
		LAYER M1 ;
		RECT 10.76 1.985 11.99 2.215 ;
		LAYER M1 ;
		RECT 11.76 1.8 11.99 1.985 ;
		LAYER M1 ;
		RECT 12.82 1.8 13.05 3.405 ;
		LAYER M1 ;
		RECT 13.31 3.35 13.65 3.405 ;
		LAYER M1 ;
		RECT 10.28 1.375 10.62 1.755 ;
		LAYER M1 ;
		RECT 11.76 1.57 13.05 1.8 ;
		LAYER M1 ;
		RECT 11.76 1.215 12.1 1.57 ;
	END
END MMI_FFHB
MACRO MMI_FFMB
	CLASS CORE ;
	FOREIGN MMI_FFMB 0 0 ;
	SIZE 14.06 BY 7.4 ;
	SYMMETRY X Y ;
	SITE CORE1 ;
	PIN d0
		DIRECTION input ;
		USE SIGNAL ;
		PORT
			LAYER M1 ;
			RECT 1.625 3.105 2.075 3.555 ;
		END
		AntennaGateArea 0.4968 ;
	END d0
	PIN sel
		DIRECTION input ;
		USE SIGNAL ;
		PORT
			LAYER M1 ;
			RECT 1.44 4.265 1.78 4.275 ;
			LAYER M1 ;
			RECT 0.97 4.035 4.08 4.265 ;
			LAYER M1 ;
			RECT 0.97 3.555 1.2 4.035 ;
			LAYER M1 ;
			RECT 1.44 3.935 1.78 4.035 ;
			LAYER M1 ;
			RECT 0.875 3.105 1.325 3.555 ;
			LAYER M1 ;
			RECT 3.85 2.72 4.08 4.035 ;
			LAYER M1 ;
			RECT 3.74 2.38 4.08 2.72 ;
		END
		AntennaGateArea 0.7452 ;
	END sel
	PIN GND
		DIRECTION inout ;
		USE GROUND ;
		PORT
			LAYER M1 ;
			RECT 1.2 1.34 1.54 2.18 ;
			LAYER M1 ;
			RECT 4.09 1.345 4.43 1.685 ;
			LAYER M1 ;
			RECT 1.31 0.5 1.54 1.34 ;
			LAYER M1 ;
			RECT 4.2 0.5 4.43 1.345 ;
			LAYER M1 ;
			RECT 5.545 0.51 5.885 1.75 ;
			LAYER M1 ;
			RECT 5.485 0.5 5.885 0.51 ;
			LAYER M1 ;
			RECT 8.565 0.5 8.905 2.105 ;
			LAYER M1 ;
			RECT 10.885 1.015 11.425 1.355 ;
			LAYER M1 ;
			RECT 10.995 0.5 11.335 1.015 ;
			LAYER M1 ;
			RECT 12.82 0.5 13.16 2.775 ;
			LAYER M1 ;
			RECT 0 -0.5 14.06 0.5 ;
		END
	END GND
	PIN q
		DIRECTION output ;
		USE SIGNAL ;
		PORT
			LAYER M1 ;
			RECT 13.54 1.935 13.88 6.24 ;
		END
		AntennaDiffArea 1.3248 ;
	END q
	PIN d1
		DIRECTION input ;
		USE SIGNAL ;
		PORT
			LAYER M1 ;
			RECT 2.365 3.485 2.815 3.555 ;
			LAYER M1 ;
			RECT 2.365 3.145 2.88 3.485 ;
			LAYER M1 ;
			RECT 2.365 3.105 2.815 3.145 ;
		END
		AntennaGateArea 0.4968 ;
	END d1
	PIN VDD
		DIRECTION inout ;
		USE POWER ;
		PORT
			LAYER M1 ;
			RECT 0 6.9 14.06 7.9 ;
			LAYER M1 ;
			RECT 1.2 4.585 1.54 6.9 ;
			LAYER M1 ;
			RECT 3.5 5.075 3.84 6.9 ;
			LAYER M1 ;
			RECT 6.26 5.975 6.6 6.9 ;
			LAYER M1 ;
			RECT 8.07 5.105 8.41 6.9 ;
			LAYER M1 ;
			RECT 10.21 4.48 10.55 6.9 ;
			LAYER M1 ;
			RECT 12.82 4.48 13.16 6.9 ;
		END
	END VDD
	PIN clk
		DIRECTION input ;
		USE CLOCK ;
		PORT
			LAYER M1 ;
			RECT 7.5 4.29 7.84 4.4 ;
			LAYER M1 ;
			RECT 6.805 4.06 7.84 4.29 ;
			LAYER M1 ;
			RECT 6.805 3.84 7.255 4.06 ;
			LAYER M1 ;
			RECT 6.915 2.435 7.145 3.84 ;
			LAYER M1 ;
			RECT 9.475 3.475 9.815 3.55 ;
			LAYER M1 ;
			RECT 10.99 3.475 11.33 3.565 ;
			LAYER M1 ;
			RECT 9.475 3.245 11.33 3.475 ;
			LAYER M1 ;
			RECT 9.475 3.21 9.815 3.245 ;
			LAYER M1 ;
			RECT 10.99 3.225 11.33 3.245 ;
			LAYER M1 ;
			RECT 6.805 2.095 7.145 2.435 ;
		END
		AntennaGateArea 0.6408 ;
	END clk
	OBS
		LAYER M1 ;
		RECT 0.44 5.21 0.78 5.425 ;
		LAYER M1 ;
		RECT 0.415 4.585 0.78 5.21 ;
		LAYER M1 ;
		RECT 2.35 4.84 2.69 5.865 ;
		LAYER M1 ;
		RECT 4.31 5.475 4.65 6.315 ;
		LAYER M1 ;
		RECT 5.03 5.475 5.37 6.315 ;
		LAYER M1 ;
		RECT 7.5 6.32 7.84 6.43 ;
		LAYER M1 ;
		RECT 6.98 6.09 7.84 6.32 ;
		LAYER M1 ;
		RECT 6.98 5.705 7.32 6.09 ;
		LAYER M1 ;
		RECT 6.345 5.475 7.32 5.705 ;
		LAYER M1 ;
		RECT 4.31 4.84 4.54 5.475 ;
		LAYER M1 ;
		RECT 5.07 5.225 5.3 5.475 ;
		LAYER M1 ;
		RECT 2.35 4.61 4.54 4.84 ;
		LAYER M1 ;
		RECT 2.35 4.585 2.69 4.61 ;
		LAYER M1 ;
		RECT 0.415 2.72 0.645 4.585 ;
		LAYER M1 ;
		RECT 3.225 3.135 3.565 3.475 ;
		LAYER M1 ;
		RECT 1.44 2.72 1.78 2.8 ;
		LAYER M1 ;
		RECT 3.225 2.72 3.455 3.135 ;
		LAYER M1 ;
		RECT 0.415 2.49 3.455 2.72 ;
		LAYER M1 ;
		RECT 0.415 2.18 0.645 2.49 ;
		LAYER M1 ;
		RECT 1.44 2.46 1.78 2.49 ;
		LAYER M1 ;
		RECT 4.31 2.435 4.54 4.61 ;
		LAYER M1 ;
		RECT 4.845 4.995 5.3 5.225 ;
		LAYER M1 ;
		RECT 4.845 3.21 5.075 4.995 ;
		LAYER M1 ;
		RECT 5.31 4.29 5.65 4.35 ;
		LAYER M1 ;
		RECT 6.345 4.29 6.575 5.475 ;
		LAYER M1 ;
		RECT 8.79 5.075 9.13 5.915 ;
		LAYER M1 ;
		RECT 9.51 5.075 9.85 5.915 ;
		LAYER M1 ;
		RECT 6.83 4.86 7.17 4.865 ;
		LAYER M1 ;
		RECT 8.79 4.86 9.11 5.075 ;
		LAYER M1 ;
		RECT 6.83 4.63 9.11 4.86 ;
		LAYER M1 ;
		RECT 6.83 4.525 7.17 4.63 ;
		LAYER M1 ;
		RECT 5.31 4.06 6.575 4.29 ;
		LAYER M1 ;
		RECT 5.31 4.01 5.65 4.06 ;
		LAYER M1 ;
		RECT 4.815 3.165 5.155 3.21 ;
		LAYER M1 ;
		RECT 5.775 3.165 6.115 3.17 ;
		LAYER M1 ;
		RECT 4.815 2.87 6.115 3.165 ;
		LAYER M1 ;
		RECT 5.775 2.83 6.115 2.87 ;
		LAYER M1 ;
		RECT 4.815 2.435 5.155 2.49 ;
		LAYER M1 ;
		RECT 4.31 2.205 5.155 2.435 ;
		LAYER M1 ;
		RECT 0.415 1.905 0.78 2.18 ;
		LAYER M1 ;
		RECT 0.44 1.8 0.78 1.905 ;
		LAYER M1 ;
		RECT 2.35 2.15 2.69 2.18 ;
		LAYER M1 ;
		RECT 4.31 2.15 4.54 2.205 ;
		LAYER M1 ;
		RECT 4.815 2.15 5.155 2.205 ;
		LAYER M1 ;
		RECT 2.35 1.92 4.54 2.15 ;
		LAYER M1 ;
		RECT 2.35 1.34 2.69 1.92 ;
		LAYER M1 ;
		RECT 6.345 1.75 6.575 4.06 ;
		LAYER M1 ;
		RECT 8.13 4.06 8.65 4.4 ;
		LAYER M1 ;
		RECT 8.13 3.255 8.36 4.06 ;
		LAYER M1 ;
		RECT 7.485 3.025 8.36 3.255 ;
		LAYER M1 ;
		RECT 7.485 2.77 7.825 3.025 ;
		LAYER M1 ;
		RECT 7.485 2.105 7.715 2.77 ;
		LAYER M1 ;
		RECT 8.285 2.57 8.625 2.68 ;
		LAYER M1 ;
		RECT 8.88 2.57 9.11 4.63 ;
		LAYER M1 ;
		RECT 9.62 4.235 9.85 5.075 ;
		LAYER M1 ;
		RECT 10.93 5.315 11.27 5.32 ;
		LAYER M1 ;
		RECT 10.93 5.085 12.495 5.315 ;
		LAYER M1 ;
		RECT 10.93 4.48 11.27 5.085 ;
		LAYER M1 ;
		RECT 11.58 4.48 11.97 4.82 ;
		LAYER M1 ;
		RECT 11.58 4.235 11.92 4.48 ;
		LAYER M1 ;
		RECT 9.62 4.005 11.92 4.235 ;
		LAYER M1 ;
		RECT 10.275 3.895 10.79 4.005 ;
		LAYER M1 ;
		RECT 10.335 2.715 10.675 2.745 ;
		LAYER M1 ;
		RECT 11.58 2.715 11.92 4.005 ;
		LAYER M1 ;
		RECT 8.285 2.34 9.515 2.57 ;
		LAYER M1 ;
		RECT 9.285 2.105 9.515 2.34 ;
		LAYER M1 ;
		RECT 10.105 2.485 11.92 2.715 ;
		LAYER M1 ;
		RECT 10.105 2.405 10.675 2.485 ;
		LAYER M1 ;
		RECT 11.58 2.435 11.92 2.485 ;
		LAYER M1 ;
		RECT 12.265 3.865 12.495 5.085 ;
		LAYER M1 ;
		RECT 12.265 3.525 13.06 3.865 ;
		LAYER M1 ;
		RECT 10.105 2.105 10.335 2.405 ;
		LAYER M1 ;
		RECT 7.375 1.765 7.715 2.105 ;
		LAYER M1 ;
		RECT 6.265 1.37 6.605 1.75 ;
		LAYER M1 ;
		RECT 6.345 1.025 6.575 1.37 ;
		LAYER M1 ;
		RECT 7.97 1.025 8.31 1.07 ;
		LAYER M1 ;
		RECT 6.345 0.795 8.31 1.025 ;
		LAYER M1 ;
		RECT 7.97 0.73 8.31 0.795 ;
		LAYER M1 ;
		RECT 9.285 1.725 9.625 2.105 ;
		LAYER M1 ;
		RECT 10.045 1.765 10.385 2.105 ;
		LAYER M1 ;
		RECT 10.885 2.01 11.425 2.075 ;
		LAYER M1 ;
		RECT 12.265 2.01 12.495 3.525 ;
		LAYER M1 ;
		RECT 10.885 1.78 12.495 2.01 ;
		LAYER M1 ;
		RECT 10.885 1.735 11.425 1.78 ;
	END
END MMI_FFMB
MACRO MMI_FFNCB
	CLASS CORE ;
	FOREIGN MMI_FFNCB 0 0 ;
	SIZE 13.32 BY 7.4 ;
	SYMMETRY X Y ;
	SITE CORE1 ;
	PIN d
		DIRECTION input ;
		USE SIGNAL ;
		PORT
			LAYER M1 ;
			RECT 0.145 3.495 0.595 3.555 ;
			LAYER M1 ;
			RECT 0.145 3.155 0.76 3.495 ;
			LAYER M1 ;
			RECT 0.145 3.105 0.595 3.155 ;
		END
		AntennaGateArea 0.4968 ;
	END d
	PIN GND
		DIRECTION inout ;
		USE GROUND ;
		PORT
			LAYER M1 ;
			RECT 5.1 2.79 6.74 3.02 ;
			LAYER M1 ;
			RECT 5.1 2.56 5.33 2.79 ;
			LAYER M1 ;
			RECT 4.1 2.48 4.48 2.49 ;
			LAYER M1 ;
			RECT 4.99 2.48 5.33 2.56 ;
			LAYER M1 ;
			RECT 1.06 0.5 1.4 2.175 ;
			LAYER M1 ;
			RECT 4.1 2.15 5.33 2.48 ;
			LAYER M1 ;
			RECT 6.51 2.56 6.74 2.79 ;
			LAYER M1 ;
			RECT 6.51 2.18 6.85 2.56 ;
			LAYER M1 ;
			RECT 4.115 2.14 5.33 2.15 ;
			LAYER M1 ;
			RECT 4.115 0.5 4.455 2.14 ;
			LAYER M1 ;
			RECT 7.61 1.605 7.95 1.665 ;
			LAYER M1 ;
			RECT 10.23 1.605 10.57 3.095 ;
			LAYER M1 ;
			RECT 7.61 1.375 10.57 1.605 ;
			LAYER M1 ;
			RECT 7.61 1.325 7.95 1.375 ;
			LAYER M1 ;
			RECT 10.23 0.5 10.57 1.375 ;
			LAYER M1 ;
			RECT 12.08 0.5 12.42 3.105 ;
			LAYER M1 ;
			RECT 0 -0.5 13.32 0.5 ;
		END
	END GND
	PIN q
		DIRECTION output ;
		USE SIGNAL ;
		PORT
			LAYER M1 ;
			RECT 12.8 4.365 13.14 6.125 ;
			LAYER M1 ;
			RECT 12.86 3.555 13.09 4.365 ;
			LAYER M1 ;
			RECT 12.8 2.265 13.14 3.555 ;
		END
		AntennaDiffArea 1.3248 ;
	END q
	PIN VDD
		DIRECTION inout ;
		USE POWER ;
		PORT
			LAYER M1 ;
			RECT 0 6.9 13.32 7.9 ;
			LAYER M1 ;
			RECT 0.18 4.19 0.52 6.9 ;
			LAYER M1 ;
			RECT 3.825 5.015 4.165 6.9 ;
			LAYER M1 ;
			RECT 5.36 6.055 5.7 6.9 ;
			LAYER M1 ;
			RECT 5.36 5.825 7.955 6.055 ;
			LAYER M1 ;
			RECT 5.36 4.79 5.7 5.825 ;
			LAYER M1 ;
			RECT 7.615 5.495 7.955 5.825 ;
			LAYER M1 ;
			RECT 10.38 4.91 10.72 6.9 ;
			LAYER M1 ;
			RECT 12.08 4.365 12.42 6.9 ;
		END
	END VDD
	PIN clk
		DIRECTION input ;
		USE CLOCK ;
		PORT
			LAYER M1 ;
			RECT 7.045 4.325 7.385 4.555 ;
			LAYER M1 ;
			RECT 4.64 4.255 7.385 4.325 ;
			LAYER M1 ;
			RECT 4.3 4.215 7.385 4.255 ;
			LAYER M1 ;
			RECT 4.3 4.095 7.375 4.215 ;
			LAYER M1 ;
			RECT 4.3 3.915 5.04 4.095 ;
			LAYER M1 ;
			RECT 4.64 3.88 5.04 3.915 ;
		END
		AntennaGateArea 0.6408 ;
	END clk
	PIN clrb
		DIRECTION input ;
		USE SIGNAL ;
		PORT
			LAYER M1 ;
			RECT 1.58 3.215 2.075 3.555 ;
			LAYER M1 ;
			RECT 1.625 3.105 2.075 3.215 ;
			LAYER M1 ;
			RECT 4.695 1.055 5.035 1.07 ;
			LAYER M1 ;
			RECT 9.66 1.055 10 1.12 ;
			LAYER M1 ;
			RECT 4.695 0.825 10 1.055 ;
			LAYER M1 ;
			RECT 4.695 0.73 5.035 0.825 ;
			LAYER M1 ;
			RECT 9.66 0.78 10 0.825 ;
		END
		AntennaGateArea 0.7128 ;
	END clrb
	OBS
		LAYER M1 ;
		RECT 0.9 5.785 1.24 5.95 ;
		LAYER M1 ;
		RECT 1.685 5.785 2.025 6.25 ;
		LAYER M1 ;
		RECT 0.9 5.555 2.025 5.785 ;
		LAYER M1 ;
		RECT 0.9 4.685 1.24 5.555 ;
		LAYER M1 ;
		RECT 1.685 5.41 2.025 5.555 ;
		LAYER M1 ;
		RECT 2.405 5.41 2.745 6.25 ;
		LAYER M1 ;
		RECT 2.515 5.05 2.745 5.41 ;
		LAYER M1 ;
		RECT 0.9 4.19 1.27 4.685 ;
		LAYER M1 ;
		RECT 2.515 4.54 2.82 5.05 ;
		LAYER M1 ;
		RECT 3.105 5.015 3.445 6.135 ;
		LAYER M1 ;
		RECT 4.79 6.34 5.13 6.375 ;
		LAYER M1 ;
		RECT 4.695 6.035 5.13 6.34 ;
		LAYER M1 ;
		RECT 6.7 6.61 7.04 6.67 ;
		LAYER M1 ;
		RECT 6.7 6.38 9.77 6.61 ;
		LAYER M1 ;
		RECT 6.7 6.33 7.04 6.38 ;
		LAYER M1 ;
		RECT 4.695 5.85 4.925 6.035 ;
		LAYER M1 ;
		RECT 0.96 3.825 1.27 4.19 ;
		LAYER M1 ;
		RECT 1.04 2.875 1.27 3.825 ;
		LAYER M1 ;
		RECT 2.59 2.875 2.82 4.54 ;
		LAYER M1 ;
		RECT 3.215 3.925 3.445 5.015 ;
		LAYER M1 ;
		RECT 4.585 4.785 4.925 5.85 ;
		LAYER M1 ;
		RECT 9.43 5.985 9.77 6.38 ;
		LAYER M1 ;
		RECT 6.51 5.255 7.385 5.595 ;
		LAYER M1 ;
		RECT 8.425 5.255 8.765 5.75 ;
		LAYER M1 ;
		RECT 6.51 5.025 8.765 5.255 ;
		LAYER M1 ;
		RECT 6.51 4.785 6.85 5.025 ;
		LAYER M1 ;
		RECT 8.425 4.91 8.765 5.025 ;
		LAYER M1 ;
		RECT 9.145 4.91 9.485 5.75 ;
		LAYER M1 ;
		RECT 11.1 4.91 11.44 5.75 ;
		LAYER M1 ;
		RECT 3.84 4.555 4.925 4.785 ;
		LAYER M1 ;
		RECT 3.215 3.51 3.61 3.925 ;
		LAYER M1 ;
		RECT 0.45 2.645 2.25 2.875 ;
		LAYER M1 ;
		RECT 0.45 2.175 0.68 2.645 ;
		LAYER M1 ;
		RECT 1.91 2.535 2.25 2.645 ;
		LAYER M1 ;
		RECT 2.59 2.535 2.97 2.875 ;
		LAYER M1 ;
		RECT 0.34 1.335 0.68 2.175 ;
		LAYER M1 ;
		RECT 2.59 1.95 2.82 2.535 ;
		LAYER M1 ;
		RECT 3.38 2.21 3.61 3.51 ;
		LAYER M1 ;
		RECT 3.84 3.58 4.07 4.555 ;
		LAYER M1 ;
		RECT 7.615 4.345 7.955 4.685 ;
		LAYER M1 ;
		RECT 7.67 4.055 7.9 4.345 ;
		LAYER M1 ;
		RECT 7.67 3.715 8.065 4.055 ;
		LAYER M1 ;
		RECT 3.84 3.385 7.385 3.58 ;
		LAYER M1 ;
		RECT 3.84 3.35 7.42 3.385 ;
		LAYER M1 ;
		RECT 4.1 2.87 4.48 3.35 ;
		LAYER M1 ;
		RECT 7.08 3.045 7.42 3.35 ;
		LAYER M1 ;
		RECT 7.67 2.815 7.9 3.715 ;
		LAYER M1 ;
		RECT 8.425 3.095 8.655 4.91 ;
		LAYER M1 ;
		RECT 9.255 4.515 9.485 4.91 ;
		LAYER M1 ;
		RECT 9.145 4.285 9.485 4.515 ;
		LAYER M1 ;
		RECT 11.21 4.515 11.44 4.91 ;
		LAYER M1 ;
		RECT 11.21 4.285 11.76 4.515 ;
		LAYER M1 ;
		RECT 9.145 4.005 9.375 4.285 ;
		LAYER M1 ;
		RECT 10.96 4.005 11.3 4.055 ;
		LAYER M1 ;
		RECT 9.145 3.775 11.3 4.005 ;
		LAYER M1 ;
		RECT 9.145 3.095 9.375 3.775 ;
		LAYER M1 ;
		RECT 10.96 3.715 11.3 3.775 ;
		LAYER M1 ;
		RECT 11.53 3.735 11.76 4.285 ;
		LAYER M1 ;
		RECT 12.14 3.735 12.48 3.78 ;
		LAYER M1 ;
		RECT 11.53 3.505 12.48 3.735 ;
		LAYER M1 ;
		RECT 11.53 3.095 11.76 3.505 ;
		LAYER M1 ;
		RECT 12.14 3.44 12.48 3.505 ;
		LAYER M1 ;
		RECT 1.82 1.38 2.16 1.855 ;
		LAYER M1 ;
		RECT 2.59 1.71 3.15 1.95 ;
		LAYER M1 ;
		RECT 2.81 1.61 3.15 1.71 ;
		LAYER M1 ;
		RECT 3.38 1.87 3.855 2.21 ;
		LAYER M1 ;
		RECT 5.71 2.18 6.05 2.56 ;
		LAYER M1 ;
		RECT 7.61 2.475 7.95 2.815 ;
		LAYER M1 ;
		RECT 8.315 2.755 8.655 3.095 ;
		LAYER M1 ;
		RECT 9.035 2.755 9.375 3.095 ;
		LAYER M1 ;
		RECT 3.38 1.38 3.61 1.87 ;
		LAYER M1 ;
		RECT 1.82 1.15 3.61 1.38 ;
		LAYER M1 ;
		RECT 5.815 1.93 6.045 2.18 ;
		LAYER M1 ;
		RECT 8.4 2.13 8.63 2.755 ;
		LAYER M1 ;
		RECT 7.08 1.93 8.63 2.13 ;
		LAYER M1 ;
		RECT 5.815 1.9 8.63 1.93 ;
		LAYER M1 ;
		RECT 5.815 1.7 7.38 1.9 ;
		LAYER M1 ;
		RECT 7.04 1.565 7.38 1.7 ;
		LAYER M1 ;
		RECT 11.38 2.715 11.76 3.095 ;
		LAYER M1 ;
		RECT 11.38 1.935 11.72 2.715 ;
	END
END MMI_FFNCB
MACRO MMI_FFSB
	CLASS CORE ;
	FOREIGN MMI_FFSB 0 0 ;
	SIZE 12.58 BY 7.4 ;
	SYMMETRY X Y ;
	SITE CORE1 ;
	PIN d
		DIRECTION input ;
		USE SIGNAL ;
		PORT
			LAYER M1 ;
			RECT 0.19 3.465 0.64 3.555 ;
			LAYER M1 ;
			RECT 0.19 3.125 0.95 3.465 ;
			LAYER M1 ;
			RECT 0.19 3.105 0.64 3.125 ;
		END
		AntennaGateArea 0.4968 ;
	END d
	PIN GND
		DIRECTION inout ;
		USE GROUND ;
		PORT
			LAYER M1 ;
			RECT 0.42 1.97 0.76 2.81 ;
			LAYER M1 ;
			RECT 4.975 2.31 5.315 3.15 ;
			LAYER M1 ;
			RECT 5.085 2.165 5.315 2.31 ;
			LAYER M1 ;
			RECT 0.47 0.5 0.7 1.97 ;
			LAYER M1 ;
			RECT 5.085 1.935 6.12 2.165 ;
			LAYER M1 ;
			RECT 8.555 2.065 8.895 2.405 ;
			LAYER M1 ;
			RECT 5.89 1.705 6.12 1.935 ;
			LAYER M1 ;
			RECT 1.21 0.5 1.55 1.57 ;
			LAYER M1 ;
			RECT 5.89 0.5 6.23 1.705 ;
			LAYER M1 ;
			RECT 8.575 0.5 8.805 2.065 ;
			LAYER M1 ;
			RECT 11.3 1.965 11.64 2.805 ;
			LAYER M1 ;
			RECT 9.98 0.5 10.32 1.275 ;
			LAYER M1 ;
			RECT 11.36 0.5 11.64 1.965 ;
			LAYER M1 ;
			RECT 0 -0.5 12.58 0.5 ;
		END
	END GND
	PIN q
		DIRECTION output ;
		USE SIGNAL ;
		PORT
			LAYER M1 ;
			RECT 11.795 4.71 12.135 6.13 ;
			LAYER M1 ;
			RECT 11.795 4.37 12.36 4.71 ;
			LAYER M1 ;
			RECT 12.02 1.965 12.36 4.37 ;
		END
		AntennaDiffArea 1.3248 ;
	END q
	PIN VDD
		DIRECTION inout ;
		USE POWER ;
		PORT
			LAYER M1 ;
			RECT 0 6.9 12.58 7.9 ;
			LAYER M1 ;
			RECT 0.19 4.2 0.53 6.9 ;
			LAYER M1 ;
			RECT 1.515 6.895 1.96 6.9 ;
			LAYER M1 ;
			RECT 1.62 5.655 1.96 6.895 ;
			LAYER M1 ;
			RECT 3.825 4.43 4.165 6.9 ;
			LAYER M1 ;
			RECT 5.265 4.43 5.605 6.9 ;
			LAYER M1 ;
			RECT 9.185 4.185 9.525 6.9 ;
			LAYER M1 ;
			RECT 11.075 4.37 11.415 6.9 ;
		END
	END VDD
	PIN setb
		DIRECTION input ;
		USE SIGNAL ;
		PORT
			LAYER M1 ;
			RECT 4.745 3.64 5.085 3.735 ;
			LAYER M1 ;
			RECT 4.745 3.41 6.515 3.64 ;
			LAYER M1 ;
			RECT 4.745 3.395 5.085 3.41 ;
			LAYER M1 ;
			RECT 6.015 3.125 6.515 3.41 ;
			LAYER M1 ;
			RECT 6.015 3.075 6.355 3.125 ;
		END
		AntennaGateArea 0.6552 ;
	END setb
	PIN clk
		DIRECTION input ;
		USE CLOCK ;
		PORT
			LAYER M1 ;
			RECT 1.64 3.495 2.09 3.555 ;
			LAYER M1 ;
			RECT 1.64 3.155 2.235 3.495 ;
			LAYER M1 ;
			RECT 1.64 3.105 2.09 3.155 ;
		END
		AntennaGateArea 0.6408 ;
	END clk
	OBS
		LAYER M1 ;
		RECT 0.91 4.47 1.25 5.96 ;
		LAYER M1 ;
		RECT 2.39 6.495 3.215 6.555 ;
		LAYER M1 ;
		RECT 2.34 6.215 3.215 6.495 ;
		LAYER M1 ;
		RECT 2.34 5.655 2.68 6.215 ;
		LAYER M1 ;
		RECT 1.62 4.47 1.96 5.27 ;
		LAYER M1 ;
		RECT 0.91 4.24 1.96 4.47 ;
		LAYER M1 ;
		RECT 2.34 4.43 2.68 5.27 ;
		LAYER M1 ;
		RECT 0.91 4.2 1.41 4.24 ;
		LAYER M1 ;
		RECT 1.18 2.81 1.41 4.2 ;
		LAYER M1 ;
		RECT 2.45 4.015 2.68 4.43 ;
		LAYER M1 ;
		RECT 2.985 4.475 3.215 6.215 ;
		LAYER M1 ;
		RECT 2.985 4.245 3.49 4.475 ;
		LAYER M1 ;
		RECT 4.555 5.85 4.895 6.19 ;
		LAYER M1 ;
		RECT 4.61 5.27 4.84 5.85 ;
		LAYER M1 ;
		RECT 4.545 4.43 4.885 5.27 ;
		LAYER M1 ;
		RECT 6.095 5.98 8.55 6.21 ;
		LAYER M1 ;
		RECT 6.095 5.55 6.325 5.98 ;
		LAYER M1 ;
		RECT 5.985 4.43 6.325 5.55 ;
		LAYER M1 ;
		RECT 6.685 4.695 7.025 5.535 ;
		LAYER M1 ;
		RECT 7.405 4.695 7.745 5.535 ;
		LAYER M1 ;
		RECT 2.45 3.82 2.965 4.015 ;
		LAYER M1 ;
		RECT 2.45 3.785 3.03 3.82 ;
		LAYER M1 ;
		RECT 2.69 3.48 3.03 3.785 ;
		LAYER M1 ;
		RECT 1.14 2.5 1.48 2.81 ;
		LAYER M1 ;
		RECT 1.13 2.27 2.31 2.5 ;
		LAYER M1 ;
		RECT 2.735 2.27 2.965 3.48 ;
		LAYER M1 ;
		RECT 1.14 1.97 1.48 2.27 ;
		LAYER M1 ;
		RECT 1.97 1.93 2.31 2.27 ;
		LAYER M1 ;
		RECT 2.69 1.93 3.03 2.27 ;
		LAYER M1 ;
		RECT 3.26 1.57 3.49 4.245 ;
		LAYER M1 ;
		RECT 4.545 4.195 4.775 4.43 ;
		LAYER M1 ;
		RECT 6.75 4.195 6.98 4.695 ;
		LAYER M1 ;
		RECT 3.935 3.965 6.98 4.195 ;
		LAYER M1 ;
		RECT 3.935 3.15 4.165 3.965 ;
		LAYER M1 ;
		RECT 3.825 2.31 4.165 3.15 ;
		LAYER M1 ;
		RECT 5.61 2.635 5.95 2.735 ;
		LAYER M1 ;
		RECT 6.75 2.635 6.98 3.965 ;
		LAYER M1 ;
		RECT 5.61 2.405 6.98 2.635 ;
		LAYER M1 ;
		RECT 7.41 3.375 7.64 4.695 ;
		LAYER M1 ;
		RECT 8.32 3.95 8.55 5.98 ;
		LAYER M1 ;
		RECT 10.335 4.18 10.675 5.94 ;
		LAYER M1 ;
		RECT 8.32 3.72 9.765 3.95 ;
		LAYER M1 ;
		RECT 9.425 3.61 9.765 3.72 ;
		LAYER M1 ;
		RECT 8.755 3.375 9.095 3.47 ;
		LAYER M1 ;
		RECT 7.41 3.145 9.095 3.375 ;
		LAYER M1 ;
		RECT 7.41 2.405 7.64 3.145 ;
		LAYER M1 ;
		RECT 8.755 3.13 9.095 3.145 ;
		LAYER M1 ;
		RECT 9.475 2.895 9.705 3.61 ;
		LAYER M1 ;
		RECT 7.94 2.725 9.705 2.895 ;
		LAYER M1 ;
		RECT 10.435 3.375 10.665 4.18 ;
		LAYER M1 ;
		RECT 11.375 3.375 11.715 3.445 ;
		LAYER M1 ;
		RECT 10.435 3.145 11.715 3.375 ;
		LAYER M1 ;
		RECT 7.94 2.665 9.815 2.725 ;
		LAYER M1 ;
		RECT 5.61 2.395 5.95 2.405 ;
		LAYER M1 ;
		RECT 6.65 2.065 6.99 2.405 ;
		LAYER M1 ;
		RECT 7.37 2.065 7.71 2.405 ;
		LAYER M1 ;
		RECT 1.93 1.34 3.49 1.57 ;
		LAYER M1 ;
		RECT 4.7 1.565 5.04 1.705 ;
		LAYER M1 ;
		RECT 1.93 1.19 2.79 1.34 ;
		LAYER M1 ;
		RECT 4.18 1.335 5.04 1.565 ;
		LAYER M1 ;
		RECT 4.18 1.225 4.52 1.335 ;
		LAYER M1 ;
		RECT 6.61 1.575 6.95 1.705 ;
		LAYER M1 ;
		RECT 7.94 1.575 8.17 2.665 ;
		LAYER M1 ;
		RECT 9.475 2.385 9.815 2.665 ;
		LAYER M1 ;
		RECT 6.61 1.345 8.175 1.575 ;
		LAYER M1 ;
		RECT 6.61 1.185 6.95 1.345 ;
		LAYER M1 ;
		RECT 9.065 1.755 9.405 1.83 ;
		LAYER M1 ;
		RECT 10.435 1.755 10.665 3.145 ;
		LAYER M1 ;
		RECT 11.375 3.105 11.715 3.145 ;
		LAYER M1 ;
		RECT 9.065 1.525 10.95 1.755 ;
		LAYER M1 ;
		RECT 9.065 1.49 9.49 1.525 ;
		LAYER M1 ;
		RECT 9.26 1.275 9.49 1.49 ;
		LAYER M1 ;
		RECT 10.72 1.275 10.95 1.525 ;
		LAYER M1 ;
		RECT 9.26 0.735 9.6 1.275 ;
		LAYER M1 ;
		RECT 10.7 0.735 11.04 1.275 ;
	END
END MMI_FFSB
MACRO MMI_FILL_1
	CLASS CORE ;
	FOREIGN MMI_FILL_1 0 0 ;
	SIZE 0.74 BY 7.4 ;
	SYMMETRY X Y ;
	SITE CORE1 ;
	PIN GND
		DIRECTION inout ;
		USE GROUND ;
		PORT
			LAYER M1 ;
			RECT 0 -0.5 0.74 0.5 ;
		END
	END GND
	PIN VDD
		DIRECTION inout ;
		USE POWER ;
		PORT
			LAYER M1 ;
			RECT 0 6.9 0.74 7.9 ;
		END
	END VDD
	OBS
	END
END MMI_FILL_1
MACRO MMI_FILL_2
	CLASS CORE ;
	FOREIGN MMI_FILL_2 0 0 ;
	SIZE 1.48 BY 7.4 ;
	SYMMETRY X Y ;
	SITE CORE1 ;
	PIN GND
		DIRECTION inout ;
		USE GROUND ;
		PORT
			LAYER M1 ;
			RECT 0 -0.5 1.48 0.5 ;
		END
	END GND
	PIN VDD
		DIRECTION inout ;
		USE POWER ;
		PORT
			LAYER M1 ;
			RECT 0 6.9 1.48 7.9 ;
		END
	END VDD
	OBS
	END
END MMI_FILL_2
MACRO MMI_FILL_4
	CLASS CORE ;
	FOREIGN MMI_FILL_4 0 0 ;
	SIZE 2.96 BY 7.4 ;
	SYMMETRY X Y ;
	SITE CORE1 ;
	PIN GND
		DIRECTION inout ;
		USE GROUND ;
		PORT
			LAYER M1 ;
			RECT 0.22 0.5 0.56 3.05 ;
			LAYER M1 ;
			RECT 0.94 0.5 1.28 4.12 ;
			LAYER M1 ;
			RECT 1.66 0.5 2 3.05 ;
			LAYER M1 ;
			RECT 2.38 0.5 2.72 3.05 ;
			LAYER M1 ;
			RECT 0 -0.5 2.96 0.5 ;
		END
	END GND
	PIN VDD
		DIRECTION inout ;
		USE POWER ;
		PORT
			LAYER M1 ;
			RECT 0 6.9 2.96 7.9 ;
			LAYER M1 ;
			RECT 0.22 4.35 0.56 6.9 ;
			LAYER M1 ;
			RECT 0.94 4.35 1.28 6.9 ;
			LAYER M1 ;
			RECT 1.66 3.38 2 6.9 ;
			LAYER M1 ;
			RECT 2.38 4.35 2.72 6.9 ;
		END
	END VDD
	OBS
	END
END MMI_FILL_4
MACRO MMI_FILL_8
	CLASS CORE ;
	FOREIGN MMI_FILL_8 0 0 ;
	SIZE 5.92 BY 7.4 ;
	SYMMETRY X Y ;
	SITE CORE1 ;
	PIN GND
		DIRECTION inout ;
		USE GROUND ;
		PORT
			LAYER M1 ;
			RECT 0.22 0.5 0.56 3.05 ;
			LAYER M1 ;
			RECT 0.94 0.5 1.28 4.12 ;
			LAYER M1 ;
			RECT 1.66 0.5 2 3.05 ;
			LAYER M1 ;
			RECT 2.38 0.5 2.72 3.05 ;
			LAYER M1 ;
			RECT 3.1 0.5 3.44 3.05 ;
			LAYER M1 ;
			RECT 3.82 0.5 4.16 4.12 ;
			LAYER M1 ;
			RECT 4.54 0.5 4.88 3.05 ;
			LAYER M1 ;
			RECT 5.26 0.5 5.6 3.05 ;
			LAYER M1 ;
			RECT 0 -0.5 5.92 0.5 ;
		END
	END GND
	PIN VDD
		DIRECTION inout ;
		USE POWER ;
		PORT
			LAYER M1 ;
			RECT 0 6.9 5.92 7.9 ;
			LAYER M1 ;
			RECT 0.22 4.35 0.56 6.9 ;
			LAYER M1 ;
			RECT 0.94 4.35 1.28 6.9 ;
			LAYER M1 ;
			RECT 1.66 3.38 2 6.9 ;
			LAYER M1 ;
			RECT 2.38 4.35 2.72 6.9 ;
			LAYER M1 ;
			RECT 3.1 4.35 3.44 6.9 ;
			LAYER M1 ;
			RECT 3.82 4.35 4.16 6.9 ;
			LAYER M1 ;
			RECT 4.54 3.38 4.88 6.9 ;
			LAYER M1 ;
			RECT 5.26 4.35 5.6 6.9 ;
		END
	END VDD
	OBS
	END
END MMI_FILL_8
MACRO MMI_INAND2A
	CLASS CORE ;
	FOREIGN MMI_INAND2A 0 0 ;
	SIZE 2.96 BY 7.4 ;
	SYMMETRY X Y ;
	SITE CORE1 ;
	PIN out
		DIRECTION output ;
		USE SIGNAL ;
		PORT
			LAYER M1 ;
			RECT 0.9 4.55 1.24 5.39 ;
			LAYER M1 ;
			RECT 0.9 4.135 1.13 4.55 ;
			LAYER M1 ;
			RECT 0.29 3.905 1.13 4.135 ;
			LAYER M1 ;
			RECT 0.29 3.555 0.52 3.905 ;
			LAYER M1 ;
			RECT 0.145 3.08 0.595 3.555 ;
			LAYER M1 ;
			RECT 0.145 2.255 0.375 3.08 ;
			LAYER M1 ;
			RECT 0.145 2.025 0.72 2.255 ;
			LAYER M1 ;
			RECT 0.38 1.415 0.72 2.025 ;
		END
		AntennaDiffArea 0.9384 ;
	END out
	PIN in1
		DIRECTION input ;
		USE SIGNAL ;
		PORT
			LAYER M1 ;
			RECT 1.625 4.19 2.075 4.295 ;
			LAYER M1 ;
			RECT 1.625 3.85 2.15 4.19 ;
			LAYER M1 ;
			RECT 1.625 3.845 2.075 3.85 ;
		END
		AntennaGateArea 0.2484 ;
	END in1
	PIN GND
		DIRECTION inout ;
		USE GROUND ;
		PORT
			LAYER M1 ;
			RECT 1.53 0.5 1.87 2.255 ;
			LAYER M1 ;
			RECT 0 -0.5 2.96 0.5 ;
		END
	END GND
	PIN VDD
		DIRECTION inout ;
		USE POWER ;
		PORT
			LAYER M1 ;
			RECT 0 6.9 2.96 7.9 ;
			LAYER M1 ;
			RECT 0.18 4.55 0.52 6.9 ;
			LAYER M1 ;
			RECT 1.62 4.55 1.96 6.9 ;
		END
	END VDD
	PIN in0
		DIRECTION input ;
		USE SIGNAL ;
		PORT
			LAYER M1 ;
			RECT 0.885 3.5 1.335 3.555 ;
			LAYER M1 ;
			RECT 0.885 3.445 1.48 3.5 ;
			LAYER M1 ;
			RECT 0.885 3.215 1.545 3.445 ;
			LAYER M1 ;
			RECT 0.885 3.16 1.48 3.215 ;
			LAYER M1 ;
			RECT 0.885 3.105 1.335 3.16 ;
		END
		AntennaGateArea 0.3312 ;
	END in0
	OBS
		LAYER M1 ;
		RECT 2.34 4.55 2.68 5.39 ;
		LAYER M1 ;
		RECT 2.395 2.83 2.625 4.55 ;
		LAYER M1 ;
		RECT 0.62 2.6 2.625 2.83 ;
		LAYER M1 ;
		RECT 0.62 2.49 0.96 2.6 ;
		LAYER M1 ;
		RECT 2.29 2.255 2.52 2.6 ;
		LAYER M1 ;
		RECT 2.29 1.875 2.63 2.255 ;
	END
END MMI_INAND2A
MACRO MMI_INAND2B
	CLASS CORE ;
	FOREIGN MMI_INAND2B 0 0 ;
	SIZE 2.96 BY 7.4 ;
	SYMMETRY X Y ;
	SITE CORE1 ;
	PIN out
		DIRECTION output ;
		USE SIGNAL ;
		PORT
			LAYER M1 ;
			RECT 0.9 4.71 1.24 6.235 ;
			LAYER M1 ;
			RECT 0.205 4.48 1.24 4.71 ;
			LAYER M1 ;
			RECT 0.205 3.555 0.435 4.48 ;
			LAYER M1 ;
			RECT 0.9 4.475 1.24 4.48 ;
			LAYER M1 ;
			RECT 0.145 3.105 0.595 3.555 ;
			LAYER M1 ;
			RECT 0.18 2.62 0.41 3.105 ;
			LAYER M1 ;
			RECT 0.18 0.86 0.52 2.62 ;
		END
		AntennaDiffArea 1.8768 ;
	END out
	PIN in1
		DIRECTION input ;
		USE SIGNAL ;
		PORT
			LAYER M1 ;
			RECT 1.625 3.495 2.075 3.555 ;
			LAYER M1 ;
			RECT 1.625 3.155 2.19 3.495 ;
			LAYER M1 ;
			RECT 1.625 3.105 2.075 3.155 ;
		END
		AntennaGateArea 0.2484 ;
	END in1
	PIN GND
		DIRECTION inout ;
		USE GROUND ;
		PORT
			LAYER M1 ;
			RECT 1.33 0.5 1.67 2.62 ;
			LAYER M1 ;
			RECT 0 -0.5 2.96 0.5 ;
		END
	END GND
	PIN VDD
		DIRECTION inout ;
		USE POWER ;
		PORT
			LAYER M1 ;
			RECT 0 6.9 2.96 7.9 ;
			LAYER M1 ;
			RECT 0.18 4.955 0.52 6.9 ;
			LAYER M1 ;
			RECT 1.62 4.475 1.96 6.9 ;
		END
	END VDD
	PIN in0
		DIRECTION input ;
		USE SIGNAL ;
		PORT
			LAYER M1 ;
			RECT 1.055 3.555 1.395 3.57 ;
			LAYER M1 ;
			RECT 0.885 3.23 1.395 3.555 ;
			LAYER M1 ;
			RECT 0.885 3.105 1.335 3.23 ;
		END
		AntennaGateArea 0.6624 ;
	END in0
	OBS
		LAYER M1 ;
		RECT 2.38 4.475 2.72 5.315 ;
		LAYER M1 ;
		RECT 0.665 4.175 1.005 4.24 ;
		LAYER M1 ;
		RECT 2.385 4.175 2.615 4.475 ;
		LAYER M1 ;
		RECT 0.665 3.945 2.65 4.175 ;
		LAYER M1 ;
		RECT 0.665 3.9 1.005 3.945 ;
		LAYER M1 ;
		RECT 2.42 2.62 2.65 3.945 ;
		LAYER M1 ;
		RECT 2.09 2.39 2.65 2.62 ;
		LAYER M1 ;
		RECT 2.09 2.24 2.43 2.39 ;
	END
END MMI_INAND2B
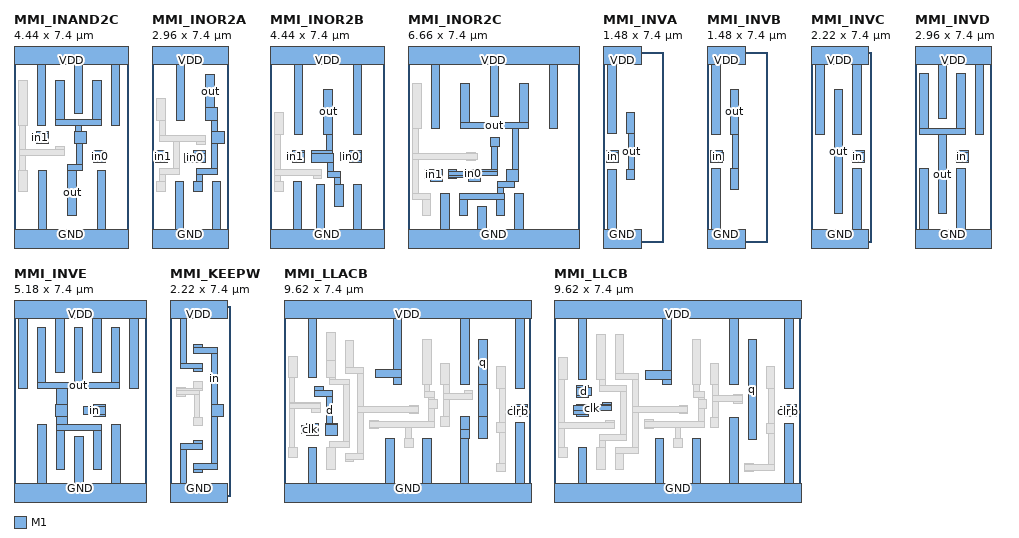
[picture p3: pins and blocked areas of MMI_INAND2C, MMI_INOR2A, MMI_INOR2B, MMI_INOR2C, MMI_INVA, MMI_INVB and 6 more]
MACRO MMI_INAND2C
	CLASS CORE ;
	FOREIGN MMI_INAND2C 0 0 ;
	SIZE 4.44 BY 7.4 ;
	SYMMETRY X Y ;
	SITE CORE1 ;
	PIN out
		DIRECTION output ;
		USE SIGNAL ;
		PORT
			LAYER M1 ;
			RECT 1.62 4.765 1.96 6.295 ;
			LAYER M1 ;
			RECT 3.06 4.765 3.4 6.295 ;
			LAYER M1 ;
			RECT 1.62 4.535 3.4 4.765 ;
			LAYER M1 ;
			RECT 2.405 4.295 2.635 4.535 ;
			LAYER M1 ;
			RECT 2.365 3.845 2.815 4.295 ;
			LAYER M1 ;
			RECT 2.425 3.02 2.655 3.845 ;
			LAYER M1 ;
			RECT 2.09 2.79 2.655 3.02 ;
			LAYER M1 ;
			RECT 2.09 1.03 2.43 2.79 ;
		END
		AntennaDiffArea 2.9808 ;
	END out
	PIN in1
		DIRECTION input ;
		USE SIGNAL ;
		PORT
			LAYER M1 ;
			RECT 0.885 4.24 1.335 4.295 ;
			LAYER M1 ;
			RECT 0.705 3.9 1.335 4.24 ;
			LAYER M1 ;
			RECT 0.885 3.845 1.335 3.9 ;
		END
		AntennaGateArea 0.4968 ;
	END in1
	PIN GND
		DIRECTION inout ;
		USE GROUND ;
		PORT
			LAYER M1 ;
			RECT 0.94 0.5 1.28 2.79 ;
			LAYER M1 ;
			RECT 3.24 0.5 3.58 2.79 ;
			LAYER M1 ;
			RECT 0 -0.5 4.44 0.5 ;
		END
	END GND
	PIN VDD
		DIRECTION inout ;
		USE POWER ;
		PORT
			LAYER M1 ;
			RECT 0 6.9 4.44 7.9 ;
			LAYER M1 ;
			RECT 0.9 4.535 1.24 6.9 ;
			LAYER M1 ;
			RECT 2.34 5.015 2.68 6.9 ;
			LAYER M1 ;
			RECT 3.78 4.535 4.12 6.9 ;
		END
	END VDD
	PIN in0
		DIRECTION input ;
		USE SIGNAL ;
		PORT
			LAYER M1 ;
			RECT 3.105 3.105 3.555 3.555 ;
		END
		AntennaGateArea 1.3248 ;
	END in0
	OBS
		LAYER M1 ;
		RECT 0.18 4.535 0.52 6.295 ;
		LAYER M1 ;
		RECT 0.225 3.6 0.455 4.535 ;
		LAYER M1 ;
		RECT 1.61 3.6 1.95 3.71 ;
		LAYER M1 ;
		RECT 0.225 3.37 1.95 3.6 ;
		LAYER M1 ;
		RECT 0.225 2.79 0.455 3.37 ;
		LAYER M1 ;
		RECT 0.18 1.95 0.52 2.79 ;
	END
END MMI_INAND2C
MACRO MMI_INOR2A
	CLASS CORE ;
	FOREIGN MMI_INOR2A 0 0 ;
	SIZE 2.96 BY 7.4 ;
	SYMMETRY X Y ;
	SITE CORE1 ;
	PIN out
		DIRECTION output ;
		USE SIGNAL ;
		PORT
			LAYER M1 ;
			RECT 2.09 5.225 2.43 6.505 ;
			LAYER M1 ;
			RECT 2.09 4.745 2.535 5.225 ;
			LAYER M1 ;
			RECT 2.305 4.295 2.535 4.745 ;
			LAYER M1 ;
			RECT 2.305 3.845 2.815 4.295 ;
			LAYER M1 ;
			RECT 2.305 2.875 2.535 3.845 ;
			LAYER M1 ;
			RECT 1.73 2.645 2.535 2.875 ;
			LAYER M1 ;
			RECT 1.73 2.345 1.96 2.645 ;
			LAYER M1 ;
			RECT 1.62 1.965 1.96 2.345 ;
		END
		AntennaDiffArea 1.1316 ;
	END out
	PIN in1
		DIRECTION input ;
		USE SIGNAL ;
		PORT
			LAYER M1 ;
			RECT 0.145 3.105 0.595 3.555 ;
		END
		AntennaGateArea 0.2484 ;
	END in1
	PIN GND
		DIRECTION inout ;
		USE GROUND ;
		PORT
			LAYER M1 ;
			RECT 0.9 0.5 1.24 2.345 ;
			LAYER M1 ;
			RECT 2.34 0.5 2.68 2.345 ;
			LAYER M1 ;
			RECT 0 -0.5 2.96 0.5 ;
		END
	END GND
	PIN VDD
		DIRECTION inout ;
		USE POWER ;
		PORT
			LAYER M1 ;
			RECT 0 6.9 2.96 7.9 ;
			LAYER M1 ;
			RECT 0.94 4.745 1.28 6.9 ;
		END
	END VDD
	PIN in0
		DIRECTION input ;
		USE SIGNAL ;
		PORT
			LAYER M1 ;
			RECT 1.625 3.445 2.075 3.555 ;
			LAYER M1 ;
			RECT 1.285 3.105 2.075 3.445 ;
		END
		AntennaGateArea 0.414 ;
	END in0
	OBS
		LAYER M1 ;
		RECT 0.18 4.745 0.52 5.585 ;
		LAYER M1 ;
		RECT 0.29 4.13 0.52 4.745 ;
		LAYER M1 ;
		RECT 0.29 3.9 2.07 4.13 ;
		LAYER M1 ;
		RECT 0.825 2.875 1.055 3.9 ;
		LAYER M1 ;
		RECT 1.73 3.79 2.07 3.9 ;
		LAYER M1 ;
		RECT 0.29 2.645 1.055 2.875 ;
		LAYER M1 ;
		RECT 0.29 2.345 0.52 2.645 ;
		LAYER M1 ;
		RECT 0.18 1.965 0.52 2.345 ;
	END
END MMI_INOR2A
MACRO MMI_INOR2B
	CLASS CORE ;
	FOREIGN MMI_INOR2B 0 0 ;
	SIZE 4.44 BY 7.4 ;
	SYMMETRY X Y ;
	SITE CORE1 ;
	PIN out
		DIRECTION output ;
		USE SIGNAL ;
		PORT
			LAYER M1 ;
			RECT 2.09 4.19 2.43 5.95 ;
			LAYER M1 ;
			RECT 2.2 3.555 2.43 4.19 ;
			LAYER M1 ;
			RECT 1.625 3.445 2.43 3.555 ;
			LAYER M1 ;
			RECT 1.625 3.105 2.475 3.445 ;
			LAYER M1 ;
			RECT 2.245 2.755 2.475 3.105 ;
			LAYER M1 ;
			RECT 2.245 2.525 2.75 2.755 ;
			LAYER M1 ;
			RECT 2.52 2.24 2.75 2.525 ;
			LAYER M1 ;
			RECT 2.52 1.4 2.86 2.24 ;
		END
		AntennaDiffArea 1.4904 ;
	END out
	PIN in1
		DIRECTION input ;
		USE SIGNAL ;
		PORT
			LAYER M1 ;
			RECT 0.885 3.5 1.335 3.555 ;
			LAYER M1 ;
			RECT 0.64 3.16 1.335 3.5 ;
			LAYER M1 ;
			RECT 0.885 3.105 1.335 3.16 ;
		END
		AntennaGateArea 0.2484 ;
	END in1
	PIN GND
		DIRECTION inout ;
		USE GROUND ;
		PORT
			LAYER M1 ;
			RECT 0.9 0.5 1.24 2.35 ;
			LAYER M1 ;
			RECT 1.8 0.5 2.14 2.24 ;
			LAYER M1 ;
			RECT 3.24 0.5 3.58 2.24 ;
			LAYER M1 ;
			RECT 0 -0.5 4.44 0.5 ;
		END
	END GND
	PIN VDD
		DIRECTION inout ;
		USE POWER ;
		PORT
			LAYER M1 ;
			RECT 0 6.9 4.44 7.9 ;
			LAYER M1 ;
			RECT 0.94 4.19 1.28 6.9 ;
			LAYER M1 ;
			RECT 3.24 4.19 3.58 6.9 ;
		END
	END VDD
	PIN in0
		DIRECTION input ;
		USE SIGNAL ;
		PORT
			LAYER M1 ;
			RECT 3.105 3.5 3.555 3.555 ;
			LAYER M1 ;
			RECT 2.76 3.16 3.555 3.5 ;
			LAYER M1 ;
			RECT 3.105 3.105 3.555 3.16 ;
		END
		AntennaGateArea 0.828 ;
	END in0
	OBS
		LAYER M1 ;
		RECT 0.18 4.19 0.52 5.03 ;
		LAYER M1 ;
		RECT 0.18 2.815 0.41 4.19 ;
		LAYER M1 ;
		RECT 0.18 2.585 2.015 2.815 ;
		LAYER M1 ;
		RECT 0.18 2.35 0.41 2.585 ;
		LAYER M1 ;
		RECT 1.675 2.47 2.015 2.585 ;
		LAYER M1 ;
		RECT 0.18 1.97 0.52 2.35 ;
	END
END MMI_INOR2B
MACRO MMI_INOR2C
	CLASS CORE ;
	FOREIGN MMI_INOR2C 0 0 ;
	SIZE 6.66 BY 7.4 ;
	SYMMETRY X Y ;
	SITE CORE1 ;
	PIN out
		DIRECTION output ;
		USE SIGNAL ;
		PORT
			LAYER M1 ;
			RECT 2.05 4.64 2.39 6.17 ;
			LAYER M1 ;
			RECT 4.35 4.64 4.69 6.17 ;
			LAYER M1 ;
			RECT 2.05 4.41 4.69 4.64 ;
			LAYER M1 ;
			RECT 4.06 2.815 4.29 4.41 ;
			LAYER M1 ;
			RECT 3.845 2.365 4.29 2.815 ;
			LAYER M1 ;
			RECT 3.845 2.35 4.14 2.365 ;
			LAYER M1 ;
			RECT 3.49 2.12 4.14 2.35 ;
			LAYER M1 ;
			RECT 3.49 1.88 3.72 2.12 ;
			LAYER M1 ;
			RECT 1.99 1.65 3.77 1.88 ;
			LAYER M1 ;
			RECT 1.99 1.04 2.33 1.65 ;
			LAYER M1 ;
			RECT 3.43 1.04 3.77 1.65 ;
		END
		AntennaDiffArea 2.9808 ;
	END out
	PIN in1
		DIRECTION input ;
		USE SIGNAL ;
		PORT
			LAYER M1 ;
			RECT 0.885 2.81 1.335 2.815 ;
			LAYER M1 ;
			RECT 0.66 2.47 1.335 2.81 ;
			LAYER M1 ;
			RECT 0.885 2.365 1.335 2.47 ;
		END
		AntennaGateArea 0.4968 ;
	END in1
	PIN GND
		DIRECTION inout ;
		USE GROUND ;
		PORT
			LAYER M1 ;
			RECT 1.27 0.5 1.61 1.88 ;
			LAYER M1 ;
			RECT 2.71 0.5 3.05 1.38 ;
			LAYER M1 ;
			RECT 4.15 0.5 4.49 1.88 ;
			LAYER M1 ;
			RECT 0 -0.5 6.66 0.5 ;
		END
	END GND
	PIN VDD
		DIRECTION inout ;
		USE POWER ;
		PORT
			LAYER M1 ;
			RECT 0 6.9 6.66 7.9 ;
			LAYER M1 ;
			RECT 0.9 4.41 1.24 6.9 ;
			LAYER M1 ;
			RECT 3.2 4.89 3.54 6.9 ;
			LAYER M1 ;
			RECT 5.5 4.41 5.84 6.9 ;
		END
	END VDD
	PIN in0
		DIRECTION input ;
		USE SIGNAL ;
		PORT
			LAYER M1 ;
			RECT 3.205 3.725 3.545 4.065 ;
			LAYER M1 ;
			RECT 3.255 2.815 3.485 3.725 ;
			LAYER M1 ;
			RECT 1.565 2.755 1.905 2.81 ;
			LAYER M1 ;
			RECT 2.365 2.755 3.485 2.815 ;
			LAYER M1 ;
			RECT 1.565 2.585 3.485 2.755 ;
			LAYER M1 ;
			RECT 1.565 2.525 2.815 2.585 ;
			LAYER M1 ;
			RECT 1.565 2.47 1.905 2.525 ;
			LAYER M1 ;
			RECT 2.365 2.365 2.815 2.525 ;
		END
		AntennaGateArea 1.656 ;
	END in0
	OBS
		LAYER M1 ;
		RECT 0.18 4.41 0.52 6.17 ;
		LAYER M1 ;
		RECT 0.18 3.445 0.41 4.41 ;
		LAYER M1 ;
		RECT 2.29 3.445 2.63 3.5 ;
		LAYER M1 ;
		RECT 0.18 3.215 2.695 3.445 ;
		LAYER M1 ;
		RECT 0.18 1.88 0.41 3.215 ;
		LAYER M1 ;
		RECT 2.29 3.16 2.63 3.215 ;
		LAYER M1 ;
		RECT 0.18 1.65 0.89 1.88 ;
		LAYER M1 ;
		RECT 0.55 1.04 0.89 1.65 ;
	END
END MMI_INOR2C
MACRO MMI_INVA
	CLASS CORE ;
	FOREIGN MMI_INVA 0 0 ;
	SIZE 1.48 BY 7.4 ;
	SYMMETRY X Y ;
	SITE CORE1 ;
	PIN out
		DIRECTION output ;
		USE SIGNAL ;
		PORT
			LAYER M1 ;
			RECT 0.9 4.215 1.24 5.055 ;
			LAYER M1 ;
			RECT 1.01 2.825 1.24 4.215 ;
			LAYER M1 ;
			RECT 0.9 2.445 1.24 2.825 ;
		END
		AntennaDiffArea 0.6624 ;
	END out
	PIN GND
		DIRECTION inout ;
		USE GROUND ;
		PORT
			LAYER M1 ;
			RECT 0.18 0.5 0.52 2.825 ;
			LAYER M1 ;
			RECT 0 -0.5 1.48 0.5 ;
		END
	END GND
	PIN VDD
		DIRECTION inout ;
		USE POWER ;
		PORT
			LAYER M1 ;
			RECT 0 6.9 1.48 7.9 ;
			LAYER M1 ;
			RECT 0.18 4.215 0.52 6.9 ;
		END
	END VDD
	PIN in
		DIRECTION input ;
		USE SIGNAL ;
		PORT
			LAYER M1 ;
			RECT 0.145 3.5 0.595 3.555 ;
			LAYER M1 ;
			RECT 0.145 3.16 0.62 3.5 ;
			LAYER M1 ;
			RECT 0.145 3.105 0.595 3.16 ;
		END
		AntennaGateArea 0.2484 ;
	END in
	OBS
	END
END MMI_INVA
MACRO MMI_INVB
	CLASS CORE ;
	FOREIGN MMI_INVB 0 0 ;
	SIZE 1.48 BY 7.4 ;
	SYMMETRY X Y ;
	SITE CORE1 ;
	PIN out
		DIRECTION output ;
		USE SIGNAL ;
		PORT
			LAYER M1 ;
			RECT 0.9 4.19 1.24 5.95 ;
			LAYER M1 ;
			RECT 1.01 2.875 1.24 4.19 ;
			LAYER M1 ;
			RECT 0.9 2.035 1.24 2.875 ;
		END
		AntennaDiffArea 1.3248 ;
	END out
	PIN GND
		DIRECTION inout ;
		USE GROUND ;
		PORT
			LAYER M1 ;
			RECT 0.18 0.5 0.52 2.875 ;
			LAYER M1 ;
			RECT 0 -0.5 1.48 0.5 ;
		END
	END GND
	PIN VDD
		DIRECTION inout ;
		USE POWER ;
		PORT
			LAYER M1 ;
			RECT 0 6.9 1.48 7.9 ;
			LAYER M1 ;
			RECT 0.18 4.19 0.52 6.9 ;
		END
	END VDD
	PIN in
		DIRECTION input ;
		USE SIGNAL ;
		PORT
			LAYER M1 ;
			RECT 0.145 3.5 0.595 3.555 ;
			LAYER M1 ;
			RECT 0.145 3.16 0.64 3.5 ;
			LAYER M1 ;
			RECT 0.145 3.105 0.595 3.16 ;
		END
		AntennaGateArea 0.4968 ;
	END in
	OBS
	END
END MMI_INVB
MACRO MMI_INVC
	CLASS CORE ;
	FOREIGN MMI_INVC 0 0 ;
	SIZE 2.22 BY 7.4 ;
	SYMMETRY X Y ;
	SITE CORE1 ;
	PIN out
		DIRECTION output ;
		USE SIGNAL ;
		PORT
			LAYER M1 ;
			RECT 0.9 1.11 1.24 5.95 ;
		END
		AntennaDiffArea 1.8768 ;
	END out
	PIN GND
		DIRECTION inout ;
		USE GROUND ;
		PORT
			LAYER M1 ;
			RECT 1.62 0.5 1.96 2.87 ;
			LAYER M1 ;
			RECT 0 -0.5 2.22 0.5 ;
		END
	END GND
	PIN VDD
		DIRECTION inout ;
		USE POWER ;
		PORT
			LAYER M1 ;
			RECT 0 6.9 2.22 7.9 ;
			LAYER M1 ;
			RECT 0.18 4.19 0.52 6.9 ;
			LAYER M1 ;
			RECT 1.62 4.19 1.96 6.9 ;
		END
	END VDD
	PIN in
		DIRECTION input ;
		USE SIGNAL ;
		PORT
			LAYER M1 ;
			RECT 1.625 3.5 2.075 3.555 ;
			LAYER M1 ;
			RECT 1.56 3.16 2.075 3.5 ;
			LAYER M1 ;
			RECT 1.625 3.105 2.075 3.16 ;
		END
		AntennaGateArea 0.9936 ;
	END in
	OBS
	END
END MMI_INVC
MACRO MMI_INVD
	CLASS CORE ;
	FOREIGN MMI_INVD 0 0 ;
	SIZE 2.96 BY 7.4 ;
	SYMMETRY X Y ;
	SITE CORE1 ;
	PIN out
		DIRECTION output ;
		USE SIGNAL ;
		PORT
			LAYER M1 ;
			RECT 0.18 4.405 0.52 6.55 ;
			LAYER M1 ;
			RECT 1.62 4.405 1.96 6.55 ;
			LAYER M1 ;
			RECT 0.18 4.175 1.96 4.405 ;
			LAYER M1 ;
			RECT 0.89 4.17 1.24 4.175 ;
			LAYER M1 ;
			RECT 0.9 1.115 1.24 4.17 ;
		END
		AntennaDiffArea 3.4977 ;
	END out
	PIN GND
		DIRECTION inout ;
		USE GROUND ;
		PORT
			LAYER M1 ;
			RECT 0.18 0.5 0.52 2.875 ;
			LAYER M1 ;
			RECT 1.62 0.5 1.96 2.875 ;
			LAYER M1 ;
			RECT 0 -0.5 2.96 0.5 ;
		END
	END GND
	PIN VDD
		DIRECTION inout ;
		USE POWER ;
		PORT
			LAYER M1 ;
			RECT 0 6.9 2.96 7.9 ;
			LAYER M1 ;
			RECT 0.9 4.795 1.24 6.9 ;
			LAYER M1 ;
			RECT 2.34 4.175 2.68 6.9 ;
		END
	END VDD
	PIN in
		DIRECTION input ;
		USE SIGNAL ;
		PORT
			LAYER M1 ;
			RECT 1.625 3.5 2.075 3.555 ;
			LAYER M1 ;
			RECT 1.56 3.16 2.075 3.5 ;
			LAYER M1 ;
			RECT 1.625 3.105 2.075 3.16 ;
		END
		AntennaGateArea 1.9881 ;
	END in
	OBS
	END
END MMI_INVD
MACRO MMI_INVE
	CLASS CORE ;
	FOREIGN MMI_INVE 0 0 ;
	SIZE 5.18 BY 7.4 ;
	SYMMETRY X Y ;
	SITE CORE1 ;
	PIN out
		DIRECTION output ;
		USE SIGNAL ;
		PORT
			LAYER M1 ;
			RECT 0.9 4.41 1.24 6.555 ;
			LAYER M1 ;
			RECT 2.34 4.41 2.68 6.555 ;
			LAYER M1 ;
			RECT 3.78 4.41 4.12 6.555 ;
			LAYER M1 ;
			RECT 0.9 4.18 4.12 4.41 ;
			LAYER M1 ;
			RECT 1.64 3.555 2.075 4.18 ;
			LAYER M1 ;
			RECT 1.625 3.105 2.075 3.555 ;
			LAYER M1 ;
			RECT 1.64 2.8 2.075 3.105 ;
			LAYER M1 ;
			RECT 1.64 2.57 3.42 2.8 ;
			LAYER M1 ;
			RECT 1.64 1.04 1.98 2.57 ;
			LAYER M1 ;
			RECT 3.08 1.04 3.42 2.57 ;
		END
		AntennaDiffArea 5.9643 ;
	END out
	PIN GND
		DIRECTION inout ;
		USE GROUND ;
		PORT
			LAYER M1 ;
			RECT 0.92 0.5 1.26 2.8 ;
			LAYER M1 ;
			RECT 2.36 0.5 2.7 2.32 ;
			LAYER M1 ;
			RECT 3.8 0.5 4.14 2.8 ;
			LAYER M1 ;
			RECT 0 -0.5 5.18 0.5 ;
		END
	END GND
	PIN VDD
		DIRECTION inout ;
		USE POWER ;
		PORT
			LAYER M1 ;
			RECT 0 6.9 5.18 7.9 ;
			LAYER M1 ;
			RECT 0.18 4.18 0.52 6.9 ;
			LAYER M1 ;
			RECT 1.62 4.8 1.96 6.9 ;
			LAYER M1 ;
			RECT 3.06 4.8 3.4 6.9 ;
			LAYER M1 ;
			RECT 4.5 4.18 4.84 6.9 ;
		END
	END VDD
	PIN in
		DIRECTION input ;
		USE SIGNAL ;
		PORT
			LAYER M1 ;
			RECT 3.105 3.5 3.555 3.555 ;
			LAYER M1 ;
			RECT 2.725 3.16 3.555 3.5 ;
			LAYER M1 ;
			RECT 3.105 3.105 3.555 3.16 ;
		END
		AntennaGateArea 3.9762 ;
	END in
	OBS
	END
END MMI_INVE
MACRO MMI_KEEPW
	CLASS CORE ;
	FOREIGN MMI_KEEPW 0 0 ;
	SIZE 2.22 BY 7.4 ;
	SYMMETRY X Y ;
	SITE CORE1 ;
	PIN GND
		DIRECTION inout ;
		USE GROUND ;
		PORT
			LAYER M1 ;
			RECT 0.93 2.06 1.27 2.17 ;
			LAYER M1 ;
			RECT 0.395 1.83 1.27 2.06 ;
			LAYER M1 ;
			RECT 0.395 0.5 0.625 1.83 ;
			LAYER M1 ;
			RECT 0 -0.5 2.22 0.5 ;
		END
	END GND
	PIN VDD
		DIRECTION inout ;
		USE POWER ;
		PORT
			LAYER M1 ;
			RECT 0 6.9 2.22 7.9 ;
			LAYER M1 ;
			RECT 0.425 5.18 0.655 6.9 ;
			LAYER M1 ;
			RECT 0.425 4.95 1.27 5.18 ;
			LAYER M1 ;
			RECT 0.93 4.84 1.27 4.95 ;
		END
	END VDD
	PIN in
		DIRECTION inout ;
		USE SIGNAL ;
		PORT
			LAYER M1 ;
			RECT 0.93 5.79 1.27 5.9 ;
			LAYER M1 ;
			RECT 0.93 5.56 1.855 5.79 ;
			LAYER M1 ;
			RECT 1.625 3.555 1.855 5.56 ;
			LAYER M1 ;
			RECT 1.625 3.105 2.075 3.555 ;
			LAYER M1 ;
			RECT 1.625 1.27 1.855 3.105 ;
			LAYER M1 ;
			RECT 0.93 1.04 1.855 1.27 ;
			LAYER M1 ;
			RECT 0.93 0.93 1.27 1.04 ;
		END
		AntennaGateArea 0.2268 ;
		AntennaDiffArea 0.4032 ;
	END in
	OBS
		LAYER M1 ;
		RECT 0.27 4.175 0.61 4.22 ;
		LAYER M1 ;
		RECT 0.93 4.175 1.27 4.46 ;
		LAYER M1 ;
		RECT 0.27 4.12 1.27 4.175 ;
		LAYER M1 ;
		RECT 0.27 3.945 1.165 4.12 ;
		LAYER M1 ;
		RECT 0.27 3.88 0.61 3.945 ;
		LAYER M1 ;
		RECT 0.935 3.07 1.165 3.945 ;
		LAYER M1 ;
		RECT 0.93 2.73 1.27 3.07 ;
	END
END MMI_KEEPW
MACRO MMI_LLACB
	CLASS CORE ;
	FOREIGN MMI_LLACB 0 0 ;
	SIZE 9.62 BY 7.4 ;
	SYMMETRY X Y ;
	SITE CORE1 ;
	PIN d
		DIRECTION input ;
		USE SIGNAL ;
		PORT
			LAYER M1 ;
			RECT 1.18 4.095 1.52 4.275 ;
			LAYER M1 ;
			RECT 1.18 3.865 1.89 4.095 ;
			LAYER M1 ;
			RECT 1.66 2.81 1.89 3.865 ;
			LAYER M1 ;
			RECT 1.62 2.8 2.075 2.81 ;
			LAYER M1 ;
			RECT 1.6 2.36 2.075 2.8 ;
		END
		AntennaGateArea 0.4968 ;
	END d
	PIN GND
		DIRECTION inout ;
		USE GROUND ;
		PORT
			LAYER M1 ;
			RECT 6.87 2.58 7.21 3.08 ;
			LAYER M1 ;
			RECT 0.94 0.5 1.28 1.875 ;
			LAYER M1 ;
			RECT 3.965 0.5 4.305 2.25 ;
			LAYER M1 ;
			RECT 5.405 0.5 5.745 2.25 ;
			LAYER M1 ;
			RECT 6.865 2.24 7.21 2.58 ;
			LAYER M1 ;
			RECT 6.865 0.5 7.205 2.24 ;
			LAYER M1 ;
			RECT 9.01 0.5 9.35 2.87 ;
			LAYER M1 ;
			RECT 0 -0.5 9.62 0.5 ;
		END
	END GND
	PIN q
		DIRECTION output ;
		USE SIGNAL ;
		PORT
			LAYER M1 ;
			RECT 7.59 4.335 7.93 6.095 ;
			LAYER M1 ;
			RECT 7.59 3.08 7.925 4.335 ;
			LAYER M1 ;
			RECT 7.59 2.24 7.93 3.08 ;
		END
		AntennaDiffArea 1.3248 ;
	END q
	PIN VDD
		DIRECTION inout ;
		USE POWER ;
		PORT
			LAYER M1 ;
			RECT 0 6.9 9.62 7.9 ;
			LAYER M1 ;
			RECT 0.94 4.605 1.28 6.9 ;
			LAYER M1 ;
			RECT 4.255 4.945 4.595 6.9 ;
			LAYER M1 ;
			RECT 3.57 4.605 4.595 4.945 ;
			LAYER M1 ;
			RECT 4.255 4.335 4.595 4.605 ;
			LAYER M1 ;
			RECT 6.87 4.335 7.21 6.9 ;
			LAYER M1 ;
			RECT 9.01 4.2 9.35 6.9 ;
		END
	END VDD
	PIN clk
		DIRECTION input ;
		USE CLOCK ;
		PORT
			LAYER M1 ;
			RECT 1.026 2.81 1.335 2.812 ;
			LAYER M1 ;
			RECT 0.88 2.755 1.335 2.81 ;
			LAYER M1 ;
			RECT 0.685 2.415 1.335 2.755 ;
			LAYER M1 ;
			RECT 0.875 2.365 1.335 2.415 ;
			LAYER M1 ;
			RECT 0.876 2.364 1.335 2.365 ;
		END
		AntennaGateArea 0.4896 ;
	END clk
	PIN clrb
		DIRECTION input ;
		USE SIGNAL ;
		PORT
			LAYER M1 ;
			RECT 9.02 3.47 9.475 3.56 ;
			LAYER M1 ;
			RECT 8.86 3.13 9.475 3.47 ;
			LAYER M1 ;
			RECT 9.02 3.114 9.475 3.13 ;
		END
		AntennaGateArea 0.2484 ;
	END clrb
	OBS
		LAYER M1 ;
		RECT 0.18 4.605 0.52 5.445 ;
		LAYER M1 ;
		RECT 1.66 5.29 2 6.365 ;
		LAYER M1 ;
		RECT 1.66 4.605 2.01 5.29 ;
		LAYER M1 ;
		RECT 2.38 5.015 2.72 6.065 ;
		LAYER M1 ;
		RECT 2.38 4.785 3.1 5.015 ;
		LAYER M1 ;
		RECT 0.195 3.635 0.425 4.605 ;
		LAYER M1 ;
		RECT 1.78 4.555 2.01 4.605 ;
		LAYER M1 ;
		RECT 1.78 4.325 2.535 4.555 ;
		LAYER M1 ;
		RECT 0.195 3.605 1.428 3.635 ;
		LAYER M1 ;
		RECT 0.195 3.405 1.43 3.605 ;
		LAYER M1 ;
		RECT 0.195 1.875 0.425 3.405 ;
		LAYER M1 ;
		RECT 1.09 3.265 1.43 3.405 ;
		LAYER M1 ;
		RECT 2.305 2.13 2.535 4.325 ;
		LAYER M1 ;
		RECT 1.77 1.9 2.535 2.13 ;
		LAYER M1 ;
		RECT 2.87 3.47 3.1 4.785 ;
		LAYER M1 ;
		RECT 5.405 4.335 5.745 6.095 ;
		LAYER M1 ;
		RECT 6.105 4.335 6.445 5.175 ;
		LAYER M1 ;
		RECT 5.455 4.075 5.685 4.335 ;
		LAYER M1 ;
		RECT 5.455 3.845 5.875 4.075 ;
		LAYER M1 ;
		RECT 5.645 3.74 5.875 3.845 ;
		LAYER M1 ;
		RECT 6.215 3.99 6.445 4.335 ;
		LAYER M1 ;
		RECT 7.015 3.99 7.355 4.1 ;
		LAYER M1 ;
		RECT 6.215 3.76 7.355 3.99 ;
		LAYER M1 ;
		RECT 4.905 3.47 5.245 3.535 ;
		LAYER M1 ;
		RECT 2.87 3.24 5.245 3.47 ;
		LAYER M1 ;
		RECT 1.77 1.875 2 1.9 ;
		LAYER M1 ;
		RECT 0.18 1.495 0.52 1.875 ;
		LAYER M1 ;
		RECT 1.66 1.035 2 1.875 ;
		LAYER M1 ;
		RECT 2.87 1.67 3.1 3.24 ;
		LAYER M1 ;
		RECT 4.905 3.195 5.245 3.24 ;
		LAYER M1 ;
		RECT 5.645 3.4 5.985 3.74 ;
		LAYER M1 ;
		RECT 3.335 2.89 3.675 2.95 ;
		LAYER M1 ;
		RECT 5.645 2.89 5.875 3.4 ;
		LAYER M1 ;
		RECT 6.215 3.085 6.445 3.76 ;
		LAYER M1 ;
		RECT 3.335 2.66 5.875 2.89 ;
		LAYER M1 ;
		RECT 6.105 2.705 6.445 3.085 ;
		LAYER M1 ;
		RECT 8.29 4.2 8.63 5.04 ;
		LAYER M1 ;
		RECT 3.335 2.61 3.675 2.66 ;
		LAYER M1 ;
		RECT 4.745 2.25 4.975 2.66 ;
		LAYER M1 ;
		RECT 2.38 1.44 3.1 1.67 ;
		LAYER M1 ;
		RECT 2.38 1.33 2.72 1.44 ;
		LAYER M1 ;
		RECT 4.685 1.87 5.025 2.25 ;
		LAYER M1 ;
		RECT 8.4 2.87 8.63 4.2 ;
		LAYER M1 ;
		RECT 8.29 2.49 8.63 2.87 ;
		LAYER M1 ;
		RECT 8.4 1.275 8.63 2.49 ;
		LAYER M1 ;
		RECT 8.29 0.935 8.63 1.275 ;
	END
END MMI_LLACB
MACRO MMI_LLCB
	CLASS CORE ;
	FOREIGN MMI_LLCB 0 0 ;
	SIZE 9.62 BY 7.4 ;
	SYMMETRY X Y ;
	SITE CORE1 ;
	PIN d
		DIRECTION input ;
		USE SIGNAL ;
		PORT
			LAYER M1 ;
			RECT 0.885 4.235 1.335 4.295 ;
			LAYER M1 ;
			RECT 0.885 3.895 1.475 4.235 ;
			LAYER M1 ;
			RECT 0.885 3.845 1.335 3.895 ;
		END
		AntennaGateArea 0.4968 ;
	END d
	PIN GND
		DIRECTION inout ;
		USE GROUND ;
		PORT
			LAYER M1 ;
			RECT 0.94 0.5 1.28 1.875 ;
			LAYER M1 ;
			RECT 3.935 0.5 4.275 2.25 ;
			LAYER M1 ;
			RECT 5.375 0.5 5.715 2.25 ;
			LAYER M1 ;
			RECT 6.84 0.5 7.18 3.06 ;
			LAYER M1 ;
			RECT 8.98 0.5 9.32 2.815 ;
			LAYER M1 ;
			RECT 0 -0.5 9.62 0.5 ;
		END
	END GND
	PIN q
		DIRECTION output ;
		USE SIGNAL ;
		PORT
			LAYER M1 ;
			RECT 7.56 2.22 7.9 6.095 ;
		END
		AntennaDiffArea 1.3248 ;
	END q
	PIN VDD
		DIRECTION inout ;
		USE POWER ;
		PORT
			LAYER M1 ;
			RECT 0 6.9 9.62 7.9 ;
			LAYER M1 ;
			RECT 0.94 4.535 1.28 6.9 ;
			LAYER M1 ;
			RECT 4.225 4.875 4.565 6.9 ;
			LAYER M1 ;
			RECT 3.57 4.535 4.565 4.875 ;
			LAYER M1 ;
			RECT 4.225 4.335 4.565 4.535 ;
			LAYER M1 ;
			RECT 6.84 4.335 7.18 6.9 ;
			LAYER M1 ;
			RECT 8.98 4.2 9.32 6.9 ;
		END
	END VDD
	PIN clk
		DIRECTION input ;
		USE CLOCK ;
		PORT
			LAYER M1 ;
			RECT 1.9 3.555 2.24 3.66 ;
			LAYER M1 ;
			RECT 0.885 3.51 2.24 3.555 ;
			LAYER M1 ;
			RECT 0.75 3.325 2.24 3.51 ;
			LAYER M1 ;
			RECT 0.75 3.17 1.335 3.325 ;
			LAYER M1 ;
			RECT 1.9 3.32 2.24 3.325 ;
			LAYER M1 ;
			RECT 0.885 3.105 1.335 3.17 ;
		END
		AntennaGateArea 0.6552 ;
	END clk
	PIN clrb
		DIRECTION input ;
		USE SIGNAL ;
		PORT
			LAYER M1 ;
			RECT 8.99 3.47 9.445 3.56 ;
			LAYER M1 ;
			RECT 8.83 3.13 9.445 3.47 ;
			LAYER M1 ;
			RECT 8.99 3.114 9.445 3.13 ;
		END
		AntennaGateArea 0.2484 ;
	END clrb
	OBS
		LAYER M1 ;
		RECT 0.18 4.535 0.52 5.375 ;
		LAYER M1 ;
		RECT 1.66 4.535 2 6.295 ;
		LAYER M1 ;
		RECT 2.38 4.765 2.72 6.295 ;
		LAYER M1 ;
		RECT 2.38 4.535 3.29 4.765 ;
		LAYER M1 ;
		RECT 0.18 2.85 0.41 4.535 ;
		LAYER M1 ;
		RECT 1.77 4.305 2 4.535 ;
		LAYER M1 ;
		RECT 1.77 4.075 2.83 4.305 ;
		LAYER M1 ;
		RECT 2.02 2.85 2.36 2.96 ;
		LAYER M1 ;
		RECT 0.18 2.62 2.36 2.85 ;
		LAYER M1 ;
		RECT 0.18 1.875 0.41 2.62 ;
		LAYER M1 ;
		RECT 2.6 2.39 2.83 4.075 ;
		LAYER M1 ;
		RECT 1.77 2.16 2.83 2.39 ;
		LAYER M1 ;
		RECT 3.06 3.47 3.29 4.535 ;
		LAYER M1 ;
		RECT 5.375 4.335 5.715 6.095 ;
		LAYER M1 ;
		RECT 6.08 4.335 6.42 5.175 ;
		LAYER M1 ;
		RECT 5.425 4.075 5.655 4.335 ;
		LAYER M1 ;
		RECT 5.425 3.845 5.845 4.075 ;
		LAYER M1 ;
		RECT 5.615 3.74 5.845 3.845 ;
		LAYER M1 ;
		RECT 6.19 3.91 6.42 4.335 ;
		LAYER M1 ;
		RECT 6.99 3.91 7.33 3.95 ;
		LAYER M1 ;
		RECT 4.875 3.47 5.215 3.535 ;
		LAYER M1 ;
		RECT 3.06 3.24 5.215 3.47 ;
		LAYER M1 ;
		RECT 1.77 1.875 2 2.16 ;
		LAYER M1 ;
		RECT 3.06 1.875 3.29 3.24 ;
		LAYER M1 ;
		RECT 4.875 3.195 5.215 3.24 ;
		LAYER M1 ;
		RECT 5.615 3.4 5.955 3.74 ;
		LAYER M1 ;
		RECT 6.19 3.68 7.33 3.91 ;
		LAYER M1 ;
		RECT 3.525 2.89 3.865 2.965 ;
		LAYER M1 ;
		RECT 5.615 2.89 5.845 3.4 ;
		LAYER M1 ;
		RECT 6.19 3.065 6.42 3.68 ;
		LAYER M1 ;
		RECT 6.99 3.61 7.33 3.68 ;
		LAYER M1 ;
		RECT 3.525 2.66 5.845 2.89 ;
		LAYER M1 ;
		RECT 6.08 2.685 6.42 3.065 ;
		LAYER M1 ;
		RECT 3.525 2.625 3.865 2.66 ;
		LAYER M1 ;
		RECT 4.715 2.25 4.945 2.66 ;
		LAYER M1 ;
		RECT 0.18 1.495 0.52 1.875 ;
		LAYER M1 ;
		RECT 1.66 1.035 2 1.875 ;
		LAYER M1 ;
		RECT 2.38 1.645 3.29 1.875 ;
		LAYER M1 ;
		RECT 2.38 1.035 2.72 1.645 ;
		LAYER M1 ;
		RECT 4.655 1.87 4.995 2.25 ;
		LAYER M1 ;
		RECT 8.26 4.2 8.6 5.04 ;
		LAYER M1 ;
		RECT 8.37 2.815 8.6 4.2 ;
		LAYER M1 ;
		RECT 8.26 2.435 8.6 2.815 ;
		LAYER M1 ;
		RECT 7.42 1.22 7.76 1.275 ;
		LAYER M1 ;
		RECT 8.37 1.22 8.6 2.435 ;
		LAYER M1 ;
		RECT 7.42 0.99 8.6 1.22 ;
		LAYER M1 ;
		RECT 7.42 0.935 7.76 0.99 ;
	END
END MMI_LLCB
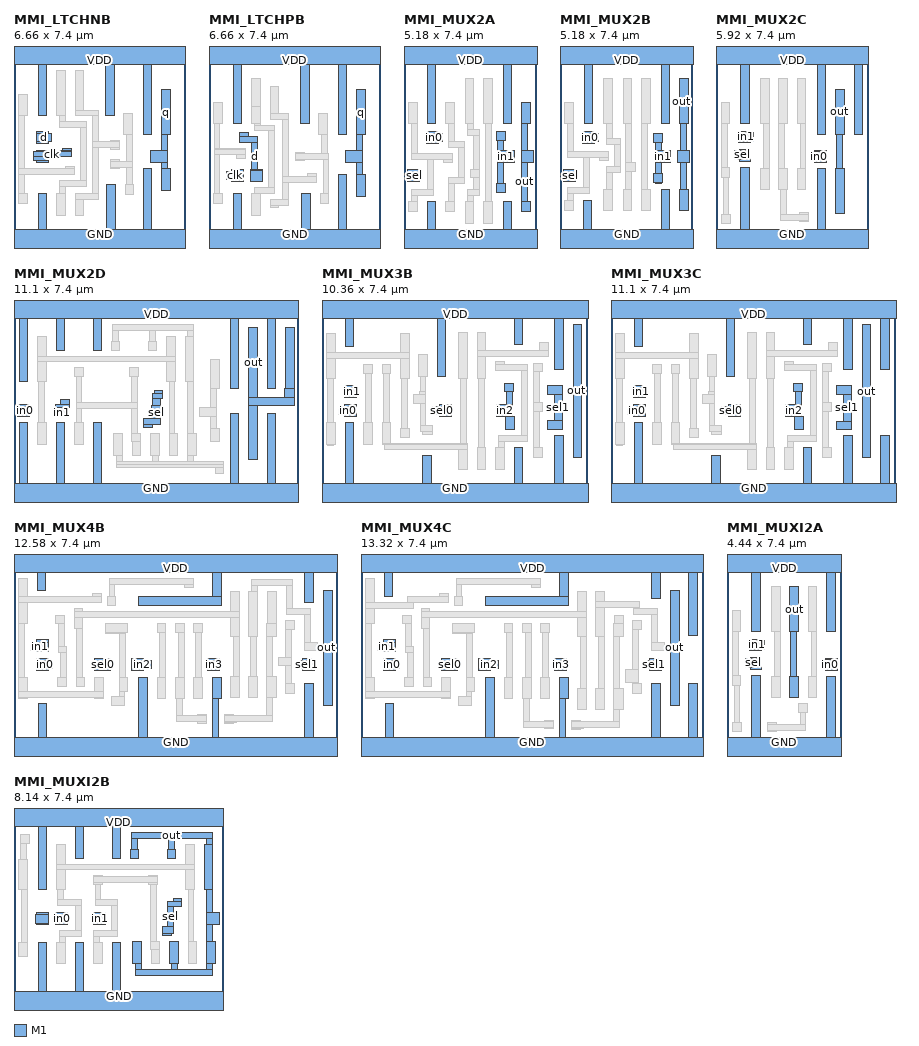
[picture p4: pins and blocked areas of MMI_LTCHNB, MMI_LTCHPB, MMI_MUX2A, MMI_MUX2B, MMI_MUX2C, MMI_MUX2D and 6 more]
MACRO MMI_LTCHNB
	CLASS CORE ;
	FOREIGN MMI_LTCHNB 0 0 ;
	SIZE 6.66 BY 7.4 ;
	SYMMETRY X Y ;
	SITE CORE1 ;
	PIN d
		DIRECTION input ;
		USE SIGNAL ;
		PORT
			LAYER M1 ;
			RECT 0.885 4.235 1.335 4.295 ;
			LAYER M1 ;
			RECT 0.885 3.895 1.475 4.235 ;
			LAYER M1 ;
			RECT 0.885 3.845 1.335 3.895 ;
		END
		AntennaGateArea 0.4968 ;
	END d
	PIN GND
		DIRECTION inout ;
		USE GROUND ;
		PORT
			LAYER M1 ;
			RECT 0.94 0.5 1.28 1.875 ;
			LAYER M1 ;
			RECT 3.61 0.5 3.95 2.24 ;
			LAYER M1 ;
			RECT 5.03 0.5 5.37 2.845 ;
			LAYER M1 ;
			RECT 0 -0.5 6.66 0.5 ;
		END
	END GND
	PIN q
		DIRECTION output ;
		USE SIGNAL ;
		PORT
			LAYER M1 ;
			RECT 5.75 4.18 6.09 5.94 ;
			LAYER M1 ;
			RECT 5.75 3.555 5.98 4.18 ;
			LAYER M1 ;
			RECT 5.325 3.105 5.98 3.555 ;
			LAYER M1 ;
			RECT 5.75 2.845 5.98 3.105 ;
			LAYER M1 ;
			RECT 5.75 2.005 6.09 2.845 ;
		END
		AntennaDiffArea 1.3248 ;
	END q
	PIN VDD
		DIRECTION inout ;
		USE POWER ;
		PORT
			LAYER M1 ;
			RECT 0 6.9 6.66 7.9 ;
			LAYER M1 ;
			RECT 0.94 4.91 1.28 6.9 ;
			LAYER M1 ;
			RECT 3.57 4.91 3.91 6.9 ;
			LAYER M1 ;
			RECT 5.03 4.18 5.37 6.9 ;
		END
	END VDD
	PIN clk
		DIRECTION input ;
		USE CLOCK ;
		PORT
			LAYER M1 ;
			RECT 1.9 3.555 2.24 3.66 ;
			LAYER M1 ;
			RECT 0.885 3.51 2.24 3.555 ;
			LAYER M1 ;
			RECT 0.75 3.325 2.24 3.51 ;
			LAYER M1 ;
			RECT 0.75 3.17 1.335 3.325 ;
			LAYER M1 ;
			RECT 1.9 3.32 2.24 3.325 ;
			LAYER M1 ;
			RECT 0.885 3.105 1.335 3.17 ;
		END
		AntennaGateArea 0.6552 ;
	END clk
	OBS
		LAYER M1 ;
		RECT 0.18 4.91 0.52 5.75 ;
		LAYER M1 ;
		RECT 1.66 4.91 2 6.67 ;
		LAYER M1 ;
		RECT 2.38 5.14 2.72 6.67 ;
		LAYER M1 ;
		RECT 2.38 4.91 3.29 5.14 ;
		LAYER M1 ;
		RECT 0.18 2.85 0.41 4.91 ;
		LAYER M1 ;
		RECT 1.77 4.68 2 4.91 ;
		LAYER M1 ;
		RECT 1.77 4.45 2.83 4.68 ;
		LAYER M1 ;
		RECT 2.02 2.85 2.36 2.96 ;
		LAYER M1 ;
		RECT 0.18 2.62 2.36 2.85 ;
		LAYER M1 ;
		RECT 0.18 1.875 0.41 2.62 ;
		LAYER M1 ;
		RECT 2.6 2.39 2.83 4.45 ;
		LAYER M1 ;
		RECT 1.77 2.16 2.83 2.39 ;
		LAYER M1 ;
		RECT 3.06 3.895 3.29 4.91 ;
		LAYER M1 ;
		RECT 4.27 4.18 4.61 5.02 ;
		LAYER M1 ;
		RECT 3.77 3.895 4.11 3.935 ;
		LAYER M1 ;
		RECT 3.06 3.665 4.11 3.895 ;
		LAYER M1 ;
		RECT 1.77 1.875 2 2.16 ;
		LAYER M1 ;
		RECT 3.06 1.875 3.29 3.665 ;
		LAYER M1 ;
		RECT 3.77 3.595 4.11 3.665 ;
		LAYER M1 ;
		RECT 3.76 3.145 4.1 3.205 ;
		LAYER M1 ;
		RECT 4.38 3.145 4.61 4.18 ;
		LAYER M1 ;
		RECT 3.76 2.915 4.61 3.145 ;
		LAYER M1 ;
		RECT 3.76 2.865 4.1 2.915 ;
		LAYER M1 ;
		RECT 4.38 2.24 4.61 2.915 ;
		LAYER M1 ;
		RECT 0.18 1.495 0.52 1.875 ;
		LAYER M1 ;
		RECT 1.66 1.035 2 1.875 ;
		LAYER M1 ;
		RECT 2.38 1.645 3.29 1.875 ;
		LAYER M1 ;
		RECT 2.38 1.035 2.72 1.645 ;
		LAYER M1 ;
		RECT 4.33 1.86 4.67 2.24 ;
	END
END MMI_LTCHNB
MACRO MMI_LTCHPB
	CLASS CORE ;
	FOREIGN MMI_LTCHPB 0 0 ;
	SIZE 6.66 BY 7.4 ;
	SYMMETRY X Y ;
	SITE CORE1 ;
	PIN d
		DIRECTION input ;
		USE SIGNAL ;
		PORT
			LAYER M1 ;
			RECT 1.18 4.095 1.52 4.275 ;
			LAYER M1 ;
			RECT 1.18 3.865 1.89 4.095 ;
			LAYER M1 ;
			RECT 1.66 2.81 1.89 3.865 ;
			LAYER M1 ;
			RECT 1.62 2.8 2.075 2.81 ;
			LAYER M1 ;
			RECT 1.6 2.36 2.075 2.8 ;
		END
		AntennaGateArea 0.4968 ;
	END d
	PIN GND
		DIRECTION inout ;
		USE GROUND ;
		PORT
			LAYER M1 ;
			RECT 0.94 0.5 1.28 1.875 ;
			LAYER M1 ;
			RECT 3.61 0.5 3.95 1.875 ;
			LAYER M1 ;
			RECT 5.03 0.5 5.37 2.62 ;
			LAYER M1 ;
			RECT 0 -0.5 6.66 0.5 ;
		END
	END GND
	PIN q
		DIRECTION output ;
		USE SIGNAL ;
		PORT
			LAYER M1 ;
			RECT 5.75 4.18 6.09 5.94 ;
			LAYER M1 ;
			RECT 5.75 3.555 5.98 4.18 ;
			LAYER M1 ;
			RECT 5.325 3.105 5.98 3.555 ;
			LAYER M1 ;
			RECT 5.75 2.62 5.98 3.105 ;
			LAYER M1 ;
			RECT 5.75 1.78 6.09 2.62 ;
		END
		AntennaDiffArea 1.3248 ;
	END q
	PIN VDD
		DIRECTION inout ;
		USE POWER ;
		PORT
			LAYER M1 ;
			RECT 0 6.9 6.66 7.9 ;
			LAYER M1 ;
			RECT 0.94 4.605 1.28 6.9 ;
			LAYER M1 ;
			RECT 3.57 4.605 3.91 6.9 ;
			LAYER M1 ;
			RECT 5.03 4.18 5.37 6.9 ;
		END
	END VDD
	PIN clk
		DIRECTION input ;
		USE CLOCK ;
		PORT
			LAYER M1 ;
			RECT 1.026 2.81 1.335 2.812 ;
			LAYER M1 ;
			RECT 0.88 2.755 1.335 2.81 ;
			LAYER M1 ;
			RECT 0.685 2.415 1.335 2.755 ;
			LAYER M1 ;
			RECT 0.875 2.365 1.335 2.415 ;
			LAYER M1 ;
			RECT 0.876 2.364 1.335 2.365 ;
		END
		AntennaGateArea 0.4896 ;
	END clk
	OBS
		LAYER M1 ;
		RECT 0.18 4.605 0.52 5.445 ;
		LAYER M1 ;
		RECT 1.66 5.29 2 6.365 ;
		LAYER M1 ;
		RECT 1.66 4.605 2.01 5.29 ;
		LAYER M1 ;
		RECT 2.38 5.015 2.72 6.065 ;
		LAYER M1 ;
		RECT 2.38 4.785 3.1 5.015 ;
		LAYER M1 ;
		RECT 0.195 3.635 0.425 4.605 ;
		LAYER M1 ;
		RECT 1.78 4.555 2.01 4.605 ;
		LAYER M1 ;
		RECT 1.78 4.325 2.535 4.555 ;
		LAYER M1 ;
		RECT 0.195 3.605 1.428 3.635 ;
		LAYER M1 ;
		RECT 0.195 3.405 1.43 3.605 ;
		LAYER M1 ;
		RECT 0.195 1.875 0.425 3.405 ;
		LAYER M1 ;
		RECT 1.09 3.265 1.43 3.405 ;
		LAYER M1 ;
		RECT 2.305 2.13 2.535 4.325 ;
		LAYER M1 ;
		RECT 1.77 1.9 2.535 2.13 ;
		LAYER M1 ;
		RECT 2.87 2.545 3.1 4.785 ;
		LAYER M1 ;
		RECT 4.27 4.18 4.61 5.02 ;
		LAYER M1 ;
		RECT 3.37 3.445 3.71 3.495 ;
		LAYER M1 ;
		RECT 4.38 3.445 4.61 4.18 ;
		LAYER M1 ;
		RECT 3.37 3.215 4.67 3.445 ;
		LAYER M1 ;
		RECT 3.37 3.155 3.71 3.215 ;
		LAYER M1 ;
		RECT 3.85 2.545 4.19 2.655 ;
		LAYER M1 ;
		RECT 2.87 2.315 4.19 2.545 ;
		LAYER M1 ;
		RECT 1.77 1.875 2 1.9 ;
		LAYER M1 ;
		RECT 0.18 1.495 0.52 1.875 ;
		LAYER M1 ;
		RECT 1.66 1.035 2 1.875 ;
		LAYER M1 ;
		RECT 2.87 1.67 3.1 2.315 ;
		LAYER M1 ;
		RECT 4.44 1.875 4.67 3.215 ;
		LAYER M1 ;
		RECT 2.38 1.44 3.1 1.67 ;
		LAYER M1 ;
		RECT 2.38 1.33 2.72 1.44 ;
		LAYER M1 ;
		RECT 4.33 1.495 4.67 1.875 ;
		LAYER M1 ;
		RECT 4.44 1.494 4.67 1.495 ;
	END
END MMI_LTCHPB
MACRO MMI_MUX2A
	CLASS CORE ;
	FOREIGN MMI_MUX2A 0 0 ;
	SIZE 5.18 BY 7.4 ;
	SYMMETRY X Y ;
	SITE CORE1 ;
	PIN out
		DIRECTION output ;
		USE SIGNAL ;
		PORT
			LAYER M1 ;
			RECT 4.58 4.6 4.92 5.44 ;
			LAYER M1 ;
			RECT 4.58 3.555 4.81 4.6 ;
			LAYER M1 ;
			RECT 4.58 3.105 5.035 3.555 ;
			LAYER M1 ;
			RECT 4.58 1.57 4.81 3.105 ;
			LAYER M1 ;
			RECT 4.58 1.19 4.92 1.57 ;
		END
		AntennaDiffArea 0.6624 ;
	END out
	PIN sel
		DIRECTION input ;
		USE SIGNAL ;
		PORT
			LAYER M1 ;
			RECT 0.145 2.365 0.595 2.815 ;
		END
		AntennaGateArea 0.5796 ;
	END sel
	PIN in1
		DIRECTION input ;
		USE SIGNAL ;
		PORT
			LAYER M1 ;
			RECT 3.62 3.945 3.96 4.285 ;
			LAYER M1 ;
			RECT 3.65 3.555 3.88 3.945 ;
			LAYER M1 ;
			RECT 3.65 3.105 4.295 3.555 ;
			LAYER M1 ;
			RECT 3.65 2.28 3.88 3.105 ;
			LAYER M1 ;
			RECT 3.62 1.94 3.96 2.28 ;
		END
		AntennaGateArea 0.2484 ;
	END in1
	PIN GND
		DIRECTION inout ;
		USE GROUND ;
		PORT
			LAYER M1 ;
			RECT 0.9 0.5 1.24 1.57 ;
			LAYER M1 ;
			RECT 3.86 0.5 4.2 1.57 ;
			LAYER M1 ;
			RECT 0 -0.5 5.18 0.5 ;
		END
	END GND
	PIN VDD
		DIRECTION inout ;
		USE POWER ;
		PORT
			LAYER M1 ;
			RECT 0 6.9 5.18 7.9 ;
			LAYER M1 ;
			RECT 0.9 4.6 1.24 6.9 ;
			LAYER M1 ;
			RECT 3.86 4.6 4.2 6.9 ;
		END
	END VDD
	PIN in0
		DIRECTION input ;
		USE SIGNAL ;
		PORT
			LAYER M1 ;
			RECT 0.885 4.245 1.335 4.295 ;
			LAYER M1 ;
			RECT 0.885 3.905 1.48 4.245 ;
			LAYER M1 ;
			RECT 0.885 3.845 1.335 3.905 ;
		END
		AntennaGateArea 0.2484 ;
	END in0
	OBS
		LAYER M1 ;
		RECT 0.18 4.6 0.52 5.44 ;
		LAYER M1 ;
		RECT 1.62 4.6 1.96 5.44 ;
		LAYER M1 ;
		RECT 2.38 4.6 2.72 6.36 ;
		LAYER M1 ;
		RECT 3.1 4.6 3.44 6.36 ;
		LAYER M1 ;
		RECT 0.29 3.44 0.52 4.6 ;
		LAYER M1 ;
		RECT 1.73 3.91 1.96 4.6 ;
		LAYER M1 ;
		RECT 2.49 4.37 2.72 4.6 ;
		LAYER M1 ;
		RECT 2.49 4.14 2.925 4.37 ;
		LAYER M1 ;
		RECT 1.73 3.68 2.35 3.91 ;
		LAYER M1 ;
		RECT 0.29 3.21 1.89 3.44 ;
		LAYER M1 ;
		RECT 0.925 2.045 1.155 3.21 ;
		LAYER M1 ;
		RECT 1.55 3.1 1.89 3.21 ;
		LAYER M1 ;
		RECT 2.12 2.495 2.35 3.68 ;
		LAYER M1 ;
		RECT 2.695 2.835 2.925 4.14 ;
		LAYER M1 ;
		RECT 2.59 2.495 2.93 2.835 ;
		LAYER M1 ;
		RECT 0.29 1.815 1.155 2.045 ;
		LAYER M1 ;
		RECT 1.73 2.265 2.35 2.495 ;
		LAYER M1 ;
		RECT 0.29 1.57 0.52 1.815 ;
		LAYER M1 ;
		RECT 1.73 1.57 1.96 2.265 ;
		LAYER M1 ;
		RECT 2.695 2.03 2.925 2.495 ;
		LAYER M1 ;
		RECT 2.49 1.8 2.925 2.03 ;
		LAYER M1 ;
		RECT 2.49 1.57 2.72 1.8 ;
		LAYER M1 ;
		RECT 3.16 1.57 3.39 4.6 ;
		LAYER M1 ;
		RECT 0.18 1.19 0.52 1.57 ;
		LAYER M1 ;
		RECT 1.62 1.19 1.96 1.57 ;
		LAYER M1 ;
		RECT 2.38 0.73 2.72 1.57 ;
		LAYER M1 ;
		RECT 3.1 0.73 3.44 1.57 ;
	END
END MMI_MUX2A
MACRO MMI_MUX2B
	CLASS CORE ;
	FOREIGN MMI_MUX2B 0 0 ;
	SIZE 5.18 BY 7.4 ;
	SYMMETRY X Y ;
	SITE CORE1 ;
	PIN out
		DIRECTION output ;
		USE SIGNAL ;
		PORT
			LAYER M1 ;
			RECT 4.66 4.61 5 6.37 ;
			LAYER M1 ;
			RECT 4.71 3.555 4.94 4.61 ;
			LAYER M1 ;
			RECT 4.585 3.105 5.035 3.555 ;
			LAYER M1 ;
			RECT 4.71 2.06 4.94 3.105 ;
			LAYER M1 ;
			RECT 4.66 1.22 5 2.06 ;
		END
		AntennaDiffArea 1.3248 ;
	END out
	PIN sel
		DIRECTION input ;
		USE SIGNAL ;
		PORT
			LAYER M1 ;
			RECT 0.145 2.365 0.595 2.815 ;
		END
		AntennaGateArea 0.7452 ;
	END sel
	PIN in1
		DIRECTION input ;
		USE SIGNAL ;
		PORT
			LAYER M1 ;
			RECT 3.65 3.885 3.99 4.225 ;
			LAYER M1 ;
			RECT 3.715 3.555 3.945 3.885 ;
			LAYER M1 ;
			RECT 3.715 3.105 4.295 3.555 ;
			LAYER M1 ;
			RECT 3.715 2.66 3.945 3.105 ;
			LAYER M1 ;
			RECT 3.66 2.32 4 2.66 ;
			LAYER M1 ;
			RECT 3.715 2.295 3.945 2.32 ;
		END
		AntennaGateArea 0.4968 ;
	END in1
	PIN GND
		DIRECTION inout ;
		USE GROUND ;
		PORT
			LAYER M1 ;
			RECT 0.9 0.5 1.24 1.6 ;
			LAYER M1 ;
			RECT 3.94 0.5 4.28 2.06 ;
			LAYER M1 ;
			RECT 0 -0.5 5.18 0.5 ;
		END
	END GND
	PIN VDD
		DIRECTION inout ;
		USE POWER ;
		PORT
			LAYER M1 ;
			RECT 0 6.9 5.18 7.9 ;
			LAYER M1 ;
			RECT 0.94 4.61 1.28 6.9 ;
			LAYER M1 ;
			RECT 3.94 4.61 4.28 6.9 ;
		END
	END VDD
	PIN in0
		DIRECTION input ;
		USE SIGNAL ;
		PORT
			LAYER M1 ;
			RECT 0.885 4.245 1.335 4.295 ;
			LAYER M1 ;
			RECT 0.885 3.905 1.48 4.245 ;
			LAYER M1 ;
			RECT 0.885 3.845 1.335 3.905 ;
		END
		AntennaGateArea 0.4968 ;
	END in0
	OBS
		LAYER M1 ;
		RECT 0.18 4.61 0.52 5.45 ;
		LAYER M1 ;
		RECT 1.7 4.61 2.04 6.37 ;
		LAYER M1 ;
		RECT 2.46 4.61 2.8 6.37 ;
		LAYER M1 ;
		RECT 3.18 4.61 3.52 6.37 ;
		LAYER M1 ;
		RECT 0.29 3.525 0.52 4.61 ;
		LAYER M1 ;
		RECT 1.81 4.02 2.04 4.61 ;
		LAYER M1 ;
		RECT 1.81 3.79 2.34 4.02 ;
		LAYER M1 ;
		RECT 0.29 3.295 1.88 3.525 ;
		LAYER M1 ;
		RECT 0.925 2.135 1.155 3.295 ;
		LAYER M1 ;
		RECT 1.54 3.185 1.88 3.295 ;
		LAYER M1 ;
		RECT 2.11 2.955 2.34 3.79 ;
		LAYER M1 ;
		RECT 0.29 1.905 1.155 2.135 ;
		LAYER M1 ;
		RECT 1.81 2.725 2.34 2.955 ;
		LAYER M1 ;
		RECT 2.57 3.095 2.8 4.61 ;
		LAYER M1 ;
		RECT 2.57 2.755 2.95 3.095 ;
		LAYER M1 ;
		RECT 1.81 2.06 2.04 2.725 ;
		LAYER M1 ;
		RECT 2.57 2.06 2.8 2.755 ;
		LAYER M1 ;
		RECT 3.19 2.06 3.42 4.61 ;
		LAYER M1 ;
		RECT 0.29 1.6 0.52 1.905 ;
		LAYER M1 ;
		RECT 0.18 1.22 0.52 1.6 ;
		LAYER M1 ;
		RECT 1.7 1.22 2.04 2.06 ;
		LAYER M1 ;
		RECT 2.46 1.22 2.8 2.06 ;
		LAYER M1 ;
		RECT 3.18 1.22 3.52 2.06 ;
	END
END MMI_MUX2B
MACRO MMI_MUX2C
	CLASS CORE ;
	FOREIGN MMI_MUX2C 0 0 ;
	SIZE 5.92 BY 7.4 ;
	SYMMETRY X Y ;
	SITE CORE1 ;
	PIN out
		DIRECTION output ;
		USE SIGNAL ;
		PORT
			LAYER M1 ;
			RECT 4.655 4.19 4.995 5.95 ;
			LAYER M1 ;
			RECT 4.69 2.88 4.92 4.19 ;
			LAYER M1 ;
			RECT 4.655 1.12 4.995 2.88 ;
		END
		AntennaDiffArea 1.8768 ;
	END out
	PIN sel
		DIRECTION input ;
		USE SIGNAL ;
		PORT
			LAYER M1 ;
			RECT 0.905 3.57 1.355 3.59 ;
			LAYER M1 ;
			RECT 0.705 3.23 1.355 3.57 ;
			LAYER M1 ;
			RECT 0.905 3.14 1.355 3.23 ;
		END
		AntennaGateArea 0.7452 ;
	END sel
	PIN in1
		DIRECTION input ;
		USE SIGNAL ;
		PORT
			LAYER M1 ;
			RECT 0.89 4.265 1.34 4.315 ;
			LAYER M1 ;
			RECT 0.89 3.925 1.46 4.265 ;
			LAYER M1 ;
			RECT 0.89 3.865 1.34 3.925 ;
		END
		AntennaGateArea 0.495 ;
	END in1
	PIN GND
		DIRECTION inout ;
		USE GROUND ;
		PORT
			LAYER M1 ;
			RECT 0.965 0.5 1.305 2.91 ;
			LAYER M1 ;
			RECT 3.935 0.5 4.275 2.88 ;
			LAYER M1 ;
			RECT 0 -0.5 5.92 0.5 ;
		END
	END GND
	PIN VDD
		DIRECTION inout ;
		USE POWER ;
		PORT
			LAYER M1 ;
			RECT 0 6.9 5.92 7.9 ;
			LAYER M1 ;
			RECT 0.965 4.6 1.305 6.9 ;
			LAYER M1 ;
			RECT 3.935 4.19 4.275 6.9 ;
			LAYER M1 ;
			RECT 5.375 4.19 5.715 6.9 ;
		END
	END VDD
	PIN in0
		DIRECTION input ;
		USE SIGNAL ;
		PORT
			LAYER M1 ;
			RECT 3.845 3.51 4.295 3.565 ;
			LAYER M1 ;
			RECT 3.74 3.17 4.295 3.51 ;
			LAYER M1 ;
			RECT 3.845 3.115 4.295 3.17 ;
		END
		AntennaGateArea 0.4968 ;
	END in0
	OBS
		LAYER M1 ;
		RECT 0.205 4.6 0.545 5.44 ;
		LAYER M1 ;
		RECT 1.725 4.6 2.065 6.36 ;
		LAYER M1 ;
		RECT 0.21 2.91 0.44 4.6 ;
		LAYER M1 ;
		RECT 0.205 2.53 0.545 2.91 ;
		LAYER M1 ;
		RECT 0.275 1.07 0.505 2.53 ;
		LAYER M1 ;
		RECT 0.225 0.73 0.565 1.07 ;
		LAYER M1 ;
		RECT 1.835 2.88 2.065 4.6 ;
		LAYER M1 ;
		RECT 1.725 2.04 2.065 2.88 ;
		LAYER M1 ;
		RECT 2.445 4.6 2.785 6.36 ;
		LAYER M1 ;
		RECT 3.165 4.6 3.505 6.36 ;
		LAYER M1 ;
		RECT 2.445 2.88 2.675 4.6 ;
		LAYER M1 ;
		RECT 3.275 2.88 3.505 4.6 ;
		LAYER M1 ;
		RECT 2.445 2.04 2.785 2.88 ;
		LAYER M1 ;
		RECT 3.165 2.04 3.505 2.88 ;
		LAYER M1 ;
		RECT 2.505 1.07 2.735 2.04 ;
		LAYER M1 ;
		RECT 3.245 1.07 3.585 1.135 ;
		LAYER M1 ;
		RECT 2.505 0.84 3.585 1.07 ;
		LAYER M1 ;
		RECT 3.245 0.795 3.585 0.84 ;
	END
END MMI_MUX2C
MACRO MMI_MUX2D
	CLASS CORE ;
	FOREIGN MMI_MUX2D 0 0 ;
	SIZE 11.1 BY 7.4 ;
	SYMMETRY X Y ;
	SITE CORE1 ;
	PIN out
		DIRECTION output ;
		USE SIGNAL ;
		PORT
			LAYER M1 ;
			RECT 9.14 3.85 9.48 6.55 ;
			LAYER M1 ;
			RECT 10.58 4.175 10.92 6.55 ;
			LAYER M1 ;
			RECT 10.54 3.85 10.92 4.175 ;
			LAYER M1 ;
			RECT 9.14 3.51 10.92 3.85 ;
			LAYER M1 ;
			RECT 9.14 1.44 9.48 3.51 ;
		END
		AntennaDiffArea 3.4977 ;
	END out
	PIN sel
		DIRECTION input ;
		USE SIGNAL ;
		PORT
			LAYER M1 ;
			RECT 5.46 4.01 5.8 4.12 ;
			LAYER M1 ;
			RECT 5.4 3.78 5.8 4.01 ;
			LAYER M1 ;
			RECT 5.4 3.52 5.725 3.78 ;
			LAYER M1 ;
			RECT 5.36 3.005 5.725 3.52 ;
			LAYER M1 ;
			RECT 5.04 2.775 5.725 3.005 ;
			LAYER M1 ;
			RECT 5.04 2.665 5.38 2.775 ;
		END
		AntennaGateArea 1.3284 ;
	END sel
	PIN in1
		DIRECTION input ;
		USE SIGNAL ;
		PORT
			LAYER M1 ;
			RECT 1.83 3.555 2.17 3.775 ;
			LAYER M1 ;
			RECT 1.625 3.435 2.17 3.555 ;
			LAYER M1 ;
			RECT 1.625 3.105 2.075 3.435 ;
		END
		AntennaGateArea 0.9936 ;
	END in1
	PIN GND
		DIRECTION inout ;
		USE GROUND ;
		PORT
			LAYER M1 ;
			RECT 0.2 0.5 0.54 2.845 ;
			LAYER M1 ;
			RECT 1.64 0.5 1.98 2.845 ;
			LAYER M1 ;
			RECT 3.08 0.5 3.42 2.845 ;
			LAYER M1 ;
			RECT 8.42 0.5 8.76 3.2 ;
			LAYER M1 ;
			RECT 9.86 0.5 10.2 3.2 ;
			LAYER M1 ;
			RECT 0 -0.5 11.1 0.5 ;
		END
	END GND
	PIN VDD
		DIRECTION inout ;
		USE POWER ;
		PORT
			LAYER M1 ;
			RECT 0 6.9 11.1 7.9 ;
			LAYER M1 ;
			RECT 0.2 4.45 0.54 6.9 ;
			LAYER M1 ;
			RECT 1.64 5.68 1.98 6.9 ;
			LAYER M1 ;
			RECT 3.08 5.68 3.42 6.9 ;
			LAYER M1 ;
			RECT 8.42 4.175 8.76 6.9 ;
			LAYER M1 ;
			RECT 9.86 4.175 10.2 6.9 ;
		END
	END VDD
	PIN in0
		DIRECTION input ;
		USE SIGNAL ;
		PORT
			LAYER M1 ;
			RECT 0.145 3.5 0.595 3.555 ;
			LAYER M1 ;
			RECT 0.145 3.16 0.65 3.5 ;
			LAYER M1 ;
			RECT 0.145 3.105 0.595 3.16 ;
		END
		AntennaGateArea 0.9936 ;
	END in0
	OBS
		LAYER M1 ;
		RECT 0.92 5.45 1.26 6.21 ;
		LAYER M1 ;
		RECT 3.83 6.44 6.99 6.67 ;
		LAYER M1 ;
		RECT 3.83 6.02 4.06 6.44 ;
		LAYER M1 ;
		RECT 5.27 6.025 5.5 6.44 ;
		LAYER M1 ;
		RECT 6.76 6.21 6.99 6.44 ;
		LAYER M1 ;
		RECT 3.78 5.68 4.12 6.02 ;
		LAYER M1 ;
		RECT 5.22 5.685 5.56 6.025 ;
		LAYER M1 ;
		RECT 5.94 5.45 6.28 6.21 ;
		LAYER M1 ;
		RECT 0.92 5.22 6.28 5.45 ;
		LAYER M1 ;
		RECT 0.92 4.45 1.26 5.22 ;
		LAYER M1 ;
		RECT 2.36 4.65 2.7 4.99 ;
		LAYER M1 ;
		RECT 4.5 4.65 4.84 4.99 ;
		LAYER M1 ;
		RECT 0.97 2.845 1.2 4.45 ;
		LAYER M1 ;
		RECT 2.415 3.635 2.645 4.65 ;
		LAYER M1 ;
		RECT 4.575 3.635 4.805 4.65 ;
		LAYER M1 ;
		RECT 5.94 4.45 6.28 5.22 ;
		LAYER M1 ;
		RECT 6.66 4.45 7 6.21 ;
		LAYER M1 ;
		RECT 2.415 3.405 4.805 3.635 ;
		LAYER M1 ;
		RECT 2.415 2.845 2.645 3.405 ;
		LAYER M1 ;
		RECT 0.92 2.005 1.26 2.845 ;
		LAYER M1 ;
		RECT 2.36 2.005 2.7 2.845 ;
		LAYER M1 ;
		RECT 4.575 2.415 4.805 3.405 ;
		LAYER M1 ;
		RECT 6.04 2.415 6.27 4.45 ;
		LAYER M1 ;
		RECT 6.76 2.415 6.99 4.45 ;
		LAYER M1 ;
		RECT 7.66 4.17 8 5.33 ;
		LAYER M1 ;
		RECT 7.66 3.44 7.89 4.17 ;
		LAYER M1 ;
		RECT 7.225 3.1 7.89 3.44 ;
		LAYER M1 ;
		RECT 7.66 2.645 7.89 3.1 ;
		LAYER M1 ;
		RECT 3.88 1.575 4.22 2.415 ;
		LAYER M1 ;
		RECT 4.575 2.13 4.94 2.415 ;
		LAYER M1 ;
		RECT 4.6 1.575 4.94 2.13 ;
		LAYER M1 ;
		RECT 5.32 1.575 5.66 2.415 ;
		LAYER M1 ;
		RECT 6.04 1.575 6.38 2.415 ;
		LAYER M1 ;
		RECT 6.76 1.575 7.1 2.415 ;
		LAYER M1 ;
		RECT 7.66 2.105 8 2.645 ;
		LAYER M1 ;
		RECT 3.99 1.345 4.22 1.575 ;
		LAYER M1 ;
		RECT 5.38 1.345 5.61 1.575 ;
		LAYER M1 ;
		RECT 6.76 1.345 6.99 1.575 ;
		LAYER M1 ;
		RECT 3.99 1.23 8.17 1.345 ;
		LAYER M1 ;
		RECT 3.99 1.115 8.175 1.23 ;
		LAYER M1 ;
		RECT 7.835 0.89 8.175 1.115 ;
	END
END MMI_MUX2D
MACRO MMI_MUX3B
	CLASS CORE ;
	FOREIGN MMI_MUX3B 0 0 ;
	SIZE 10.36 BY 7.4 ;
	SYMMETRY X Y ;
	SITE CORE1 ;
	PIN out
		DIRECTION output ;
		USE SIGNAL ;
		PORT
			LAYER M1 ;
			RECT 9.78 1.51 10.12 6.67 ;
		END
		AntennaDiffArea 1.3248 ;
	END out
	PIN in1
		DIRECTION input ;
		USE SIGNAL ;
		PORT
			LAYER M1 ;
			RECT 0.885 4.24 1.335 4.295 ;
			LAYER M1 ;
			RECT 0.885 3.9 1.435 4.24 ;
			LAYER M1 ;
			RECT 0.885 3.845 1.335 3.9 ;
		END
		AntennaGateArea 0.4968 ;
	END in1
	PIN sel0
		DIRECTION input ;
		USE SIGNAL ;
		PORT
			LAYER M1 ;
			RECT 4.585 3.5 5.035 3.555 ;
			LAYER M1 ;
			RECT 4.29 3.16 5.035 3.5 ;
			LAYER M1 ;
			RECT 4.585 3.105 5.035 3.16 ;
		END
		AntennaGateArea 0.7452 ;
	END sel0
	PIN GND
		DIRECTION inout ;
		USE GROUND ;
		PORT
			LAYER M1 ;
			RECT 0.9 0.5 1.24 2.865 ;
			LAYER M1 ;
			RECT 3.93 0.5 4.27 1.565 ;
			LAYER M1 ;
			RECT 7.485 0.5 7.825 1.88 ;
			LAYER M1 ;
			RECT 9.06 0.5 9.4 2.35 ;
			LAYER M1 ;
			RECT 0 -0.5 10.36 0.5 ;
		END
	END GND
	PIN in2
		DIRECTION input ;
		USE SIGNAL ;
		PORT
			LAYER M1 ;
			RECT 7.125 4.055 7.465 4.395 ;
			LAYER M1 ;
			RECT 7.195 3.55 7.425 4.055 ;
			LAYER M1 ;
			RECT 6.805 3.1 7.425 3.55 ;
			LAYER M1 ;
			RECT 7.165 2.575 7.505 3.1 ;
		END
		AntennaGateArea 0.4968 ;
	END in2
	PIN sel1
		DIRECTION input ;
		USE SIGNAL ;
		PORT
			LAYER M1 ;
			RECT 8.79 3.96 9.36 4.3 ;
			LAYER M1 ;
			RECT 9.055 2.925 9.36 3.96 ;
			LAYER M1 ;
			RECT 8.79 2.585 9.36 2.925 ;
		END
		AntennaGateArea 0.7452 ;
	END sel1
	PIN VDD
		DIRECTION inout ;
		USE POWER ;
		PORT
			LAYER M1 ;
			RECT 0 6.9 10.36 7.9 ;
			LAYER M1 ;
			RECT 0.9 5.81 1.24 6.9 ;
			LAYER M1 ;
			RECT 4.48 4.67 4.82 6.9 ;
			LAYER M1 ;
			RECT 7.485 5.91 7.825 6.9 ;
			LAYER M1 ;
			RECT 9.06 4.91 9.4 6.9 ;
		END
	END VDD
	PIN in0
		DIRECTION input ;
		USE SIGNAL ;
		PORT
			LAYER M1 ;
			RECT 0.885 3.5 1.335 3.555 ;
			LAYER M1 ;
			RECT 0.66 3.16 1.335 3.5 ;
			LAYER M1 ;
			RECT 0.885 3.105 1.335 3.16 ;
		END
		AntennaGateArea 0.4968 ;
	END in0
	OBS
		LAYER M1 ;
		RECT 0.18 5.58 0.52 6.345 ;
		LAYER M1 ;
		RECT 3.06 5.58 3.4 6.345 ;
		LAYER M1 ;
		RECT 0.18 5.35 3.4 5.58 ;
		LAYER M1 ;
		RECT 0.18 4.585 0.52 5.35 ;
		LAYER M1 ;
		RECT 1.62 4.78 1.96 5.12 ;
		LAYER M1 ;
		RECT 2.34 4.78 2.68 5.12 ;
		LAYER M1 ;
		RECT 0.2 2.865 0.43 4.585 ;
		LAYER M1 ;
		RECT 1.7 2.865 1.93 4.78 ;
		LAYER M1 ;
		RECT 2.4 2.865 2.63 4.78 ;
		LAYER M1 ;
		RECT 3.06 4.585 3.4 5.35 ;
		LAYER M1 ;
		RECT 3.76 4.67 4.1 5.51 ;
		LAYER M1 ;
		RECT 0.18 2.025 0.52 2.865 ;
		LAYER M1 ;
		RECT 0.2 1.985 0.43 2.025 ;
		LAYER M1 ;
		RECT 1.62 2.025 1.96 2.865 ;
		LAYER M1 ;
		RECT 2.34 2.035 2.68 2.865 ;
		LAYER M1 ;
		RECT 3.095 2.62 3.325 4.585 ;
		LAYER M1 ;
		RECT 3.82 4.075 4.05 4.67 ;
		LAYER M1 ;
		RECT 5.325 4.595 5.665 6.355 ;
		LAYER M1 ;
		RECT 6.045 5.68 6.385 6.355 ;
		LAYER M1 ;
		RECT 8.49 5.68 8.83 5.97 ;
		LAYER M1 ;
		RECT 6.045 5.45 8.83 5.68 ;
		LAYER M1 ;
		RECT 6.045 4.595 6.385 5.45 ;
		LAYER M1 ;
		RECT 6.765 5.11 7.105 5.22 ;
		LAYER M1 ;
		RECT 6.765 4.88 8.015 5.11 ;
		LAYER M1 ;
		RECT 3.81 3.935 4.05 4.075 ;
		LAYER M1 ;
		RECT 3.56 3.595 4.05 3.935 ;
		LAYER M1 ;
		RECT 3.82 2.735 4.05 3.595 ;
		LAYER M1 ;
		RECT 3.06 2.28 3.4 2.62 ;
		LAYER M1 ;
		RECT 3.82 2.495 4.285 2.735 ;
		LAYER M1 ;
		RECT 3.905 2.395 4.285 2.495 ;
		LAYER M1 ;
		RECT 5.385 2.035 5.615 4.595 ;
		LAYER M1 ;
		RECT 2.34 2.025 5.665 2.035 ;
		LAYER M1 ;
		RECT 1.7 1.995 1.93 2.025 ;
		LAYER M1 ;
		RECT 2.45 1.805 5.665 2.025 ;
		LAYER M1 ;
		RECT 6.1 1.88 6.33 4.595 ;
		LAYER M1 ;
		RECT 7.785 2.345 8.015 4.88 ;
		LAYER M1 ;
		RECT 6.875 2.115 8.015 2.345 ;
		LAYER M1 ;
		RECT 8.245 4.84 8.585 5.18 ;
		LAYER M1 ;
		RECT 8.245 3.625 8.475 4.84 ;
		LAYER M1 ;
		RECT 8.245 3.285 8.605 3.625 ;
		LAYER M1 ;
		RECT 6.875 1.88 7.105 2.115 ;
		LAYER M1 ;
		RECT 8.245 1.88 8.475 3.285 ;
		LAYER M1 ;
		RECT 5.325 1.04 5.665 1.805 ;
		LAYER M1 ;
		RECT 6.045 1.04 6.385 1.88 ;
		LAYER M1 ;
		RECT 6.765 1.04 7.105 1.88 ;
		LAYER M1 ;
		RECT 8.245 1.5 8.585 1.88 ;
	END
END MMI_MUX3B
MACRO MMI_MUX3C
	CLASS CORE ;
	FOREIGN MMI_MUX3C 0 0 ;
	SIZE 11.1 BY 7.4 ;
	SYMMETRY X Y ;
	SITE CORE1 ;
	PIN out
		DIRECTION output ;
		USE SIGNAL ;
		PORT
			LAYER M1 ;
			RECT 9.78 1.5 10.12 6.67 ;
		END
		AntennaDiffArea 1.4904 ;
	END out
	PIN sel0
		DIRECTION input ;
		USE SIGNAL ;
		PORT
			LAYER M1 ;
			RECT 4.585 3.5 5.035 3.555 ;
			LAYER M1 ;
			RECT 4.29 3.16 5.035 3.5 ;
			LAYER M1 ;
			RECT 4.585 3.105 5.035 3.16 ;
		END
		AntennaGateArea 0.7452 ;
	END sel0
	PIN in1
		DIRECTION input ;
		USE SIGNAL ;
		PORT
			LAYER M1 ;
			RECT 0.885 4.24 1.335 4.295 ;
			LAYER M1 ;
			RECT 0.885 3.9 1.435 4.24 ;
			LAYER M1 ;
			RECT 0.885 3.845 1.335 3.9 ;
		END
		AntennaGateArea 0.4968 ;
	END in1
	PIN GND
		DIRECTION inout ;
		USE GROUND ;
		PORT
			LAYER M1 ;
			RECT 0.9 0.5 1.24 2.865 ;
			LAYER M1 ;
			RECT 3.93 0.5 4.27 1.565 ;
			LAYER M1 ;
			RECT 7.485 0.5 7.825 1.88 ;
			LAYER M1 ;
			RECT 9.06 0.5 9.4 2.34 ;
			LAYER M1 ;
			RECT 10.5 0.5 10.84 2.34 ;
			LAYER M1 ;
			RECT 0 -0.5 11.1 0.5 ;
		END
	END GND
	PIN in2
		DIRECTION input ;
		USE SIGNAL ;
		PORT
			LAYER M1 ;
			RECT 7.125 4.055 7.465 4.395 ;
			LAYER M1 ;
			RECT 7.195 3.55 7.425 4.055 ;
			LAYER M1 ;
			RECT 6.805 3.1 7.425 3.55 ;
			LAYER M1 ;
			RECT 7.165 2.575 7.505 3.1 ;
		END
		AntennaGateArea 0.4968 ;
	END in2
	PIN sel1
		DIRECTION input ;
		USE SIGNAL ;
		PORT
			LAYER M1 ;
			RECT 8.79 3.96 9.36 4.3 ;
			LAYER M1 ;
			RECT 9.06 2.915 9.36 3.96 ;
			LAYER M1 ;
			RECT 8.79 2.575 9.36 2.915 ;
		END
		AntennaGateArea 0.7452 ;
	END sel1
	PIN VDD
		DIRECTION inout ;
		USE POWER ;
		PORT
			LAYER M1 ;
			RECT 0 6.9 11.1 7.9 ;
			LAYER M1 ;
			RECT 0.9 5.81 1.24 6.9 ;
			LAYER M1 ;
			RECT 4.48 4.67 4.82 6.9 ;
			LAYER M1 ;
			RECT 7.485 5.91 7.825 6.9 ;
			LAYER M1 ;
			RECT 9.06 4.91 9.4 6.9 ;
			LAYER M1 ;
			RECT 10.5 4.91 10.84 6.9 ;
		END
	END VDD
	PIN in0
		DIRECTION input ;
		USE SIGNAL ;
		PORT
			LAYER M1 ;
			RECT 0.885 3.5 1.335 3.555 ;
			LAYER M1 ;
			RECT 0.66 3.16 1.335 3.5 ;
			LAYER M1 ;
			RECT 0.885 3.105 1.335 3.16 ;
		END
		AntennaGateArea 0.4968 ;
	END in0
	OBS
		LAYER M1 ;
		RECT 0.18 5.58 0.52 6.345 ;
		LAYER M1 ;
		RECT 3.06 5.58 3.4 6.345 ;
		LAYER M1 ;
		RECT 0.18 5.35 3.4 5.58 ;
		LAYER M1 ;
		RECT 0.18 4.585 0.52 5.35 ;
		LAYER M1 ;
		RECT 1.62 4.78 1.96 5.12 ;
		LAYER M1 ;
		RECT 2.34 4.78 2.68 5.12 ;
		LAYER M1 ;
		RECT 0.2 2.865 0.43 4.585 ;
		LAYER M1 ;
		RECT 1.7 2.865 1.93 4.78 ;
		LAYER M1 ;
		RECT 2.4 2.865 2.63 4.78 ;
		LAYER M1 ;
		RECT 3.06 4.585 3.4 5.35 ;
		LAYER M1 ;
		RECT 3.76 4.67 4.1 5.51 ;
		LAYER M1 ;
		RECT 0.18 2.025 0.52 2.865 ;
		LAYER M1 ;
		RECT 0.2 1.985 0.43 2.025 ;
		LAYER M1 ;
		RECT 1.62 2.025 1.96 2.865 ;
		LAYER M1 ;
		RECT 2.34 2.035 2.68 2.865 ;
		LAYER M1 ;
		RECT 3.095 2.62 3.325 4.585 ;
		LAYER M1 ;
		RECT 3.82 4.075 4.05 4.67 ;
		LAYER M1 ;
		RECT 5.325 4.595 5.665 6.355 ;
		LAYER M1 ;
		RECT 6.045 5.68 6.385 6.355 ;
		LAYER M1 ;
		RECT 8.49 5.68 8.83 5.97 ;
		LAYER M1 ;
		RECT 6.045 5.45 8.83 5.68 ;
		LAYER M1 ;
		RECT 6.045 4.595 6.385 5.45 ;
		LAYER M1 ;
		RECT 6.765 5.11 7.105 5.22 ;
		LAYER M1 ;
		RECT 6.765 4.88 8.015 5.11 ;
		LAYER M1 ;
		RECT 3.81 3.935 4.05 4.075 ;
		LAYER M1 ;
		RECT 3.56 3.595 4.05 3.935 ;
		LAYER M1 ;
		RECT 3.82 2.735 4.05 3.595 ;
		LAYER M1 ;
		RECT 3.06 2.28 3.4 2.62 ;
		LAYER M1 ;
		RECT 3.82 2.495 4.285 2.735 ;
		LAYER M1 ;
		RECT 3.905 2.395 4.285 2.495 ;
		LAYER M1 ;
		RECT 5.385 2.035 5.615 4.595 ;
		LAYER M1 ;
		RECT 2.34 2.025 5.665 2.035 ;
		LAYER M1 ;
		RECT 1.7 1.995 1.93 2.025 ;
		LAYER M1 ;
		RECT 2.45 1.805 5.665 2.025 ;
		LAYER M1 ;
		RECT 6.1 1.88 6.33 4.595 ;
		LAYER M1 ;
		RECT 7.785 2.345 8.015 4.88 ;
		LAYER M1 ;
		RECT 6.875 2.115 8.015 2.345 ;
		LAYER M1 ;
		RECT 8.245 4.84 8.585 5.18 ;
		LAYER M1 ;
		RECT 8.245 3.625 8.475 4.84 ;
		LAYER M1 ;
		RECT 8.245 3.285 8.605 3.625 ;
		LAYER M1 ;
		RECT 6.875 1.88 7.105 2.115 ;
		LAYER M1 ;
		RECT 8.245 1.88 8.475 3.285 ;
		LAYER M1 ;
		RECT 5.325 1.04 5.665 1.805 ;
		LAYER M1 ;
		RECT 6.045 1.04 6.385 1.88 ;
		LAYER M1 ;
		RECT 6.765 1.04 7.105 1.88 ;
		LAYER M1 ;
		RECT 8.245 1.5 8.585 1.88 ;
	END
END MMI_MUX3C
MACRO MMI_MUX4B
	CLASS CORE ;
	FOREIGN MMI_MUX4B 0 0 ;
	SIZE 12.58 BY 7.4 ;
	SYMMETRY X Y ;
	SITE CORE1 ;
	PIN out
		DIRECTION output ;
		USE SIGNAL ;
		PORT
			LAYER M1 ;
			RECT 12.05 1.75 12.39 6.225 ;
		END
		AntennaDiffArea 1.3248 ;
	END out
	PIN sel0
		DIRECTION input ;
		USE SIGNAL ;
		PORT
			LAYER M1 ;
			RECT 3.15 3.095 3.75 3.56 ;
		END
		AntennaGateArea 1.3284 ;
	END sel0
	PIN in1
		DIRECTION input ;
		USE SIGNAL ;
		PORT
			LAYER M1 ;
			RECT 0.885 4.205 1.335 4.295 ;
			LAYER M1 ;
			RECT 0.66 3.865 1.335 4.205 ;
			LAYER M1 ;
			RECT 0.885 3.845 1.335 3.865 ;
		END
		AntennaGateArea 0.4968 ;
	END in1
	PIN GND
		DIRECTION inout ;
		USE GROUND ;
		PORT
			LAYER M1 ;
			RECT 0.94 0.5 1.28 1.8 ;
			LAYER M1 ;
			RECT 4.85 0.5 5.19 2.83 ;
			LAYER M1 ;
			RECT 7.73 1.99 8.07 2.83 ;
			LAYER M1 ;
			RECT 7.73 0.5 7.96 1.99 ;
			LAYER M1 ;
			RECT 11.33 0.5 11.67 2.59 ;
			LAYER M1 ;
			RECT 0 -0.5 12.58 0.5 ;
		END
	END GND
	PIN in2
		DIRECTION input ;
		USE SIGNAL ;
		PORT
			LAYER M1 ;
			RECT 4.585 3.5 5.035 3.555 ;
			LAYER M1 ;
			RECT 4.585 3.16 5.35 3.5 ;
			LAYER M1 ;
			RECT 4.585 3.105 5.035 3.16 ;
		END
		AntennaGateArea 0.4968 ;
	END in2
	PIN sel1
		DIRECTION input ;
		USE SIGNAL ;
		PORT
			LAYER M1 ;
			RECT 11.245 3.5 11.695 3.555 ;
			LAYER M1 ;
			RECT 11.1 3.16 11.695 3.5 ;
			LAYER M1 ;
			RECT 11.245 3.105 11.695 3.16 ;
		END
		AntennaGateArea 0.7452 ;
	END sel1
	PIN VDD
		DIRECTION inout ;
		USE POWER ;
		PORT
			LAYER M1 ;
			RECT 0 6.9 12.58 7.9 ;
			LAYER M1 ;
			RECT 0.9 6.22 1.24 6.9 ;
			LAYER M1 ;
			RECT 7.73 5.965 8.07 6.9 ;
			LAYER M1 ;
			RECT 4.85 5.625 8.07 5.965 ;
			LAYER M1 ;
			RECT 11.33 5.73 11.67 6.9 ;
		END
	END VDD
	PIN in3
		DIRECTION input ;
		USE SIGNAL ;
		PORT
			LAYER M1 ;
			RECT 7.545 3.5 7.995 3.555 ;
			LAYER M1 ;
			RECT 7.545 3.16 8.01 3.5 ;
			LAYER M1 ;
			RECT 7.545 3.105 7.995 3.16 ;
		END
		AntennaGateArea 0.4968 ;
	END in3
	PIN in0
		DIRECTION input ;
		USE SIGNAL ;
		PORT
			LAYER M1 ;
			RECT 0.885 3.5 1.335 3.555 ;
			LAYER M1 ;
			RECT 0.885 3.16 1.515 3.5 ;
			LAYER M1 ;
			RECT 0.885 3.105 1.335 3.16 ;
		END
		AntennaGateArea 0.4968 ;
	END in0
	OBS
		LAYER M1 ;
		RECT 0.18 5.99 0.52 6.67 ;
		LAYER M1 ;
		RECT 3.7 6.435 6.99 6.665 ;
		LAYER M1 ;
		RECT 3.06 5.99 3.4 6.1 ;
		LAYER M1 ;
		RECT 0.18 5.76 3.4 5.99 ;
		LAYER M1 ;
		RECT 3.7 5.96 3.93 6.435 ;
		LAYER M1 ;
		RECT 6.65 6.325 6.99 6.435 ;
		LAYER M1 ;
		RECT 9.26 6.415 10.835 6.645 ;
		LAYER M1 ;
		RECT 9.26 6.185 9.49 6.415 ;
		LAYER M1 ;
		RECT 0.18 4.91 0.52 5.76 ;
		LAYER M1 ;
		RECT 3.63 5.62 3.97 5.96 ;
		LAYER M1 ;
		RECT 2.34 5.39 2.68 5.53 ;
		LAYER M1 ;
		RECT 8.43 5.39 8.77 6.185 ;
		LAYER M1 ;
		RECT 1.62 4.91 1.96 5.25 ;
		LAYER M1 ;
		RECT 0.18 2.83 0.41 4.91 ;
		LAYER M1 ;
		RECT 1.73 4.02 1.96 4.91 ;
		LAYER M1 ;
		RECT 2.34 5.16 8.77 5.39 ;
		LAYER M1 ;
		RECT 2.34 4.72 2.68 5.16 ;
		LAYER M1 ;
		RECT 1.73 3.79 2.04 4.02 ;
		LAYER M1 ;
		RECT 1.81 2.83 2.04 3.79 ;
		LAYER M1 ;
		RECT 2.43 2.83 2.66 4.72 ;
		LAYER M1 ;
		RECT 3.565 4.585 4.43 4.925 ;
		LAYER M1 ;
		RECT 5.57 4.59 5.91 4.93 ;
		LAYER M1 ;
		RECT 6.29 4.59 6.63 4.93 ;
		LAYER M1 ;
		RECT 7.01 4.59 7.35 4.93 ;
		LAYER M1 ;
		RECT 3.565 4.555 4.345 4.585 ;
		LAYER M1 ;
		RECT 4.115 2.83 4.345 4.555 ;
		LAYER M1 ;
		RECT 5.68 2.83 5.91 4.59 ;
		LAYER M1 ;
		RECT 6.4 2.83 6.63 4.59 ;
		LAYER M1 ;
		RECT 7.085 2.83 7.315 4.59 ;
		LAYER M1 ;
		RECT 8.43 4.425 8.77 5.16 ;
		LAYER M1 ;
		RECT 9.15 4.425 9.49 6.185 ;
		LAYER M1 ;
		RECT 9.87 4.935 10.21 6.185 ;
		LAYER M1 ;
		RECT 10.605 5.5 10.835 6.415 ;
		LAYER M1 ;
		RECT 10.605 5.27 11.53 5.5 ;
		LAYER M1 ;
		RECT 9.845 4.425 10.21 4.935 ;
		LAYER M1 ;
		RECT 10.57 4.7 10.91 5.04 ;
		LAYER M1 ;
		RECT 8.54 2.88 8.77 4.425 ;
		LAYER M1 ;
		RECT 9.205 2.88 9.435 4.425 ;
		LAYER M1 ;
		RECT 9.845 2.88 10.075 4.425 ;
		LAYER M1 ;
		RECT 10.57 3.62 10.8 4.7 ;
		LAYER M1 ;
		RECT 11.3 4.205 11.53 5.27 ;
		LAYER M1 ;
		RECT 11.3 3.865 11.82 4.205 ;
		LAYER M1 ;
		RECT 10.305 3.28 10.8 3.62 ;
		LAYER M1 ;
		RECT 0.18 2.26 0.52 2.83 ;
		LAYER M1 ;
		RECT 1.7 2.49 2.04 2.83 ;
		LAYER M1 ;
		RECT 2.42 2.49 2.76 2.83 ;
		LAYER M1 ;
		RECT 3.14 2.26 3.48 2.83 ;
		LAYER M1 ;
		RECT 0.18 2.03 3.48 2.26 ;
		LAYER M1 ;
		RECT 4.09 2.29 4.43 2.83 ;
		LAYER M1 ;
		RECT 4.09 2.085 4.32 2.29 ;
		LAYER M1 ;
		RECT 0.18 1.99 0.52 2.03 ;
		LAYER M1 ;
		RECT 3.14 1.99 3.48 2.03 ;
		LAYER M1 ;
		RECT 3.815 1.745 4.32 2.085 ;
		LAYER M1 ;
		RECT 5.57 1.99 5.91 2.83 ;
		LAYER M1 ;
		RECT 6.29 1.99 6.63 2.83 ;
		LAYER M1 ;
		RECT 7.01 1.99 7.35 2.83 ;
		LAYER M1 ;
		RECT 8.43 2.04 8.77 2.88 ;
		LAYER M1 ;
		RECT 9.15 2.04 9.49 2.88 ;
		LAYER M1 ;
		RECT 9.845 2.04 10.21 2.88 ;
		LAYER M1 ;
		RECT 10.57 2.59 10.8 3.28 ;
		LAYER M1 ;
		RECT 10.57 2.21 10.91 2.59 ;
		LAYER M1 ;
		RECT 6.325 1.335 6.555 1.99 ;
		LAYER M1 ;
		RECT 7.145 1.335 7.485 1.39 ;
		LAYER M1 ;
		RECT 6.325 1.105 7.485 1.335 ;
		LAYER M1 ;
		RECT 7.145 1.05 7.485 1.105 ;
		LAYER M1 ;
		RECT 8.2 1.325 8.54 1.385 ;
		LAYER M1 ;
		RECT 9.845 1.325 10.075 2.04 ;
		LAYER M1 ;
		RECT 8.2 1.095 10.075 1.325 ;
		LAYER M1 ;
		RECT 8.2 1.085 8.655 1.095 ;
		LAYER M1 ;
		RECT 8.2 1.045 8.54 1.085 ;
	END
END MMI_MUX4B
MACRO MMI_MUX4C
	CLASS CORE ;
	FOREIGN MMI_MUX4C 0 0 ;
	SIZE 13.32 BY 7.4 ;
	SYMMETRY X Y ;
	SITE CORE1 ;
	PIN out
		DIRECTION output ;
		USE SIGNAL ;
		PORT
			LAYER M1 ;
			RECT 12.05 1.75 12.39 6.225 ;
		END
		AntennaDiffArea 1.4904 ;
	END out
	PIN sel0
		DIRECTION input ;
		USE SIGNAL ;
		PORT
			LAYER M1 ;
			RECT 3.15 3.095 3.75 3.56 ;
		END
		AntennaGateArea 1.3284 ;
	END sel0
	PIN in1
		DIRECTION input ;
		USE SIGNAL ;
		PORT
			LAYER M1 ;
			RECT 0.885 4.205 1.335 4.295 ;
			LAYER M1 ;
			RECT 0.66 3.865 1.335 4.205 ;
			LAYER M1 ;
			RECT 0.885 3.845 1.335 3.865 ;
		END
		AntennaGateArea 0.4968 ;
	END in1
	PIN GND
		DIRECTION inout ;
		USE GROUND ;
		PORT
			LAYER M1 ;
			RECT 0.94 0.5 1.28 1.8 ;
			LAYER M1 ;
			RECT 4.85 0.5 5.19 2.83 ;
			LAYER M1 ;
			RECT 7.73 1.99 8.07 2.83 ;
			LAYER M1 ;
			RECT 7.73 0.5 7.96 1.99 ;
			LAYER M1 ;
			RECT 11.33 0.5 11.67 2.59 ;
			LAYER M1 ;
			RECT 12.77 0.5 13.11 2.59 ;
			LAYER M1 ;
			RECT 0 -0.5 13.32 0.5 ;
		END
	END GND
	PIN in2
		DIRECTION input ;
		USE SIGNAL ;
		PORT
			LAYER M1 ;
			RECT 4.585 3.5 5.035 3.555 ;
			LAYER M1 ;
			RECT 4.585 3.16 5.35 3.5 ;
			LAYER M1 ;
			RECT 4.585 3.105 5.035 3.16 ;
		END
		AntennaGateArea 0.4968 ;
	END in2
	PIN sel1
		DIRECTION input ;
		USE SIGNAL ;
		PORT
			LAYER M1 ;
			RECT 11.245 3.5 11.695 3.555 ;
			LAYER M1 ;
			RECT 11.1 3.16 11.695 3.5 ;
			LAYER M1 ;
			RECT 11.245 3.105 11.695 3.16 ;
		END
		AntennaGateArea 0.7452 ;
	END sel1
	PIN VDD
		DIRECTION inout ;
		USE POWER ;
		PORT
			LAYER M1 ;
			RECT 0 6.9 13.32 7.9 ;
			LAYER M1 ;
			RECT 0.9 5.995 1.24 6.9 ;
			LAYER M1 ;
			RECT 7.73 5.965 8.07 6.9 ;
			LAYER M1 ;
			RECT 4.85 5.625 8.07 5.965 ;
			LAYER M1 ;
			RECT 11.33 5.885 11.67 6.9 ;
			LAYER M1 ;
			RECT 12.77 4.465 13.11 6.9 ;
		END
	END VDD
	PIN in3
		DIRECTION input ;
		USE SIGNAL ;
		PORT
			LAYER M1 ;
			RECT 7.545 3.5 7.995 3.555 ;
			LAYER M1 ;
			RECT 7.545 3.16 8.01 3.5 ;
			LAYER M1 ;
			RECT 7.545 3.105 7.995 3.16 ;
		END
		AntennaGateArea 0.4968 ;
	END in3
	PIN in0
		DIRECTION input ;
		USE SIGNAL ;
		PORT
			LAYER M1 ;
			RECT 0.885 3.5 1.335 3.555 ;
			LAYER M1 ;
			RECT 0.885 3.16 1.515 3.5 ;
			LAYER M1 ;
			RECT 0.885 3.105 1.335 3.16 ;
		END
		AntennaGateArea 0.4968 ;
	END in0
	OBS
		LAYER M1 ;
		RECT 0.18 5.735 0.52 6.67 ;
		LAYER M1 ;
		RECT 3.7 6.435 6.99 6.665 ;
		LAYER M1 ;
		RECT 3.06 5.99 3.4 6.1 ;
		LAYER M1 ;
		RECT 1.81 5.76 3.4 5.99 ;
		LAYER M1 ;
		RECT 3.7 5.96 3.93 6.435 ;
		LAYER M1 ;
		RECT 6.65 6.325 6.99 6.435 ;
		LAYER M1 ;
		RECT 1.81 5.735 2.04 5.76 ;
		LAYER M1 ;
		RECT 0.18 5.505 2.04 5.735 ;
		LAYER M1 ;
		RECT 3.63 5.62 3.97 5.96 ;
		LAYER M1 ;
		RECT 0.18 4.91 0.52 5.505 ;
		LAYER M1 ;
		RECT 2.34 5.39 2.68 5.53 ;
		LAYER M1 ;
		RECT 8.43 5.39 8.77 6.185 ;
		LAYER M1 ;
		RECT 1.62 4.91 1.96 5.25 ;
		LAYER M1 ;
		RECT 0.18 2.83 0.41 4.91 ;
		LAYER M1 ;
		RECT 1.73 4.02 1.96 4.91 ;
		LAYER M1 ;
		RECT 2.34 5.16 8.77 5.39 ;
		LAYER M1 ;
		RECT 2.34 4.72 2.68 5.16 ;
		LAYER M1 ;
		RECT 1.73 3.79 2.04 4.02 ;
		LAYER M1 ;
		RECT 1.81 2.83 2.04 3.79 ;
		LAYER M1 ;
		RECT 2.43 2.83 2.66 4.72 ;
		LAYER M1 ;
		RECT 3.565 4.585 4.43 4.925 ;
		LAYER M1 ;
		RECT 5.57 4.59 5.91 4.93 ;
		LAYER M1 ;
		RECT 6.29 4.59 6.63 4.93 ;
		LAYER M1 ;
		RECT 7.01 4.59 7.35 4.93 ;
		LAYER M1 ;
		RECT 3.565 4.555 4.35 4.585 ;
		LAYER M1 ;
		RECT 4.12 2.83 4.35 4.555 ;
		LAYER M1 ;
		RECT 5.68 2.83 5.91 4.59 ;
		LAYER M1 ;
		RECT 6.4 2.83 6.63 4.59 ;
		LAYER M1 ;
		RECT 7.085 2.83 7.315 4.59 ;
		LAYER M1 ;
		RECT 8.43 4.425 8.77 5.16 ;
		LAYER M1 ;
		RECT 9.15 5.765 9.49 6.185 ;
		LAYER M1 ;
		RECT 9.15 5.535 10.835 5.765 ;
		LAYER M1 ;
		RECT 9.15 4.425 9.49 5.535 ;
		LAYER M1 ;
		RECT 10.605 5.5 10.835 5.535 ;
		LAYER M1 ;
		RECT 10.605 5.27 11.53 5.5 ;
		LAYER M1 ;
		RECT 9.87 4.935 10.21 5.235 ;
		LAYER M1 ;
		RECT 0.18 2.26 0.52 2.83 ;
		LAYER M1 ;
		RECT 1.7 2.49 2.04 2.83 ;
		LAYER M1 ;
		RECT 2.42 2.49 2.76 2.83 ;
		LAYER M1 ;
		RECT 3.14 2.26 3.48 2.83 ;
		LAYER M1 ;
		RECT 0.18 2.03 3.48 2.26 ;
		LAYER M1 ;
		RECT 4.09 2.29 4.43 2.83 ;
		LAYER M1 ;
		RECT 4.09 2.085 4.32 2.29 ;
		LAYER M1 ;
		RECT 0.18 1.99 0.52 2.03 ;
		LAYER M1 ;
		RECT 3.14 1.99 3.48 2.03 ;
		LAYER M1 ;
		RECT 3.815 1.745 4.32 2.085 ;
		LAYER M1 ;
		RECT 5.57 1.99 5.91 2.83 ;
		LAYER M1 ;
		RECT 6.29 1.99 6.63 2.83 ;
		LAYER M1 ;
		RECT 7.01 1.99 7.35 2.83 ;
		LAYER M1 ;
		RECT 8.54 2.41 8.77 4.425 ;
		LAYER M1 ;
		RECT 9.26 2.41 9.49 4.425 ;
		LAYER M1 ;
		RECT 6.325 1.105 6.555 1.99 ;
		LAYER M1 ;
		RECT 7.145 1.105 7.485 1.16 ;
		LAYER M1 ;
		RECT 6.325 0.875 7.485 1.105 ;
		LAYER M1 ;
		RECT 7.145 0.82 7.485 0.875 ;
		LAYER M1 ;
		RECT 8.43 1.57 8.77 2.41 ;
		LAYER M1 ;
		RECT 9.15 1.57 9.49 2.41 ;
		LAYER M1 ;
		RECT 9.845 4.425 10.21 4.935 ;
		LAYER M1 ;
		RECT 10.57 4.7 10.91 5.04 ;
		LAYER M1 ;
		RECT 9.845 2.41 10.075 4.425 ;
		LAYER M1 ;
		RECT 10.57 3.13 10.8 4.7 ;
		LAYER M1 ;
		RECT 11.3 4.205 11.53 5.27 ;
		LAYER M1 ;
		RECT 11.3 3.865 11.82 4.205 ;
		LAYER M1 ;
		RECT 10.305 2.64 10.8 3.13 ;
		LAYER M1 ;
		RECT 10.57 2.59 10.8 2.64 ;
		LAYER M1 ;
		RECT 9.845 1.57 10.21 2.41 ;
		LAYER M1 ;
		RECT 10.57 2.21 10.91 2.59 ;
		LAYER M1 ;
		RECT 8.2 1.095 8.54 1.155 ;
		LAYER M1 ;
		RECT 9.845 1.095 10.075 1.57 ;
		LAYER M1 ;
		RECT 8.2 0.865 10.075 1.095 ;
		LAYER M1 ;
		RECT 8.2 0.855 8.655 0.865 ;
		LAYER M1 ;
		RECT 8.2 0.815 8.54 0.855 ;
	END
END MMI_MUX4C
MACRO MMI_MUXI2A
	CLASS CORE ;
	FOREIGN MMI_MUXI2A 0 0 ;
	SIZE 4.44 BY 7.4 ;
	SYMMETRY X Y ;
	SITE CORE1 ;
	PIN out
		DIRECTION output ;
		USE SIGNAL ;
		PORT
			LAYER M1 ;
			RECT 2.445 4.6 2.785 6.36 ;
			LAYER M1 ;
			RECT 2.47 2.87 2.7 4.6 ;
			LAYER M1 ;
			RECT 2.445 2.03 2.785 2.87 ;
		END
		AntennaDiffArea 1.4904 ;
	END out
	PIN sel
		DIRECTION input ;
		USE SIGNAL ;
		PORT
			LAYER M1 ;
			RECT 0.905 3.57 1.355 3.59 ;
			LAYER M1 ;
			RECT 0.705 3.23 1.355 3.57 ;
			LAYER M1 ;
			RECT 0.905 3.14 1.355 3.23 ;
		END
		AntennaGateArea 0.7452 ;
	END sel
	PIN in1
		DIRECTION input ;
		USE SIGNAL ;
		PORT
			LAYER M1 ;
			RECT 0.89 4.265 1.34 4.315 ;
			LAYER M1 ;
			RECT 0.89 3.925 1.46 4.265 ;
			LAYER M1 ;
			RECT 0.89 3.865 1.34 3.925 ;
		END
		AntennaGateArea 0.495 ;
	END in1
	PIN GND
		DIRECTION inout ;
		USE GROUND ;
		PORT
			LAYER M1 ;
			RECT 0.965 0.5 1.305 2.91 ;
			LAYER M1 ;
			RECT 3.885 0.5 4.225 2.87 ;
			LAYER M1 ;
			RECT 0 -0.5 4.44 0.5 ;
		END
	END GND
	PIN VDD
		DIRECTION inout ;
		USE POWER ;
		PORT
			LAYER M1 ;
			RECT 0 6.9 4.44 7.9 ;
			LAYER M1 ;
			RECT 0.965 4.6 1.305 6.9 ;
			LAYER M1 ;
			RECT 3.885 4.6 4.225 6.9 ;
		END
	END VDD
	PIN in0
		DIRECTION input ;
		USE SIGNAL ;
		PORT
			LAYER M1 ;
			RECT 3.845 3.51 4.295 3.565 ;
			LAYER M1 ;
			RECT 3.74 3.17 4.295 3.51 ;
			LAYER M1 ;
			RECT 3.845 3.115 4.295 3.17 ;
		END
		AntennaGateArea 0.4968 ;
	END in0
	OBS
		LAYER M1 ;
		RECT 0.205 4.6 0.545 5.44 ;
		LAYER M1 ;
		RECT 1.725 4.6 2.065 6.36 ;
		LAYER M1 ;
		RECT 3.165 4.6 3.505 6.36 ;
		LAYER M1 ;
		RECT 0.21 2.91 0.44 4.6 ;
		LAYER M1 ;
		RECT 0.205 2.53 0.545 2.91 ;
		LAYER M1 ;
		RECT 0.275 1.07 0.505 2.53 ;
		LAYER M1 ;
		RECT 0.225 0.73 0.565 1.07 ;
		LAYER M1 ;
		RECT 1.835 2.87 2.065 4.6 ;
		LAYER M1 ;
		RECT 3.275 2.87 3.505 4.6 ;
		LAYER M1 ;
		RECT 1.725 2.03 2.065 2.87 ;
		LAYER M1 ;
		RECT 3.165 2.03 3.505 2.87 ;
		LAYER M1 ;
		RECT 2.785 1.455 3.125 1.795 ;
		LAYER M1 ;
		RECT 1.58 0.995 1.92 1.07 ;
		LAYER M1 ;
		RECT 2.845 0.995 3.075 1.455 ;
		LAYER M1 ;
		RECT 1.58 0.765 3.075 0.995 ;
		LAYER M1 ;
		RECT 1.58 0.73 1.92 0.765 ;
	END
END MMI_MUXI2A
MACRO MMI_MUXI2B
	CLASS CORE ;
	FOREIGN MMI_MUXI2B 0 0 ;
	SIZE 8.14 BY 7.4 ;
	SYMMETRY X Y ;
	SITE CORE1 ;
	PIN out
		DIRECTION output ;
		USE SIGNAL ;
		PORT
			LAYER M1 ;
			RECT 4.57 6.44 7.73 6.67 ;
			LAYER M1 ;
			RECT 4.57 6.02 4.8 6.44 ;
			LAYER M1 ;
			RECT 6.01 6.025 6.24 6.44 ;
			LAYER M1 ;
			RECT 7.5 6.21 7.73 6.44 ;
			LAYER M1 ;
			RECT 4.52 5.68 4.86 6.02 ;
			LAYER M1 ;
			RECT 5.96 5.685 6.3 6.025 ;
			LAYER M1 ;
			RECT 7.4 4.45 7.74 6.21 ;
			LAYER M1 ;
			RECT 7.5 3.555 7.73 4.45 ;
			LAYER M1 ;
			RECT 7.5 3.105 7.995 3.555 ;
			LAYER M1 ;
			RECT 7.5 2.415 7.73 3.105 ;
			LAYER M1 ;
			RECT 4.62 1.575 4.96 2.415 ;
			LAYER M1 ;
			RECT 6.06 1.575 6.4 2.415 ;
			LAYER M1 ;
			RECT 7.5 1.575 7.84 2.415 ;
			LAYER M1 ;
			RECT 4.73 1.345 4.96 1.575 ;
			LAYER M1 ;
			RECT 6.12 1.345 6.35 1.575 ;
			LAYER M1 ;
			RECT 7.5 1.345 7.73 1.575 ;
			LAYER M1 ;
			RECT 4.73 1.115 7.73 1.345 ;
		END
		AntennaDiffArea 4.14 ;
	END out
	PIN in1
		DIRECTION input ;
		USE SIGNAL ;
		PORT
			LAYER M1 ;
			RECT 3.105 3.105 3.555 3.555 ;
		END
		AntennaGateArea 0.9936 ;
	END in1
	PIN sel
		DIRECTION input ;
		USE SIGNAL ;
		PORT
			LAYER M1 ;
			RECT 6.2 4.01 6.54 4.12 ;
			LAYER M1 ;
			RECT 5.985 3.78 6.54 4.01 ;
			LAYER M1 ;
			RECT 0.885 3.48 1.335 3.555 ;
			LAYER M1 ;
			RECT 0.82 3.14 1.335 3.48 ;
			LAYER M1 ;
			RECT 0.885 3.105 1.335 3.14 ;
			LAYER M1 ;
			RECT 5.985 3.005 6.215 3.78 ;
			LAYER M1 ;
			RECT 5.78 2.735 6.215 3.005 ;
			LAYER M1 ;
			RECT 5.78 2.665 6.12 2.735 ;
		END
		AntennaGateArea 1.3284 ;
	END sel
	PIN GND
		DIRECTION inout ;
		USE GROUND ;
		PORT
			LAYER M1 ;
			RECT 0.94 0.5 1.28 2.4 ;
			LAYER M1 ;
			RECT 2.38 0.5 2.72 2.4 ;
			LAYER M1 ;
			RECT 3.82 0.5 4.16 2.4 ;
			LAYER M1 ;
			RECT 0 -0.5 8.14 0.5 ;
		END
	END GND
	PIN VDD
		DIRECTION inout ;
		USE POWER ;
		PORT
			LAYER M1 ;
			RECT 0 6.9 8.14 7.9 ;
			LAYER M1 ;
			RECT 0.94 4.45 1.28 6.9 ;
			LAYER M1 ;
			RECT 2.38 5.68 2.72 6.9 ;
			LAYER M1 ;
			RECT 3.82 5.68 4.16 6.9 ;
		END
	END VDD
	PIN in0
		DIRECTION input ;
		USE SIGNAL ;
		PORT
			LAYER M1 ;
			RECT 1.625 3.105 2.075 3.555 ;
		END
		AntennaGateArea 0.9936 ;
	END in0
	OBS
		LAYER M1 ;
		RECT 0.26 6.25 0.6 6.59 ;
		LAYER M1 ;
		RECT 0.26 5.61 0.49 6.25 ;
		LAYER M1 ;
		RECT 0.18 4.45 0.52 5.61 ;
		LAYER M1 ;
		RECT 1.66 5.45 2 6.21 ;
		LAYER M1 ;
		RECT 6.68 5.45 7.02 6.21 ;
		LAYER M1 ;
		RECT 1.66 5.22 7.02 5.45 ;
		LAYER M1 ;
		RECT 1.66 4.45 2 5.22 ;
		LAYER M1 ;
		RECT 3.1 4.955 3.44 4.99 ;
		LAYER M1 ;
		RECT 5.24 4.955 5.58 4.99 ;
		LAYER M1 ;
		RECT 3.1 4.725 5.58 4.955 ;
		LAYER M1 ;
		RECT 3.1 4.65 3.44 4.725 ;
		LAYER M1 ;
		RECT 5.24 4.65 5.58 4.725 ;
		LAYER M1 ;
		RECT 0.29 2.4 0.52 4.45 ;
		LAYER M1 ;
		RECT 1.71 4.065 1.94 4.45 ;
		LAYER M1 ;
		RECT 3.155 4.065 3.385 4.65 ;
		LAYER M1 ;
		RECT 1.71 3.835 2.63 4.065 ;
		LAYER M1 ;
		RECT 3.155 3.835 4.035 4.065 ;
		LAYER M1 ;
		RECT 2.4 2.865 2.63 3.835 ;
		LAYER M1 ;
		RECT 3.805 2.87 4.035 3.835 ;
		LAYER M1 ;
		RECT 1.77 2.635 2.63 2.865 ;
		LAYER M1 ;
		RECT 3.105 2.64 4.035 2.87 ;
		LAYER M1 ;
		RECT 1.77 2.4 2 2.635 ;
		LAYER M1 ;
		RECT 3.105 2.4 3.335 2.64 ;
		LAYER M1 ;
		RECT 5.315 2.415 5.545 4.65 ;
		LAYER M1 ;
		RECT 6.68 4.45 7.02 5.22 ;
		LAYER M1 ;
		RECT 6.78 2.415 7.01 4.45 ;
		LAYER M1 ;
		RECT 0.18 1.86 0.52 2.4 ;
		LAYER M1 ;
		RECT 1.66 1.56 2 2.4 ;
		LAYER M1 ;
		RECT 3.1 1.56 3.44 2.4 ;
		LAYER M1 ;
		RECT 5.315 2.13 5.68 2.415 ;
		LAYER M1 ;
		RECT 5.34 1.575 5.68 2.13 ;
		LAYER M1 ;
		RECT 6.78 1.575 7.12 2.415 ;
	END
END MMI_MUXI2B
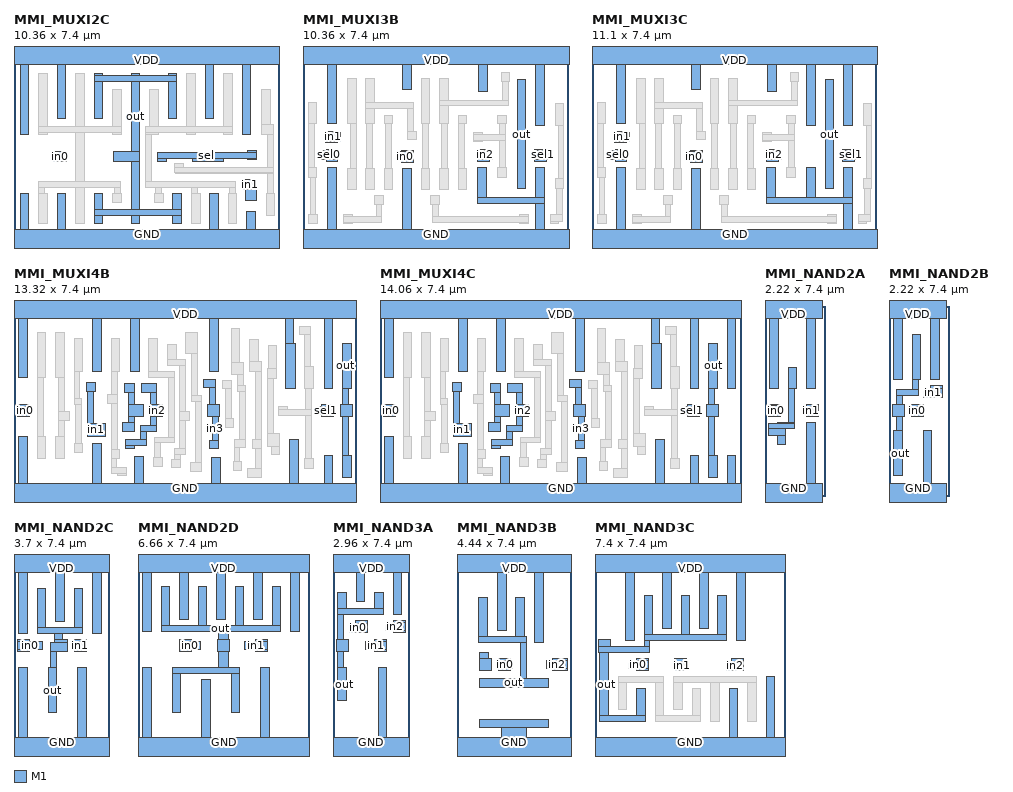
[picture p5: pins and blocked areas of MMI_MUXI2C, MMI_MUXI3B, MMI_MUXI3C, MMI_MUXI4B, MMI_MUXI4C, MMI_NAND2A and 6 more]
MACRO MMI_MUXI2C
	CLASS CORE ;
	FOREIGN MMI_MUXI2C 0 0 ;
	SIZE 10.36 BY 7.4 ;
	SYMMETRY X Y ;
	SITE CORE1 ;
	PIN out
		DIRECTION output ;
		USE SIGNAL ;
		PORT
			LAYER M1 ;
			RECT 3.12 6.475 3.46 6.57 ;
			LAYER M1 ;
			RECT 4.56 6.475 4.9 6.57 ;
			LAYER M1 ;
			RECT 6 6.475 6.34 6.57 ;
			LAYER M1 ;
			RECT 3.12 6.245 6.34 6.475 ;
			LAYER M1 ;
			RECT 3.12 4.815 3.46 6.245 ;
			LAYER M1 ;
			RECT 4.56 3.525 4.9 6.245 ;
			LAYER M1 ;
			RECT 6 4.815 6.34 6.245 ;
			LAYER M1 ;
			RECT 3.875 3.13 4.9 3.525 ;
			LAYER M1 ;
			RECT 3.12 1.26 3.46 1.88 ;
			LAYER M1 ;
			RECT 4.56 1.26 4.9 3.13 ;
			LAYER M1 ;
			RECT 6.185 1.26 6.525 1.88 ;
			LAYER M1 ;
			RECT 3.12 1.03 6.525 1.26 ;
			LAYER M1 ;
			RECT 3.12 0.73 3.46 1.03 ;
			LAYER M1 ;
			RECT 4.56 0.73 4.9 1.03 ;
			LAYER M1 ;
			RECT 6.185 0.73 6.525 1.03 ;
		END
		AntennaDiffArea 5.9697 ;
	END out
	PIN sel
		DIRECTION input ;
		USE SIGNAL ;
		PORT
			LAYER M1 ;
			RECT 9.1 3.5 9.44 3.545 ;
			LAYER M1 ;
			RECT 5.6 3.49 9.44 3.5 ;
			LAYER M1 ;
			RECT 5.59 3.27 9.44 3.49 ;
			LAYER M1 ;
			RECT 5.59 3.15 5.93 3.27 ;
			LAYER M1 ;
			RECT 6.94 3.135 8.14 3.27 ;
			LAYER M1 ;
			RECT 9.1 3.205 9.44 3.27 ;
		END
		AntennaGateArea 2.4867 ;
	END sel
	PIN in1
		DIRECTION input ;
		USE SIGNAL ;
		PORT
			LAYER M1 ;
			RECT 8.915 2.03 9.46 2.43 ;
			LAYER M1 ;
			RECT 9.035 1.61 9.46 2.03 ;
		END
		AntennaGateArea 1.9899 ;
	END in1
	PIN GND
		DIRECTION inout ;
		USE GROUND ;
		PORT
			LAYER M1 ;
			RECT 0.24 0.5 0.58 1.88 ;
			LAYER M1 ;
			RECT 1.68 0.5 2.02 1.88 ;
			LAYER M1 ;
			RECT 7.625 0.5 7.965 1.88 ;
			LAYER M1 ;
			RECT 9.065 0.5 9.405 1.175 ;
			LAYER M1 ;
			RECT 0 -0.5 10.36 0.5 ;
		END
	END GND
	PIN VDD
		DIRECTION inout ;
		USE POWER ;
		PORT
			LAYER M1 ;
			RECT 0 6.9 10.36 7.9 ;
			LAYER M1 ;
			RECT 0.24 4.195 0.58 6.9 ;
			LAYER M1 ;
			RECT 1.68 4.815 2.02 6.9 ;
			LAYER M1 ;
			RECT 7.44 4.815 7.78 6.9 ;
			LAYER M1 ;
			RECT 8.88 4.195 9.22 6.9 ;
		END
	END VDD
	PIN in0
		DIRECTION input ;
		USE SIGNAL ;
		PORT
			LAYER M1 ;
			RECT 1.515 3.125 2.06 3.53 ;
		END
		AntennaGateArea 1.9899 ;
	END in0
	OBS
		LAYER M1 ;
		RECT 0.96 4.5 1.3 6.57 ;
		LAYER M1 ;
		RECT 2.4 4.5 2.74 6.57 ;
		LAYER M1 ;
		RECT 3.84 4.5 4.18 5.945 ;
		LAYER M1 ;
		RECT 0.96 4.27 4.18 4.5 ;
		LAYER M1 ;
		RECT 0.96 4.195 1.3 4.27 ;
		LAYER M1 ;
		RECT 2.4 2.36 2.74 4.27 ;
		LAYER M1 ;
		RECT 3.84 4.195 4.18 4.27 ;
		LAYER M1 ;
		RECT 5.28 4.495 5.62 5.945 ;
		LAYER M1 ;
		RECT 6.72 4.495 7.06 6.57 ;
		LAYER M1 ;
		RECT 8.16 4.495 8.5 6.57 ;
		LAYER M1 ;
		RECT 0.96 2.13 4.14 2.36 ;
		LAYER M1 ;
		RECT 0.96 1.88 1.19 2.13 ;
		LAYER M1 ;
		RECT 0.96 0.73 1.3 1.88 ;
		LAYER M1 ;
		RECT 2.4 0.73 2.74 2.13 ;
		LAYER M1 ;
		RECT 3.91 1.88 4.14 2.13 ;
		LAYER M1 ;
		RECT 3.84 1.54 4.18 1.88 ;
		LAYER M1 ;
		RECT 5.13 4.265 8.5 4.495 ;
		LAYER M1 ;
		RECT 5.13 4.195 5.62 4.265 ;
		LAYER M1 ;
		RECT 6.72 4.195 7.06 4.265 ;
		LAYER M1 ;
		RECT 8.16 4.195 8.5 4.265 ;
		LAYER M1 ;
		RECT 9.64 4.595 9.98 5.955 ;
		LAYER M1 ;
		RECT 9.64 4.195 10.1 4.595 ;
		LAYER M1 ;
		RECT 5.13 2.34 5.36 4.195 ;
		LAYER M1 ;
		RECT 6.26 2.89 6.6 3.04 ;
		LAYER M1 ;
		RECT 9.87 2.89 10.1 4.195 ;
		LAYER M1 ;
		RECT 6.26 2.7 10.1 2.89 ;
		LAYER M1 ;
		RECT 6.29 2.66 10.1 2.7 ;
		LAYER M1 ;
		RECT 5.13 2.11 8.625 2.34 ;
		LAYER M1 ;
		RECT 5.52 1.88 5.75 2.11 ;
		LAYER M1 ;
		RECT 6.91 1.88 7.14 2.11 ;
		LAYER M1 ;
		RECT 8.395 1.88 8.625 2.11 ;
		LAYER M1 ;
		RECT 5.465 1.54 5.805 1.88 ;
		LAYER M1 ;
		RECT 6.905 0.73 7.245 1.88 ;
		LAYER M1 ;
		RECT 8.345 0.73 8.685 1.88 ;
		LAYER M1 ;
		RECT 9.87 1.88 10.1 2.66 ;
		LAYER M1 ;
		RECT 9.825 1.04 10.165 1.88 ;
	END
END MMI_MUXI2C
MACRO MMI_MUXI3B
	CLASS CORE ;
	FOREIGN MMI_MUXI3B 0 0 ;
	SIZE 10.36 BY 7.4 ;
	SYMMETRY X Y ;
	SITE CORE1 ;
	PIN out
		DIRECTION output ;
		USE SIGNAL ;
		PORT
			LAYER M1 ;
			RECT 8.335 2.08 8.675 6.315 ;
		END
		AntennaDiffArea 1.32 ;
	END out
	PIN sel0
		DIRECTION input ;
		USE SIGNAL ;
		PORT
			LAYER M1 ;
			RECT 0.905 3.57 1.355 3.59 ;
			LAYER M1 ;
			RECT 0.705 3.23 1.355 3.57 ;
			LAYER M1 ;
			RECT 0.905 3.14 1.355 3.23 ;
		END
		AntennaGateArea 0.7452 ;
	END sel0
	PIN in1
		DIRECTION input ;
		USE SIGNAL ;
		PORT
			LAYER M1 ;
			RECT 0.89 4.265 1.34 4.315 ;
			LAYER M1 ;
			RECT 0.89 3.925 1.46 4.265 ;
			LAYER M1 ;
			RECT 0.89 3.865 1.34 3.925 ;
		END
		AntennaGateArea 0.495 ;
	END in1
	PIN GND
		DIRECTION inout ;
		USE GROUND ;
		PORT
			LAYER M1 ;
			RECT 0.965 0.5 1.305 2.91 ;
			LAYER M1 ;
			RECT 3.885 0.5 4.225 2.88 ;
			LAYER M1 ;
			RECT 6.805 1.725 7.145 2.91 ;
			LAYER M1 ;
			RECT 9.055 1.725 9.395 2.91 ;
			LAYER M1 ;
			RECT 6.805 1.495 9.395 1.725 ;
			LAYER M1 ;
			RECT 9.055 0.5 9.395 1.495 ;
			LAYER M1 ;
			RECT 0 -0.5 10.36 0.5 ;
		END
	END GND
	PIN sel1
		DIRECTION input ;
		USE SIGNAL ;
		PORT
			LAYER M1 ;
			RECT 9.015 3.57 9.465 3.59 ;
			LAYER M1 ;
			RECT 9.015 3.23 9.665 3.57 ;
			LAYER M1 ;
			RECT 9.015 3.14 9.465 3.23 ;
		END
		AntennaGateArea 0.7452 ;
	END sel1
	PIN in2
		DIRECTION input ;
		USE SIGNAL ;
		PORT
			LAYER M1 ;
			RECT 6.805 3.57 7.255 3.59 ;
			LAYER M1 ;
			RECT 6.805 3.23 7.37 3.57 ;
			LAYER M1 ;
			RECT 6.805 3.14 7.255 3.23 ;
		END
		AntennaGateArea 0.2484 ;
	END in2
	PIN VDD
		DIRECTION inout ;
		USE POWER ;
		PORT
			LAYER M1 ;
			RECT 0 6.9 10.36 7.9 ;
			LAYER M1 ;
			RECT 0.965 4.6 1.305 6.9 ;
			LAYER M1 ;
			RECT 3.885 5.95 4.225 6.9 ;
			LAYER M1 ;
			RECT 6.845 5.87 7.185 6.9 ;
			LAYER M1 ;
			RECT 9.055 4.555 9.395 6.9 ;
		END
	END VDD
	PIN in0
		DIRECTION input ;
		USE SIGNAL ;
		PORT
			LAYER M1 ;
			RECT 3.845 3.51 4.295 3.565 ;
			LAYER M1 ;
			RECT 3.685 3.17 4.295 3.51 ;
			LAYER M1 ;
			RECT 3.845 3.115 4.295 3.17 ;
		END
		AntennaGateArea 0.4968 ;
	END in0
	OBS
		LAYER M1 ;
		RECT 0.205 4.6 0.545 5.44 ;
		LAYER M1 ;
		RECT 1.725 4.6 2.065 6.36 ;
		LAYER M1 ;
		RECT 2.445 5.415 2.785 6.36 ;
		LAYER M1 ;
		RECT 2.445 5.185 4.315 5.415 ;
		LAYER M1 ;
		RECT 2.445 4.6 2.785 5.185 ;
		LAYER M1 ;
		RECT 3.165 4.6 3.505 4.94 ;
		LAYER M1 ;
		RECT 0.21 2.91 0.44 4.6 ;
		LAYER M1 ;
		RECT 0.205 2.53 0.545 2.91 ;
		LAYER M1 ;
		RECT 0.275 1.07 0.505 2.53 ;
		LAYER M1 ;
		RECT 0.225 0.73 0.565 1.07 ;
		LAYER M1 ;
		RECT 1.835 2.88 2.065 4.6 ;
		LAYER M1 ;
		RECT 2.47 2.88 2.7 4.6 ;
		LAYER M1 ;
		RECT 3.22 2.88 3.45 4.6 ;
		LAYER M1 ;
		RECT 4.085 4.32 4.315 5.185 ;
		LAYER M1 ;
		RECT 4.605 4.6 4.945 6.36 ;
		LAYER M1 ;
		RECT 5.325 5.53 5.665 6.36 ;
		LAYER M1 ;
		RECT 7.785 6.605 8.015 6.61 ;
		LAYER M1 ;
		RECT 7.72 6.265 8.06 6.605 ;
		LAYER M1 ;
		RECT 7.785 5.53 8.015 6.265 ;
		LAYER M1 ;
		RECT 5.325 5.3 8.015 5.53 ;
		LAYER M1 ;
		RECT 5.325 4.6 5.665 5.3 ;
		LAYER M1 ;
		RECT 6.045 4.6 6.385 4.94 ;
		LAYER M1 ;
		RECT 7.575 4.6 7.915 4.94 ;
		LAYER M1 ;
		RECT 4.085 3.98 4.425 4.32 ;
		LAYER M1 ;
		RECT 4.655 2.88 4.885 4.6 ;
		LAYER M1 ;
		RECT 5.41 2.88 5.64 4.6 ;
		LAYER M1 ;
		RECT 6.045 2.88 6.275 4.6 ;
		LAYER M1 ;
		RECT 6.65 4.2 6.99 4.265 ;
		LAYER M1 ;
		RECT 7.66 4.2 7.89 4.6 ;
		LAYER M1 ;
		RECT 6.65 3.97 7.89 4.2 ;
		LAYER M1 ;
		RECT 6.65 3.925 6.99 3.97 ;
		LAYER M1 ;
		RECT 7.66 2.91 7.89 3.97 ;
		LAYER M1 ;
		RECT 1.725 2.04 2.065 2.88 ;
		LAYER M1 ;
		RECT 2.445 2.04 2.785 2.88 ;
		LAYER M1 ;
		RECT 3.165 2.04 3.505 2.88 ;
		LAYER M1 ;
		RECT 2.785 1.465 3.125 1.805 ;
		LAYER M1 ;
		RECT 1.58 1.005 1.92 1.07 ;
		LAYER M1 ;
		RECT 2.845 1.005 3.075 1.465 ;
		LAYER M1 ;
		RECT 1.58 0.775 3.075 1.005 ;
		LAYER M1 ;
		RECT 1.58 0.73 1.92 0.775 ;
		LAYER M1 ;
		RECT 4.605 2.04 4.945 2.88 ;
		LAYER M1 ;
		RECT 5.325 2.04 5.665 2.88 ;
		LAYER M1 ;
		RECT 6.045 2.04 6.385 2.88 ;
		LAYER M1 ;
		RECT 4.985 1.465 5.325 1.805 ;
		LAYER M1 ;
		RECT 7.575 2.53 7.915 2.91 ;
		LAYER M1 ;
		RECT 9.825 4.555 10.165 5.395 ;
		LAYER M1 ;
		RECT 9.935 2.46 10.165 4.555 ;
		LAYER M1 ;
		RECT 9.825 2.08 10.165 2.46 ;
		LAYER M1 ;
		RECT 5.035 1.005 5.265 1.465 ;
		LAYER M1 ;
		RECT 8.44 1.005 8.78 1.07 ;
		LAYER M1 ;
		RECT 5.035 0.775 8.78 1.005 ;
		LAYER M1 ;
		RECT 8.44 0.73 8.78 0.775 ;
		LAYER M1 ;
		RECT 9.865 1.07 10.095 2.08 ;
		LAYER M1 ;
		RECT 9.625 0.79 10.095 1.07 ;
		LAYER M1 ;
		RECT 9.625 0.73 9.965 0.79 ;
	END
END MMI_MUXI3B
MACRO MMI_MUXI3C
	CLASS CORE ;
	FOREIGN MMI_MUXI3C 0 0 ;
	SIZE 11.1 BY 7.4 ;
	SYMMETRY X Y ;
	SITE CORE1 ;
	PIN out
		DIRECTION output ;
		USE SIGNAL ;
		PORT
			LAYER M1 ;
			RECT 9.075 2.08 9.415 6.315 ;
		END
		AntennaDiffArea 1.485 ;
	END out
	PIN sel0
		DIRECTION input ;
		USE SIGNAL ;
		PORT
			LAYER M1 ;
			RECT 0.905 3.57 1.355 3.59 ;
			LAYER M1 ;
			RECT 0.705 3.23 1.355 3.57 ;
			LAYER M1 ;
			RECT 0.905 3.14 1.355 3.23 ;
		END
		AntennaGateArea 0.7452 ;
	END sel0
	PIN in1
		DIRECTION input ;
		USE SIGNAL ;
		PORT
			LAYER M1 ;
			RECT 0.89 4.265 1.34 4.315 ;
			LAYER M1 ;
			RECT 0.89 3.925 1.46 4.265 ;
			LAYER M1 ;
			RECT 0.89 3.865 1.34 3.925 ;
		END
		AntennaGateArea 0.495 ;
	END in1
	PIN GND
		DIRECTION inout ;
		USE GROUND ;
		PORT
			LAYER M1 ;
			RECT 0.965 0.5 1.305 2.91 ;
			LAYER M1 ;
			RECT 3.885 0.5 4.225 2.88 ;
			LAYER M1 ;
			RECT 6.805 1.725 7.145 2.91 ;
			LAYER M1 ;
			RECT 8.355 1.725 8.695 2.91 ;
			LAYER M1 ;
			RECT 9.795 1.725 10.135 2.91 ;
			LAYER M1 ;
			RECT 6.805 1.495 10.135 1.725 ;
			LAYER M1 ;
			RECT 9.795 0.5 10.135 1.495 ;
			LAYER M1 ;
			RECT 0 -0.5 11.1 0.5 ;
		END
	END GND
	PIN in2
		DIRECTION input ;
		USE SIGNAL ;
		PORT
			LAYER M1 ;
			RECT 6.805 3.57 7.255 3.59 ;
			LAYER M1 ;
			RECT 6.805 3.23 7.37 3.57 ;
			LAYER M1 ;
			RECT 6.805 3.14 7.255 3.23 ;
		END
		AntennaGateArea 0.2484 ;
	END in2
	PIN sel1
		DIRECTION input ;
		USE SIGNAL ;
		PORT
			LAYER M1 ;
			RECT 9.755 3.57 10.205 3.59 ;
			LAYER M1 ;
			RECT 9.755 3.23 10.405 3.57 ;
			LAYER M1 ;
			RECT 9.755 3.14 10.205 3.23 ;
		END
		AntennaGateArea 0.7452 ;
	END sel1
	PIN VDD
		DIRECTION inout ;
		USE POWER ;
		PORT
			LAYER M1 ;
			RECT 0 6.9 11.1 7.9 ;
			LAYER M1 ;
			RECT 0.965 4.6 1.305 6.9 ;
			LAYER M1 ;
			RECT 3.885 5.95 4.225 6.9 ;
			LAYER M1 ;
			RECT 6.845 5.87 7.185 6.9 ;
			LAYER M1 ;
			RECT 8.355 4.555 8.695 6.9 ;
			LAYER M1 ;
			RECT 9.795 4.555 10.135 6.9 ;
		END
	END VDD
	PIN in0
		DIRECTION input ;
		USE SIGNAL ;
		PORT
			LAYER M1 ;
			RECT 3.845 3.51 4.295 3.565 ;
			LAYER M1 ;
			RECT 3.685 3.17 4.295 3.51 ;
			LAYER M1 ;
			RECT 3.845 3.115 4.295 3.17 ;
		END
		AntennaGateArea 0.4968 ;
	END in0
	OBS
		LAYER M1 ;
		RECT 0.205 4.6 0.545 5.44 ;
		LAYER M1 ;
		RECT 1.725 4.6 2.065 6.36 ;
		LAYER M1 ;
		RECT 2.445 5.415 2.785 6.36 ;
		LAYER M1 ;
		RECT 2.445 5.185 4.315 5.415 ;
		LAYER M1 ;
		RECT 2.445 4.6 2.785 5.185 ;
		LAYER M1 ;
		RECT 3.165 4.6 3.505 4.94 ;
		LAYER M1 ;
		RECT 0.21 2.91 0.44 4.6 ;
		LAYER M1 ;
		RECT 0.205 2.53 0.545 2.91 ;
		LAYER M1 ;
		RECT 0.275 1.07 0.505 2.53 ;
		LAYER M1 ;
		RECT 0.225 0.73 0.565 1.07 ;
		LAYER M1 ;
		RECT 1.835 2.88 2.065 4.6 ;
		LAYER M1 ;
		RECT 2.47 2.88 2.7 4.6 ;
		LAYER M1 ;
		RECT 3.22 2.88 3.45 4.6 ;
		LAYER M1 ;
		RECT 4.085 4.32 4.315 5.185 ;
		LAYER M1 ;
		RECT 4.605 4.6 4.945 6.36 ;
		LAYER M1 ;
		RECT 5.325 5.53 5.665 6.36 ;
		LAYER M1 ;
		RECT 7.785 6.605 8.015 6.61 ;
		LAYER M1 ;
		RECT 7.72 6.265 8.06 6.605 ;
		LAYER M1 ;
		RECT 7.785 5.53 8.015 6.265 ;
		LAYER M1 ;
		RECT 5.325 5.3 8.015 5.53 ;
		LAYER M1 ;
		RECT 5.325 4.6 5.665 5.3 ;
		LAYER M1 ;
		RECT 6.045 4.6 6.385 4.94 ;
		LAYER M1 ;
		RECT 7.575 4.6 7.915 4.94 ;
		LAYER M1 ;
		RECT 4.085 3.98 4.425 4.32 ;
		LAYER M1 ;
		RECT 4.655 2.88 4.885 4.6 ;
		LAYER M1 ;
		RECT 5.41 2.88 5.64 4.6 ;
		LAYER M1 ;
		RECT 6.045 2.88 6.275 4.6 ;
		LAYER M1 ;
		RECT 6.65 4.2 6.99 4.265 ;
		LAYER M1 ;
		RECT 7.66 4.2 7.89 4.6 ;
		LAYER M1 ;
		RECT 6.65 3.97 7.89 4.2 ;
		LAYER M1 ;
		RECT 6.65 3.925 6.99 3.97 ;
		LAYER M1 ;
		RECT 7.66 2.91 7.89 3.97 ;
		LAYER M1 ;
		RECT 1.725 2.04 2.065 2.88 ;
		LAYER M1 ;
		RECT 2.445 2.04 2.785 2.88 ;
		LAYER M1 ;
		RECT 3.165 2.04 3.505 2.88 ;
		LAYER M1 ;
		RECT 2.785 1.465 3.125 1.805 ;
		LAYER M1 ;
		RECT 1.58 1.005 1.92 1.07 ;
		LAYER M1 ;
		RECT 2.845 1.005 3.075 1.465 ;
		LAYER M1 ;
		RECT 1.58 0.775 3.075 1.005 ;
		LAYER M1 ;
		RECT 1.58 0.73 1.92 0.775 ;
		LAYER M1 ;
		RECT 4.605 2.04 4.945 2.88 ;
		LAYER M1 ;
		RECT 5.325 2.04 5.665 2.88 ;
		LAYER M1 ;
		RECT 6.045 2.04 6.385 2.88 ;
		LAYER M1 ;
		RECT 4.985 1.465 5.325 1.805 ;
		LAYER M1 ;
		RECT 7.575 2.53 7.915 2.91 ;
		LAYER M1 ;
		RECT 10.565 4.555 10.905 5.395 ;
		LAYER M1 ;
		RECT 10.675 2.46 10.905 4.555 ;
		LAYER M1 ;
		RECT 10.565 2.08 10.905 2.46 ;
		LAYER M1 ;
		RECT 5.035 1.005 5.265 1.465 ;
		LAYER M1 ;
		RECT 9.18 1.005 9.52 1.07 ;
		LAYER M1 ;
		RECT 5.035 0.775 9.52 1.005 ;
		LAYER M1 ;
		RECT 9.18 0.73 9.52 0.775 ;
		LAYER M1 ;
		RECT 10.605 1.07 10.835 2.08 ;
		LAYER M1 ;
		RECT 10.365 0.79 10.835 1.07 ;
		LAYER M1 ;
		RECT 10.365 0.73 10.705 0.79 ;
	END
END MMI_MUXI3C
MACRO MMI_MUXI4B
	CLASS CORE ;
	FOREIGN MMI_MUXI4B 0 0 ;
	SIZE 13.32 BY 7.4 ;
	SYMMETRY X Y ;
	SITE CORE1 ;
	PIN out
		DIRECTION output ;
		USE SIGNAL ;
		PORT
			LAYER M1 ;
			RECT 12.8 4.19 13.14 5.95 ;
			LAYER M1 ;
			RECT 12.8 3.555 13.03 4.19 ;
			LAYER M1 ;
			RECT 12.725 3.105 13.175 3.555 ;
			LAYER M1 ;
			RECT 12.8 1.57 13.03 3.105 ;
			LAYER M1 ;
			RECT 12.8 0.73 13.14 1.57 ;
		END
		AntennaDiffArea 1.3248 ;
	END out
	PIN in1
		DIRECTION input ;
		USE SIGNAL ;
		PORT
			LAYER M1 ;
			RECT 2.82 4.07 3.16 4.41 ;
			LAYER M1 ;
			RECT 2.87 2.83 3.1 4.07 ;
			LAYER M1 ;
			RECT 2.87 2.815 3.21 2.83 ;
			LAYER M1 ;
			RECT 2.87 2.335 3.555 2.815 ;
		END
		AntennaGateArea 0.4968 ;
	END in1
	PIN sel0
		DIRECTION input ;
		USE SIGNAL ;
		PORT
			LAYER M1 ;
			RECT 4.305 4.05 4.685 4.39 ;
			LAYER M1 ;
			RECT 4.455 3.555 4.685 4.05 ;
			LAYER M1 ;
			RECT 4.455 3.105 5.035 3.555 ;
			LAYER M1 ;
			RECT 4.455 2.86 4.685 3.105 ;
			LAYER M1 ;
			RECT 4.245 2.52 4.685 2.86 ;
		END
		AntennaGateArea 1.4904 ;
	END sel0
	PIN GND
		DIRECTION inout ;
		USE GROUND ;
		PORT
			LAYER M1 ;
			RECT 0.18 0.5 0.52 2.3 ;
			LAYER M1 ;
			RECT 3.06 0.5 3.4 2.04 ;
			LAYER M1 ;
			RECT 4.71 0.5 5.05 1.52 ;
			LAYER M1 ;
			RECT 7.7 0.5 8.04 1.515 ;
			LAYER M1 ;
			RECT 10.73 0.5 11.07 2.22 ;
			LAYER M1 ;
			RECT 12.08 0.5 12.42 1.57 ;
			LAYER M1 ;
			RECT 0 -0.5 13.32 0.5 ;
		END
	END GND
	PIN sel1
		DIRECTION input ;
		USE SIGNAL ;
		PORT
			LAYER M1 ;
			RECT 11.985 3.5 12.435 3.555 ;
			LAYER M1 ;
			RECT 11.865 3.16 12.435 3.5 ;
			LAYER M1 ;
			RECT 11.985 3.105 12.435 3.16 ;
		END
		AntennaGateArea 0.7452 ;
	END sel1
	PIN in2
		DIRECTION input ;
		USE SIGNAL ;
		PORT
			LAYER M1 ;
			RECT 4.975 4.05 5.555 4.39 ;
			LAYER M1 ;
			RECT 5.325 3.555 5.555 4.05 ;
			LAYER M1 ;
			RECT 5.325 3.105 5.775 3.555 ;
			LAYER M1 ;
			RECT 5.325 2.755 5.555 3.105 ;
			LAYER M1 ;
			RECT 4.915 2.525 5.555 2.755 ;
			LAYER M1 ;
			RECT 4.915 2.19 5.145 2.525 ;
			LAYER M1 ;
			RECT 4.35 1.96 5.145 2.19 ;
			LAYER M1 ;
			RECT 4.35 1.85 4.69 1.96 ;
		END
		AntennaGateArea 0.4968 ;
	END in2
	PIN VDD
		DIRECTION inout ;
		USE POWER ;
		PORT
			LAYER M1 ;
			RECT 0 6.9 13.32 7.9 ;
			LAYER M1 ;
			RECT 0.18 4.6 0.52 6.9 ;
			LAYER M1 ;
			RECT 3.06 4.85 3.4 6.9 ;
			LAYER M1 ;
			RECT 4.535 4.85 4.875 6.9 ;
			LAYER M1 ;
			RECT 7.61 4.83 7.95 6.9 ;
			LAYER M1 ;
			RECT 10.56 5.935 10.9 6.9 ;
			LAYER M1 ;
			RECT 10.56 4.175 10.96 5.935 ;
			LAYER M1 ;
			RECT 12.08 4.19 12.42 6.9 ;
		END
	END VDD
	PIN in3
		DIRECTION input ;
		USE SIGNAL ;
		PORT
			LAYER M1 ;
			RECT 7.385 4.215 7.86 4.555 ;
			LAYER M1 ;
			RECT 7.63 3.555 7.86 4.215 ;
			LAYER M1 ;
			RECT 7.545 3.105 7.995 3.555 ;
			LAYER M1 ;
			RECT 7.73 2.175 7.96 3.105 ;
			LAYER M1 ;
			RECT 7.62 1.835 7.96 2.175 ;
		END
		AntennaGateArea 0.4968 ;
	END in3
	PIN in0
		DIRECTION input ;
		USE SIGNAL ;
		PORT
			LAYER M1 ;
			RECT 0.145 3.505 0.595 3.555 ;
			LAYER M1 ;
			RECT 0.145 3.165 0.65 3.505 ;
			LAYER M1 ;
			RECT 0.145 3.105 0.595 3.165 ;
		END
		AntennaGateArea 0.4968 ;
	END in0
	OBS
		LAYER M1 ;
		RECT 0.9 4.6 1.24 6.36 ;
		LAYER M1 ;
		RECT 1.62 4.6 1.96 6.36 ;
		LAYER M1 ;
		RECT 0.9 2.3 1.13 4.6 ;
		LAYER M1 ;
		RECT 1.73 3.29 1.96 4.6 ;
		LAYER M1 ;
		RECT 2.34 4.85 2.68 6.13 ;
		LAYER M1 ;
		RECT 3.78 4.85 4.12 6.13 ;
		LAYER M1 ;
		RECT 6.695 6.355 7.035 6.36 ;
		LAYER M1 ;
		RECT 5.255 4.85 5.595 6.135 ;
		LAYER M1 ;
		RECT 5.975 5.315 6.315 5.905 ;
		LAYER M1 ;
		RECT 6.695 5.55 7.155 6.355 ;
		LAYER M1 ;
		RECT 5.975 5.085 6.695 5.315 ;
		LAYER M1 ;
		RECT 2.34 3.81 2.57 4.85 ;
		LAYER M1 ;
		RECT 2.34 3.58 2.62 3.81 ;
		LAYER M1 ;
		RECT 1.73 2.95 2.15 3.29 ;
		LAYER M1 ;
		RECT 1.73 2.3 1.96 2.95 ;
		LAYER M1 ;
		RECT 0.9 1.46 1.24 2.3 ;
		LAYER M1 ;
		RECT 1.62 1.46 1.96 2.3 ;
		LAYER M1 ;
		RECT 2.39 2.04 2.62 3.58 ;
		LAYER M1 ;
		RECT 3.785 3.96 4.015 4.85 ;
		LAYER M1 ;
		RECT 5.255 4.62 6.235 4.85 ;
		LAYER M1 ;
		RECT 3.635 3.62 4.015 3.96 ;
		LAYER M1 ;
		RECT 2.34 1.7 2.68 2.04 ;
		LAYER M1 ;
		RECT 3.785 1.8 4.015 3.62 ;
		LAYER M1 ;
		RECT 6.005 2.295 6.235 4.62 ;
		LAYER M1 ;
		RECT 5.475 2.065 6.235 2.295 ;
		LAYER M1 ;
		RECT 6.465 3.29 6.695 5.085 ;
		LAYER M1 ;
		RECT 6.925 3.925 7.155 5.55 ;
		LAYER M1 ;
		RECT 8.46 5.19 8.8 6.505 ;
		LAYER M1 ;
		RECT 9.18 5.245 9.52 6.11 ;
		LAYER M1 ;
		RECT 11.13 6.275 11.55 6.615 ;
		LAYER M1 ;
		RECT 8.46 4.745 8.95 5.19 ;
		LAYER M1 ;
		RECT 9.18 4.83 9.63 5.245 ;
		LAYER M1 ;
		RECT 9.9 4.965 10.24 5.855 ;
		LAYER M1 ;
		RECT 6.925 3.695 7.31 3.925 ;
		LAYER M1 ;
		RECT 6.465 2.95 6.85 3.29 ;
		LAYER M1 ;
		RECT 3.78 1.46 4.12 1.8 ;
		LAYER M1 ;
		RECT 3.78 1.125 4.01 1.46 ;
		LAYER M1 ;
		RECT 3.78 0.895 4.39 1.125 ;
		LAYER M1 ;
		RECT 4.05 0.785 4.39 0.895 ;
		LAYER M1 ;
		RECT 5.475 1.495 5.705 2.065 ;
		LAYER M1 ;
		RECT 6.465 1.835 6.695 2.95 ;
		LAYER M1 ;
		RECT 6.26 1.605 6.695 1.835 ;
		LAYER M1 ;
		RECT 5.43 1.155 5.77 1.495 ;
		LAYER M1 ;
		RECT 6.26 1.44 6.49 1.605 ;
		LAYER M1 ;
		RECT 6.15 1.1 6.49 1.44 ;
		LAYER M1 ;
		RECT 7.08 1.295 7.31 3.695 ;
		LAYER M1 ;
		RECT 8.13 4.17 8.47 4.51 ;
		LAYER M1 ;
		RECT 8.24 3.02 8.47 4.17 ;
		LAYER M1 ;
		RECT 8.72 4.305 8.95 4.745 ;
		LAYER M1 ;
		RECT 8.72 4.06 9.025 4.305 ;
		LAYER M1 ;
		RECT 8.225 2.68 8.565 3.02 ;
		LAYER M1 ;
		RECT 8.795 2.215 9.025 4.06 ;
		LAYER M1 ;
		RECT 8.57 1.875 9.025 2.215 ;
		LAYER M1 ;
		RECT 9.4 2.2 9.63 4.83 ;
		LAYER M1 ;
		RECT 6.87 0.955 7.31 1.295 ;
		LAYER M1 ;
		RECT 8.57 1.33 8.8 1.875 ;
		LAYER M1 ;
		RECT 9.29 1.86 9.63 2.2 ;
		LAYER M1 ;
		RECT 9.86 4.575 10.24 4.965 ;
		LAYER M1 ;
		RECT 9.86 2.45 10.09 4.575 ;
		LAYER M1 ;
		RECT 11.32 5.03 11.55 6.275 ;
		LAYER M1 ;
		RECT 11.32 4.19 11.66 5.03 ;
		LAYER M1 ;
		RECT 10.32 3.37 10.66 3.48 ;
		LAYER M1 ;
		RECT 11.34 3.37 11.57 4.19 ;
		LAYER M1 ;
		RECT 10.32 3.14 11.57 3.37 ;
		LAYER M1 ;
		RECT 9.86 1.91 10.35 2.45 ;
		LAYER M1 ;
		RECT 8.53 0.99 8.87 1.33 ;
		LAYER M1 ;
		RECT 9.4 1.07 9.63 1.86 ;
		LAYER M1 ;
		RECT 10.01 1.61 10.35 1.91 ;
		LAYER M1 ;
		RECT 9.1 0.73 9.63 1.07 ;
		LAYER M1 ;
		RECT 11.34 1.45 11.57 3.14 ;
		LAYER M1 ;
		RECT 11.32 1.07 11.66 1.45 ;
	END
END MMI_MUXI4B
MACRO MMI_MUXI4C
	CLASS CORE ;
	FOREIGN MMI_MUXI4C 0 0 ;
	SIZE 14.06 BY 7.4 ;
	SYMMETRY X Y ;
	SITE CORE1 ;
	PIN out
		DIRECTION output ;
		USE SIGNAL ;
		PORT
			LAYER M1 ;
			RECT 12.8 4.19 13.14 5.95 ;
			LAYER M1 ;
			RECT 12.8 3.555 13.03 4.19 ;
			LAYER M1 ;
			RECT 12.725 3.105 13.175 3.555 ;
			LAYER M1 ;
			RECT 12.8 1.57 13.03 3.105 ;
			LAYER M1 ;
			RECT 12.8 0.73 13.14 1.57 ;
		END
		AntennaDiffArea 1.4904 ;
	END out
	PIN sel0
		DIRECTION input ;
		USE SIGNAL ;
		PORT
			LAYER M1 ;
			RECT 4.305 4.05 4.685 4.39 ;
			LAYER M1 ;
			RECT 4.455 3.555 4.685 4.05 ;
			LAYER M1 ;
			RECT 4.455 3.105 5.035 3.555 ;
			LAYER M1 ;
			RECT 4.455 2.86 4.685 3.105 ;
			LAYER M1 ;
			RECT 4.245 2.52 4.685 2.86 ;
		END
		AntennaGateArea 1.4904 ;
	END sel0
	PIN in1
		DIRECTION input ;
		USE SIGNAL ;
		PORT
			LAYER M1 ;
			RECT 2.82 4.07 3.16 4.41 ;
			LAYER M1 ;
			RECT 2.87 2.83 3.1 4.07 ;
			LAYER M1 ;
			RECT 2.87 2.815 3.21 2.83 ;
			LAYER M1 ;
			RECT 2.87 2.335 3.555 2.815 ;
		END
		AntennaGateArea 0.4968 ;
	END in1
	PIN GND
		DIRECTION inout ;
		USE GROUND ;
		PORT
			LAYER M1 ;
			RECT 0.18 0.5 0.52 2.3 ;
			LAYER M1 ;
			RECT 3.06 0.5 3.4 2.04 ;
			LAYER M1 ;
			RECT 4.71 0.5 5.05 1.52 ;
			LAYER M1 ;
			RECT 7.7 0.5 8.04 1.515 ;
			LAYER M1 ;
			RECT 10.73 0.5 11.07 2.22 ;
			LAYER M1 ;
			RECT 12.08 0.5 12.42 1.57 ;
			LAYER M1 ;
			RECT 13.52 0.5 13.86 1.57 ;
			LAYER M1 ;
			RECT 0 -0.5 14.06 0.5 ;
		END
	END GND
	PIN sel1
		DIRECTION input ;
		USE SIGNAL ;
		PORT
			LAYER M1 ;
			RECT 11.985 3.5 12.435 3.555 ;
			LAYER M1 ;
			RECT 11.865 3.16 12.435 3.5 ;
			LAYER M1 ;
			RECT 11.985 3.105 12.435 3.16 ;
		END
		AntennaGateArea 0.7452 ;
	END sel1
	PIN in2
		DIRECTION input ;
		USE SIGNAL ;
		PORT
			LAYER M1 ;
			RECT 4.975 4.05 5.555 4.39 ;
			LAYER M1 ;
			RECT 5.325 3.555 5.555 4.05 ;
			LAYER M1 ;
			RECT 5.325 3.105 5.775 3.555 ;
			LAYER M1 ;
			RECT 5.325 2.755 5.555 3.105 ;
			LAYER M1 ;
			RECT 4.915 2.525 5.555 2.755 ;
			LAYER M1 ;
			RECT 4.915 2.19 5.145 2.525 ;
			LAYER M1 ;
			RECT 4.35 1.96 5.145 2.19 ;
			LAYER M1 ;
			RECT 4.35 1.85 4.69 1.96 ;
		END
		AntennaGateArea 0.4968 ;
	END in2
	PIN VDD
		DIRECTION inout ;
		USE POWER ;
		PORT
			LAYER M1 ;
			RECT 0 6.9 14.06 7.9 ;
			LAYER M1 ;
			RECT 0.18 4.6 0.52 6.9 ;
			LAYER M1 ;
			RECT 3.06 4.85 3.4 6.9 ;
			LAYER M1 ;
			RECT 4.535 4.85 4.875 6.9 ;
			LAYER M1 ;
			RECT 7.61 4.83 7.95 6.9 ;
			LAYER M1 ;
			RECT 10.56 5.935 10.9 6.9 ;
			LAYER M1 ;
			RECT 10.56 4.175 10.96 5.935 ;
			LAYER M1 ;
			RECT 12.08 4.19 12.42 6.9 ;
			LAYER M1 ;
			RECT 13.52 4.19 13.86 6.9 ;
		END
	END VDD
	PIN in3
		DIRECTION input ;
		USE SIGNAL ;
		PORT
			LAYER M1 ;
			RECT 7.385 4.215 7.86 4.555 ;
			LAYER M1 ;
			RECT 7.63 3.555 7.86 4.215 ;
			LAYER M1 ;
			RECT 7.545 3.105 7.995 3.555 ;
			LAYER M1 ;
			RECT 7.73 2.175 7.96 3.105 ;
			LAYER M1 ;
			RECT 7.62 1.835 7.96 2.175 ;
		END
		AntennaGateArea 0.4968 ;
	END in3
	PIN in0
		DIRECTION input ;
		USE SIGNAL ;
		PORT
			LAYER M1 ;
			RECT 0.145 3.505 0.595 3.555 ;
			LAYER M1 ;
			RECT 0.145 3.165 0.65 3.505 ;
			LAYER M1 ;
			RECT 0.145 3.105 0.595 3.165 ;
		END
		AntennaGateArea 0.4968 ;
	END in0
	OBS
		LAYER M1 ;
		RECT 0.9 4.6 1.24 6.36 ;
		LAYER M1 ;
		RECT 1.62 4.6 1.96 6.36 ;
		LAYER M1 ;
		RECT 0.9 2.3 1.13 4.6 ;
		LAYER M1 ;
		RECT 1.73 3.29 1.96 4.6 ;
		LAYER M1 ;
		RECT 2.34 4.85 2.68 6.13 ;
		LAYER M1 ;
		RECT 3.78 4.85 4.12 6.13 ;
		LAYER M1 ;
		RECT 6.695 6.355 7.035 6.36 ;
		LAYER M1 ;
		RECT 5.255 4.85 5.595 6.135 ;
		LAYER M1 ;
		RECT 5.975 5.315 6.315 5.905 ;
		LAYER M1 ;
		RECT 6.695 5.55 7.155 6.355 ;
		LAYER M1 ;
		RECT 5.975 5.085 6.695 5.315 ;
		LAYER M1 ;
		RECT 2.34 3.81 2.57 4.85 ;
		LAYER M1 ;
		RECT 2.34 3.58 2.62 3.81 ;
		LAYER M1 ;
		RECT 1.73 2.95 2.15 3.29 ;
		LAYER M1 ;
		RECT 1.73 2.3 1.96 2.95 ;
		LAYER M1 ;
		RECT 0.9 1.46 1.24 2.3 ;
		LAYER M1 ;
		RECT 1.62 1.46 1.96 2.3 ;
		LAYER M1 ;
		RECT 2.39 2.04 2.62 3.58 ;
		LAYER M1 ;
		RECT 3.785 3.96 4.015 4.85 ;
		LAYER M1 ;
		RECT 5.255 4.62 6.235 4.85 ;
		LAYER M1 ;
		RECT 3.635 3.62 4.015 3.96 ;
		LAYER M1 ;
		RECT 2.34 1.7 2.68 2.04 ;
		LAYER M1 ;
		RECT 3.785 1.8 4.015 3.62 ;
		LAYER M1 ;
		RECT 6.005 2.295 6.235 4.62 ;
		LAYER M1 ;
		RECT 5.475 2.065 6.235 2.295 ;
		LAYER M1 ;
		RECT 6.465 3.29 6.695 5.085 ;
		LAYER M1 ;
		RECT 6.925 3.925 7.155 5.55 ;
		LAYER M1 ;
		RECT 8.46 5.19 8.8 6.505 ;
		LAYER M1 ;
		RECT 9.18 5.245 9.52 6.11 ;
		LAYER M1 ;
		RECT 11.13 6.275 11.55 6.615 ;
		LAYER M1 ;
		RECT 8.46 4.745 8.95 5.19 ;
		LAYER M1 ;
		RECT 9.18 4.83 9.63 5.245 ;
		LAYER M1 ;
		RECT 9.9 4.965 10.24 5.855 ;
		LAYER M1 ;
		RECT 6.925 3.695 7.31 3.925 ;
		LAYER M1 ;
		RECT 6.465 2.95 6.85 3.29 ;
		LAYER M1 ;
		RECT 3.78 1.46 4.12 1.8 ;
		LAYER M1 ;
		RECT 3.78 1.125 4.01 1.46 ;
		LAYER M1 ;
		RECT 3.78 0.895 4.39 1.125 ;
		LAYER M1 ;
		RECT 4.05 0.785 4.39 0.895 ;
		LAYER M1 ;
		RECT 5.475 1.495 5.705 2.065 ;
		LAYER M1 ;
		RECT 6.465 1.835 6.695 2.95 ;
		LAYER M1 ;
		RECT 6.26 1.605 6.695 1.835 ;
		LAYER M1 ;
		RECT 5.43 1.155 5.77 1.495 ;
		LAYER M1 ;
		RECT 6.26 1.44 6.49 1.605 ;
		LAYER M1 ;
		RECT 6.15 1.1 6.49 1.44 ;
		LAYER M1 ;
		RECT 7.08 1.295 7.31 3.695 ;
		LAYER M1 ;
		RECT 8.13 4.17 8.47 4.51 ;
		LAYER M1 ;
		RECT 8.24 3.02 8.47 4.17 ;
		LAYER M1 ;
		RECT 8.72 4.305 8.95 4.745 ;
		LAYER M1 ;
		RECT 8.72 4.06 9.025 4.305 ;
		LAYER M1 ;
		RECT 8.225 2.68 8.565 3.02 ;
		LAYER M1 ;
		RECT 8.795 2.215 9.025 4.06 ;
		LAYER M1 ;
		RECT 8.57 1.875 9.025 2.215 ;
		LAYER M1 ;
		RECT 9.4 2.2 9.63 4.83 ;
		LAYER M1 ;
		RECT 6.87 0.955 7.31 1.295 ;
		LAYER M1 ;
		RECT 8.57 1.33 8.8 1.875 ;
		LAYER M1 ;
		RECT 9.29 1.86 9.63 2.2 ;
		LAYER M1 ;
		RECT 9.86 4.575 10.24 4.965 ;
		LAYER M1 ;
		RECT 9.86 2.45 10.09 4.575 ;
		LAYER M1 ;
		RECT 11.32 5.03 11.55 6.275 ;
		LAYER M1 ;
		RECT 11.32 4.19 11.66 5.03 ;
		LAYER M1 ;
		RECT 10.32 3.37 10.66 3.48 ;
		LAYER M1 ;
		RECT 11.34 3.37 11.57 4.19 ;
		LAYER M1 ;
		RECT 10.32 3.14 11.57 3.37 ;
		LAYER M1 ;
		RECT 9.86 1.91 10.35 2.45 ;
		LAYER M1 ;
		RECT 8.53 0.99 8.87 1.33 ;
		LAYER M1 ;
		RECT 9.4 1.07 9.63 1.86 ;
		LAYER M1 ;
		RECT 10.01 1.61 10.35 1.91 ;
		LAYER M1 ;
		RECT 9.1 0.73 9.63 1.07 ;
		LAYER M1 ;
		RECT 11.34 1.45 11.57 3.14 ;
		LAYER M1 ;
		RECT 11.32 1.07 11.66 1.45 ;
	END
END MMI_MUXI4C
MACRO MMI_NAND2A
	CLASS CORE ;
	FOREIGN MMI_NAND2A 0 0 ;
	SIZE 2.22 BY 7.4 ;
	SYMMETRY X Y ;
	SITE CORE1 ;
	PIN out
		DIRECTION output ;
		USE SIGNAL ;
		PORT
			LAYER M1 ;
			RECT 0.9 4.18 1.24 5.02 ;
			LAYER M1 ;
			RECT 0.9 2.845 1.13 4.18 ;
			LAYER M1 ;
			RECT 0.47 2.815 1.13 2.845 ;
			LAYER M1 ;
			RECT 0.145 2.615 1.13 2.815 ;
			LAYER M1 ;
			RECT 0.145 2.365 0.81 2.615 ;
			LAYER M1 ;
			RECT 0.47 2.005 0.81 2.365 ;
		END
		AntennaDiffArea 0.9384 ;
	END out
	PIN in1
		DIRECTION input ;
		USE SIGNAL ;
		PORT
			LAYER M1 ;
			RECT 1.625 3.5 2.075 3.555 ;
			LAYER M1 ;
			RECT 1.51 3.16 2.075 3.5 ;
			LAYER M1 ;
			RECT 1.625 3.105 2.075 3.16 ;
		END
		AntennaGateArea 0.3312 ;
	END in1
	PIN GND
		DIRECTION inout ;
		USE GROUND ;
		PORT
			LAYER M1 ;
			RECT 1.62 0.5 1.96 2.845 ;
			LAYER M1 ;
			RECT 0 -0.5 2.22 0.5 ;
		END
	END GND
	PIN VDD
		DIRECTION inout ;
		USE POWER ;
		PORT
			LAYER M1 ;
			RECT 0 6.9 2.22 7.9 ;
			LAYER M1 ;
			RECT 0.18 4.18 0.52 6.9 ;
			LAYER M1 ;
			RECT 1.62 4.18 1.96 6.9 ;
		END
	END VDD
	PIN in0
		DIRECTION input ;
		USE SIGNAL ;
		PORT
			LAYER M1 ;
			RECT 0.145 3.51 0.61 3.555 ;
			LAYER M1 ;
			RECT 0.145 3.17 0.655 3.51 ;
			LAYER M1 ;
			RECT 0.145 3.105 0.595 3.17 ;
		END
		AntennaGateArea 0.3312 ;
	END in0
	OBS
	END
END MMI_NAND2A
MACRO MMI_NAND2B
	CLASS CORE ;
	FOREIGN MMI_NAND2B 0 0 ;
	SIZE 2.22 BY 7.4 ;
	SYMMETRY X Y ;
	SITE CORE1 ;
	PIN out
		DIRECTION output ;
		USE SIGNAL ;
		PORT
			LAYER M1 ;
			RECT 0.9 4.54 1.24 6.3 ;
			LAYER M1 ;
			RECT 0.9 4.135 1.13 4.54 ;
			LAYER M1 ;
			RECT 0.29 3.905 1.13 4.135 ;
			LAYER M1 ;
			RECT 0.29 3.555 0.52 3.905 ;
			LAYER M1 ;
			RECT 0.145 3.105 0.595 3.555 ;
			LAYER M1 ;
			RECT 0.29 2.54 0.52 3.105 ;
			LAYER M1 ;
			RECT 0.18 0.78 0.52 2.54 ;
		END
		AntennaDiffArea 1.8768 ;
	END out
	PIN in1
		DIRECTION input ;
		USE SIGNAL ;
		PORT
			LAYER M1 ;
			RECT 1.625 4.19 2.075 4.295 ;
			LAYER M1 ;
			RECT 1.36 3.85 2.075 4.19 ;
			LAYER M1 ;
			RECT 1.625 3.845 2.075 3.85 ;
		END
		AntennaGateArea 0.6624 ;
	END in1
	PIN GND
		DIRECTION inout ;
		USE GROUND ;
		PORT
			LAYER M1 ;
			RECT 1.33 0.5 1.67 2.54 ;
			LAYER M1 ;
			RECT 0 -0.5 2.22 0.5 ;
		END
	END GND
	PIN VDD
		DIRECTION inout ;
		USE POWER ;
		PORT
			LAYER M1 ;
			RECT 0 6.9 2.22 7.9 ;
			LAYER M1 ;
			RECT 0.18 4.54 0.52 6.9 ;
			LAYER M1 ;
			RECT 1.62 4.54 1.96 6.9 ;
		END
	END VDD
	PIN in0
		DIRECTION input ;
		USE SIGNAL ;
		PORT
			LAYER M1 ;
			RECT 0.885 3.5 1.335 3.555 ;
			LAYER M1 ;
			RECT 0.825 3.16 1.335 3.5 ;
			LAYER M1 ;
			RECT 0.885 3.105 1.335 3.16 ;
		END
		AntennaGateArea 0.6624 ;
	END in0
	OBS
	END
END MMI_NAND2B
MACRO MMI_NAND2C
	CLASS CORE ;
	FOREIGN MMI_NAND2C 0 0 ;
	SIZE 3.7 BY 7.4 ;
	SYMMETRY X Y ;
	SITE CORE1 ;
	PIN out
		DIRECTION output ;
		USE SIGNAL ;
		PORT
			LAYER M1 ;
			RECT 0.9 4.765 1.24 6.295 ;
			LAYER M1 ;
			RECT 2.34 4.765 2.68 6.295 ;
			LAYER M1 ;
			RECT 0.9 4.535 2.68 4.765 ;
			LAYER M1 ;
			RECT 1.565 4.295 1.905 4.535 ;
			LAYER M1 ;
			RECT 1.565 4.185 2.075 4.295 ;
			LAYER M1 ;
			RECT 1.44 3.845 2.075 4.185 ;
			LAYER M1 ;
			RECT 1.44 3.215 1.67 3.845 ;
			LAYER M1 ;
			RECT 1.33 1.455 1.67 3.215 ;
		END
		AntennaDiffArea 2.9808 ;
	END out
	PIN in1
		DIRECTION input ;
		USE SIGNAL ;
		PORT
			LAYER M1 ;
			RECT 2.365 4.24 2.815 4.295 ;
			LAYER M1 ;
			RECT 2.305 3.9 2.815 4.24 ;
			LAYER M1 ;
			RECT 2.365 3.845 2.815 3.9 ;
		END
		AntennaGateArea 1.3248 ;
	END in1
	PIN GND
		DIRECTION inout ;
		USE GROUND ;
		PORT
			LAYER M1 ;
			RECT 0.18 0.5 0.52 3.215 ;
			LAYER M1 ;
			RECT 2.48 0.5 2.82 3.215 ;
			LAYER M1 ;
			RECT 0 -0.5 3.7 0.5 ;
		END
	END GND
	PIN VDD
		DIRECTION inout ;
		USE POWER ;
		PORT
			LAYER M1 ;
			RECT 0 6.9 3.7 7.9 ;
			LAYER M1 ;
			RECT 0.18 4.535 0.52 6.9 ;
			LAYER M1 ;
			RECT 1.62 5.015 1.96 6.9 ;
			LAYER M1 ;
			RECT 3.06 4.535 3.4 6.9 ;
		END
	END VDD
	PIN in0
		DIRECTION input ;
		USE SIGNAL ;
		PORT
			LAYER M1 ;
			RECT 0.145 4.24 0.595 4.295 ;
			LAYER M1 ;
			RECT 0.145 3.9 1.12 4.24 ;
			LAYER M1 ;
			RECT 0.145 3.845 0.595 3.9 ;
		END
		AntennaGateArea 1.3248 ;
	END in0
	OBS
	END
END MMI_NAND2C
MACRO MMI_NAND2D
	CLASS CORE ;
	FOREIGN MMI_NAND2D 0 0 ;
	SIZE 6.66 BY 7.4 ;
	SYMMETRY X Y ;
	SITE CORE1 ;
	PIN out
		DIRECTION output ;
		USE SIGNAL ;
		PORT
			LAYER M1 ;
			RECT 0.9 4.83 1.24 6.36 ;
			LAYER M1 ;
			RECT 2.34 4.83 2.68 6.36 ;
			LAYER M1 ;
			RECT 3.78 4.83 4.12 6.36 ;
			LAYER M1 ;
			RECT 5.22 4.83 5.56 6.36 ;
			LAYER M1 ;
			RECT 0.9 4.6 5.56 4.83 ;
			LAYER M1 ;
			RECT 3.135 4.295 3.525 4.6 ;
			LAYER M1 ;
			RECT 3.105 3.845 3.555 4.295 ;
			LAYER M1 ;
			RECT 3.135 3.22 3.525 3.845 ;
			LAYER M1 ;
			RECT 1.33 2.99 3.97 3.22 ;
			LAYER M1 ;
			RECT 1.33 1.46 1.67 2.99 ;
			LAYER M1 ;
			RECT 3.63 1.46 3.97 2.99 ;
		END
		AntennaDiffArea 5.9616 ;
	END out
	PIN in1
		DIRECTION input ;
		USE SIGNAL ;
		PORT
			LAYER M1 ;
			RECT 4.585 4.24 5.035 4.295 ;
			LAYER M1 ;
			RECT 4.145 3.9 5.035 4.24 ;
			LAYER M1 ;
			RECT 4.585 3.845 5.035 3.9 ;
		END
		AntennaGateArea 2.6496 ;
	END in1
	PIN GND
		DIRECTION inout ;
		USE GROUND ;
		PORT
			LAYER M1 ;
			RECT 0.18 0.5 0.52 3.22 ;
			LAYER M1 ;
			RECT 2.48 0.5 2.82 2.74 ;
			LAYER M1 ;
			RECT 4.78 0.5 5.12 3.22 ;
			LAYER M1 ;
			RECT 0 -0.5 6.66 0.5 ;
		END
	END GND
	PIN VDD
		DIRECTION inout ;
		USE POWER ;
		PORT
			LAYER M1 ;
			RECT 0 6.9 6.66 7.9 ;
			LAYER M1 ;
			RECT 0.18 4.6 0.52 6.9 ;
			LAYER M1 ;
			RECT 1.62 5.08 1.96 6.9 ;
			LAYER M1 ;
			RECT 3.06 5.08 3.4 6.9 ;
			LAYER M1 ;
			RECT 4.5 5.08 4.84 6.9 ;
			LAYER M1 ;
			RECT 5.94 4.6 6.28 6.9 ;
		END
	END VDD
	PIN in0
		DIRECTION input ;
		USE SIGNAL ;
		PORT
			LAYER M1 ;
			RECT 1.625 4.24 2.075 4.295 ;
			LAYER M1 ;
			RECT 1.625 3.9 2.445 4.24 ;
			LAYER M1 ;
			RECT 1.625 3.845 2.075 3.9 ;
		END
		AntennaGateArea 2.6496 ;
	END in0
	OBS
	END
END MMI_NAND2D
MACRO MMI_NAND3A
	CLASS CORE ;
	FOREIGN MMI_NAND3A 0 0 ;
	SIZE 2.96 BY 7.4 ;
	SYMMETRY X Y ;
	SITE CORE1 ;
	PIN out
		DIRECTION output ;
		USE SIGNAL ;
		PORT
			LAYER M1 ;
			RECT 0.18 5.515 0.52 6.125 ;
			LAYER M1 ;
			RECT 1.62 5.515 1.96 6.125 ;
			LAYER M1 ;
			RECT 0.18 5.285 1.96 5.515 ;
			LAYER M1 ;
			RECT 0.18 4.295 0.41 5.285 ;
			LAYER M1 ;
			RECT 0.145 3.845 0.595 4.295 ;
			LAYER M1 ;
			RECT 0.18 3.21 0.41 3.845 ;
			LAYER M1 ;
			RECT 0.18 1.91 0.52 3.21 ;
		END
		AntennaDiffArea 1.6008 ;
	END out
	PIN in1
		DIRECTION input ;
		USE SIGNAL ;
		PORT
			LAYER M1 ;
			RECT 1.625 4.24 2.075 4.295 ;
			LAYER M1 ;
			RECT 1.285 3.9 2.075 4.24 ;
			LAYER M1 ;
			RECT 1.625 3.845 2.075 3.9 ;
		END
		AntennaGateArea 0.414 ;
	END in1
	PIN GND
		DIRECTION inout ;
		USE GROUND ;
		PORT
			LAYER M1 ;
			RECT 1.76 0.5 2.1 3.21 ;
			LAYER M1 ;
			RECT 0 -0.5 2.96 0.5 ;
		END
	END GND
	PIN in2
		DIRECTION input ;
		USE SIGNAL ;
		PORT
			LAYER M1 ;
			RECT 2.365 4.975 2.815 5.035 ;
			LAYER M1 ;
			RECT 2.035 4.635 2.815 4.975 ;
			LAYER M1 ;
			RECT 2.365 4.585 2.815 4.635 ;
		END
		AntennaGateArea 0.414 ;
	END in2
	PIN VDD
		DIRECTION inout ;
		USE POWER ;
		PORT
			LAYER M1 ;
			RECT 0 6.9 2.96 7.9 ;
			LAYER M1 ;
			RECT 0.9 5.785 1.24 6.9 ;
			LAYER M1 ;
			RECT 2.34 5.285 2.68 6.9 ;
		END
	END VDD
	PIN in0
		DIRECTION input ;
		USE SIGNAL ;
		PORT
			LAYER M1 ;
			RECT 0.885 4.93 1.335 5.035 ;
			LAYER M1 ;
			RECT 0.64 4.59 1.335 4.93 ;
			LAYER M1 ;
			RECT 0.885 4.585 1.335 4.59 ;
		END
		AntennaGateArea 0.414 ;
	END in0
	OBS
	END
END MMI_NAND3A
MACRO MMI_NAND3B
	CLASS CORE ;
	FOREIGN MMI_NAND3B 0 0 ;
	SIZE 4.44 BY 7.4 ;
	SYMMETRY X Y ;
	SITE CORE1 ;
	PIN out
		DIRECTION output ;
		USE SIGNAL ;
		PORT
			LAYER M1 ;
			RECT 0.85 4.41 1.19 5.94 ;
			LAYER M1 ;
			RECT 2.29 4.41 2.63 5.94 ;
			LAYER M1 ;
			RECT 0.85 4.18 2.705 4.41 ;
			LAYER M1 ;
			RECT 2.475 2.785 2.705 4.18 ;
			LAYER M1 ;
			RECT 0.875 2.445 3.555 2.785 ;
		END
		AntennaDiffArea 3.2016 ;
	END out
	PIN in1
		DIRECTION input ;
		USE SIGNAL ;
		PORT
			LAYER M1 ;
			RECT 0.885 3.555 1.225 3.81 ;
			LAYER M1 ;
			RECT 0.885 3.105 1.335 3.555 ;
		END
		AntennaGateArea 0.828 ;
	END in1
	PIN GND
		DIRECTION inout ;
		USE GROUND ;
		PORT
			LAYER M1 ;
			RECT 0.875 0.865 3.555 1.205 ;
			LAYER M1 ;
			RECT 1.72 0.5 2.72 0.865 ;
			LAYER M1 ;
			RECT 0 -0.5 4.44 0.5 ;
		END
	END GND
	PIN in2
		DIRECTION input ;
		USE SIGNAL ;
		PORT
			LAYER M1 ;
			RECT 3.7 3.5 4.295 3.555 ;
			LAYER M1 ;
			RECT 3.5 3.16 4.295 3.5 ;
			LAYER M1 ;
			RECT 3.7 3.105 4.295 3.16 ;
		END
		AntennaGateArea 0.828 ;
	END in2
	PIN VDD
		DIRECTION inout ;
		USE POWER ;
		PORT
			LAYER M1 ;
			RECT 0 6.9 4.44 7.9 ;
			LAYER M1 ;
			RECT 1.57 4.66 1.91 6.9 ;
			LAYER M1 ;
			RECT 3.01 4.18 3.35 6.9 ;
		END
	END VDD
	PIN in0
		DIRECTION input ;
		USE SIGNAL ;
		PORT
			LAYER M1 ;
			RECT 1.625 3.5 2.075 3.555 ;
			LAYER M1 ;
			RECT 1.625 3.16 2.15 3.5 ;
			LAYER M1 ;
			RECT 1.625 3.105 2.075 3.16 ;
		END
		AntennaGateArea 0.828 ;
	END in0
	OBS
	END
END MMI_NAND3B
MACRO MMI_NAND3C
	CLASS CORE ;
	FOREIGN MMI_NAND3C 0 0 ;
	SIZE 7.4 BY 7.4 ;
	SYMMETRY X Y ;
	SITE CORE1 ;
	PIN out
		DIRECTION output ;
		USE SIGNAL ;
		PORT
			LAYER M1 ;
			RECT 1.91 4.49 2.25 6.02 ;
			LAYER M1 ;
			RECT 3.35 4.49 3.69 6.02 ;
			LAYER M1 ;
			RECT 4.79 4.49 5.13 6.02 ;
			LAYER M1 ;
			RECT 0.145 4.02 0.595 4.295 ;
			LAYER M1 ;
			RECT 1.91 4.26 5.13 4.49 ;
			LAYER M1 ;
			RECT 1.91 4.02 2.14 4.26 ;
			LAYER M1 ;
			RECT 0.145 3.79 2.14 4.02 ;
			LAYER M1 ;
			RECT 0.18 1.335 0.52 3.79 ;
			LAYER M1 ;
			RECT 1.62 1.335 1.96 2.385 ;
			LAYER M1 ;
			RECT 0.18 1.105 1.96 1.335 ;
		END
		AntennaDiffArea 4.8576 ;
	END out
	PIN in1
		DIRECTION input ;
		USE SIGNAL ;
		PORT
			LAYER M1 ;
			RECT 3.105 3.445 3.555 3.555 ;
			LAYER M1 ;
			RECT 3.105 3.105 3.66 3.445 ;
		END
		AntennaGateArea 1.656 ;
	END in1
	PIN GND
		DIRECTION inout ;
		USE GROUND ;
		PORT
			LAYER M1 ;
			RECT 5.22 0.5 5.56 2.385 ;
			LAYER M1 ;
			RECT 6.66 0.5 7 2.865 ;
			LAYER M1 ;
			RECT 0 -0.5 7.4 0.5 ;
		END
	END GND
	PIN in2
		DIRECTION input ;
		USE SIGNAL ;
		PORT
			LAYER M1 ;
			RECT 5.325 3.445 5.775 3.555 ;
			LAYER M1 ;
			RECT 5.11 3.105 5.775 3.445 ;
		END
		AntennaGateArea 1.656 ;
	END in2
	PIN VDD
		DIRECTION inout ;
		USE POWER ;
		PORT
			LAYER M1 ;
			RECT 0 6.9 7.4 7.9 ;
			LAYER M1 ;
			RECT 1.19 4.26 1.53 6.9 ;
			LAYER M1 ;
			RECT 2.63 4.74 2.97 6.9 ;
			LAYER M1 ;
			RECT 4.07 4.74 4.41 6.9 ;
			LAYER M1 ;
			RECT 5.51 4.26 5.85 6.9 ;
		END
	END VDD
	PIN in0
		DIRECTION input ;
		USE SIGNAL ;
		PORT
			LAYER M1 ;
			RECT 1.625 3.5 2.075 3.555 ;
			LAYER M1 ;
			RECT 1.31 3.16 2.075 3.5 ;
			LAYER M1 ;
			RECT 1.625 3.105 2.075 3.16 ;
		END
		AntennaGateArea 1.656 ;
	END in0
	OBS
		LAYER M1 ;
		RECT 0.9 2.635 2.68 2.865 ;
		LAYER M1 ;
		RECT 0.9 1.585 1.24 2.635 ;
		LAYER M1 ;
		RECT 2.34 1.335 2.68 2.635 ;
		LAYER M1 ;
		RECT 3.06 2.635 6.28 2.865 ;
		LAYER M1 ;
		RECT 3.06 1.585 3.4 2.635 ;
		LAYER M1 ;
		RECT 3.78 1.335 4.12 2.385 ;
		LAYER M1 ;
		RECT 2.34 1.105 4.12 1.335 ;
		LAYER M1 ;
		RECT 4.5 1.105 4.84 2.635 ;
		LAYER M1 ;
		RECT 5.94 1.105 6.28 2.635 ;
	END
END MMI_NAND3C
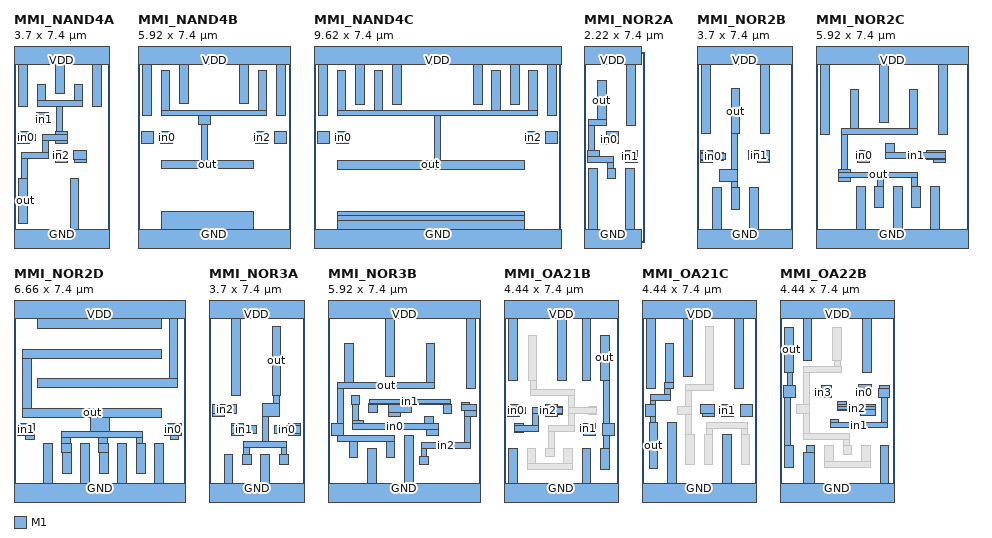
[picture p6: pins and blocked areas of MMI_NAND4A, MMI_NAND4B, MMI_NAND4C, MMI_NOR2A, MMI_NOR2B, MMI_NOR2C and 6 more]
MACRO MMI_NAND4A
	CLASS CORE ;
	FOREIGN MMI_NAND4A 0 0 ;
	SIZE 3.7 BY 7.4 ;
	SYMMETRY X Y ;
	SITE CORE1 ;
	PIN out
		DIRECTION output ;
		USE SIGNAL ;
		PORT
			LAYER M1 ;
			RECT 0.9 5.52 1.24 6.13 ;
			LAYER M1 ;
			RECT 2.34 5.52 2.68 6.13 ;
			LAYER M1 ;
			RECT 0.9 5.29 2.68 5.52 ;
			LAYER M1 ;
			RECT 1.66 4.295 1.89 5.29 ;
			LAYER M1 ;
			RECT 1.625 4.185 2.075 4.295 ;
			LAYER M1 ;
			RECT 1.11 3.955 2.075 4.185 ;
			LAYER M1 ;
			RECT 1.11 3.495 1.34 3.955 ;
			LAYER M1 ;
			RECT 1.625 3.845 2.075 3.955 ;
			LAYER M1 ;
			RECT 0.29 3.265 1.34 3.495 ;
			LAYER M1 ;
			RECT 0.29 2.49 0.52 3.265 ;
			LAYER M1 ;
			RECT 0.18 0.73 0.52 2.49 ;
		END
		AntennaDiffArea 1.8768 ;
	END out
	PIN in1
		DIRECTION input ;
		USE SIGNAL ;
		PORT
			LAYER M1 ;
			RECT 0.885 4.93 1.335 5.035 ;
			LAYER M1 ;
			RECT 0.885 4.59 1.43 4.93 ;
			LAYER M1 ;
			RECT 0.885 4.585 1.335 4.59 ;
		END
		AntennaGateArea 0.4968 ;
	END in1
	PIN GND
		DIRECTION inout ;
		USE GROUND ;
		PORT
			LAYER M1 ;
			RECT 2.19 0.5 2.53 2.49 ;
			LAYER M1 ;
			RECT 0 -0.5 3.7 0.5 ;
		END
	END GND
	PIN in2
		DIRECTION input ;
		USE SIGNAL ;
		PORT
			LAYER M1 ;
			RECT 1.625 3.55 2.075 3.555 ;
			LAYER M1 ;
			RECT 1.57 3.21 2.075 3.55 ;
			LAYER M1 ;
			RECT 1.625 3.105 2.075 3.21 ;
		END
		AntennaGateArea 0.4968 ;
	END in2
	PIN VDD
		DIRECTION inout ;
		USE POWER ;
		PORT
			LAYER M1 ;
			RECT 0 6.9 3.7 7.9 ;
			LAYER M1 ;
			RECT 0.18 5.29 0.52 6.9 ;
			LAYER M1 ;
			RECT 1.62 5.79 1.96 6.9 ;
			LAYER M1 ;
			RECT 3.06 5.29 3.4 6.9 ;
		END
	END VDD
	PIN in3
		DIRECTION input ;
		USE SIGNAL ;
		PORT
			LAYER M1 ;
			RECT 2.365 3.55 2.815 3.555 ;
			LAYER M1 ;
			RECT 2.305 3.21 2.815 3.55 ;
			LAYER M1 ;
			RECT 2.365 3.105 2.815 3.21 ;
		END
		AntennaGateArea 0.4968 ;
	END in3
	PIN in0
		DIRECTION input ;
		USE SIGNAL ;
		PORT
			LAYER M1 ;
			RECT 0.145 4.24 0.595 4.295 ;
			LAYER M1 ;
			RECT 0.145 4.185 0.76 4.24 ;
			LAYER M1 ;
			RECT 0.145 3.955 0.825 4.185 ;
			LAYER M1 ;
			RECT 0.145 3.9 0.76 3.955 ;
			LAYER M1 ;
			RECT 0.145 3.845 0.595 3.9 ;
		END
		AntennaGateArea 0.4968 ;
	END in0
	OBS
	END
END MMI_NAND4A
MACRO MMI_NAND4B
	CLASS CORE ;
	FOREIGN MMI_NAND4B 0 0 ;
	SIZE 5.92 BY 7.4 ;
	SYMMETRY X Y ;
	SITE CORE1 ;
	PIN out
		DIRECTION output ;
		USE SIGNAL ;
		PORT
			LAYER M1 ;
			RECT 0.9 5.14 1.24 6.67 ;
			LAYER M1 ;
			RECT 4.68 5.14 5.02 6.67 ;
			LAYER M1 ;
			RECT 0.9 4.91 5.02 5.14 ;
			LAYER M1 ;
			RECT 2.365 4.585 2.815 4.91 ;
			LAYER M1 ;
			RECT 2.485 3.19 2.715 4.585 ;
			LAYER M1 ;
			RECT 0.91 2.85 4.51 3.19 ;
		END
		AntennaDiffArea 3.7536 ;
	END out
	PIN in1
		DIRECTION input ;
		USE SIGNAL ;
		PORT
			LAYER M1 ;
			RECT 0.145 3.845 0.595 4.295 ;
		END
		AntennaGateArea 0.9936 ;
	END in1
	PIN GND
		DIRECTION inout ;
		USE GROUND ;
		PORT
			LAYER M1 ;
			RECT 0.91 0.5 4.51 1.18 ;
			LAYER M1 ;
			RECT 0 -0.5 5.92 0.5 ;
		END
	END GND
	PIN in2
		DIRECTION input ;
		USE SIGNAL ;
		PORT
			LAYER M1 ;
			RECT 4.585 3.845 5.035 4.295 ;
		END
		AntennaGateArea 0.9936 ;
	END in2
	PIN VDD
		DIRECTION inout ;
		USE POWER ;
		PORT
			LAYER M1 ;
			RECT 0 6.9 5.92 7.9 ;
			LAYER M1 ;
			RECT 0.18 4.91 0.52 6.9 ;
			LAYER M1 ;
			RECT 1.62 5.39 1.96 6.9 ;
			LAYER M1 ;
			RECT 3.96 5.39 4.3 6.9 ;
			LAYER M1 ;
			RECT 5.4 4.91 5.74 6.9 ;
		END
	END VDD
	PIN in3
		DIRECTION input ;
		USE SIGNAL ;
		PORT
			LAYER M1 ;
			RECT 5.325 3.845 5.775 4.295 ;
		END
		AntennaGateArea 0.9936 ;
	END in3
	PIN in0
		DIRECTION input ;
		USE SIGNAL ;
		PORT
			LAYER M1 ;
			RECT 0.885 3.845 1.335 4.295 ;
		END
		AntennaGateArea 0.9936 ;
	END in0
	OBS
	END
END MMI_NAND4B
MACRO MMI_NAND4C
	CLASS CORE ;
	FOREIGN MMI_NAND4C 0 0 ;
	SIZE 9.62 BY 7.4 ;
	SYMMETRY X Y ;
	SITE CORE1 ;
	PIN out
		DIRECTION output ;
		USE SIGNAL ;
		PORT
			LAYER M1 ;
			RECT 0.9 5.14 1.24 6.67 ;
			LAYER M1 ;
			RECT 2.34 5.14 2.68 6.67 ;
			LAYER M1 ;
			RECT 6.93 5.14 7.27 6.67 ;
			LAYER M1 ;
			RECT 8.37 5.14 8.71 6.67 ;
			LAYER M1 ;
			RECT 0.9 4.91 8.71 5.14 ;
			LAYER M1 ;
			RECT 4.68 3.18 4.91 4.91 ;
			LAYER M1 ;
			RECT 0.91 2.84 8.19 3.18 ;
		END
		AntennaDiffArea 7.5072 ;
	END out
	PIN in1
		DIRECTION input ;
		USE SIGNAL ;
		PORT
			LAYER M1 ;
			RECT 0.145 3.845 0.595 4.295 ;
		END
		AntennaGateArea 1.9872 ;
	END in1
	PIN GND
		DIRECTION inout ;
		USE GROUND ;
		PORT
			LAYER M1 ;
			RECT 0.91 1.02 8.19 1.17 ;
			LAYER M1 ;
			RECT 0.9 0.83 8.19 1.02 ;
			LAYER M1 ;
			RECT 0.9 0.5 8.18 0.83 ;
			LAYER M1 ;
			RECT 0 -0.5 9.62 0.5 ;
		END
	END GND
	PIN in2
		DIRECTION input ;
		USE SIGNAL ;
		PORT
			LAYER M1 ;
			RECT 8.285 3.845 8.735 4.295 ;
		END
		AntennaGateArea 1.9872 ;
	END in2
	PIN VDD
		DIRECTION inout ;
		USE POWER ;
		PORT
			LAYER M1 ;
			RECT 0 6.9 9.62 7.9 ;
			LAYER M1 ;
			RECT 0.18 4.909 0.52 6.9 ;
			LAYER M1 ;
			RECT 1.62 5.37 1.96 6.9 ;
			LAYER M1 ;
			RECT 3.06 5.37 3.4 6.9 ;
			LAYER M1 ;
			RECT 6.21 5.37 6.55 6.9 ;
			LAYER M1 ;
			RECT 7.65 5.37 7.99 6.9 ;
			LAYER M1 ;
			RECT 9.09 4.909 9.43 6.9 ;
		END
	END VDD
	PIN in3
		DIRECTION input ;
		USE SIGNAL ;
		PORT
			LAYER M1 ;
			RECT 9.025 3.845 9.475 4.295 ;
		END
		AntennaGateArea 1.9872 ;
	END in3
	PIN in0
		DIRECTION input ;
		USE SIGNAL ;
		PORT
			LAYER M1 ;
			RECT 0.885 3.845 1.335 4.295 ;
		END
		AntennaGateArea 1.9872 ;
	END in0
	OBS
	END
END MMI_NAND4C
MACRO MMI_NOR2A
	CLASS CORE ;
	FOREIGN MMI_NOR2A 0 0 ;
	SIZE 2.22 BY 7.4 ;
	SYMMETRY X Y ;
	SITE CORE1 ;
	PIN out
		DIRECTION output ;
		USE SIGNAL ;
		PORT
			LAYER M1 ;
			RECT 0.52 4.765 0.86 6.295 ;
			LAYER M1 ;
			RECT 0.18 4.535 0.86 4.765 ;
			LAYER M1 ;
			RECT 0.18 3.555 0.41 4.535 ;
			LAYER M1 ;
			RECT 0.145 3.335 0.595 3.555 ;
			LAYER M1 ;
			RECT 0.145 3.105 1.13 3.335 ;
			LAYER M1 ;
			RECT 0.9 2.86 1.13 3.105 ;
			LAYER M1 ;
			RECT 0.9 2.48 1.24 2.86 ;
		END
		AntennaDiffArea 1.1316 ;
	END out
	PIN in1
		DIRECTION input ;
		USE SIGNAL ;
		PORT
			LAYER M1 ;
			RECT 1.625 3.5 2.075 3.555 ;
			LAYER M1 ;
			RECT 1.51 3.16 2.075 3.5 ;
			LAYER M1 ;
			RECT 1.625 3.105 2.075 3.16 ;
		END
		AntennaGateArea 0.414 ;
	END in1
	PIN GND
		DIRECTION inout ;
		USE GROUND ;
		PORT
			LAYER M1 ;
			RECT 0.18 0.5 0.52 2.86 ;
			LAYER M1 ;
			RECT 1.62 0.5 1.96 2.86 ;
			LAYER M1 ;
			RECT 0 -0.5 2.22 0.5 ;
		END
	END GND
	PIN VDD
		DIRECTION inout ;
		USE POWER ;
		PORT
			LAYER M1 ;
			RECT 0 6.9 2.22 7.9 ;
			LAYER M1 ;
			RECT 1.67 4.535 2.01 6.9 ;
		END
	END VDD
	PIN in0
		DIRECTION input ;
		USE SIGNAL ;
		PORT
			LAYER M1 ;
			RECT 0.885 4.14 1.335 4.295 ;
			LAYER M1 ;
			RECT 0.64 3.845 1.335 4.14 ;
			LAYER M1 ;
			RECT 0.64 3.8 0.98 3.845 ;
		END
		AntennaGateArea 0.414 ;
	END in0
	OBS
	END
END MMI_NOR2A
MACRO MMI_NOR2B
	CLASS CORE ;
	FOREIGN MMI_NOR2B 0 0 ;
	SIZE 3.7 BY 7.4 ;
	SYMMETRY X Y ;
	SITE CORE1 ;
	PIN out
		DIRECTION output ;
		USE SIGNAL ;
		PORT
			LAYER M1 ;
			RECT 1.33 4.21 1.67 5.97 ;
			LAYER M1 ;
			RECT 1.345 2.815 1.575 4.21 ;
			LAYER M1 ;
			RECT 0.885 2.365 1.575 2.815 ;
			LAYER M1 ;
			RECT 1.345 2.11 1.575 2.365 ;
			LAYER M1 ;
			RECT 1.33 1.27 1.67 2.11 ;
		END
		AntennaDiffArea 1.4904 ;
	END out
	PIN in1
		DIRECTION input ;
		USE SIGNAL ;
		PORT
			LAYER M1 ;
			RECT 2.365 3.55 2.815 3.555 ;
			LAYER M1 ;
			RECT 2 3.21 2.815 3.55 ;
			LAYER M1 ;
			RECT 2.365 3.105 2.815 3.21 ;
		END
		AntennaGateArea 0.828 ;
	END in1
	PIN GND
		DIRECTION inout ;
		USE GROUND ;
		PORT
			LAYER M1 ;
			RECT 0.61 0.5 0.95 2.11 ;
			LAYER M1 ;
			RECT 2.05 0.5 2.39 2.11 ;
			LAYER M1 ;
			RECT 0 -0.5 3.7 0.5 ;
		END
	END GND
	PIN VDD
		DIRECTION inout ;
		USE POWER ;
		PORT
			LAYER M1 ;
			RECT 0 6.9 3.7 7.9 ;
			LAYER M1 ;
			RECT 0.18 4.21 0.52 6.9 ;
			LAYER M1 ;
			RECT 2.48 4.21 2.82 6.9 ;
		END
	END VDD
	PIN in0
		DIRECTION input ;
		USE SIGNAL ;
		PORT
			LAYER M1 ;
			RECT 0.145 3.5 0.595 3.555 ;
			LAYER M1 ;
			RECT 0.145 3.445 1.05 3.5 ;
			LAYER M1 ;
			RECT 0.145 3.215 1.115 3.445 ;
			LAYER M1 ;
			RECT 0.145 3.16 1.05 3.215 ;
			LAYER M1 ;
			RECT 0.145 3.105 0.595 3.16 ;
		END
		AntennaGateArea 0.828 ;
	END in0
	OBS
	END
END MMI_NOR2B
MACRO MMI_NOR2C
	CLASS CORE ;
	FOREIGN MMI_NOR2C 0 0 ;
	SIZE 5.92 BY 7.4 ;
	SYMMETRY X Y ;
	SITE CORE1 ;
	PIN out
		DIRECTION output ;
		USE SIGNAL ;
		PORT
			LAYER M1 ;
			RECT 1.33 4.41 1.67 5.94 ;
			LAYER M1 ;
			RECT 3.63 4.41 3.97 5.94 ;
			LAYER M1 ;
			RECT 1.01 4.18 3.97 4.41 ;
			LAYER M1 ;
			RECT 1.01 2.815 1.24 4.18 ;
			LAYER M1 ;
			RECT 0.885 2.725 1.335 2.815 ;
			LAYER M1 ;
			RECT 0.885 2.495 3.965 2.725 ;
			LAYER M1 ;
			RECT 0.885 2.365 1.335 2.495 ;
			LAYER M1 ;
			RECT 2.405 2.17 2.635 2.495 ;
			LAYER M1 ;
			RECT 2.295 1.33 2.635 2.17 ;
			LAYER M1 ;
			RECT 3.735 2.17 3.965 2.495 ;
			LAYER M1 ;
			RECT 3.735 1.33 4.075 2.17 ;
		END
		AntennaDiffArea 2.9808 ;
	END out
	PIN in1
		DIRECTION input ;
		USE SIGNAL ;
		PORT
			LAYER M1 ;
			RECT 2.72 3.495 3.06 3.82 ;
			LAYER M1 ;
			RECT 4.585 3.55 5.035 3.555 ;
			LAYER M1 ;
			RECT 4.3 3.495 5.035 3.55 ;
			LAYER M1 ;
			RECT 2.72 3.265 5.035 3.495 ;
			LAYER M1 ;
			RECT 4.3 3.21 5.035 3.265 ;
			LAYER M1 ;
			RECT 4.585 3.105 5.035 3.21 ;
		END
		AntennaGateArea 1.656 ;
	END in1
	PIN GND
		DIRECTION inout ;
		USE GROUND ;
		PORT
			LAYER M1 ;
			RECT 1.575 0.5 1.915 2.17 ;
			LAYER M1 ;
			RECT 3.015 0.5 3.355 2.17 ;
			LAYER M1 ;
			RECT 4.455 0.5 4.795 2.17 ;
			LAYER M1 ;
			RECT 0 -0.5 5.92 0.5 ;
		END
	END GND
	PIN VDD
		DIRECTION inout ;
		USE POWER ;
		PORT
			LAYER M1 ;
			RECT 0 6.9 5.92 7.9 ;
			LAYER M1 ;
			RECT 0.18 4.18 0.52 6.9 ;
			LAYER M1 ;
			RECT 2.48 4.66 2.82 6.9 ;
			LAYER M1 ;
			RECT 4.78 4.18 5.12 6.9 ;
		END
	END VDD
	PIN in0
		DIRECTION input ;
		USE SIGNAL ;
		PORT
			LAYER M1 ;
			RECT 1.625 3.55 2.075 3.555 ;
			LAYER M1 ;
			RECT 1.625 3.21 2.15 3.55 ;
			LAYER M1 ;
			RECT 1.625 3.105 2.075 3.21 ;
		END
		AntennaGateArea 1.656 ;
	END in0
	OBS
	END
END MMI_NOR2C
MACRO MMI_NOR2D
	CLASS CORE ;
	FOREIGN MMI_NOR2D 0 0 ;
	SIZE 6.66 BY 7.4 ;
	SYMMETRY X Y ;
	SITE CORE1 ;
	PIN out
		DIRECTION output ;
		USE SIGNAL ;
		PORT
			LAYER M1 ;
			RECT 0.34 5.37 5.74 5.71 ;
			LAYER M1 ;
			RECT 0.34 3.41 0.68 5.37 ;
			LAYER M1 ;
			RECT 0.34 3.07 5.74 3.41 ;
			LAYER M1 ;
			RECT 2.995 2.5 3.71 3.07 ;
			LAYER M1 ;
			RECT 1.865 2.27 4.995 2.5 ;
			LAYER M1 ;
			RECT 1.865 2.04 2.205 2.27 ;
			LAYER M1 ;
			RECT 3.305 2.04 3.645 2.27 ;
			LAYER M1 ;
			RECT 4.765 2.04 4.995 2.27 ;
			LAYER M1 ;
			RECT 1.865 1.7 2.225 2.04 ;
			LAYER M1 ;
			RECT 3.305 1.7 3.665 2.04 ;
			LAYER M1 ;
			RECT 1.885 0.895 2.225 1.7 ;
			LAYER M1 ;
			RECT 3.325 0.895 3.665 1.7 ;
			LAYER M1 ;
			RECT 4.765 0.895 5.105 2.04 ;
		END
		AntennaDiffArea 6.9825 ;
	END out
	PIN in1
		DIRECTION input ;
		USE SIGNAL ;
		PORT
			LAYER M1 ;
			RECT 0.145 2.365 0.78 2.835 ;
			LAYER M1 ;
			RECT 0.44 2.22 0.78 2.365 ;
		END
		AntennaGateArea 3.3075 ;
	END in1
	PIN GND
		DIRECTION inout ;
		USE GROUND ;
		PORT
			LAYER M1 ;
			RECT 1.165 0.5 1.505 2.04 ;
			LAYER M1 ;
			RECT 2.605 0.5 2.945 2.04 ;
			LAYER M1 ;
			RECT 4.045 0.5 4.385 2.04 ;
			LAYER M1 ;
			RECT 5.485 0.5 5.825 2.04 ;
			LAYER M1 ;
			RECT 0 -0.5 6.66 0.5 ;
		END
	END GND
	PIN VDD
		DIRECTION inout ;
		USE POWER ;
		PORT
			LAYER M1 ;
			RECT 0 6.9 6.66 7.9 ;
			LAYER M1 ;
			RECT 0.92 6.52 5.74 6.9 ;
			LAYER M1 ;
			RECT 6.045 4.56 6.385 6.9 ;
			LAYER M1 ;
			RECT 0.92 4.22 6.385 4.56 ;
		END
	END VDD
	PIN in0
		DIRECTION input ;
		USE SIGNAL ;
		PORT
			LAYER M1 ;
			RECT 5.85 2.365 6.515 2.815 ;
			LAYER M1 ;
			RECT 6.08 2.22 6.42 2.365 ;
		END
		AntennaGateArea 3.3075 ;
	END in0
	OBS
	END
END MMI_NOR2D
MACRO MMI_NOR3A
	CLASS CORE ;
	FOREIGN MMI_NOR3A 0 0 ;
	SIZE 3.7 BY 7.4 ;
	SYMMETRY X Y ;
	SITE CORE1 ;
	PIN out
		DIRECTION output ;
		USE SIGNAL ;
		PORT
			LAYER M1 ;
			RECT 2.455 3.93 2.795 6.61 ;
			LAYER M1 ;
			RECT 2.5 3.605 2.73 3.93 ;
			LAYER M1 ;
			RECT 2.085 3.105 2.73 3.605 ;
			LAYER M1 ;
			RECT 2.085 2.13 2.315 3.105 ;
			LAYER M1 ;
			RECT 1.345 1.9 3.035 2.13 ;
			LAYER M1 ;
			RECT 1.345 1.615 1.575 1.9 ;
			LAYER M1 ;
			RECT 2.805 1.615 3.035 1.9 ;
			LAYER M1 ;
			RECT 1.305 1.235 1.645 1.615 ;
			LAYER M1 ;
			RECT 2.745 1.235 3.085 1.615 ;
		END
		AntennaDiffArea 1.794 ;
	END out
	PIN in1
		DIRECTION input ;
		USE SIGNAL ;
		PORT
			LAYER M1 ;
			RECT 0.885 2.76 1.335 2.815 ;
			LAYER M1 ;
			RECT 0.885 2.42 1.85 2.76 ;
			LAYER M1 ;
			RECT 0.885 2.365 1.335 2.42 ;
		END
		AntennaGateArea 0.5796 ;
	END in1
	PIN GND
		DIRECTION inout ;
		USE GROUND ;
		PORT
			LAYER M1 ;
			RECT 0.585 0.5 0.925 1.615 ;
			LAYER M1 ;
			RECT 2.025 0.5 2.365 1.615 ;
			LAYER M1 ;
			RECT 0 -0.5 3.7 0.5 ;
		END
	END GND
	PIN in2
		DIRECTION input ;
		USE SIGNAL ;
		PORT
			LAYER M1 ;
			RECT 0.145 3.215 1.075 3.555 ;
			LAYER M1 ;
			RECT 0.145 3.105 0.595 3.215 ;
		END
		AntennaGateArea 0.5796 ;
	END in2
	PIN VDD
		DIRECTION inout ;
		USE POWER ;
		PORT
			LAYER M1 ;
			RECT 0 6.9 3.7 7.9 ;
			LAYER M1 ;
			RECT 0.875 3.93 1.215 6.9 ;
		END
	END VDD
	PIN in0
		DIRECTION input ;
		USE SIGNAL ;
		PORT
			LAYER M1 ;
			RECT 3.105 2.76 3.555 2.815 ;
			LAYER M1 ;
			RECT 2.555 2.42 3.555 2.76 ;
			LAYER M1 ;
			RECT 3.105 2.365 3.555 2.42 ;
		END
		AntennaGateArea 0.5796 ;
	END in0
	OBS
	END
END MMI_NOR3A
MACRO MMI_NOR3B
	CLASS CORE ;
	FOREIGN MMI_NOR3B 0 0 ;
	SIZE 5.92 BY 7.4 ;
	SYMMETRY X Y ;
	SITE CORE1 ;
	PIN out
		DIRECTION output ;
		USE SIGNAL ;
		PORT
			LAYER M1 ;
			RECT 0.66 4.41 1 5.94 ;
			LAYER M1 ;
			RECT 3.82 4.41 4.16 5.94 ;
			LAYER M1 ;
			RECT 0.365 4.18 4.16 4.41 ;
			LAYER M1 ;
			RECT 0.365 2.815 0.595 4.18 ;
			LAYER M1 ;
			RECT 0.145 2.365 0.595 2.815 ;
			LAYER M1 ;
			RECT 0.365 2.355 0.595 2.365 ;
			LAYER M1 ;
			RECT 0.365 2.35 2.55 2.355 ;
			LAYER M1 ;
			RECT 0.365 2.125 2.6 2.35 ;
			LAYER M1 ;
			RECT 0.82 1.51 1.16 2.125 ;
			LAYER M1 ;
			RECT 2.26 1.51 2.6 2.125 ;
		END
		AntennaDiffArea 2.8152 ;
	END out
	PIN in1
		DIRECTION input ;
		USE SIGNAL ;
		PORT
			LAYER M1 ;
			RECT 1.61 3.595 4.765 3.775 ;
			LAYER M1 ;
			RECT 1.57 3.57 4.765 3.595 ;
			LAYER M1 ;
			RECT 1.57 3.545 4.82 3.57 ;
			LAYER M1 ;
			RECT 1.57 3.255 1.91 3.545 ;
			LAYER M1 ;
			RECT 2.365 3.26 3.25 3.545 ;
			LAYER M1 ;
			RECT 2.365 3.105 2.815 3.26 ;
			LAYER M1 ;
			RECT 4.48 3.23 4.82 3.545 ;
		END
		AntennaGateArea 1.1592 ;
	END in1
	PIN GND
		DIRECTION inout ;
		USE GROUND ;
		PORT
			LAYER M1 ;
			RECT 1.54 0.5 1.88 1.85 ;
			LAYER M1 ;
			RECT 2.98 0.5 3.32 2.35 ;
			LAYER M1 ;
			RECT 0 -0.5 5.92 0.5 ;
		END
	END GND
	PIN in2
		DIRECTION input ;
		USE SIGNAL ;
		PORT
			LAYER M1 ;
			RECT 5.185 3.555 5.525 3.655 ;
			LAYER M1 ;
			RECT 5.185 3.315 5.775 3.555 ;
			LAYER M1 ;
			RECT 5.325 3.105 5.775 3.315 ;
			LAYER M1 ;
			RECT 5.33 2.085 5.56 3.105 ;
			LAYER M1 ;
			RECT 3.625 1.855 5.56 2.085 ;
			LAYER M1 ;
			RECT 3.625 1.55 3.855 1.855 ;
			LAYER M1 ;
			RECT 3.57 1.21 3.91 1.55 ;
		END
		AntennaGateArea 1.1592 ;
	END in2
	PIN VDD
		DIRECTION inout ;
		USE POWER ;
		PORT
			LAYER M1 ;
			RECT 0 6.9 5.92 7.9 ;
			LAYER M1 ;
			RECT 2.24 4.66 2.58 6.9 ;
			LAYER M1 ;
			RECT 5.4 4.18 5.74 6.9 ;
		END
	END VDD
	PIN in0
		DIRECTION input ;
		USE SIGNAL ;
		PORT
			LAYER M1 ;
			RECT 0.9 3.58 1.24 3.92 ;
			LAYER M1 ;
			RECT 0.96 2.925 1.19 3.58 ;
			LAYER M1 ;
			RECT 0.96 2.83 1.4 2.925 ;
			LAYER M1 ;
			RECT 3.76 2.83 4.1 3.08 ;
			LAYER M1 ;
			RECT 0.96 2.815 4.1 2.83 ;
			LAYER M1 ;
			RECT 0.96 2.6 4.295 2.815 ;
			LAYER M1 ;
			RECT 1.06 2.585 1.4 2.6 ;
			LAYER M1 ;
			RECT 3.845 2.365 4.295 2.6 ;
		END
		AntennaGateArea 1.1592 ;
	END in0
	OBS
	END
END MMI_NOR3B
MACRO MMI_OA21B
	CLASS CORE ;
	FOREIGN MMI_OA21B 0 0 ;
	SIZE 4.44 BY 7.4 ;
	SYMMETRY X Y ;
	SITE CORE1 ;
	PIN out
		DIRECTION output ;
		USE SIGNAL ;
		PORT
			LAYER M1 ;
			RECT 3.76 4.51 4.1 6.27 ;
			LAYER M1 ;
			RECT 3.87 2.815 4.1 4.51 ;
			LAYER M1 ;
			RECT 3.845 2.365 4.295 2.815 ;
			LAYER M1 ;
			RECT 3.87 1.86 4.1 2.365 ;
			LAYER M1 ;
			RECT 3.76 1.02 4.1 1.86 ;
		END
		AntennaDiffArea 1.3248 ;
	END out
	PIN in1
		DIRECTION input ;
		USE SIGNAL ;
		PORT
			LAYER M1 ;
			RECT 3.105 2.81 3.555 2.815 ;
			LAYER M1 ;
			RECT 2.98 2.47 3.555 2.81 ;
			LAYER M1 ;
			RECT 3.105 2.365 3.555 2.47 ;
		END
		AntennaGateArea 0.4968 ;
	END in1
	PIN GND
		DIRECTION inout ;
		USE GROUND ;
		PORT
			LAYER M1 ;
			RECT 0.18 0.5 0.52 1.86 ;
			LAYER M1 ;
			RECT 3.04 0.5 3.38 1.86 ;
			LAYER M1 ;
			RECT 0 -0.5 4.44 0.5 ;
		END
	END GND
	PIN in2
		DIRECTION input ;
		USE SIGNAL ;
		PORT
			LAYER M1 ;
			RECT 1.625 3.5 2.075 3.555 ;
			LAYER M1 ;
			RECT 1.625 3.445 2.29 3.5 ;
			LAYER M1 ;
			RECT 1.11 3.215 2.29 3.445 ;
			LAYER M1 ;
			RECT 0.42 2.755 0.76 2.81 ;
			LAYER M1 ;
			RECT 1.11 2.755 1.34 3.215 ;
			LAYER M1 ;
			RECT 1.625 3.16 2.29 3.215 ;
			LAYER M1 ;
			RECT 1.625 3.105 2.075 3.16 ;
			LAYER M1 ;
			RECT 0.42 2.525 1.34 2.755 ;
			LAYER M1 ;
			RECT 0.42 2.47 0.76 2.525 ;
		END
		AntennaGateArea 0.4968 ;
	END in2
	PIN VDD
		DIRECTION inout ;
		USE POWER ;
		PORT
			LAYER M1 ;
			RECT 0 6.9 4.44 7.9 ;
			LAYER M1 ;
			RECT 0.18 4.51 0.52 6.9 ;
			LAYER M1 ;
			RECT 2.09 4.51 2.43 6.9 ;
			LAYER M1 ;
			RECT 3.04 4.51 3.38 6.9 ;
		END
	END VDD
	PIN in0
		DIRECTION input ;
		USE SIGNAL ;
		PORT
			LAYER M1 ;
			RECT 0.145 3.5 0.595 3.555 ;
			LAYER M1 ;
			RECT 0.145 3.445 0.76 3.5 ;
			LAYER M1 ;
			RECT 0.145 3.215 0.825 3.445 ;
			LAYER M1 ;
			RECT 0.145 3.16 0.76 3.215 ;
			LAYER M1 ;
			RECT 0.145 3.105 0.595 3.16 ;
		END
		AntennaGateArea 0.3312 ;
	END in0
	OBS
		LAYER M1 ;
		RECT 0.94 4.51 1.28 6.27 ;
		LAYER M1 ;
		RECT 1.05 4.135 1.28 4.51 ;
		LAYER M1 ;
		RECT 1.05 3.905 2.75 4.135 ;
		LAYER M1 ;
		RECT 2.52 3.445 2.75 3.905 ;
		LAYER M1 ;
		RECT 3.28 3.445 3.62 3.5 ;
		LAYER M1 ;
		RECT 2.52 3.215 3.62 3.445 ;
		LAYER M1 ;
		RECT 2.52 2.755 2.75 3.215 ;
		LAYER M1 ;
		RECT 3.28 3.16 3.62 3.215 ;
		LAYER M1 ;
		RECT 1.73 2.525 2.75 2.755 ;
		LAYER M1 ;
		RECT 1.73 1.86 1.96 2.525 ;
		LAYER M1 ;
		RECT 0.9 1.25 1.24 1.86 ;
		LAYER M1 ;
		RECT 1.62 1.52 1.96 1.86 ;
		LAYER M1 ;
		RECT 2.32 1.25 2.66 1.86 ;
		LAYER M1 ;
		RECT 0.9 1.02 2.66 1.25 ;
	END
END MMI_OA21B
MACRO MMI_OA21C
	CLASS CORE ;
	FOREIGN MMI_OA21C 0 0 ;
	SIZE 4.44 BY 7.4 ;
	SYMMETRY X Y ;
	SITE CORE1 ;
	PIN out
		DIRECTION output ;
		USE SIGNAL ;
		PORT
			LAYER M1 ;
			RECT 0.9 4.42 1.24 5.95 ;
			LAYER M1 ;
			RECT 0.895 4.19 1.24 4.42 ;
			LAYER M1 ;
			RECT 0.895 3.94 1.125 4.19 ;
			LAYER M1 ;
			RECT 0.315 3.71 1.125 3.94 ;
			LAYER M1 ;
			RECT 0.315 3.555 0.545 3.71 ;
			LAYER M1 ;
			RECT 0.145 3.105 0.545 3.555 ;
			LAYER M1 ;
			RECT 0.315 2.85 0.545 3.105 ;
			LAYER M1 ;
			RECT 0.28 1.09 0.62 2.85 ;
		END
		AntennaDiffArea 1.8768 ;
	END out
	PIN in1
		DIRECTION input ;
		USE SIGNAL ;
		PORT
			LAYER M1 ;
			RECT 3.105 3.495 3.555 3.55 ;
			LAYER M1 ;
			RECT 3.075 3.155 3.555 3.495 ;
			LAYER M1 ;
			RECT 3.105 3.1 3.555 3.155 ;
		END
		AntennaGateArea 0.6696 ;
	END in1
	PIN GND
		DIRECTION inout ;
		USE GROUND ;
		PORT
			LAYER M1 ;
			RECT 1 0.5 1.34 2.85 ;
			LAYER M1 ;
			RECT 3.14 0.5 3.48 2.4 ;
			LAYER M1 ;
			RECT 0 -0.5 4.44 0.5 ;
		END
	END GND
	PIN in2
		DIRECTION input ;
		USE SIGNAL ;
		PORT
			LAYER M1 ;
			RECT 3.845 3.105 4.295 3.555 ;
		END
		AntennaGateArea 0.6696 ;
	END in2
	PIN VDD
		DIRECTION inout ;
		USE POWER ;
		PORT
			LAYER M1 ;
			RECT 0 6.9 4.44 7.9 ;
			LAYER M1 ;
			RECT 0.18 4.19 0.52 6.9 ;
			LAYER M1 ;
			RECT 1.62 4.67 1.96 6.9 ;
			LAYER M1 ;
			RECT 3.605 4.19 3.945 6.9 ;
		END
	END VDD
	PIN in0
		DIRECTION input ;
		USE SIGNAL ;
		PORT
			LAYER M1 ;
			RECT 2.26 3.215 2.815 3.555 ;
			LAYER M1 ;
			RECT 2.365 3.105 2.815 3.215 ;
		END
		AntennaGateArea 0.4464 ;
	END in0
	OBS
		LAYER M1 ;
		RECT 2.455 4.345 2.795 6.59 ;
		LAYER M1 ;
		RECT 1.7 4.115 2.795 4.345 ;
		LAYER M1 ;
		RECT 1.7 3.5 1.93 4.115 ;
		LAYER M1 ;
		RECT 1.365 3.16 1.93 3.5 ;
		LAYER M1 ;
		RECT 1.7 2.4 1.93 3.16 ;
		LAYER M1 ;
		RECT 2.53 2.64 4.09 2.87 ;
		LAYER M1 ;
		RECT 2.53 2.4 2.76 2.64 ;
		LAYER M1 ;
		RECT 3.86 2.4 4.09 2.64 ;
		LAYER M1 ;
		RECT 1.7 1.24 2.04 2.4 ;
		LAYER M1 ;
		RECT 2.42 1.24 2.76 2.4 ;
		LAYER M1 ;
		RECT 3.86 1.24 4.2 2.4 ;
	END
END MMI_OA21C
MACRO MMI_OA22B
	CLASS CORE ;
	FOREIGN MMI_OA22B 0 0 ;
	SIZE 4.44 BY 7.4 ;
	SYMMETRY X Y ;
	SITE CORE1 ;
	PIN out
		DIRECTION output ;
		USE SIGNAL ;
		PORT
			LAYER M1 ;
			RECT 0.18 4.81 0.52 6.57 ;
			LAYER M1 ;
			RECT 0.275 4.295 0.505 4.81 ;
			LAYER M1 ;
			RECT 0.145 3.845 0.595 4.295 ;
			LAYER M1 ;
			RECT 0.18 1.96 0.41 3.845 ;
			LAYER M1 ;
			RECT 0.18 1.12 0.52 1.96 ;
		END
		AntennaDiffArea 1.3248 ;
	END out
	PIN in1
		DIRECTION input ;
		USE SIGNAL ;
		PORT
			LAYER M1 ;
			RECT 3.89 4.195 4.265 4.305 ;
			LAYER M1 ;
			RECT 3.855 3.855 4.265 4.195 ;
			LAYER M1 ;
			RECT 1.955 2.88 2.295 2.99 ;
			LAYER M1 ;
			RECT 3.96 2.88 4.19 3.855 ;
			LAYER M1 ;
			RECT 1.955 2.65 4.19 2.88 ;
		END
		AntennaGateArea 0.4968 ;
	END in1
	PIN GND
		DIRECTION inout ;
		USE GROUND ;
		PORT
			LAYER M1 ;
			RECT 1.02 1.695 1.36 1.96 ;
			LAYER M1 ;
			RECT 0.9 0.5 1.36 1.695 ;
			LAYER M1 ;
			RECT 3.9 0.5 4.24 1.96 ;
			LAYER M1 ;
			RECT 0 -0.5 4.44 0.5 ;
		END
	END GND
	PIN in2
		DIRECTION input ;
		USE SIGNAL ;
		PORT
			LAYER M1 ;
			RECT 2.255 3.58 2.595 3.67 ;
			LAYER M1 ;
			RECT 2.255 3.47 3.71 3.58 ;
			LAYER M1 ;
			RECT 2.255 3.35 3.715 3.47 ;
			LAYER M1 ;
			RECT 2.255 3.33 2.595 3.35 ;
			LAYER M1 ;
			RECT 3.12 3.13 3.715 3.35 ;
		END
		AntennaGateArea 0.4968 ;
	END in2
	PIN VDD
		DIRECTION inout ;
		USE POWER ;
		PORT
			LAYER M1 ;
			RECT 0 6.9 4.44 7.9 ;
			LAYER M1 ;
			RECT 0.9 5.29 1.24 6.9 ;
			LAYER M1 ;
			RECT 3.205 4.81 3.545 6.9 ;
		END
	END VDD
	PIN in3
		DIRECTION input ;
		USE SIGNAL ;
		PORT
			LAYER M1 ;
			RECT 1.625 4.19 2.015 4.295 ;
			LAYER M1 ;
			RECT 1.36 3.85 2.015 4.19 ;
			LAYER M1 ;
			RECT 1.625 3.845 2.015 3.85 ;
		END
		AntennaGateArea 0.4968 ;
	END in3
	PIN in0
		DIRECTION input ;
		USE SIGNAL ;
		PORT
			LAYER M1 ;
			RECT 3.07 4.2 3.55 4.36 ;
			LAYER M1 ;
			RECT 2.985 3.86 3.55 4.2 ;
		END
		AntennaGateArea 0.4968 ;
	END in0
	OBS
		LAYER M1 ;
		RECT 2.05 5.29 2.39 6.57 ;
		LAYER M1 ;
		RECT 2.12 5.04 2.35 5.29 ;
		LAYER M1 ;
		RECT 0.9 4.81 2.395 5.04 ;
		LAYER M1 ;
		RECT 0.9 3.55 1.13 4.81 ;
		LAYER M1 ;
		RECT 0.64 3.21 1.13 3.55 ;
		LAYER M1 ;
		RECT 0.9 2.42 1.13 3.21 ;
		LAYER M1 ;
		RECT 0.9 2.19 2.69 2.42 ;
		LAYER M1 ;
		RECT 2.46 1.96 2.69 2.19 ;
		LAYER M1 ;
		RECT 1.74 1.35 2.08 1.96 ;
		LAYER M1 ;
		RECT 2.46 1.62 2.8 1.96 ;
		LAYER M1 ;
		RECT 3.18 1.35 3.52 1.96 ;
		LAYER M1 ;
		RECT 1.74 1.12 3.52 1.35 ;
	END
END MMI_OA22B
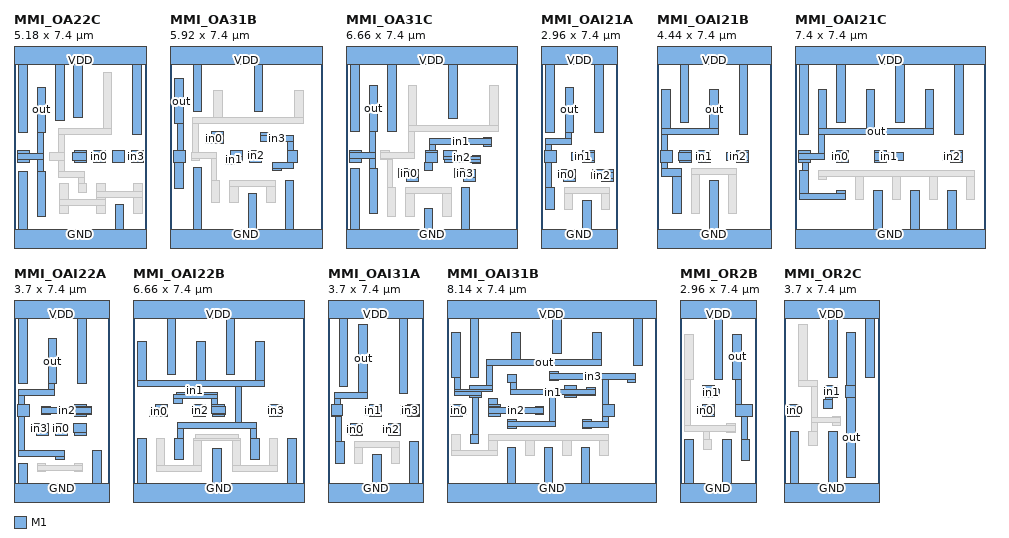
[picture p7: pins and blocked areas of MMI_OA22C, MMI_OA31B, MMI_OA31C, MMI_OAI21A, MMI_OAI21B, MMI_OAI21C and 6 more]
MACRO MMI_OA22C
	CLASS CORE ;
	FOREIGN MMI_OA22C 0 0 ;
	SIZE 5.18 BY 7.4 ;
	SYMMETRY X Y ;
	SITE CORE1 ;
	PIN out
		DIRECTION output ;
		USE SIGNAL ;
		PORT
			LAYER M1 ;
			RECT 0.9 4.27 1.24 6.03 ;
			LAYER M1 ;
			RECT 0.145 3.445 0.595 3.555 ;
			LAYER M1 ;
			RECT 0.9 3.445 1.13 4.27 ;
			LAYER M1 ;
			RECT 0.145 3.215 1.13 3.445 ;
			LAYER M1 ;
			RECT 0.145 3.105 0.595 3.215 ;
			LAYER M1 ;
			RECT 0.9 2.745 1.13 3.215 ;
			LAYER M1 ;
			RECT 0.9 0.985 1.24 2.745 ;
		END
		AntennaDiffArea 1.8768 ;
	END out
	PIN in1
		DIRECTION input ;
		USE SIGNAL ;
		PORT
			LAYER M1 ;
			RECT 2.365 3.5 2.815 3.555 ;
			LAYER M1 ;
			RECT 2.26 3.16 2.815 3.5 ;
			LAYER M1 ;
			RECT 2.365 3.105 2.815 3.16 ;
		END
		AntennaGateArea 0.6696 ;
	END in1
	PIN GND
		DIRECTION inout ;
		USE GROUND ;
		PORT
			LAYER M1 ;
			RECT 0.18 0.5 0.52 2.745 ;
			LAYER M1 ;
			RECT 3.94 0.5 4.28 1.465 ;
			LAYER M1 ;
			RECT 0 -0.5 5.18 0.5 ;
		END
	END GND
	PIN in2
		DIRECTION input ;
		USE SIGNAL ;
		PORT
			LAYER M1 ;
			RECT 3.845 3.105 4.295 3.555 ;
		END
		AntennaGateArea 0.6696 ;
	END in2
	PIN VDD
		DIRECTION inout ;
		USE POWER ;
		PORT
			LAYER M1 ;
			RECT 0 6.9 5.18 7.9 ;
			LAYER M1 ;
			RECT 0.18 4.27 0.52 6.9 ;
			LAYER M1 ;
			RECT 1.62 4.75 1.96 6.9 ;
			LAYER M1 ;
			RECT 2.32 4.855 2.66 6.9 ;
			LAYER M1 ;
			RECT 4.62 4.205 4.96 6.9 ;
		END
	END VDD
	PIN in3
		DIRECTION input ;
		USE SIGNAL ;
		PORT
			LAYER M1 ;
			RECT 4.585 3.105 5.035 3.555 ;
		END
		AntennaGateArea 0.6696 ;
	END in3
	PIN in0
		DIRECTION input ;
		USE SIGNAL ;
		PORT
			LAYER M1 ;
			RECT 3.105 3.5 3.555 3.555 ;
			LAYER M1 ;
			RECT 3.055 3.16 3.555 3.5 ;
			LAYER M1 ;
			RECT 3.105 3.105 3.555 3.16 ;
		END
		AntennaGateArea 0.6696 ;
	END in0
	OBS
		LAYER M1 ;
		RECT 3.47 4.435 3.81 6.605 ;
		LAYER M1 ;
		RECT 1.75 4.205 3.81 4.435 ;
		LAYER M1 ;
		RECT 1.75 3.505 1.98 4.205 ;
		LAYER M1 ;
		RECT 1.38 3.165 1.98 3.505 ;
		LAYER M1 ;
		RECT 1.75 2.755 1.98 3.165 ;
		LAYER M1 ;
		RECT 1.75 2.525 2.73 2.755 ;
		LAYER M1 ;
		RECT 2.5 2.285 2.73 2.525 ;
		LAYER M1 ;
		RECT 1.78 1.64 2.12 2.285 ;
		LAYER M1 ;
		RECT 2.5 1.945 2.84 2.285 ;
		LAYER M1 ;
		RECT 3.22 1.96 3.56 2.285 ;
		LAYER M1 ;
		RECT 4.66 1.96 5 2.285 ;
		LAYER M1 ;
		RECT 3.22 1.73 5 1.96 ;
		LAYER M1 ;
		RECT 3.22 1.64 3.56 1.73 ;
		LAYER M1 ;
		RECT 1.78 1.41 3.56 1.64 ;
		LAYER M1 ;
		RECT 1.78 1.125 2.12 1.41 ;
		LAYER M1 ;
		RECT 3.22 1.125 3.56 1.41 ;
		LAYER M1 ;
		RECT 4.66 1.125 5 1.73 ;
	END
END MMI_OA22C
MACRO MMI_OA31B
	CLASS CORE ;
	FOREIGN MMI_OA31B 0 0 ;
	SIZE 5.92 BY 7.4 ;
	SYMMETRY X Y ;
	SITE CORE1 ;
	PIN out
		DIRECTION output ;
		USE SIGNAL ;
		PORT
			LAYER M1 ;
			RECT 0.18 4.61 0.52 6.37 ;
			LAYER M1 ;
			RECT 0.29 3.555 0.52 4.61 ;
			LAYER M1 ;
			RECT 0.145 3.105 0.595 3.555 ;
			LAYER M1 ;
			RECT 0.18 2.08 0.52 3.105 ;
		END
		AntennaDiffArea 1.3248 ;
	END out
	PIN in1
		DIRECTION input ;
		USE SIGNAL ;
		PORT
			LAYER M1 ;
			RECT 2.365 3.34 2.815 3.555 ;
			LAYER M1 ;
			RECT 2.18 3.105 2.815 3.34 ;
			LAYER M1 ;
			RECT 2.18 3 2.52 3.105 ;
		END
		AntennaGateArea 0.6624 ;
	END in1
	PIN GND
		DIRECTION inout ;
		USE GROUND ;
		PORT
			LAYER M1 ;
			RECT 0.9 0.5 1.24 2.92 ;
			LAYER M1 ;
			RECT 3.04 0.5 3.38 1.885 ;
			LAYER M1 ;
			RECT 4.48 0.5 4.82 2.385 ;
			LAYER M1 ;
			RECT 0 -0.5 5.92 0.5 ;
		END
	END GND
	PIN in2
		DIRECTION input ;
		USE SIGNAL ;
		PORT
			LAYER M1 ;
			RECT 3.105 3.55 3.555 3.555 ;
			LAYER M1 ;
			RECT 3.105 3.21 3.62 3.55 ;
			LAYER M1 ;
			RECT 3.105 3.105 3.555 3.21 ;
		END
		AntennaGateArea 0.6624 ;
	END in2
	PIN VDD
		DIRECTION inout ;
		USE POWER ;
		PORT
			LAYER M1 ;
			RECT 0 6.9 5.92 7.9 ;
			LAYER M1 ;
			RECT 0.9 5.09 1.24 6.9 ;
			LAYER M1 ;
			RECT 3.28 5.1 3.62 6.9 ;
		END
	END VDD
	PIN in3
		DIRECTION input ;
		USE SIGNAL ;
		PORT
			LAYER M1 ;
			RECT 3.52 4.145 3.86 4.255 ;
			LAYER M1 ;
			RECT 3.52 3.915 4.815 4.145 ;
			LAYER M1 ;
			RECT 4.585 3.555 4.815 3.915 ;
			LAYER M1 ;
			RECT 4.585 3.11 4.975 3.555 ;
			LAYER M1 ;
			RECT 4 3.105 4.975 3.11 ;
			LAYER M1 ;
			RECT 4 2.88 4.815 3.105 ;
			LAYER M1 ;
			RECT 4 2.77 4.34 2.88 ;
		END
		AntennaGateArea 0.6624 ;
	END in3
	PIN in0
		DIRECTION input ;
		USE SIGNAL ;
		PORT
			LAYER M1 ;
			RECT 1.625 4.19 2.075 4.295 ;
			LAYER M1 ;
			RECT 1.375 3.85 2.075 4.19 ;
			LAYER M1 ;
			RECT 1.625 3.845 2.075 3.85 ;
		END
		AntennaGateArea 0.3312 ;
	END in0
	OBS
		LAYER M1 ;
		RECT 1.7 4.84 2.04 5.91 ;
		LAYER M1 ;
		RECT 4.86 4.84 5.2 5.91 ;
		LAYER M1 ;
		RECT 0.865 4.61 5.2 4.84 ;
		LAYER M1 ;
		RECT 0.865 3.5 1.095 4.61 ;
		LAYER M1 ;
		RECT 0.825 3.495 1.165 3.5 ;
		LAYER M1 ;
		RECT 0.825 3.265 1.83 3.495 ;
		LAYER M1 ;
		RECT 0.825 3.16 1.165 3.265 ;
		LAYER M1 ;
		RECT 1.6 2.385 1.83 3.265 ;
		LAYER M1 ;
		RECT 1.6 1.545 1.94 2.385 ;
		LAYER M1 ;
		RECT 2.32 2.155 4.1 2.385 ;
		LAYER M1 ;
		RECT 2.32 1.545 2.66 2.155 ;
		LAYER M1 ;
		RECT 3.76 1.545 4.1 2.155 ;
	END
END MMI_OA31B
MACRO MMI_OA31C
	CLASS CORE ;
	FOREIGN MMI_OA31C 0 0 ;
	SIZE 6.66 BY 7.4 ;
	SYMMETRY X Y ;
	SITE CORE1 ;
	PIN out
		DIRECTION output ;
		USE SIGNAL ;
		PORT
			LAYER M1 ;
			RECT 0.9 4.32 1.24 6.08 ;
			LAYER M1 ;
			RECT 0.145 3.495 0.595 3.555 ;
			LAYER M1 ;
			RECT 0.9 3.495 1.13 4.32 ;
			LAYER M1 ;
			RECT 0.145 3.265 1.13 3.495 ;
			LAYER M1 ;
			RECT 0.145 3.105 0.595 3.265 ;
			LAYER M1 ;
			RECT 0.9 2.86 1.13 3.265 ;
			LAYER M1 ;
			RECT 0.9 1.1 1.24 2.86 ;
		END
		AntennaDiffArea 1.8768 ;
	END out
	PIN in1
		DIRECTION input ;
		USE SIGNAL ;
		PORT
			LAYER M1 ;
			RECT 5.34 4.015 5.68 4.065 ;
			LAYER M1 ;
			RECT 3.245 3.785 5.68 4.015 ;
			LAYER M1 ;
			RECT 3.245 3.555 3.475 3.785 ;
			LAYER M1 ;
			RECT 5.34 3.725 5.68 3.785 ;
			LAYER M1 ;
			RECT 3.105 3.495 3.555 3.555 ;
			LAYER M1 ;
			RECT 3.1 3.115 3.555 3.495 ;
			LAYER M1 ;
			RECT 3.045 3.105 3.555 3.115 ;
			LAYER M1 ;
			RECT 3.045 2.775 3.385 3.105 ;
		END
		AntennaGateArea 0.8928 ;
	END in1
	PIN GND
		DIRECTION inout ;
		USE GROUND ;
		PORT
			LAYER M1 ;
			RECT 0.18 0.5 0.52 2.86 ;
			LAYER M1 ;
			RECT 3.04 0.5 3.38 1.315 ;
			LAYER M1 ;
			RECT 4.48 0.5 4.82 2.135 ;
			LAYER M1 ;
			RECT 0 -0.5 6.66 0.5 ;
		END
	END GND
	PIN in2
		DIRECTION input ;
		USE SIGNAL ;
		PORT
			LAYER M1 ;
			RECT 3.845 3.55 4.295 3.555 ;
			LAYER M1 ;
			RECT 3.785 3.335 4.295 3.55 ;
			LAYER M1 ;
			RECT 4.91 3.335 5.25 3.385 ;
			LAYER M1 ;
			RECT 3.785 3.21 5.25 3.335 ;
			LAYER M1 ;
			RECT 3.845 3.105 5.25 3.21 ;
			LAYER M1 ;
			RECT 4.91 3.045 5.25 3.105 ;
		END
		AntennaGateArea 0.8928 ;
	END in2
	PIN VDD
		DIRECTION inout ;
		USE POWER ;
		PORT
			LAYER M1 ;
			RECT 0 6.9 6.66 7.9 ;
			LAYER M1 ;
			RECT 0.18 4.32 0.52 6.9 ;
			LAYER M1 ;
			RECT 1.62 4.32 1.96 6.9 ;
			LAYER M1 ;
			RECT 4 4.8 4.34 6.9 ;
		END
	END VDD
	PIN in3
		DIRECTION input ;
		USE SIGNAL ;
		PORT
			LAYER M1 ;
			RECT 4.24 2.815 4.58 2.86 ;
			LAYER M1 ;
			RECT 4.24 2.52 5.035 2.815 ;
			LAYER M1 ;
			RECT 4.585 2.365 5.035 2.52 ;
		END
		AntennaGateArea 0.8928 ;
	END in3
	PIN in0
		DIRECTION input ;
		USE SIGNAL ;
		PORT
			LAYER M1 ;
			RECT 2.06 2.815 2.4 2.86 ;
			LAYER M1 ;
			RECT 2.06 2.52 2.815 2.815 ;
			LAYER M1 ;
			RECT 2.365 2.365 2.815 2.52 ;
		END
		AntennaGateArea 0.4464 ;
	END in0
	OBS
		LAYER M1 ;
		RECT 2.42 4.53 2.76 6.08 ;
		LAYER M1 ;
		RECT 5.58 4.53 5.92 6.08 ;
		LAYER M1 ;
		RECT 2.42 4.3 5.92 4.53 ;
		LAYER M1 ;
		RECT 1.36 3.495 1.7 3.55 ;
		LAYER M1 ;
		RECT 2.42 3.495 2.65 4.3 ;
		LAYER M1 ;
		RECT 1.36 3.265 2.65 3.495 ;
		LAYER M1 ;
		RECT 1.36 3.21 1.83 3.265 ;
		LAYER M1 ;
		RECT 1.6 2.135 1.83 3.21 ;
		LAYER M1 ;
		RECT 1.6 0.975 1.94 2.135 ;
		LAYER M1 ;
		RECT 2.32 1.905 4.1 2.135 ;
		LAYER M1 ;
		RECT 2.32 0.975 2.66 1.905 ;
		LAYER M1 ;
		RECT 3.76 0.975 4.1 1.905 ;
	END
END MMI_OA31C
MACRO MMI_OAI21A
	CLASS CORE ;
	FOREIGN MMI_OAI21A 0 0 ;
	SIZE 2.96 BY 7.4 ;
	SYMMETRY X Y ;
	SITE CORE1 ;
	PIN out
		DIRECTION output ;
		USE SIGNAL ;
		PORT
			LAYER M1 ;
			RECT 0.94 4.275 1.28 6.035 ;
			LAYER M1 ;
			RECT 0.94 4.02 1.17 4.275 ;
			LAYER M1 ;
			RECT 0.18 3.79 1.17 4.02 ;
			LAYER M1 ;
			RECT 0.18 3.555 0.41 3.79 ;
			LAYER M1 ;
			RECT 0.145 3.105 0.595 3.555 ;
			LAYER M1 ;
			RECT 0.18 2.11 0.41 3.105 ;
			LAYER M1 ;
			RECT 0.18 1.27 0.52 2.11 ;
		END
		AntennaDiffArea 1.4168 ;
	END out
	PIN in1
		DIRECTION input ;
		USE SIGNAL ;
		PORT
			LAYER M1 ;
			RECT 1.625 3.5 2.075 3.555 ;
			LAYER M1 ;
			RECT 1.175 3.16 2.075 3.5 ;
			LAYER M1 ;
			RECT 1.625 3.105 2.075 3.16 ;
		END
		AntennaGateArea 0.4968 ;
	END in1
	PIN GND
		DIRECTION inout ;
		USE GROUND ;
		PORT
			LAYER M1 ;
			RECT 1.62 0.5 1.96 1.61 ;
			LAYER M1 ;
			RECT 0 -0.5 2.96 0.5 ;
		END
	END GND
	PIN in2
		DIRECTION input ;
		USE SIGNAL ;
		PORT
			LAYER M1 ;
			RECT 2.365 2.81 2.815 2.815 ;
			LAYER M1 ;
			RECT 2.025 2.695 2.815 2.81 ;
			LAYER M1 ;
			RECT 1.975 2.465 2.815 2.695 ;
			LAYER M1 ;
			RECT 2.365 2.365 2.815 2.465 ;
		END
		AntennaGateArea 0.4968 ;
	END in2
	PIN VDD
		DIRECTION inout ;
		USE POWER ;
		PORT
			LAYER M1 ;
			RECT 0 6.9 2.96 7.9 ;
			LAYER M1 ;
			RECT 0.18 4.275 0.52 6.9 ;
			LAYER M1 ;
			RECT 2.09 4.275 2.43 6.9 ;
		END
	END VDD
	PIN in0
		DIRECTION input ;
		USE SIGNAL ;
		PORT
			LAYER M1 ;
			RECT 0.885 2.81 1.335 2.815 ;
			LAYER M1 ;
			RECT 0.64 2.47 1.335 2.81 ;
			LAYER M1 ;
			RECT 0.885 2.365 1.335 2.47 ;
		END
		AntennaGateArea 0.3312 ;
	END in0
	OBS
		LAYER M1 ;
		RECT 0.9 1.88 2.68 2.11 ;
		LAYER M1 ;
		RECT 0.9 1.27 1.24 1.88 ;
		LAYER M1 ;
		RECT 2.34 1.27 2.68 1.88 ;
	END
END MMI_OAI21A
MACRO MMI_OAI21B
	CLASS CORE ;
	FOREIGN MMI_OAI21B 0 0 ;
	SIZE 4.44 BY 7.4 ;
	SYMMETRY X Y ;
	SITE CORE1 ;
	PIN out
		DIRECTION output ;
		USE SIGNAL ;
		PORT
			LAYER M1 ;
			RECT 0.18 4.41 0.52 5.94 ;
			LAYER M1 ;
			RECT 2.05 4.41 2.39 5.94 ;
			LAYER M1 ;
			RECT 0.18 4.18 2.39 4.41 ;
			LAYER M1 ;
			RECT 0.18 3.555 0.41 4.18 ;
			LAYER M1 ;
			RECT 0.145 3.105 0.595 3.555 ;
			LAYER M1 ;
			RECT 0.18 2.865 0.41 3.105 ;
			LAYER M1 ;
			RECT 0.18 2.545 0.95 2.865 ;
			LAYER M1 ;
			RECT 0.61 1.105 0.95 2.545 ;
		END
		AntennaDiffArea 2.76 ;
	END out
	PIN in1
		DIRECTION input ;
		USE SIGNAL ;
		PORT
			LAYER M1 ;
			RECT 1.625 3.5 2.075 3.555 ;
			LAYER M1 ;
			RECT 1.57 3.16 2.075 3.5 ;
			LAYER M1 ;
			RECT 1.625 3.105 2.075 3.16 ;
		END
		AntennaGateArea 0.9936 ;
	END in1
	PIN GND
		DIRECTION inout ;
		USE GROUND ;
		PORT
			LAYER M1 ;
			RECT 2.05 0.505 2.39 2.385 ;
			LAYER M1 ;
			RECT 2.05 0.5 2.82 0.505 ;
			LAYER M1 ;
			RECT 0 -0.5 4.44 0.5 ;
		END
	END GND
	PIN in2
		DIRECTION input ;
		USE SIGNAL ;
		PORT
			LAYER M1 ;
			RECT 3.105 3.5 3.555 3.555 ;
			LAYER M1 ;
			RECT 2.72 3.16 3.555 3.5 ;
			LAYER M1 ;
			RECT 3.105 3.105 3.555 3.16 ;
		END
		AntennaGateArea 0.9936 ;
	END in2
	PIN VDD
		DIRECTION inout ;
		USE POWER ;
		PORT
			LAYER M1 ;
			RECT 0 6.9 4.44 7.9 ;
			LAYER M1 ;
			RECT 0.9 4.66 1.24 6.9 ;
			LAYER M1 ;
			RECT 3.2 4.18 3.54 6.9 ;
		END
	END VDD
	PIN in0
		DIRECTION input ;
		USE SIGNAL ;
		PORT
			LAYER M1 ;
			RECT 0.885 3.5 1.335 3.555 ;
			LAYER M1 ;
			RECT 0.825 3.16 1.335 3.5 ;
			LAYER M1 ;
			RECT 0.885 3.105 1.335 3.16 ;
		END
		AntennaGateArea 0.6624 ;
	END in0
	OBS
		LAYER M1 ;
		RECT 1.33 2.635 3.11 2.865 ;
		LAYER M1 ;
		RECT 1.33 1.105 1.67 2.635 ;
		LAYER M1 ;
		RECT 2.77 1.105 3.11 2.635 ;
	END
END MMI_OAI21B
MACRO MMI_OAI21C
	CLASS CORE ;
	FOREIGN MMI_OAI21C 0 0 ;
	SIZE 7.4 BY 7.4 ;
	SYMMETRY X Y ;
	SITE CORE1 ;
	PIN out
		DIRECTION output ;
		USE SIGNAL ;
		PORT
			LAYER M1 ;
			RECT 0.9 4.415 1.24 5.945 ;
			LAYER M1 ;
			RECT 2.77 4.415 3.11 5.945 ;
			LAYER M1 ;
			RECT 5.07 4.415 5.41 5.945 ;
			LAYER M1 ;
			RECT 0.9 4.185 5.41 4.415 ;
			LAYER M1 ;
			RECT 0.145 3.445 0.595 3.555 ;
			LAYER M1 ;
			RECT 0.9 3.445 1.13 4.185 ;
			LAYER M1 ;
			RECT 0.145 3.215 1.13 3.445 ;
			LAYER M1 ;
			RECT 0.145 3.105 0.595 3.215 ;
			LAYER M1 ;
			RECT 0.29 2.795 0.52 3.105 ;
			LAYER M1 ;
			RECT 0.18 1.88 0.52 2.795 ;
			LAYER M1 ;
			RECT 1.62 1.88 1.96 1.99 ;
			LAYER M1 ;
			RECT 0.18 1.65 1.96 1.88 ;
		END
		AntennaDiffArea 4.2303 ;
	END out
	PIN in1
		DIRECTION input ;
		USE SIGNAL ;
		PORT
			LAYER M1 ;
			RECT 3.105 3.495 3.555 3.555 ;
			LAYER M1 ;
			RECT 3.105 3.155 4.24 3.495 ;
			LAYER M1 ;
			RECT 3.105 3.105 3.555 3.155 ;
		END
		AntennaGateArea 1.9863 ;
	END in1
	PIN GND
		DIRECTION inout ;
		USE GROUND ;
		PORT
			LAYER M1 ;
			RECT 3.06 0.5 3.4 1.99 ;
			LAYER M1 ;
			RECT 4.5 0.5 4.84 1.99 ;
			LAYER M1 ;
			RECT 5.94 0.5 6.28 1.99 ;
			LAYER M1 ;
			RECT 0 -0.5 7.4 0.5 ;
		END
	END GND
	PIN in2
		DIRECTION input ;
		USE SIGNAL ;
		PORT
			LAYER M1 ;
			RECT 6.065 3.495 6.515 3.555 ;
			LAYER M1 ;
			RECT 5.74 3.155 6.515 3.495 ;
			LAYER M1 ;
			RECT 6.065 3.105 6.515 3.155 ;
		END
		AntennaGateArea 1.9863 ;
	END in2
	PIN VDD
		DIRECTION inout ;
		USE POWER ;
		PORT
			LAYER M1 ;
			RECT 0 6.9 7.4 7.9 ;
			LAYER M1 ;
			RECT 0.18 4.185 0.52 6.9 ;
			LAYER M1 ;
			RECT 1.62 4.665 1.96 6.9 ;
			LAYER M1 ;
			RECT 3.92 4.665 4.26 6.9 ;
			LAYER M1 ;
			RECT 6.22 4.185 6.56 6.9 ;
		END
	END VDD
	PIN in0
		DIRECTION input ;
		USE SIGNAL ;
		PORT
			LAYER M1 ;
			RECT 1.625 3.495 2.075 3.555 ;
			LAYER M1 ;
			RECT 1.43 3.155 2.075 3.495 ;
			LAYER M1 ;
			RECT 1.625 3.105 2.075 3.155 ;
		END
		AntennaGateArea 1.3239 ;
	END in0
	OBS
		LAYER M1 ;
		RECT 0.9 2.565 7 2.795 ;
		LAYER M1 ;
		RECT 0.9 2.45 1.24 2.565 ;
		LAYER M1 ;
		RECT 2.34 1.65 2.68 2.565 ;
		LAYER M1 ;
		RECT 3.78 1.65 4.12 2.565 ;
		LAYER M1 ;
		RECT 5.22 1.65 5.56 2.565 ;
		LAYER M1 ;
		RECT 6.66 1.65 7 2.565 ;
	END
END MMI_OAI21C
MACRO MMI_OAI22A
	CLASS CORE ;
	FOREIGN MMI_OAI22A 0 0 ;
	SIZE 3.7 BY 7.4 ;
	SYMMETRY X Y ;
	SITE CORE1 ;
	PIN out
		DIRECTION output ;
		USE SIGNAL ;
		PORT
			LAYER M1 ;
			RECT 1.33 4.375 1.67 6.135 ;
			LAYER M1 ;
			RECT 1.33 4.135 1.56 4.375 ;
			LAYER M1 ;
			RECT 0.18 3.905 1.56 4.135 ;
			LAYER M1 ;
			RECT 0.18 3.555 0.41 3.905 ;
			LAYER M1 ;
			RECT 0.145 3.105 0.595 3.555 ;
			LAYER M1 ;
			RECT 0.18 1.775 0.41 3.105 ;
			LAYER M1 ;
			RECT 0.18 1.545 1.96 1.775 ;
			LAYER M1 ;
			RECT 1.62 1.435 1.96 1.545 ;
		END
		AntennaDiffArea 1.4904 ;
	END out
	PIN in1
		DIRECTION input ;
		USE SIGNAL ;
		PORT
			LAYER M1 ;
			RECT 2.365 2.81 2.815 2.815 ;
			LAYER M1 ;
			RECT 2.305 2.47 2.815 2.81 ;
			LAYER M1 ;
			RECT 2.365 2.365 2.815 2.47 ;
		END
		AntennaGateArea 0.4968 ;
	END in1
	PIN GND
		DIRECTION inout ;
		USE GROUND ;
		PORT
			LAYER M1 ;
			RECT 0.18 0.5 0.52 1.275 ;
			LAYER M1 ;
			RECT 3.06 0.5 3.4 1.775 ;
			LAYER M1 ;
			RECT 0 -0.5 3.7 0.5 ;
		END
	END GND
	PIN in2
		DIRECTION input ;
		USE SIGNAL ;
		PORT
			LAYER M1 ;
			RECT 2.365 3.5 2.815 3.555 ;
			LAYER M1 ;
			RECT 1.09 3.445 1.43 3.5 ;
			LAYER M1 ;
			RECT 2.365 3.445 3.01 3.5 ;
			LAYER M1 ;
			RECT 1.09 3.215 3.01 3.445 ;
			LAYER M1 ;
			RECT 1.09 3.16 1.43 3.215 ;
			LAYER M1 ;
			RECT 2.365 3.16 3.01 3.215 ;
			LAYER M1 ;
			RECT 2.365 3.105 2.815 3.16 ;
		END
		AntennaGateArea 0.4968 ;
	END in2
	PIN VDD
		DIRECTION inout ;
		USE POWER ;
		PORT
			LAYER M1 ;
			RECT 0 6.9 3.7 7.9 ;
			LAYER M1 ;
			RECT 0.18 4.375 0.52 6.9 ;
			LAYER M1 ;
			RECT 2.48 4.375 2.82 6.9 ;
		END
	END VDD
	PIN in3
		DIRECTION input ;
		USE SIGNAL ;
		PORT
			LAYER M1 ;
			RECT 0.885 2.81 1.335 2.815 ;
			LAYER M1 ;
			RECT 0.64 2.47 1.335 2.81 ;
			LAYER M1 ;
			RECT 0.885 2.365 1.335 2.47 ;
		END
		AntennaGateArea 0.4968 ;
	END in3
	PIN in0
		DIRECTION input ;
		USE SIGNAL ;
		PORT
			LAYER M1 ;
			RECT 1.625 2.81 2.075 2.815 ;
			LAYER M1 ;
			RECT 1.57 2.47 2.075 2.81 ;
			LAYER M1 ;
			RECT 1.625 2.365 2.075 2.47 ;
		END
		AntennaGateArea 0.4968 ;
	END in0
	OBS
		LAYER M1 ;
		RECT 0.9 1.205 1.24 1.275 ;
		LAYER M1 ;
		RECT 2.34 1.205 2.68 1.275 ;
		LAYER M1 ;
		RECT 0.9 0.975 2.68 1.205 ;
		LAYER M1 ;
		RECT 0.9 0.935 1.24 0.975 ;
		LAYER M1 ;
		RECT 2.34 0.935 2.68 0.975 ;
	END
END MMI_OAI22A
MACRO MMI_OAI22B
	CLASS CORE ;
	FOREIGN MMI_OAI22B 0 0 ;
	SIZE 6.66 BY 7.4 ;
	SYMMETRY X Y ;
	SITE CORE1 ;
	PIN out
		DIRECTION output ;
		USE SIGNAL ;
		PORT
			LAYER M1 ;
			RECT 0.18 4.485 0.52 6.025 ;
			LAYER M1 ;
			RECT 2.48 4.485 2.82 6.025 ;
			LAYER M1 ;
			RECT 4.78 4.485 5.12 6.025 ;
			LAYER M1 ;
			RECT 0.18 4.255 5.12 4.485 ;
			LAYER M1 ;
			RECT 3.99 2.875 4.22 4.255 ;
			LAYER M1 ;
			RECT 1.73 2.645 4.81 2.875 ;
			LAYER M1 ;
			RECT 1.73 2.245 1.96 2.645 ;
			LAYER M1 ;
			RECT 1.62 1.405 1.96 2.245 ;
			LAYER M1 ;
			RECT 4.58 2.245 4.81 2.645 ;
			LAYER M1 ;
			RECT 4.58 1.405 4.92 2.245 ;
		END
		AntennaDiffArea 3.7536 ;
	END out
	PIN in1
		DIRECTION input ;
		USE SIGNAL ;
		PORT
			LAYER M1 ;
			RECT 1.675 3.94 3.295 4.015 ;
			LAYER M1 ;
			RECT 1.57 3.785 3.295 3.94 ;
			LAYER M1 ;
			RECT 1.57 3.6 1.91 3.785 ;
			LAYER M1 ;
			RECT 3.065 3.555 3.295 3.785 ;
			LAYER M1 ;
			RECT 3.065 3.5 3.555 3.555 ;
			LAYER M1 ;
			RECT 3.065 3.215 3.59 3.5 ;
			LAYER M1 ;
			RECT 3.105 3.16 3.59 3.215 ;
			LAYER M1 ;
			RECT 3.105 3.105 3.555 3.16 ;
		END
		AntennaGateArea 0.9936 ;
	END in1
	PIN GND
		DIRECTION inout ;
		USE GROUND ;
		PORT
			LAYER M1 ;
			RECT 0.18 0.5 0.52 2.245 ;
			LAYER M1 ;
			RECT 3.1 0.5 3.44 1.845 ;
			LAYER M1 ;
			RECT 6.02 0.5 6.36 2.245 ;
			LAYER M1 ;
			RECT 0 -0.5 6.66 0.5 ;
		END
	END GND
	PIN in2
		DIRECTION input ;
		USE SIGNAL ;
		PORT
			LAYER M1 ;
			RECT 2.365 3.105 2.815 3.555 ;
		END
		AntennaGateArea 0.9936 ;
	END in2
	PIN VDD
		DIRECTION inout ;
		USE POWER ;
		PORT
			LAYER M1 ;
			RECT 0 6.9 6.66 7.9 ;
			LAYER M1 ;
			RECT 1.33 4.745 1.67 6.9 ;
			LAYER M1 ;
			RECT 3.63 4.745 3.97 6.9 ;
		END
	END VDD
	PIN in3
		DIRECTION input ;
		USE SIGNAL ;
		PORT
			LAYER M1 ;
			RECT 5.325 3.105 5.775 3.555 ;
		END
		AntennaGateArea 0.9936 ;
	END in3
	PIN in0
		DIRECTION input ;
		USE SIGNAL ;
		PORT
			LAYER M1 ;
			RECT 0.885 3.445 1.335 3.555 ;
			LAYER M1 ;
			RECT 0.66 3.105 1.335 3.445 ;
		END
		AntennaGateArea 0.9936 ;
	END in0
	OBS
		LAYER M1 ;
		RECT 2.45 2.245 4.09 2.405 ;
		LAYER M1 ;
		RECT 0.9 1.175 1.24 2.245 ;
		LAYER M1 ;
		RECT 2.34 2.175 4.2 2.245 ;
		LAYER M1 ;
		RECT 2.34 1.175 2.68 2.175 ;
		LAYER M1 ;
		RECT 0.9 0.945 2.68 1.175 ;
		LAYER M1 ;
		RECT 3.86 1.175 4.2 2.175 ;
		LAYER M1 ;
		RECT 5.3 1.175 5.64 2.245 ;
		LAYER M1 ;
		RECT 3.86 0.945 5.64 1.175 ;
	END
END MMI_OAI22B
MACRO MMI_OAI31A
	CLASS CORE ;
	FOREIGN MMI_OAI31A 0 0 ;
	SIZE 3.7 BY 7.4 ;
	SYMMETRY X Y ;
	SITE CORE1 ;
	PIN out
		DIRECTION output ;
		USE SIGNAL ;
		PORT
			LAYER M1 ;
			RECT 1.195 4.04 1.535 6.67 ;
			LAYER M1 ;
			RECT 0.255 3.81 1.535 4.04 ;
			LAYER M1 ;
			RECT 0.255 3.555 0.485 3.81 ;
			LAYER M1 ;
			RECT 0.145 3.145 0.55 3.555 ;
			LAYER M1 ;
			RECT 0.145 3.105 0.53 3.145 ;
			LAYER M1 ;
			RECT 0.3 2.12 0.53 3.105 ;
			LAYER M1 ;
			RECT 0.3 1.28 0.64 2.12 ;
		END
		AntennaDiffArea 1.8584 ;
	END out
	PIN in1
		DIRECTION input ;
		USE SIGNAL ;
		PORT
			LAYER M1 ;
			RECT 1.625 3.485 2.075 3.555 ;
			LAYER M1 ;
			RECT 1.435 3.145 2.075 3.485 ;
			LAYER M1 ;
			RECT 1.625 3.105 2.075 3.145 ;
		END
		AntennaGateArea 0.6624 ;
	END in1
	PIN GND
		DIRECTION inout ;
		USE GROUND ;
		PORT
			LAYER M1 ;
			RECT 1.74 0.5 2.08 1.62 ;
			LAYER M1 ;
			RECT 3.18 0.5 3.52 2.12 ;
			LAYER M1 ;
			RECT 0 -0.5 3.7 0.5 ;
		END
	END GND
	PIN in2
		DIRECTION input ;
		USE SIGNAL ;
		PORT
			LAYER M1 ;
			RECT 2.365 2.755 2.815 2.815 ;
			LAYER M1 ;
			RECT 2.105 2.415 2.815 2.755 ;
			LAYER M1 ;
			RECT 2.365 2.365 2.815 2.415 ;
		END
		AntennaGateArea 0.6624 ;
	END in2
	PIN VDD
		DIRECTION inout ;
		USE POWER ;
		PORT
			LAYER M1 ;
			RECT 0 6.9 3.7 7.9 ;
			LAYER M1 ;
			RECT 0.435 4.275 0.775 6.9 ;
			LAYER M1 ;
			RECT 2.775 3.99 3.115 6.9 ;
		END
	END VDD
	PIN in3
		DIRECTION input ;
		USE SIGNAL ;
		PORT
			LAYER M1 ;
			RECT 3.105 3.51 3.555 3.555 ;
			LAYER M1 ;
			RECT 2.835 3.17 3.555 3.51 ;
			LAYER M1 ;
			RECT 3.07 3.12 3.555 3.17 ;
			LAYER M1 ;
			RECT 3.105 3.105 3.555 3.12 ;
		END
		AntennaGateArea 0.6624 ;
	END in3
	PIN in0
		DIRECTION input ;
		USE SIGNAL ;
		PORT
			LAYER M1 ;
			RECT 0.885 2.745 1.335 2.815 ;
			LAYER M1 ;
			RECT 0.765 2.405 1.335 2.745 ;
			LAYER M1 ;
			RECT 0.885 2.365 1.335 2.405 ;
		END
		AntennaGateArea 0.3312 ;
	END in0
	OBS
		LAYER M1 ;
		RECT 1.02 1.89 2.8 2.12 ;
		LAYER M1 ;
		RECT 1.02 1.28 1.36 1.89 ;
		LAYER M1 ;
		RECT 2.46 1.28 2.8 1.89 ;
	END
END MMI_OAI31A
MACRO MMI_OAI31B
	CLASS CORE ;
	FOREIGN MMI_OAI31B 0 0 ;
	SIZE 8.14 BY 7.4 ;
	SYMMETRY X Y ;
	SITE CORE1 ;
	PIN out
		DIRECTION output ;
		USE SIGNAL ;
		PORT
			LAYER M1 ;
			RECT 0.18 4.61 0.52 6.37 ;
			LAYER M1 ;
			RECT 2.52 5.3 2.86 6.37 ;
			LAYER M1 ;
			RECT 5.68 5.3 6.02 6.37 ;
			LAYER M1 ;
			RECT 0.29 4.135 0.52 4.61 ;
			LAYER M1 ;
			RECT 1.54 5.07 6.02 5.3 ;
			LAYER M1 ;
			RECT 1.54 4.295 1.77 5.07 ;
			LAYER M1 ;
			RECT 0.885 4.135 1.77 4.295 ;
			LAYER M1 ;
			RECT 0.29 4.065 1.77 4.135 ;
			LAYER M1 ;
			RECT 0.29 3.905 1.335 4.065 ;
			LAYER M1 ;
			RECT 0.885 3.845 1.335 3.905 ;
			LAYER M1 ;
			RECT 1.01 2.4 1.24 3.845 ;
			LAYER M1 ;
			RECT 0.9 2.06 1.24 2.4 ;
		END
		AntennaDiffArea 2.8704 ;
	END out
	PIN in1
		DIRECTION input ;
		USE SIGNAL ;
		PORT
			LAYER M1 ;
			RECT 2.37 4.41 2.71 4.75 ;
			LAYER M1 ;
			RECT 2.48 4.165 2.71 4.41 ;
			LAYER M1 ;
			RECT 4.585 4.165 5.035 4.295 ;
			LAYER M1 ;
			RECT 2.48 4.135 5.035 4.165 ;
			LAYER M1 ;
			RECT 5.44 4.135 5.78 4.245 ;
			LAYER M1 ;
			RECT 2.48 3.935 5.78 4.135 ;
			LAYER M1 ;
			RECT 2.37 2.92 2.71 2.975 ;
			LAYER M1 ;
			RECT 4 2.92 4.23 3.935 ;
			LAYER M1 ;
			RECT 4.585 3.905 5.78 3.935 ;
			LAYER M1 ;
			RECT 4.585 3.845 5.035 3.905 ;
			LAYER M1 ;
			RECT 2.37 2.69 4.23 2.92 ;
			LAYER M1 ;
			RECT 2.37 2.635 2.71 2.69 ;
		END
		AntennaGateArea 1.3248 ;
	END in1
	PIN GND
		DIRECTION inout ;
		USE GROUND ;
		PORT
			LAYER M1 ;
			RECT 2.34 0.5 2.68 1.9 ;
			LAYER M1 ;
			RECT 3.78 0.5 4.12 1.9 ;
			LAYER M1 ;
			RECT 5.22 0.5 5.56 1.9 ;
			LAYER M1 ;
			RECT 0 -0.5 8.14 0.5 ;
		END
	END GND
	PIN in2
		DIRECTION input ;
		USE SIGNAL ;
		PORT
			LAYER M1 ;
			RECT 1.61 3.555 1.95 3.81 ;
			LAYER M1 ;
			RECT 1.61 3.47 2.075 3.555 ;
			LAYER M1 ;
			RECT 1.625 3.445 2.075 3.47 ;
			LAYER M1 ;
			RECT 3.43 3.445 3.77 3.5 ;
			LAYER M1 ;
			RECT 1.625 3.215 3.77 3.445 ;
			LAYER M1 ;
			RECT 1.625 3.105 2.075 3.215 ;
			LAYER M1 ;
			RECT 3.43 3.16 3.77 3.215 ;
		END
		AntennaGateArea 1.3248 ;
	END in2
	PIN VDD
		DIRECTION inout ;
		USE POWER ;
		PORT
			LAYER M1 ;
			RECT 0 6.9 8.14 7.9 ;
			LAYER M1 ;
			RECT 0.9 4.61 1.24 6.9 ;
			LAYER M1 ;
			RECT 4.1 5.56 4.44 6.9 ;
			LAYER M1 ;
			RECT 7.26 5.07 7.6 6.9 ;
		END
	END VDD
	PIN in3
		DIRECTION input ;
		USE SIGNAL ;
		PORT
			LAYER M1 ;
			RECT 4 4.77 4.34 4.84 ;
			LAYER M1 ;
			RECT 4 4.54 7.36 4.77 ;
			LAYER M1 ;
			RECT 4 4.5 4.34 4.54 ;
			LAYER M1 ;
			RECT 6.065 3.555 6.295 4.54 ;
			LAYER M1 ;
			RECT 7.02 4.43 7.36 4.54 ;
			LAYER M1 ;
			RECT 6.065 3.105 6.515 3.555 ;
			LAYER M1 ;
			RECT 5.27 2.89 5.61 2.97 ;
			LAYER M1 ;
			RECT 6.065 2.89 6.295 3.105 ;
			LAYER M1 ;
			RECT 5.27 2.66 6.295 2.89 ;
			LAYER M1 ;
			RECT 5.27 2.63 5.61 2.66 ;
		END
		AntennaGateArea 1.3248 ;
	END in3
	PIN in0
		DIRECTION input ;
		USE SIGNAL ;
		PORT
			LAYER M1 ;
			RECT 0.145 3.5 0.595 3.555 ;
			LAYER M1 ;
			RECT 0.145 3.16 0.76 3.5 ;
			LAYER M1 ;
			RECT 0.145 3.105 0.595 3.16 ;
		END
		AntennaGateArea 0.6624 ;
	END in0
	OBS
		LAYER M1 ;
		RECT 0.18 1.79 0.52 2.4 ;
		LAYER M1 ;
		RECT 1.62 2.17 6.28 2.4 ;
		LAYER M1 ;
		RECT 1.62 1.79 1.96 2.17 ;
		LAYER M1 ;
		RECT 0.18 1.56 1.96 1.79 ;
		LAYER M1 ;
		RECT 3.06 1.56 3.4 2.17 ;
		LAYER M1 ;
		RECT 4.5 1.56 4.84 2.17 ;
		LAYER M1 ;
		RECT 5.94 1.56 6.28 2.17 ;
	END
END MMI_OAI31B
MACRO MMI_OR2B
	CLASS CORE ;
	FOREIGN MMI_OR2B 0 0 ;
	SIZE 2.96 BY 7.4 ;
	SYMMETRY X Y ;
	SITE CORE1 ;
	PIN out
		DIRECTION output ;
		USE SIGNAL ;
		PORT
			LAYER M1 ;
			RECT 2.05 4.545 2.39 6.305 ;
			LAYER M1 ;
			RECT 2.16 3.555 2.39 4.545 ;
			LAYER M1 ;
			RECT 2.16 3.105 2.815 3.555 ;
			LAYER M1 ;
			RECT 2.38 2.21 2.61 3.105 ;
			LAYER M1 ;
			RECT 2.38 1.37 2.72 2.21 ;
		END
		AntennaDiffArea 1.3248 ;
	END out
	PIN in1
		DIRECTION input ;
		USE SIGNAL ;
		PORT
			LAYER M1 ;
			RECT 0.885 4.19 1.335 4.295 ;
			LAYER M1 ;
			RECT 0.885 4.135 1.48 4.19 ;
			LAYER M1 ;
			RECT 0.885 3.905 1.545 4.135 ;
			LAYER M1 ;
			RECT 0.885 3.85 1.48 3.905 ;
			LAYER M1 ;
			RECT 0.885 3.845 1.335 3.85 ;
		END
		AntennaGateArea 0.414 ;
	END in1
	PIN GND
		DIRECTION inout ;
		USE GROUND ;
		PORT
			LAYER M1 ;
			RECT 0.18 0.5 0.52 2.21 ;
			LAYER M1 ;
			RECT 1.66 0.5 2 2.21 ;
			LAYER M1 ;
			RECT 0 -0.5 2.96 0.5 ;
		END
	END GND
	PIN VDD
		DIRECTION inout ;
		USE POWER ;
		PORT
			LAYER M1 ;
			RECT 0 6.9 2.96 7.9 ;
			LAYER M1 ;
			RECT 1.33 4.545 1.67 6.9 ;
		END
	END VDD
	PIN in0
		DIRECTION input ;
		USE SIGNAL ;
		PORT
			LAYER M1 ;
			RECT 0.885 3.5 1.335 3.555 ;
			LAYER M1 ;
			RECT 0.64 3.16 1.335 3.5 ;
			LAYER M1 ;
			RECT 0.885 3.105 1.335 3.16 ;
		END
		AntennaGateArea 0.414 ;
	END in0
	OBS
		LAYER M1 ;
		RECT 0.18 4.545 0.52 6.305 ;
		LAYER M1 ;
		RECT 0.18 2.755 0.41 4.545 ;
		LAYER M1 ;
		RECT 1.81 2.755 2.15 2.81 ;
		LAYER M1 ;
		RECT 0.18 2.525 2.15 2.755 ;
		LAYER M1 ;
		RECT 0.9 2.21 1.13 2.525 ;
		LAYER M1 ;
		RECT 1.81 2.47 2.15 2.525 ;
		LAYER M1 ;
		RECT 0.9 1.83 1.24 2.21 ;
	END
END MMI_OR2B
MACRO MMI_OR2C
	CLASS CORE ;
	FOREIGN MMI_OR2C 0 0 ;
	SIZE 3.7 BY 7.4 ;
	SYMMETRY X Y ;
	SITE CORE1 ;
	PIN out
		DIRECTION output ;
		USE SIGNAL ;
		PORT
			LAYER M1 ;
			RECT 2.45 4.295 2.79 6.37 ;
			LAYER M1 ;
			RECT 2.395 3.845 2.79 4.295 ;
			LAYER M1 ;
			RECT 2.45 0.74 2.79 3.845 ;
		END
		AntennaDiffArea 1.8768 ;
	END out
	PIN in1
		DIRECTION input ;
		USE SIGNAL ;
		PORT
			LAYER M1 ;
			RECT 1.625 3.845 2.075 4.295 ;
			LAYER M1 ;
			RECT 1.625 3.755 1.875 3.845 ;
			LAYER M1 ;
			RECT 1.535 3.415 1.875 3.755 ;
		END
		AntennaGateArea 0.558 ;
	END in1
	PIN GND
		DIRECTION inout ;
		USE GROUND ;
		PORT
			LAYER M1 ;
			RECT 0.24 0.5 0.58 2.5 ;
			LAYER M1 ;
			RECT 1.73 0.5 2.07 2.5 ;
			LAYER M1 ;
			RECT 0 -0.5 3.7 0.5 ;
		END
	END GND
	PIN VDD
		DIRECTION inout ;
		USE POWER ;
		PORT
			LAYER M1 ;
			RECT 0 6.9 3.7 7.9 ;
			LAYER M1 ;
			RECT 1.73 4.61 2.07 6.9 ;
			LAYER M1 ;
			RECT 3.17 4.61 3.51 6.9 ;
		END
	END VDD
	PIN in0
		DIRECTION input ;
		USE SIGNAL ;
		PORT
			LAYER M1 ;
			RECT 0.145 3.5 0.595 3.555 ;
			LAYER M1 ;
			RECT 0.145 3.16 0.665 3.5 ;
			LAYER M1 ;
			RECT 0.145 3.105 0.595 3.16 ;
		END
		AntennaGateArea 0.558 ;
	END in0
	OBS
		LAYER M1 ;
		RECT 0.57 4.5 0.91 6.67 ;
		LAYER M1 ;
		RECT 0.57 4.27 1.3 4.5 ;
		LAYER M1 ;
		RECT 1.07 3.075 1.3 4.27 ;
		LAYER M1 ;
		RECT 1.87 3.075 2.21 3.08 ;
		LAYER M1 ;
		RECT 1.07 2.845 2.21 3.075 ;
		LAYER M1 ;
		RECT 1.07 2.5 1.3 2.845 ;
		LAYER M1 ;
		RECT 1.87 2.74 2.21 2.845 ;
		LAYER M1 ;
		RECT 0.96 1.96 1.3 2.5 ;
	END
END MMI_OR2C
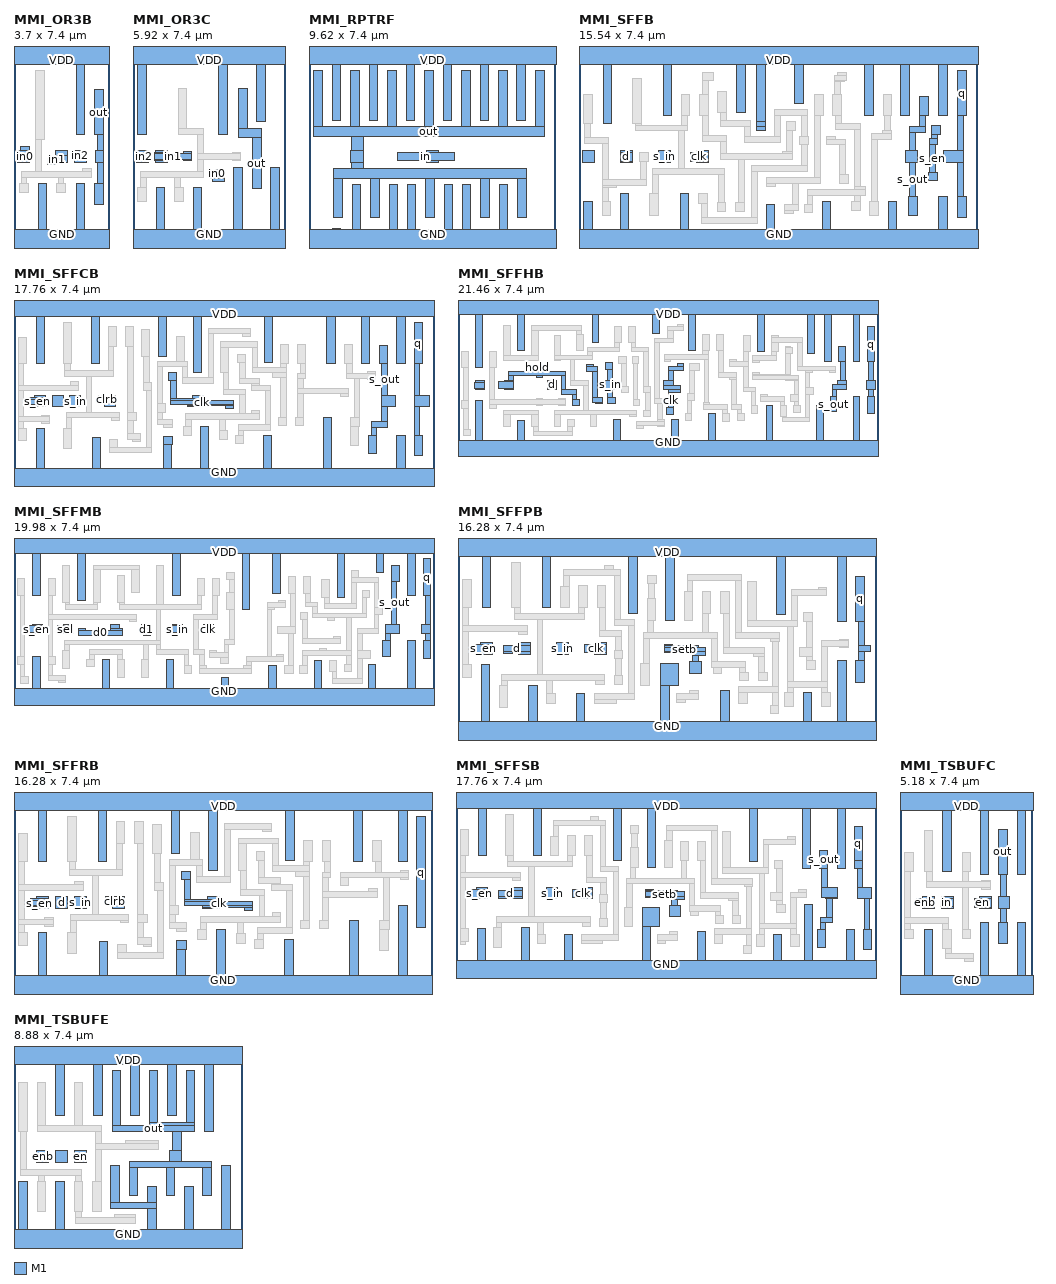
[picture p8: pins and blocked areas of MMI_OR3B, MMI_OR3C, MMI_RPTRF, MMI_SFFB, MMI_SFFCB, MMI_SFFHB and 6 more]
MACRO MMI_OR3B
	CLASS CORE ;
	FOREIGN MMI_OR3B 0 0 ;
	SIZE 3.7 BY 7.4 ;
	SYMMETRY X Y ;
	SITE CORE1 ;
	PIN out
		DIRECTION output ;
		USE SIGNAL ;
		PORT
			LAYER M1 ;
			RECT 3.14 4.18 3.48 5.94 ;
			LAYER M1 ;
			RECT 3.25 3.555 3.48 4.18 ;
			LAYER M1 ;
			RECT 3.165 3.1 3.48 3.555 ;
			LAYER M1 ;
			RECT 3.25 2.29 3.48 3.1 ;
			LAYER M1 ;
			RECT 3.14 1.45 3.48 2.29 ;
		END
		AntennaDiffArea 1.3248 ;
	END out
	PIN in1
		DIRECTION input ;
		USE SIGNAL ;
		PORT
			LAYER M1 ;
			RECT 1.625 3.36 2.075 3.555 ;
			LAYER M1 ;
			RECT 1.31 3.105 2.075 3.36 ;
			LAYER M1 ;
			RECT 1.31 3.02 1.65 3.105 ;
		END
		AntennaGateArea 0.5796 ;
	END in1
	PIN GND
		DIRECTION inout ;
		USE GROUND ;
		PORT
			LAYER M1 ;
			RECT 0.94 0.5 1.28 2.29 ;
			LAYER M1 ;
			RECT 2.42 0.5 2.76 2.29 ;
			LAYER M1 ;
			RECT 0 -0.5 3.7 0.5 ;
		END
	END GND
	PIN in2
		DIRECTION input ;
		USE SIGNAL ;
		PORT
			LAYER M1 ;
			RECT 2.305 3.215 2.815 3.555 ;
			LAYER M1 ;
			RECT 2.365 3.105 2.815 3.215 ;
		END
		AntennaGateArea 0.5796 ;
	END in2
	PIN VDD
		DIRECTION inout ;
		USE POWER ;
		PORT
			LAYER M1 ;
			RECT 0 6.9 3.7 7.9 ;
			LAYER M1 ;
			RECT 2.42 4.18 2.76 6.9 ;
		END
	END VDD
	PIN in0
		DIRECTION input ;
		USE SIGNAL ;
		PORT
			LAYER M1 ;
			RECT 0.255 3.555 0.595 3.73 ;
			LAYER M1 ;
			RECT 0.145 3.105 0.595 3.555 ;
		END
		AntennaGateArea 0.5796 ;
	END in0
	OBS
		LAYER M1 ;
		RECT 0.84 3.99 1.18 6.67 ;
		LAYER M1 ;
		RECT 0.84 2.755 1.07 3.99 ;
		LAYER M1 ;
		RECT 2.66 2.755 3 2.865 ;
		LAYER M1 ;
		RECT 0.275 2.525 3 2.755 ;
		LAYER M1 ;
		RECT 0.275 2.29 0.505 2.525 ;
		LAYER M1 ;
		RECT 1.715 2.29 1.945 2.525 ;
		LAYER M1 ;
		RECT 0.22 1.91 0.56 2.29 ;
		LAYER M1 ;
		RECT 1.66 1.91 2 2.29 ;
	END
END MMI_OR3B
MACRO MMI_OR3C
	CLASS CORE ;
	FOREIGN MMI_OR3C 0 0 ;
	SIZE 5.92 BY 7.4 ;
	SYMMETRY X Y ;
	SITE CORE1 ;
	PIN out
		DIRECTION output ;
		USE SIGNAL ;
		PORT
			LAYER M1 ;
			RECT 4.105 4.405 4.445 5.96 ;
			LAYER M1 ;
			RECT 4.105 4.065 4.99 4.405 ;
			LAYER M1 ;
			RECT 4.65 2.065 4.99 4.065 ;
		END
		AntennaDiffArea 1.4904 ;
	END out
	PIN in1
		DIRECTION input ;
		USE SIGNAL ;
		PORT
			LAYER M1 ;
			RECT 0.885 3.5 1.335 3.555 ;
			LAYER M1 ;
			RECT 0.85 3.445 1.335 3.5 ;
			LAYER M1 ;
			RECT 1.95 3.445 2.29 3.51 ;
			LAYER M1 ;
			RECT 0.85 3.215 2.29 3.445 ;
			LAYER M1 ;
			RECT 0.85 3.16 1.335 3.215 ;
			LAYER M1 ;
			RECT 1.95 3.17 2.29 3.215 ;
			LAYER M1 ;
			RECT 0.885 3.105 1.335 3.16 ;
		END
		AntennaGateArea 0.7812 ;
	END in1
	PIN GND
		DIRECTION inout ;
		USE GROUND ;
		PORT
			LAYER M1 ;
			RECT 0.9 0.5 1.24 2.125 ;
			LAYER M1 ;
			RECT 2.34 0.5 2.68 2.125 ;
			LAYER M1 ;
			RECT 3.93 0.5 4.27 2.905 ;
			LAYER M1 ;
			RECT 5.37 0.5 5.71 2.905 ;
			LAYER M1 ;
			RECT 0 -0.5 5.92 0.5 ;
		END
	END GND
	PIN in2
		DIRECTION input ;
		USE SIGNAL ;
		PORT
			LAYER M1 ;
			RECT 0.145 3.5 0.595 3.555 ;
			LAYER M1 ;
			RECT 0.12 3.16 0.595 3.5 ;
			LAYER M1 ;
			RECT 0.145 3.105 0.595 3.16 ;
		END
		AntennaGateArea 0.7812 ;
	END in2
	PIN VDD
		DIRECTION inout ;
		USE POWER ;
		PORT
			LAYER M1 ;
			RECT 4.825 7.9 5.165 7.92 ;
			LAYER M1 ;
			RECT 0 6.9 5.92 7.9 ;
			LAYER M1 ;
			RECT 0.18 4.18 0.52 6.9 ;
			LAYER M1 ;
			RECT 3.34 4.18 3.68 6.9 ;
			LAYER M1 ;
			RECT 4.825 4.68 5.165 6.9 ;
		END
	END VDD
	PIN in0
		DIRECTION input ;
		USE SIGNAL ;
		PORT
			LAYER M1 ;
			RECT 2.98 2.815 3.32 2.83 ;
			LAYER M1 ;
			RECT 2.98 2.49 3.555 2.815 ;
			LAYER M1 ;
			RECT 3.105 2.365 3.555 2.49 ;
		END
		AntennaGateArea 0.7812 ;
	END in0
	OBS
		LAYER M1 ;
		RECT 1.76 4.41 2.1 5.96 ;
		LAYER M1 ;
		RECT 1.76 4.18 2.75 4.41 ;
		LAYER M1 ;
		RECT 2.52 3.445 2.75 4.18 ;
		LAYER M1 ;
		RECT 3.865 3.445 4.205 3.5 ;
		LAYER M1 ;
		RECT 2.52 3.215 4.205 3.445 ;
		LAYER M1 ;
		RECT 2.52 2.755 2.75 3.215 ;
		LAYER M1 ;
		RECT 3.865 3.16 4.205 3.215 ;
		LAYER M1 ;
		RECT 0.29 2.525 2.75 2.755 ;
		LAYER M1 ;
		RECT 0.29 2.125 0.52 2.525 ;
		LAYER M1 ;
		RECT 1.62 2.125 1.85 2.525 ;
		LAYER M1 ;
		RECT 0.18 1.585 0.52 2.125 ;
		LAYER M1 ;
		RECT 1.62 1.585 1.96 2.125 ;
	END
END MMI_OR3C
MACRO MMI_RPTRF
	CLASS CORE ;
	FOREIGN MMI_RPTRF 0 0 ;
	SIZE 9.62 BY 7.4 ;
	SYMMETRY X Y ;
	SITE CORE1 ;
	PIN out
		DIRECTION output ;
		USE SIGNAL ;
		PORT
			LAYER M1 ;
			RECT 0.18 4.515 0.52 6.665 ;
			LAYER M1 ;
			RECT 1.62 4.515 1.96 6.665 ;
			LAYER M1 ;
			RECT 3.06 4.515 3.4 6.665 ;
			LAYER M1 ;
			RECT 4.5 4.515 4.84 6.665 ;
			LAYER M1 ;
			RECT 5.94 4.515 6.28 6.665 ;
			LAYER M1 ;
			RECT 7.38 4.515 7.72 6.665 ;
			LAYER M1 ;
			RECT 8.82 4.515 9.16 6.665 ;
			LAYER M1 ;
			RECT 0.18 4.115 9.16 4.515 ;
			LAYER M1 ;
			RECT 1.66 3.555 2.115 4.115 ;
			LAYER M1 ;
			RECT 1.625 3.105 2.115 3.555 ;
			LAYER M1 ;
			RECT 1.66 2.865 2.115 3.105 ;
			LAYER M1 ;
			RECT 0.955 2.465 8.46 2.865 ;
			LAYER M1 ;
			RECT 0.955 0.935 1.295 2.465 ;
			LAYER M1 ;
			RECT 2.4 0.935 2.74 2.465 ;
			LAYER M1 ;
			RECT 4.54 0.935 4.88 2.465 ;
			LAYER M1 ;
			RECT 6.68 0.935 7.02 2.465 ;
			LAYER M1 ;
			RECT 8.12 0.935 8.46 2.465 ;
		END
		AntennaDiffArea 13.7325 ;
	END out
	PIN GND
		DIRECTION inout ;
		USE GROUND ;
		PORT
			LAYER M1 ;
			RECT 0.9 0.5 1.24 0.525 ;
			LAYER M1 ;
			RECT 1.68 0.5 2.02 2.235 ;
			LAYER M1 ;
			RECT 3.12 0.5 3.46 2.235 ;
			LAYER M1 ;
			RECT 3.82 0.5 4.16 2.235 ;
			LAYER M1 ;
			RECT 5.26 0.5 5.6 2.235 ;
			LAYER M1 ;
			RECT 5.96 0.5 6.3 2.235 ;
			LAYER M1 ;
			RECT 7.4 0.5 7.74 2.235 ;
			LAYER M1 ;
			RECT 0 -0.5 9.62 0.5 ;
		END
	END GND
	PIN VDD
		DIRECTION inout ;
		USE POWER ;
		PORT
			LAYER M1 ;
			RECT 0 6.9 9.62 7.9 ;
			LAYER M1 ;
			RECT 0.9 4.75 1.24 6.9 ;
			LAYER M1 ;
			RECT 2.34 4.75 2.68 6.9 ;
			LAYER M1 ;
			RECT 3.78 4.75 4.12 6.9 ;
			LAYER M1 ;
			RECT 5.22 4.75 5.56 6.9 ;
			LAYER M1 ;
			RECT 6.66 4.75 7 6.9 ;
			LAYER M1 ;
			RECT 8.1 4.75 8.44 6.9 ;
		END
	END VDD
	PIN in
		DIRECTION input ;
		USE SIGNAL ;
		PORT
			LAYER M1 ;
			RECT 4.585 3.5 5.035 3.555 ;
			LAYER M1 ;
			RECT 3.44 3.16 5.66 3.5 ;
			LAYER M1 ;
			RECT 4.585 3.105 5.035 3.16 ;
			LAYER M1 ;
			RECT 4.586 3.104 5.034 3.105 ;
		END
		AntennaGateArea 7.9524 ;
	END in
	OBS
	END
END MMI_RPTRF
MACRO MMI_SFFB
	CLASS CORE ;
	FOREIGN MMI_SFFB 0 0 ;
	SIZE 15.54 BY 7.4 ;
	SYMMETRY X Y ;
	SITE CORE1 ;
	PIN d
		DIRECTION input ;
		USE SIGNAL ;
		PORT
			LAYER M1 ;
			RECT 1.625 3.485 2.075 3.555 ;
			LAYER M1 ;
			RECT 1.61 3.145 2.075 3.485 ;
			LAYER M1 ;
			RECT 1.625 3.105 2.075 3.145 ;
		END
		AntennaGateArea 0.4968 ;
	END d
	PIN GND
		DIRECTION inout ;
		USE GROUND ;
		PORT
			LAYER M1 ;
			RECT 0.18 0.5 0.52 1.57 ;
			LAYER M1 ;
			RECT 1.6 0.5 1.94 1.88 ;
			LAYER M1 ;
			RECT 3.94 0.5 4.28 1.88 ;
			LAYER M1 ;
			RECT 7.29 0.5 7.63 1.48 ;
			LAYER M1 ;
			RECT 9.47 0.5 9.81 1.57 ;
			LAYER M1 ;
			RECT 12.04 0.5 12.38 1.57 ;
			LAYER M1 ;
			RECT 14.02 0.5 14.36 1.79 ;
			LAYER M1 ;
			RECT 0 -0.5 15.54 0.5 ;
		END
	END GND
	PIN q
		DIRECTION output ;
		USE SIGNAL ;
		PORT
			LAYER M1 ;
			RECT 14.74 4.91 15.08 6.67 ;
			LAYER M1 ;
			RECT 14.74 3.555 14.97 4.91 ;
			LAYER M1 ;
			RECT 14.205 3.105 14.97 3.555 ;
			LAYER M1 ;
			RECT 14.74 1.79 14.97 3.105 ;
			LAYER M1 ;
			RECT 14.74 0.95 15.08 1.79 ;
		END
		AntennaDiffArea 1.3248 ;
	END q
	PIN s_in
		DIRECTION input ;
		USE SIGNAL ;
		PORT
			LAYER M1 ;
			RECT 3.105 3.105 3.555 3.555 ;
		END
		AntennaGateArea 0.2484 ;
	END s_in
	PIN s_en
		DIRECTION input ;
		USE SIGNAL ;
		PORT
			LAYER M1 ;
			RECT 13.74 4.18 14.08 4.52 ;
			LAYER M1 ;
			RECT 13.74 4.02 13.97 4.18 ;
			LAYER M1 ;
			RECT 13.66 3.79 13.97 4.02 ;
			LAYER M1 ;
			RECT 0.145 3.105 0.595 3.555 ;
			LAYER M1 ;
			RECT 13.66 2.72 13.89 3.79 ;
			LAYER M1 ;
			RECT 13.62 2.38 13.96 2.72 ;
		END
		AntennaGateArea 1.0404 ;
	END s_en
	PIN VDD
		DIRECTION inout ;
		USE POWER ;
		PORT
			LAYER M1 ;
			RECT 0 6.9 15.54 7.9 ;
			LAYER M1 ;
			RECT 0.94 4.61 1.28 6.9 ;
			LAYER M1 ;
			RECT 3.28 4.91 3.62 6.9 ;
			LAYER M1 ;
			RECT 6.13 5.03 6.47 6.9 ;
			LAYER M1 ;
			RECT 6.925 4.69 7.265 6.9 ;
			LAYER M1 ;
			RECT 8.405 5.38 8.745 6.9 ;
			LAYER M1 ;
			RECT 11.12 4.91 11.46 6.9 ;
			LAYER M1 ;
			RECT 12.54 4.91 12.88 6.9 ;
			LAYER M1 ;
			RECT 14.02 4.91 14.36 6.9 ;
			LAYER M1 ;
			RECT 6.925 4.515 7.27 4.69 ;
			LAYER M1 ;
			RECT 6.93 4.35 7.27 4.515 ;
		END
	END VDD
	PIN s_out
		DIRECTION output ;
		USE SIGNAL ;
		PORT
			LAYER M1 ;
			RECT 13.26 4.91 13.6 5.67 ;
			LAYER M1 ;
			RECT 13.26 4.495 13.49 4.91 ;
			LAYER M1 ;
			RECT 12.865 4.265 13.49 4.495 ;
			LAYER M1 ;
			RECT 12.865 3.555 13.095 4.265 ;
			LAYER M1 ;
			RECT 12.725 3.105 13.175 3.555 ;
			LAYER M1 ;
			RECT 12.865 1.79 13.095 3.105 ;
			LAYER M1 ;
			RECT 12.83 1.03 13.17 1.79 ;
		END
		AntennaDiffArea 0.8568 ;
	END s_out
	PIN clk
		DIRECTION input ;
		USE CLOCK ;
		PORT
			LAYER M1 ;
			RECT 4.585 3.49 5.035 3.555 ;
			LAYER M1 ;
			RECT 4.34 3.15 5.035 3.49 ;
			LAYER M1 ;
			RECT 4.585 3.105 5.035 3.15 ;
		END
		AntennaGateArea 0.6408 ;
	END clk
	OBS
		LAYER M1 ;
		RECT 0.18 4.61 0.52 5.73 ;
		LAYER M1 ;
		RECT 2.09 4.61 2.43 6.37 ;
		LAYER M1 ;
		RECT 4.81 6.275 5.23 6.615 ;
		LAYER M1 ;
		RECT 4.81 5.75 5.04 6.275 ;
		LAYER M1 ;
		RECT 3.98 4.91 4.32 5.75 ;
		LAYER M1 ;
		RECT 4.7 4.91 5.04 5.75 ;
		LAYER M1 ;
		RECT 5.41 5.03 5.75 5.87 ;
		LAYER M1 ;
		RECT 0.215 4.07 0.445 4.61 ;
		LAYER M1 ;
		RECT 2.2 4.555 2.43 4.61 ;
		LAYER M1 ;
		RECT 3.98 4.555 4.21 4.91 ;
		LAYER M1 ;
		RECT 2.2 4.325 4.21 4.555 ;
		LAYER M1 ;
		RECT 0.215 3.84 1.13 4.07 ;
		LAYER M1 ;
		RECT 0.9 2.45 1.13 3.84 ;
		LAYER M1 ;
		RECT 2.37 3.145 2.71 3.485 ;
		LAYER M1 ;
		RECT 2.38 2.45 2.61 3.145 ;
		LAYER M1 ;
		RECT 3.865 2.875 4.095 4.325 ;
		LAYER M1 ;
		RECT 4.81 4.14 5.04 4.91 ;
		LAYER M1 ;
		RECT 5.52 4.73 5.75 5.03 ;
		LAYER M1 ;
		RECT 5.52 4.5 6.68 4.73 ;
		LAYER M1 ;
		RECT 10.08 6.475 10.42 6.62 ;
		LAYER M1 ;
		RECT 9.955 6.28 10.42 6.475 ;
		LAYER M1 ;
		RECT 9.955 6.245 10.35 6.28 ;
		LAYER M1 ;
		RECT 9.955 5.75 10.185 6.245 ;
		LAYER M1 ;
		RECT 7.61 4.92 8.88 5.15 ;
		LAYER M1 ;
		RECT 4.81 3.91 5.73 4.14 ;
		LAYER M1 ;
		RECT 5.5 3.43 5.73 3.91 ;
		LAYER M1 ;
		RECT 6.45 4.12 6.68 4.5 ;
		LAYER M1 ;
		RECT 7.61 4.12 7.84 4.92 ;
		LAYER M1 ;
		RECT 6.45 3.89 7.84 4.12 ;
		LAYER M1 ;
		RECT 8.08 4.35 8.42 4.69 ;
		LAYER M1 ;
		RECT 8.08 3.54 8.31 4.35 ;
		LAYER M1 ;
		RECT 8.65 4.12 8.88 4.92 ;
		LAYER M1 ;
		RECT 9.17 4.91 9.51 5.75 ;
		LAYER M1 ;
		RECT 9.89 4.91 10.23 5.75 ;
		LAYER M1 ;
		RECT 11.84 4.91 12.18 5.75 ;
		LAYER M1 ;
		RECT 8.6 3.78 8.94 4.12 ;
		LAYER M1 ;
		RECT 7.93 3.43 8.31 3.54 ;
		LAYER M1 ;
		RECT 5.5 3.2 8.31 3.43 ;
		LAYER M1 ;
		RECT 0.9 2.22 2.61 2.45 ;
		LAYER M1 ;
		RECT 2.86 2.645 5.65 2.875 ;
		LAYER M1 ;
		RECT 0.9 2.11 1.455 2.22 ;
		LAYER M1 ;
		RECT 0.9 1.57 1.13 2.11 ;
		LAYER M1 ;
		RECT 2.86 1.88 3.09 2.645 ;
		LAYER M1 ;
		RECT 0.9 1.05 1.24 1.57 ;
		LAYER M1 ;
		RECT 2.75 1.04 3.09 1.88 ;
		LAYER M1 ;
		RECT 4.66 1.5 5 1.88 ;
		LAYER M1 ;
		RECT 5.42 1.53 5.65 2.645 ;
		LAYER M1 ;
		RECT 6.21 1.53 6.44 3.2 ;
		LAYER M1 ;
		RECT 8.65 2.97 8.88 3.78 ;
		LAYER M1 ;
		RECT 4.77 0.96 5 1.5 ;
		LAYER M1 ;
		RECT 5.38 1.19 5.72 1.53 ;
		LAYER M1 ;
		RECT 6.1 1.19 6.44 1.53 ;
		LAYER M1 ;
		RECT 6.73 2.74 8.88 2.97 ;
		LAYER M1 ;
		RECT 6.73 0.96 6.96 2.74 ;
		LAYER M1 ;
		RECT 9.17 2.5 9.4 4.91 ;
		LAYER M1 ;
		RECT 10 4.6 10.23 4.91 ;
		LAYER M1 ;
		RECT 10 4.37 10.96 4.6 ;
		LAYER M1 ;
		RECT 9.65 4.01 9.99 4.12 ;
		LAYER M1 ;
		RECT 9.65 3.78 10.37 4.01 ;
		LAYER M1 ;
		RECT 7.32 2.27 9.4 2.5 ;
		LAYER M1 ;
		RECT 10.14 2.61 10.37 3.78 ;
		LAYER M1 ;
		RECT 10.14 2.27 10.48 2.61 ;
		LAYER M1 ;
		RECT 7.32 2.16 7.66 2.27 ;
		LAYER M1 ;
		RECT 8.31 1.48 8.54 2.27 ;
		LAYER M1 ;
		RECT 10.73 2.15 10.96 4.37 ;
		LAYER M1 ;
		RECT 11.89 4.325 12.12 4.91 ;
		LAYER M1 ;
		RECT 11.835 4.215 12.175 4.325 ;
		LAYER M1 ;
		RECT 11.405 3.985 12.175 4.215 ;
		LAYER M1 ;
		RECT 10.73 2.04 11.15 2.15 ;
		LAYER M1 ;
		RECT 8.88 1.81 11.15 2.04 ;
		LAYER M1 ;
		RECT 8.88 1.48 9.11 1.81 ;
		LAYER M1 ;
		RECT 10.73 1.57 10.96 1.81 ;
		LAYER M1 ;
		RECT 11.405 1.57 11.635 3.985 ;
		LAYER M1 ;
		RECT 4.77 0.73 6.96 0.96 ;
		LAYER M1 ;
		RECT 8.01 1.24 8.54 1.48 ;
		LAYER M1 ;
		RECT 8.01 1.1 8.35 1.24 ;
		LAYER M1 ;
		RECT 8.77 1.14 9.11 1.48 ;
		LAYER M1 ;
		RECT 10.62 1.23 10.96 1.57 ;
		LAYER M1 ;
		RECT 11.32 1.03 11.66 1.57 ;
	END
END MMI_SFFB
MACRO MMI_SFFCB
	CLASS CORE ;
	FOREIGN MMI_SFFCB 0 0 ;
	SIZE 17.76 BY 7.4 ;
	SYMMETRY X Y ;
	SITE CORE1 ;
	PIN d
		DIRECTION input ;
		USE SIGNAL ;
		PORT
			LAYER M1 ;
			RECT 1.625 3.105 2.075 3.555 ;
		END
		AntennaGateArea 0.4968 ;
	END d
	PIN GND
		DIRECTION inout ;
		USE GROUND ;
		PORT
			LAYER M1 ;
			RECT 0.94 0.5 1.28 2.175 ;
			LAYER M1 ;
			RECT 3.32 0.5 3.66 1.795 ;
			LAYER M1 ;
			RECT 6.32 1.5 6.7 1.84 ;
			LAYER M1 ;
			RECT 6.335 0.5 6.675 1.5 ;
			LAYER M1 ;
			RECT 7.88 0.5 8.22 2.28 ;
			LAYER M1 ;
			RECT 10.53 0.5 10.87 1.875 ;
			LAYER M1 ;
			RECT 13.085 0.5 13.425 2.64 ;
			LAYER M1 ;
			RECT 16.195 0.5 16.535 1.89 ;
			LAYER M1 ;
			RECT 0 -0.5 17.76 0.5 ;
		END
	END GND
	PIN q
		DIRECTION output ;
		USE SIGNAL ;
		PORT
			LAYER M1 ;
			RECT 16.915 4.91 17.255 6.67 ;
			LAYER M1 ;
			RECT 16.915 3.555 17.145 4.91 ;
			LAYER M1 ;
			RECT 16.915 3.105 17.57 3.555 ;
			LAYER M1 ;
			RECT 16.915 1.89 17.145 3.105 ;
			LAYER M1 ;
			RECT 16.915 1.05 17.255 1.89 ;
		END
		AntennaDiffArea 1.3248 ;
	END q
	PIN s_en
		DIRECTION input ;
		USE SIGNAL ;
		PORT
			LAYER M1 ;
			RECT 0.885 3.5 1.335 3.555 ;
			LAYER M1 ;
			RECT 0.66 3.425 1.335 3.5 ;
			LAYER M1 ;
			RECT 0.645 3.195 1.335 3.425 ;
			LAYER M1 ;
			RECT 0.66 3.16 1.335 3.195 ;
			LAYER M1 ;
			RECT 0.885 3.105 1.335 3.16 ;
		END
		AntennaGateArea 1.0404 ;
	END s_en
	PIN s_in
		DIRECTION input ;
		USE SIGNAL ;
		PORT
			LAYER M1 ;
			RECT 2.365 3.105 2.815 3.555 ;
		END
		AntennaGateArea 0.2484 ;
	END s_in
	PIN VDD
		DIRECTION inout ;
		USE POWER ;
		PORT
			LAYER M1 ;
			RECT 0 6.9 17.76 7.9 ;
			LAYER M1 ;
			RECT 0.94 4.91 1.28 6.9 ;
			LAYER M1 ;
			RECT 3.28 4.91 3.62 6.9 ;
			LAYER M1 ;
			RECT 6.12 5.24 6.46 6.9 ;
			LAYER M1 ;
			RECT 7.58 4.56 7.92 6.9 ;
			LAYER M1 ;
			RECT 10.58 4.985 10.92 6.9 ;
			LAYER M1 ;
			RECT 13.235 4.91 13.575 6.9 ;
			LAYER M1 ;
			RECT 14.675 4.91 15.015 6.9 ;
			LAYER M1 ;
			RECT 16.195 4.91 16.535 6.9 ;
		END
	END VDD
	PIN s_out
		DIRECTION output ;
		USE SIGNAL ;
		PORT
			LAYER M1 ;
			RECT 15.435 4.91 15.775 5.67 ;
			LAYER M1 ;
			RECT 15.545 3.555 15.775 4.91 ;
			LAYER M1 ;
			RECT 15.545 3.105 16.135 3.555 ;
			LAYER M1 ;
			RECT 15.545 2.47 15.775 3.105 ;
			LAYER M1 ;
			RECT 15.115 2.24 15.775 2.47 ;
			LAYER M1 ;
			RECT 15.115 1.89 15.345 2.24 ;
			LAYER M1 ;
			RECT 15.005 1.13 15.345 1.89 ;
		END
		AntennaDiffArea 0.8568 ;
	END s_out
	PIN clk
		DIRECTION input ;
		USE CLOCK ;
		PORT
			LAYER M1 ;
			RECT 6.52 4.21 6.86 4.55 ;
			LAYER M1 ;
			RECT 6.63 3.43 6.86 4.21 ;
			LAYER M1 ;
			RECT 7.545 3.445 7.995 3.555 ;
			LAYER M1 ;
			RECT 7.34 3.43 7.995 3.445 ;
			LAYER M1 ;
			RECT 6.63 3.375 7.995 3.43 ;
			LAYER M1 ;
			RECT 6.63 3.2 9.3 3.375 ;
			LAYER M1 ;
			RECT 7.34 3.145 9.3 3.2 ;
			LAYER M1 ;
			RECT 7.34 3.105 7.995 3.145 ;
			LAYER M1 ;
			RECT 8.96 3.035 9.3 3.145 ;
		END
		AntennaGateArea 0.6408 ;
	END clk
	PIN clrb
		DIRECTION input ;
		USE SIGNAL ;
		PORT
			LAYER M1 ;
			RECT 3.56 3.555 3.9 3.56 ;
			LAYER M1 ;
			RECT 3.56 3.22 4.295 3.555 ;
			LAYER M1 ;
			RECT 3.845 3.105 4.295 3.22 ;
		END
		AntennaGateArea 0.7128 ;
	END clrb
	OBS
		LAYER M1 ;
		RECT 0.18 4.91 0.52 6.03 ;
		LAYER M1 ;
		RECT 2.09 4.91 2.43 6.67 ;
		LAYER M1 ;
		RECT 3.98 5.635 4.32 6.475 ;
		LAYER M1 ;
		RECT 4.7 5.635 5.04 6.475 ;
		LAYER M1 ;
		RECT 0.18 4.015 0.41 4.91 ;
		LAYER M1 ;
		RECT 2.15 4.625 2.38 4.91 ;
		LAYER M1 ;
		RECT 3.98 4.625 4.21 5.635 ;
		LAYER M1 ;
		RECT 2.15 4.395 4.21 4.625 ;
		LAYER M1 ;
		RECT 2.37 4.015 2.71 4.165 ;
		LAYER M1 ;
		RECT 0.18 3.785 2.71 4.015 ;
		LAYER M1 ;
		RECT 0.18 2.685 0.41 3.785 ;
		LAYER M1 ;
		RECT 3.05 2.875 3.28 4.395 ;
		LAYER M1 ;
		RECT 4.81 2.875 5.04 5.635 ;
		LAYER M1 ;
		RECT 5.4 5.24 5.74 6.36 ;
		LAYER M1 ;
		RECT 5.49 4.12 5.72 5.24 ;
		LAYER M1 ;
		RECT 6.88 5.01 7.22 6.075 ;
		LAYER M1 ;
		RECT 6.06 4.78 7.35 5.01 ;
		LAYER M1 ;
		RECT 5.49 3.78 5.83 4.12 ;
		LAYER M1 ;
		RECT 1.18 2.685 1.52 2.745 ;
		LAYER M1 ;
		RECT 0.18 2.455 1.52 2.685 ;
		LAYER M1 ;
		RECT 0.18 2.175 0.41 2.455 ;
		LAYER M1 ;
		RECT 1.18 2.405 1.52 2.455 ;
		LAYER M1 ;
		RECT 2.2 2.645 4.47 2.875 ;
		LAYER M1 ;
		RECT 2.2 2.175 2.43 2.645 ;
		LAYER M1 ;
		RECT 4.13 2.535 4.47 2.645 ;
		LAYER M1 ;
		RECT 4.81 2.535 5.19 2.875 ;
		LAYER M1 ;
		RECT 0.18 1.655 0.52 2.175 ;
		LAYER M1 ;
		RECT 2.09 1.335 2.43 2.175 ;
		LAYER M1 ;
		RECT 4.81 1.955 5.04 2.535 ;
		LAYER M1 ;
		RECT 4.81 1.71 5.37 1.955 ;
		LAYER M1 ;
		RECT 4.04 1.38 4.38 1.71 ;
		LAYER M1 ;
		RECT 5.03 1.615 5.37 1.71 ;
		LAYER M1 ;
		RECT 5.6 1.38 5.83 3.78 ;
		LAYER M1 ;
		RECT 6.06 3.215 6.29 4.78 ;
		LAYER M1 ;
		RECT 7.12 4.325 7.35 4.78 ;
		LAYER M1 ;
		RECT 8.21 6.19 10.01 6.42 ;
		LAYER M1 ;
		RECT 8.21 4.325 8.44 6.19 ;
		LAYER M1 ;
		RECT 9.67 6.08 10.01 6.19 ;
		LAYER M1 ;
		RECT 8.73 5.61 10.305 5.84 ;
		LAYER M1 ;
		RECT 8.73 4.56 9.07 5.61 ;
		LAYER M1 ;
		RECT 9.43 4.985 9.77 5.325 ;
		LAYER M1 ;
		RECT 7.12 4.095 8.44 4.325 ;
		LAYER M1 ;
		RECT 8.84 3.835 9.07 4.56 ;
		LAYER M1 ;
		RECT 9.54 4.295 9.77 4.985 ;
		LAYER M1 ;
		RECT 10.075 4.755 10.305 5.61 ;
		LAYER M1 ;
		RECT 11.28 4.91 11.62 5.75 ;
		LAYER M1 ;
		RECT 12 4.91 12.34 5.75 ;
		LAYER M1 ;
		RECT 13.955 4.91 14.295 5.75 ;
		LAYER M1 ;
		RECT 11.28 4.755 11.51 4.91 ;
		LAYER M1 ;
		RECT 10.075 4.525 11.51 4.755 ;
		LAYER M1 ;
		RECT 10.945 4.34 11.51 4.525 ;
		LAYER M1 ;
		RECT 12.11 4.515 12.34 4.91 ;
		LAYER M1 ;
		RECT 9.54 4.065 10.375 4.295 ;
		LAYER M1 ;
		RECT 10.035 4.015 10.375 4.065 ;
		LAYER M1 ;
		RECT 8.84 3.605 9.775 3.835 ;
		LAYER M1 ;
		RECT 10.035 3.785 10.855 4.015 ;
		LAYER M1 ;
		RECT 6.06 2.875 6.4 3.215 ;
		LAYER M1 ;
		RECT 6.06 2.56 6.29 2.875 ;
		LAYER M1 ;
		RECT 9.545 2.8 9.775 3.605 ;
		LAYER M1 ;
		RECT 10.05 2.8 10.39 2.945 ;
		LAYER M1 ;
		RECT 7.27 2.57 10.39 2.8 ;
		LAYER M1 ;
		RECT 6.06 2.33 6.7 2.56 ;
		LAYER M1 ;
		RECT 6.32 2.22 6.7 2.33 ;
		LAYER M1 ;
		RECT 7.27 2.28 7.5 2.57 ;
		LAYER M1 ;
		RECT 7.16 1.9 7.5 2.28 ;
		LAYER M1 ;
		RECT 4.04 1.15 5.83 1.38 ;
		LAYER M1 ;
		RECT 8.71 2.11 8.94 2.57 ;
		LAYER M1 ;
		RECT 10.625 2.34 10.855 3.785 ;
		LAYER M1 ;
		RECT 11.28 2.64 11.51 4.34 ;
		LAYER M1 ;
		RECT 12 4.285 12.34 4.515 ;
		LAYER M1 ;
		RECT 14.065 4.515 14.295 4.91 ;
		LAYER M1 ;
		RECT 14.955 4.515 15.295 4.58 ;
		LAYER M1 ;
		RECT 14.065 4.285 15.295 4.515 ;
		LAYER M1 ;
		RECT 12 3.87 12.23 4.285 ;
		LAYER M1 ;
		RECT 12 3.64 14.155 3.87 ;
		LAYER M1 ;
		RECT 12 2.64 12.23 3.64 ;
		LAYER M1 ;
		RECT 13.815 3.53 14.155 3.64 ;
		LAYER M1 ;
		RECT 14.395 2.64 14.625 4.285 ;
		LAYER M1 ;
		RECT 14.955 4.24 15.295 4.285 ;
		LAYER M1 ;
		RECT 9.49 2.11 10.855 2.34 ;
		LAYER M1 ;
		RECT 11.17 2.3 11.51 2.64 ;
		LAYER M1 ;
		RECT 11.89 2.3 12.23 2.64 ;
		LAYER M1 ;
		RECT 8.68 1.73 9.02 2.11 ;
		LAYER M1 ;
		RECT 9.49 1.875 9.72 2.11 ;
		LAYER M1 ;
		RECT 9.38 1.535 9.72 1.875 ;
		LAYER M1 ;
		RECT 14.235 2.26 14.625 2.64 ;
		LAYER M1 ;
		RECT 14.235 1.48 14.575 2.26 ;
	END
END MMI_SFFCB
MACRO MMI_SFFHB
	CLASS CORE ;
	FOREIGN MMI_SFFHB 0 0 ;
	SIZE 21.46 BY 7.4 ;
	SYMMETRY X Y ;
	SITE CORE1 ;
	PIN d
		DIRECTION input ;
		USE SIGNAL ;
		PORT
			LAYER M1 ;
			RECT 4.585 3.105 5.035 3.555 ;
		END
		AntennaGateArea 0.4968 ;
	END d
	PIN GND
		DIRECTION inout ;
		USE GROUND ;
		PORT
			LAYER M1 ;
			RECT 0.9 0.5 1.24 2.515 ;
			LAYER M1 ;
			RECT 3.04 0.5 3.38 1.53 ;
			LAYER M1 ;
			RECT 7.95 0.5 8.29 1.57 ;
			LAYER M1 ;
			RECT 10.91 0.5 11.25 1.57 ;
			LAYER M1 ;
			RECT 12.8 0.5 13.14 1.84 ;
			LAYER M1 ;
			RECT 15.74 0.5 16.08 2.25 ;
			LAYER M1 ;
			RECT 18.31 0.5 18.65 2.25 ;
			LAYER M1 ;
			RECT 20.2 0.5 20.54 2.73 ;
			LAYER M1 ;
			RECT 0 -0.5 21.46 0.5 ;
		END
	END GND
	PIN q
		DIRECTION output ;
		USE SIGNAL ;
		PORT
			LAYER M1 ;
			RECT 20.92 4.535 21.26 6.295 ;
			LAYER M1 ;
			RECT 20.975 3.555 21.205 4.535 ;
			LAYER M1 ;
			RECT 20.865 3.105 21.315 3.555 ;
			LAYER M1 ;
			RECT 20.975 2.73 21.205 3.105 ;
			LAYER M1 ;
			RECT 20.92 1.89 21.26 2.73 ;
		END
		AntennaDiffArea 1.3248 ;
	END q
	PIN s_en
		DIRECTION input ;
		USE SIGNAL ;
		PORT
			LAYER M1 ;
			RECT 6.58 4.26 6.92 4.38 ;
			LAYER M1 ;
			RECT 6.58 4.03 7.115 4.26 ;
			LAYER M1 ;
			RECT 0.885 3.47 1.335 3.555 ;
			LAYER M1 ;
			RECT 0.83 3.13 1.335 3.47 ;
			LAYER M1 ;
			RECT 0.885 3.105 1.335 3.13 ;
			LAYER M1 ;
			RECT 6.885 2.7 7.115 4.03 ;
			LAYER M1 ;
			RECT 6.885 2.415 7.38 2.7 ;
			LAYER M1 ;
			RECT 7.04 2.36 7.38 2.415 ;
		END
		AntennaGateArea 1.296 ;
	END s_en
	PIN s_in
		DIRECTION input ;
		USE SIGNAL ;
		PORT
			LAYER M1 ;
			RECT 7.535 4.125 7.875 4.465 ;
			LAYER M1 ;
			RECT 7.645 3.555 7.875 4.125 ;
			LAYER M1 ;
			RECT 7.545 3.105 7.995 3.555 ;
			LAYER M1 ;
			RECT 7.645 2.7 7.875 3.105 ;
			LAYER M1 ;
			RECT 7.645 2.36 8.05 2.7 ;
		END
		AntennaGateArea 0.2484 ;
	END s_in
	PIN VDD
		DIRECTION inout ;
		USE POWER ;
		PORT
			LAYER M1 ;
			RECT 0 6.9 21.46 7.9 ;
			LAYER M1 ;
			RECT 0.9 4.2 1.24 6.9 ;
			LAYER M1 ;
			RECT 3.04 5.065 3.38 6.9 ;
			LAYER M1 ;
			RECT 6.86 5.475 7.2 6.9 ;
			LAYER M1 ;
			RECT 9.96 5.975 10.3 6.9 ;
			LAYER M1 ;
			RECT 11.77 5.105 12.11 6.9 ;
			LAYER M1 ;
			RECT 15.31 5.035 15.65 6.9 ;
			LAYER M1 ;
			RECT 17.88 4.91 18.22 6.9 ;
			LAYER M1 ;
			RECT 18.72 4.535 19.06 6.9 ;
			LAYER M1 ;
			RECT 20.2 4.535 20.54 6.9 ;
		END
	END VDD
	PIN s_out
		DIRECTION output ;
		USE SIGNAL ;
		PORT
			LAYER M1 ;
			RECT 19.44 4.535 19.78 5.295 ;
			LAYER M1 ;
			RECT 19.55 3.555 19.78 4.535 ;
			LAYER M1 ;
			RECT 19.385 3.335 19.835 3.555 ;
			LAYER M1 ;
			RECT 19.12 3.105 19.835 3.335 ;
			LAYER M1 ;
			RECT 19.12 2.73 19.35 3.105 ;
			LAYER M1 ;
			RECT 19.01 1.97 19.35 2.73 ;
		END
		AntennaDiffArea 0.8568 ;
	END s_out
	PIN clk
		DIRECTION input ;
		USE CLOCK ;
		PORT
			LAYER M1 ;
			RECT 11.2 4.29 11.54 4.4 ;
			LAYER M1 ;
			RECT 10.78 4.06 11.54 4.29 ;
			LAYER M1 ;
			RECT 10.78 3.555 11.01 4.06 ;
			LAYER M1 ;
			RECT 10.505 3.28 11.01 3.555 ;
			LAYER M1 ;
			RECT 10.505 3.105 11.35 3.28 ;
			LAYER M1 ;
			RECT 10.78 2.94 11.35 3.105 ;
			LAYER M1 ;
			RECT 10.78 2.15 11.01 2.94 ;
			LAYER M1 ;
			RECT 10.67 1.81 11.01 2.15 ;
		END
		AntennaGateArea 0.6408 ;
	END clk
	PIN hold
		DIRECTION input ;
		USE SIGNAL ;
		PORT
			LAYER M1 ;
			RECT 4 4.015 4.34 4.025 ;
			LAYER M1 ;
			RECT 2.585 3.785 5.51 4.015 ;
			LAYER M1 ;
			RECT 2.585 3.555 2.815 3.785 ;
			LAYER M1 ;
			RECT 4 3.685 4.34 3.785 ;
			LAYER M1 ;
			RECT 2.365 3.495 2.815 3.555 ;
			LAYER M1 ;
			RECT 2.085 3.155 2.815 3.495 ;
			LAYER M1 ;
			RECT 2.365 3.105 2.815 3.155 ;
			LAYER M1 ;
			RECT 5.28 3.085 5.51 3.785 ;
			LAYER M1 ;
			RECT 5.28 2.855 6.08 3.085 ;
			LAYER M1 ;
			RECT 5.85 2.6 6.08 2.855 ;
			LAYER M1 ;
			RECT 5.85 2.26 6.19 2.6 ;
		END
		AntennaGateArea 0.7452 ;
	END hold
	OBS
		LAYER M1 ;
		RECT 0.18 4.2 0.52 5.04 ;
		LAYER M1 ;
		RECT 1.62 4.2 1.96 5.04 ;
		LAYER M1 ;
		RECT 2.32 4.815 2.66 6.345 ;
		LAYER M1 ;
		RECT 3.76 6.115 6.29 6.345 ;
		LAYER M1 ;
		RECT 3.76 4.815 4.1 6.115 ;
		LAYER M1 ;
		RECT 6.06 5.885 6.29 6.115 ;
		LAYER M1 ;
		RECT 2.32 4.585 4.1 4.815 ;
		LAYER M1 ;
		RECT 4.91 4.84 5.25 5.865 ;
		LAYER M1 ;
		RECT 6.06 5.075 6.4 5.885 ;
		LAYER M1 ;
		RECT 8.01 5.475 8.35 6.315 ;
		LAYER M1 ;
		RECT 8.73 5.475 9.07 6.315 ;
		LAYER M1 ;
		RECT 11.2 6.32 11.54 6.43 ;
		LAYER M1 ;
		RECT 10.68 6.09 11.54 6.32 ;
		LAYER M1 ;
		RECT 10.68 5.705 11.02 6.09 ;
		LAYER M1 ;
		RECT 8.01 5.245 8.24 5.475 ;
		LAYER M1 ;
		RECT 6.63 5.015 8.24 5.245 ;
		LAYER M1 ;
		RECT 8.84 5.245 9.07 5.475 ;
		LAYER M1 ;
		RECT 10.045 5.475 11.02 5.705 ;
		LAYER M1 ;
		RECT 8.84 5.015 9.72 5.245 ;
		LAYER M1 ;
		RECT 6.63 4.84 6.86 5.015 ;
		LAYER M1 ;
		RECT 4.91 4.61 6.86 4.84 ;
		LAYER M1 ;
		RECT 4.91 4.585 5.25 4.61 ;
		LAYER M1 ;
		RECT 0.29 2.515 0.52 4.2 ;
		LAYER M1 ;
		RECT 1.62 2.57 1.85 4.2 ;
		LAYER M1 ;
		RECT 5.74 3.545 5.97 4.61 ;
		LAYER M1 ;
		RECT 8.215 4.445 8.585 4.785 ;
		LAYER M1 ;
		RECT 8.9 4.445 9.24 4.785 ;
		LAYER M1 ;
		RECT 5.74 3.315 6.655 3.545 ;
		LAYER M1 ;
		RECT 4 2.57 4.34 2.625 ;
		LAYER M1 ;
		RECT 5.15 2.57 5.49 2.615 ;
		LAYER M1 ;
		RECT 0.18 2.135 0.52 2.515 ;
		LAYER M1 ;
		RECT 0.29 1.07 0.52 2.135 ;
		LAYER M1 ;
		RECT 0.29 0.73 0.63 1.07 ;
		LAYER M1 ;
		RECT 1.62 2.34 5.49 2.57 ;
		LAYER M1 ;
		RECT 1.62 2.135 1.96 2.34 ;
		LAYER M1 ;
		RECT 4 2.285 4.34 2.34 ;
		LAYER M1 ;
		RECT 5.15 2.275 5.49 2.34 ;
		LAYER M1 ;
		RECT 6.425 2.03 6.655 3.315 ;
		LAYER M1 ;
		RECT 8.355 3.27 8.585 4.445 ;
		LAYER M1 ;
		RECT 8.355 2.93 8.72 3.27 ;
		LAYER M1 ;
		RECT 8.95 2.6 9.18 4.445 ;
		LAYER M1 ;
		RECT 9.49 3.27 9.72 5.015 ;
		LAYER M1 ;
		RECT 9.475 2.93 9.815 3.27 ;
		LAYER M1 ;
		RECT 8.95 2.26 9.29 2.6 ;
		LAYER M1 ;
		RECT 9.585 2.03 9.815 2.93 ;
		LAYER M1 ;
		RECT 10.045 2.61 10.275 5.475 ;
		LAYER M1 ;
		RECT 12.49 5.075 12.83 5.915 ;
		LAYER M1 ;
		RECT 13.21 5.075 13.55 5.915 ;
		LAYER M1 ;
		RECT 10.53 4.86 10.87 4.865 ;
		LAYER M1 ;
		RECT 12.49 4.86 12.81 5.075 ;
		LAYER M1 ;
		RECT 10.53 4.63 12.81 4.86 ;
		LAYER M1 ;
		RECT 10.53 4.525 10.87 4.63 ;
		LAYER M1 ;
		RECT 11.83 4.06 12.35 4.4 ;
		LAYER M1 ;
		RECT 10.045 2.38 10.44 2.61 ;
		LAYER M1 ;
		RECT 2.32 1.8 4.1 2.03 ;
		LAYER M1 ;
		RECT 2.32 1.19 2.66 1.8 ;
		LAYER M1 ;
		RECT 3.76 1.19 4.1 1.8 ;
		LAYER M1 ;
		RECT 4.91 1.8 9.11 2.03 ;
		LAYER M1 ;
		RECT 4.91 1.19 5.25 1.8 ;
		LAYER M1 ;
		RECT 5.61 1.195 5.95 1.535 ;
		LAYER M1 ;
		RECT 3.87 0.96 4.1 1.19 ;
		LAYER M1 ;
		RECT 5.61 0.96 5.84 1.195 ;
		LAYER M1 ;
		RECT 6.76 1.19 7.1 1.8 ;
		LAYER M1 ;
		RECT 8.77 1.69 9.11 1.8 ;
		LAYER M1 ;
		RECT 9.49 1.69 9.83 2.03 ;
		LAYER M1 ;
		RECT 10.21 1.57 10.44 2.38 ;
		LAYER M1 ;
		RECT 11.83 2.875 12.06 4.06 ;
		LAYER M1 ;
		RECT 11.72 2.505 12.06 2.875 ;
		LAYER M1 ;
		RECT 11.72 1.84 11.95 2.505 ;
		LAYER M1 ;
		RECT 12.58 2.415 12.81 4.63 ;
		LAYER M1 ;
		RECT 13.32 3.95 13.55 5.075 ;
		LAYER M1 ;
		RECT 14.59 5.035 14.93 5.875 ;
		LAYER M1 ;
		RECT 16.03 5.745 16.37 5.875 ;
		LAYER M1 ;
		RECT 16.03 5.515 17.585 5.745 ;
		LAYER M1 ;
		RECT 16.03 5.035 16.37 5.515 ;
		LAYER M1 ;
		RECT 16.75 5.25 16.98 5.275 ;
		LAYER M1 ;
		RECT 13.89 4.51 14.23 4.62 ;
		LAYER M1 ;
		RECT 14.595 4.51 14.825 5.035 ;
		LAYER M1 ;
		RECT 16.03 4.805 16.26 5.035 ;
		LAYER M1 ;
		RECT 16.73 4.91 17.07 5.25 ;
		LAYER M1 ;
		RECT 13.89 4.28 14.825 4.51 ;
		LAYER M1 ;
		RECT 15.07 4.575 16.26 4.805 ;
		LAYER M1 ;
		RECT 15.07 4.465 15.41 4.575 ;
		LAYER M1 ;
		RECT 13.32 3.72 14.23 3.95 ;
		LAYER M1 ;
		RECT 13.89 3.61 14.23 3.72 ;
		LAYER M1 ;
		RECT 12.52 2.305 12.86 2.415 ;
		LAYER M1 ;
		RECT 14 2.305 14.23 3.61 ;
		LAYER M1 ;
		RECT 14.595 3.2 14.825 4.28 ;
		LAYER M1 ;
		RECT 15.055 3.84 15.395 3.95 ;
		LAYER M1 ;
		RECT 16.75 3.84 16.98 4.91 ;
		LAYER M1 ;
		RECT 17.355 4.29 17.585 5.515 ;
		LAYER M1 ;
		RECT 17.355 4.06 19.3 4.29 ;
		LAYER M1 ;
		RECT 15.055 3.795 16.98 3.84 ;
		LAYER M1 ;
		RECT 17.74 3.95 18.105 4.06 ;
		LAYER M1 ;
		RECT 18.96 3.95 19.3 4.06 ;
		LAYER M1 ;
		RECT 15.055 3.61 17.415 3.795 ;
		LAYER M1 ;
		RECT 16.75 3.565 17.415 3.61 ;
		LAYER M1 ;
		RECT 14.595 2.97 15.21 3.2 ;
		LAYER M1 ;
		RECT 12.52 2.075 13.75 2.305 ;
		LAYER M1 ;
		RECT 14 2.075 14.51 2.305 ;
		LAYER M1 ;
		RECT 13.52 1.84 13.75 2.075 ;
		LAYER M1 ;
		RECT 14.28 1.84 14.51 2.075 ;
		LAYER M1 ;
		RECT 14.98 2.25 15.21 2.97 ;
		LAYER M1 ;
		RECT 17.185 2.82 17.415 3.565 ;
		LAYER M1 ;
		RECT 15.46 2.71 15.8 2.82 ;
		LAYER M1 ;
		RECT 15.46 2.48 16.69 2.71 ;
		LAYER M1 ;
		RECT 16.965 2.48 17.415 2.82 ;
		LAYER M1 ;
		RECT 16.46 2.25 16.69 2.48 ;
		LAYER M1 ;
		RECT 17.185 2.25 17.415 2.48 ;
		LAYER M1 ;
		RECT 17.74 3.17 17.97 3.95 ;
		LAYER M1 ;
		RECT 17.74 2.83 18.17 3.17 ;
		LAYER M1 ;
		RECT 14.98 1.87 15.32 2.25 ;
		LAYER M1 ;
		RECT 3.87 0.73 5.84 0.96 ;
		LAYER M1 ;
		RECT 10.19 1.46 10.53 1.57 ;
		LAYER M1 ;
		RECT 9.13 1.23 10.53 1.46 ;
		LAYER M1 ;
		RECT 9.13 1.12 9.47 1.23 ;
		LAYER M1 ;
		RECT 10.19 1.19 10.53 1.23 ;
		LAYER M1 ;
		RECT 11.61 1.5 11.95 1.84 ;
		LAYER M1 ;
		RECT 13.52 1.46 13.86 1.84 ;
		LAYER M1 ;
		RECT 14.28 1.5 14.62 1.84 ;
		LAYER M1 ;
		RECT 16.46 1.71 16.8 2.25 ;
		LAYER M1 ;
		RECT 17.16 1.91 17.5 2.25 ;
		LAYER M1 ;
		RECT 16.57 1.665 16.8 1.71 ;
		LAYER M1 ;
		RECT 17.74 1.665 17.97 2.83 ;
		LAYER M1 ;
		RECT 16.57 1.435 17.97 1.665 ;
	END
END MMI_SFFHB
MACRO MMI_SFFMB
	CLASS CORE ;
	FOREIGN MMI_SFFMB 0 0 ;
	SIZE 19.98 BY 7.4 ;
	SYMMETRY X Y ;
	SITE CORE1 ;
	PIN d0
		DIRECTION input ;
		USE SIGNAL ;
		PORT
			LAYER M1 ;
			RECT 4.585 3.37 5.035 3.555 ;
			LAYER M1 ;
			RECT 3.045 3.26 3.385 3.37 ;
			LAYER M1 ;
			RECT 4.585 3.26 5.155 3.37 ;
			LAYER M1 ;
			RECT 3.045 3.03 5.155 3.26 ;
		END
		AntennaGateArea 0.4968 ;
	END d0
	PIN sel
		DIRECTION input ;
		USE SIGNAL ;
		PORT
			LAYER M1 ;
			RECT 2.365 3.5 2.815 3.555 ;
			LAYER M1 ;
			RECT 2.08 3.16 2.815 3.5 ;
			LAYER M1 ;
			RECT 2.365 3.105 2.815 3.16 ;
		END
		AntennaGateArea 0.7452 ;
	END sel
	PIN GND
		DIRECTION inout ;
		USE GROUND ;
		PORT
			LAYER M1 ;
			RECT 0.9 0.5 1.24 2.03 ;
			LAYER M1 ;
			RECT 4.19 0.5 4.53 1.88 ;
			LAYER M1 ;
			RECT 7.25 0.5 7.59 1.88 ;
			LAYER M1 ;
			RECT 9.86 0.5 10.2 1 ;
			LAYER M1 ;
			RECT 12.125 0.5 12.465 1.57 ;
			LAYER M1 ;
			RECT 14.305 0.5 14.645 1.84 ;
			LAYER M1 ;
			RECT 16.875 0.5 17.215 1.645 ;
			LAYER M1 ;
			RECT 18.74 0.5 19.08 2.765 ;
			LAYER M1 ;
			RECT 0 -0.5 19.98 0.5 ;
		END
	END GND
	PIN q
		DIRECTION output ;
		USE SIGNAL ;
		PORT
			LAYER M1 ;
			RECT 19.46 4.91 19.8 6.67 ;
			LAYER M1 ;
			RECT 19.57 3.555 19.8 4.91 ;
			LAYER M1 ;
			RECT 19.385 3.105 19.835 3.555 ;
			LAYER M1 ;
			RECT 19.57 2.765 19.8 3.105 ;
			LAYER M1 ;
			RECT 19.46 1.925 19.8 2.765 ;
		END
		AntennaDiffArea 1.3248 ;
	END q
	PIN s_in
		DIRECTION input ;
		USE SIGNAL ;
		PORT
			LAYER M1 ;
			RECT 7.545 3.485 7.995 3.555 ;
			LAYER M1 ;
			RECT 7.545 3.145 8.04 3.485 ;
			LAYER M1 ;
			RECT 7.545 3.105 7.995 3.145 ;
		END
		AntennaGateArea 0.2484 ;
	END s_in
	PIN s_en
		DIRECTION input ;
		USE SIGNAL ;
		PORT
			LAYER M1 ;
			RECT 0.885 3.5 1.335 3.555 ;
			LAYER M1 ;
			RECT 0.76 3.16 1.335 3.5 ;
			LAYER M1 ;
			RECT 0.885 3.105 1.335 3.16 ;
		END
		AntennaGateArea 1.296 ;
	END s_en
	PIN d1
		DIRECTION input ;
		USE SIGNAL ;
		PORT
			LAYER M1 ;
			RECT 6.065 3.105 6.515 3.555 ;
			LAYER M1 ;
			RECT 6.175 3.03 6.515 3.105 ;
		END
		AntennaGateArea 0.4968 ;
	END d1
	PIN VDD
		DIRECTION inout ;
		USE POWER ;
		PORT
			LAYER M1 ;
			RECT 0 6.9 19.98 7.9 ;
			LAYER M1 ;
			RECT 0.9 4.91 1.24 6.9 ;
			LAYER M1 ;
			RECT 3.04 4.705 3.38 6.9 ;
			LAYER M1 ;
			RECT 7.56 4.91 7.9 6.9 ;
			LAYER M1 ;
			RECT 10.85 4.25 11.19 6.9 ;
			LAYER M1 ;
			RECT 12.32 5 12.66 6.9 ;
			LAYER M1 ;
			RECT 15.37 4.84 15.71 6.9 ;
			LAYER M1 ;
			RECT 17.26 6 17.6 6.9 ;
			LAYER M1 ;
			RECT 18.74 4.91 19.08 6.9 ;
		END
	END VDD
	PIN s_out
		DIRECTION output ;
		USE SIGNAL ;
		PORT
			LAYER M1 ;
			RECT 17.98 5.58 18.32 6.34 ;
			LAYER M1 ;
			RECT 17.98 3.555 18.21 5.58 ;
			LAYER M1 ;
			RECT 17.66 3.105 18.355 3.555 ;
			LAYER M1 ;
			RECT 17.66 2.765 17.89 3.105 ;
			LAYER M1 ;
			RECT 17.55 2.005 17.89 2.765 ;
		END
		AntennaDiffArea 0.8568 ;
	END s_out
	PIN clk
		DIRECTION input ;
		USE CLOCK ;
		PORT
			LAYER M1 ;
			RECT 9.025 3.105 9.475 3.555 ;
		END
		AntennaGateArea 0.6408 ;
	END clk
	OBS
		LAYER M1 ;
		RECT 0.18 4.91 0.52 5.75 ;
		LAYER M1 ;
		RECT 1.62 4.91 1.96 5.75 ;
		LAYER M1 ;
		RECT 0.29 2.03 0.52 4.91 ;
		LAYER M1 ;
		RECT 1.62 4.015 1.85 4.91 ;
		LAYER M1 ;
		RECT 2.32 4.61 2.66 6.37 ;
		LAYER M1 ;
		RECT 3.76 6.14 5.95 6.37 ;
		LAYER M1 ;
		RECT 2.43 4.475 2.66 4.61 ;
		LAYER M1 ;
		RECT 3.76 4.61 4.1 6.14 ;
		LAYER M1 ;
		RECT 4.91 4.61 5.25 5.89 ;
		LAYER M1 ;
		RECT 5.61 5.09 5.95 6.14 ;
		LAYER M1 ;
		RECT 3.76 4.475 3.99 4.61 ;
		LAYER M1 ;
		RECT 2.43 4.245 3.99 4.475 ;
		LAYER M1 ;
		RECT 5.02 4.48 5.25 4.61 ;
		LAYER M1 ;
		RECT 6.76 4.48 7.1 6.37 ;
		LAYER M1 ;
		RECT 8.71 4.91 9.05 5.75 ;
		LAYER M1 ;
		RECT 9.43 4.91 9.77 5.75 ;
		LAYER M1 ;
		RECT 10.13 5.69 10.47 6.03 ;
		LAYER M1 ;
		RECT 10.24 5.09 10.47 5.69 ;
		LAYER M1 ;
		RECT 8.71 4.48 8.94 4.91 ;
		LAYER M1 ;
		RECT 5.02 4.25 8.94 4.48 ;
		LAYER M1 ;
		RECT 5.485 4.015 5.825 4.02 ;
		LAYER M1 ;
		RECT 1.62 3.785 5.825 4.015 ;
		LAYER M1 ;
		RECT 1.62 2.03 1.85 3.785 ;
		LAYER M1 ;
		RECT 5.485 3.68 5.825 3.785 ;
		LAYER M1 ;
		RECT 6.76 2.8 6.99 4.25 ;
		LAYER M1 ;
		RECT 9.43 4.015 9.66 4.91 ;
		LAYER M1 ;
		RECT 10.13 4.25 10.47 5.09 ;
		LAYER M1 ;
		RECT 13.04 5 13.38 5.84 ;
		LAYER M1 ;
		RECT 13.76 5 14.1 5.84 ;
		LAYER M1 ;
		RECT 12.56 4.59 12.9 4.7 ;
		LAYER M1 ;
		RECT 12.04 4.36 12.9 4.59 ;
		LAYER M1 ;
		RECT 12.04 4.25 12.38 4.36 ;
		LAYER M1 ;
		RECT 8.55 3.785 9.66 4.015 ;
		LAYER M1 ;
		RECT 2.425 2.57 6.99 2.8 ;
		LAYER M1 ;
		RECT 2.425 2.31 2.655 2.57 ;
		LAYER M1 ;
		RECT 0.18 1.65 0.52 2.03 ;
		LAYER M1 ;
		RECT 0.29 1.07 0.52 1.65 ;
		LAYER M1 ;
		RECT 0.29 0.73 0.67 1.07 ;
		LAYER M1 ;
		RECT 1.62 1.65 1.96 2.03 ;
		LAYER M1 ;
		RECT 1.62 1.13 1.85 1.65 ;
		LAYER M1 ;
		RECT 2.32 1.47 2.66 2.31 ;
		LAYER M1 ;
		RECT 3.58 2.11 5.14 2.34 ;
		LAYER M1 ;
		RECT 3.58 1.88 3.81 2.11 ;
		LAYER M1 ;
		RECT 4.91 1.88 5.14 2.11 ;
		LAYER M1 ;
		RECT 6.17 1.88 6.4 2.57 ;
		LAYER M1 ;
		RECT 6.76 2.34 6.99 2.57 ;
		LAYER M1 ;
		RECT 8.55 2.355 8.78 3.785 ;
		LAYER M1 ;
		RECT 10.24 2.82 10.47 4.25 ;
		LAYER M1 ;
		RECT 9.99 2.59 10.47 2.82 ;
		LAYER M1 ;
		RECT 6.76 2.11 8.32 2.34 ;
		LAYER M1 ;
		RECT 8.55 2.125 9.04 2.355 ;
		LAYER M1 ;
		RECT 3.47 1.54 3.81 1.88 ;
		LAYER M1 ;
		RECT 1.62 0.9 2.47 1.13 ;
		LAYER M1 ;
		RECT 2.13 0.79 2.47 0.9 ;
		LAYER M1 ;
		RECT 4.91 1.04 5.25 1.88 ;
		LAYER M1 ;
		RECT 6.06 1.04 6.4 1.88 ;
		LAYER M1 ;
		RECT 8.09 1.57 8.32 2.11 ;
		LAYER M1 ;
		RECT 8.81 1.57 9.04 2.125 ;
		LAYER M1 ;
		RECT 9.315 2.19 9.655 2.3 ;
		LAYER M1 ;
		RECT 9.99 2.19 10.22 2.59 ;
		LAYER M1 ;
		RECT 9.315 1.96 10.22 2.19 ;
		LAYER M1 ;
		RECT 12.04 2.03 12.27 4.25 ;
		LAYER M1 ;
		RECT 13.15 3.465 13.38 5 ;
		LAYER M1 ;
		RECT 13.87 4.61 14.1 5 ;
		LAYER M1 ;
		RECT 14.65 4.84 14.99 5.68 ;
		LAYER M1 ;
		RECT 16.04 5.765 16.38 6.1 ;
		LAYER M1 ;
		RECT 16.04 5.535 17.36 5.765 ;
		LAYER M1 ;
		RECT 13.87 4.38 14.42 4.61 ;
		LAYER M1 ;
		RECT 13.62 3.795 13.96 4.135 ;
		LAYER M1 ;
		RECT 14.19 4.085 14.42 4.38 ;
		LAYER M1 ;
		RECT 14.76 4.545 14.99 4.84 ;
		LAYER M1 ;
		RECT 16.04 4.545 16.27 5.535 ;
		LAYER M1 ;
		RECT 14.76 4.315 16.27 4.545 ;
		LAYER M1 ;
		RECT 16.56 4.84 16.9 5.18 ;
		LAYER M1 ;
		RECT 16.56 4.085 16.79 4.84 ;
		LAYER M1 ;
		RECT 14.19 3.855 16.79 4.085 ;
		LAYER M1 ;
		RECT 17.13 4.34 17.36 5.535 ;
		LAYER M1 ;
		RECT 17.13 4 17.51 4.34 ;
		LAYER M1 ;
		RECT 12.525 3.13 13.38 3.465 ;
		LAYER M1 ;
		RECT 12.525 3.125 13.3 3.13 ;
		LAYER M1 ;
		RECT 12.5 2.03 12.84 2.14 ;
		LAYER M1 ;
		RECT 9.84 1.69 10.22 1.96 ;
		LAYER M1 ;
		RECT 11.045 1.8 12.84 2.03 ;
		LAYER M1 ;
		RECT 11.045 1.57 11.275 1.8 ;
		LAYER M1 ;
		RECT 13.07 1.57 13.3 3.125 ;
		LAYER M1 ;
		RECT 13.73 2.87 13.96 3.795 ;
		LAYER M1 ;
		RECT 14.89 3.745 15.23 3.855 ;
		LAYER M1 ;
		RECT 15.215 2.87 15.555 2.98 ;
		LAYER M1 ;
		RECT 13.73 2.64 15.555 2.87 ;
		LAYER M1 ;
		RECT 14.545 2.3 14.885 2.41 ;
		LAYER M1 ;
		RECT 15.835 2.3 16.065 3.855 ;
		LAYER M1 ;
		RECT 17.13 3.36 17.36 4 ;
		LAYER M1 ;
		RECT 13.715 2.07 16.065 2.3 ;
		LAYER M1 ;
		RECT 13.715 1.57 13.945 2.07 ;
		LAYER M1 ;
		RECT 8.09 1.23 8.43 1.57 ;
		LAYER M1 ;
		RECT 8.81 1.46 9.15 1.57 ;
		LAYER M1 ;
		RECT 10.935 1.46 11.275 1.57 ;
		LAYER M1 ;
		RECT 8.81 1.23 11.275 1.46 ;
		LAYER M1 ;
		RECT 12.845 1.19 13.3 1.57 ;
		LAYER M1 ;
		RECT 13.605 1.23 13.945 1.57 ;
		LAYER M1 ;
		RECT 15.025 1.3 15.365 1.84 ;
		LAYER M1 ;
		RECT 15.835 1.645 16.065 2.07 ;
		LAYER M1 ;
		RECT 15.725 1.305 16.065 1.645 ;
		LAYER M1 ;
		RECT 16.355 3.13 17.36 3.36 ;
		LAYER M1 ;
		RECT 16.355 2.29 16.585 3.13 ;
		LAYER M1 ;
		RECT 16.355 1.95 16.975 2.29 ;
		LAYER M1 ;
		RECT 15.135 0.96 15.365 1.3 ;
		LAYER M1 ;
		RECT 16.355 0.96 16.585 1.95 ;
		LAYER M1 ;
		RECT 15.135 0.73 16.585 0.96 ;
	END
END MMI_SFFMB
MACRO MMI_SFFPB
	CLASS CORE ;
	FOREIGN MMI_SFFPB 0 0 ;
	SIZE 16.28 BY 7.4 ;
	SYMMETRY X Y ;
	SITE CORE1 ;
	PIN d
		DIRECTION input ;
		USE SIGNAL ;
		PORT
			LAYER M1 ;
			RECT 1.79 3.435 2.13 3.465 ;
			LAYER M1 ;
			RECT 2.365 3.435 2.815 3.555 ;
			LAYER M1 ;
			RECT 1.79 3.205 2.815 3.435 ;
			LAYER M1 ;
			RECT 1.79 3.125 2.13 3.205 ;
			LAYER M1 ;
			RECT 2.365 3.105 2.815 3.205 ;
		END
		AntennaGateArea 0.4968 ;
	END d
	PIN GND
		DIRECTION inout ;
		USE GROUND ;
		PORT
			LAYER M1 ;
			RECT 0.9 0.5 1.24 2.72 ;
			LAYER M1 ;
			RECT 7.905 1.905 8.6 2.745 ;
			LAYER M1 ;
			RECT 2.75 0.5 3.09 1.87 ;
			LAYER M1 ;
			RECT 4.6 0.5 4.94 1.57 ;
			LAYER M1 ;
			RECT 7.905 0.5 8.245 1.905 ;
			LAYER M1 ;
			RECT 10.215 0.5 10.555 1.705 ;
			LAYER M1 ;
			RECT 13.445 0.5 13.785 1.6 ;
			LAYER M1 ;
			RECT 14.775 0.5 15.115 2.855 ;
			LAYER M1 ;
			RECT 0 -0.5 16.28 0.5 ;
		END
	END GND
	PIN q
		DIRECTION output ;
		USE SIGNAL ;
		PORT
			LAYER M1 ;
			RECT 15.495 4.39 15.835 6.15 ;
			LAYER M1 ;
			RECT 15.605 3.44 15.835 4.39 ;
			LAYER M1 ;
			RECT 15.605 3.21 16.08 3.44 ;
			LAYER M1 ;
			RECT 15.605 2.855 15.835 3.21 ;
			LAYER M1 ;
			RECT 15.495 2.015 15.835 2.855 ;
		END
		AntennaDiffArea 1.3248 ;
	END q
	PIN s_in
		DIRECTION input ;
		USE SIGNAL ;
		PORT
			LAYER M1 ;
			RECT 3.845 3.105 4.295 3.555 ;
		END
		AntennaGateArea 0.2484 ;
	END s_in
	PIN s_en
		DIRECTION input ;
		USE SIGNAL ;
		PORT
			LAYER M1 ;
			RECT 0.885 3.5 1.335 3.555 ;
			LAYER M1 ;
			RECT 0.66 3.16 1.335 3.5 ;
			LAYER M1 ;
			RECT 0.885 3.105 1.335 3.16 ;
		END
		AntennaGateArea 0.738 ;
	END s_en
	PIN VDD
		DIRECTION inout ;
		USE POWER ;
		PORT
			LAYER M1 ;
			RECT 0 6.9 16.28 7.9 ;
			LAYER M1 ;
			RECT 0.94 4.91 1.28 6.9 ;
			LAYER M1 ;
			RECT 3.28 4.91 3.62 6.9 ;
			LAYER M1 ;
			RECT 6.65 4.705 6.99 6.9 ;
			LAYER M1 ;
			RECT 8.09 4.43 8.43 6.9 ;
			LAYER M1 ;
			RECT 12.42 4.66 12.76 6.9 ;
			LAYER M1 ;
			RECT 14.775 4.39 15.115 6.9 ;
		END
	END VDD
	PIN setb
		DIRECTION input ;
		USE SIGNAL ;
		PORT
			LAYER M1 ;
			RECT 8.025 3.435 8.365 3.5 ;
			LAYER M1 ;
			RECT 8.025 3.385 9.355 3.435 ;
			LAYER M1 ;
			RECT 8.025 3.205 9.645 3.385 ;
			LAYER M1 ;
			RECT 8.025 3.16 8.365 3.205 ;
			LAYER M1 ;
			RECT 9.125 3.045 9.645 3.205 ;
			LAYER M1 ;
			RECT 9.125 2.815 9.355 3.045 ;
			LAYER M1 ;
			RECT 9.025 2.365 9.475 2.815 ;
		END
		AntennaGateArea 0.6552 ;
	END setb
	PIN clk
		DIRECTION input ;
		USE CLOCK ;
		PORT
			LAYER M1 ;
			RECT 5.325 3.495 5.775 3.555 ;
			LAYER M1 ;
			RECT 4.94 3.155 5.775 3.495 ;
			LAYER M1 ;
			RECT 5.325 3.105 5.775 3.155 ;
		END
		AntennaGateArea 0.6408 ;
	END clk
	OBS
		LAYER M1 ;
		RECT 0.18 4.91 0.52 6.03 ;
		LAYER M1 ;
		RECT 2.09 4.91 2.43 6.67 ;
		LAYER M1 ;
		RECT 5.7 6.405 6.04 6.555 ;
		LAYER M1 ;
		RECT 4.11 6.175 6.32 6.405 ;
		LAYER M1 ;
		RECT 4.11 5.75 4.34 6.175 ;
		LAYER M1 ;
		RECT 4 4.91 4.34 5.75 ;
		LAYER M1 ;
		RECT 4.7 4.93 5.04 5.77 ;
		LAYER M1 ;
		RECT 5.42 4.93 5.76 5.77 ;
		LAYER M1 ;
		RECT 0.18 4.22 0.41 4.91 ;
		LAYER M1 ;
		RECT 2.185 4.68 2.415 4.91 ;
		LAYER M1 ;
		RECT 4.7 4.68 4.93 4.93 ;
		LAYER M1 ;
		RECT 2.185 4.45 4.93 4.68 ;
		LAYER M1 ;
		RECT 0.18 3.99 2.71 4.22 ;
		LAYER M1 ;
		RECT 0.18 2.72 0.41 3.99 ;
		LAYER M1 ;
		RECT 2.37 3.88 2.71 3.99 ;
		LAYER M1 ;
		RECT 0.18 2.2 0.52 2.72 ;
		LAYER M1 ;
		RECT 3.08 2.33 3.31 4.45 ;
		LAYER M1 ;
		RECT 5.53 4.015 5.76 4.93 ;
		LAYER M1 ;
		RECT 6.09 4.475 6.32 6.175 ;
		LAYER M1 ;
		RECT 7.38 5.85 7.72 6.19 ;
		LAYER M1 ;
		RECT 7.435 5.27 7.665 5.85 ;
		LAYER M1 ;
		RECT 6.09 4.245 6.88 4.475 ;
		LAYER M1 ;
		RECT 5.53 3.785 6.355 4.015 ;
		LAYER M1 ;
		RECT 6.125 3.265 6.355 3.785 ;
		LAYER M1 ;
		RECT 6.08 2.925 6.42 3.265 ;
		LAYER M1 ;
		RECT 1.71 2.1 5.7 2.33 ;
		LAYER M1 ;
		RECT 6.125 2.27 6.355 2.925 ;
		LAYER M1 ;
		RECT 1.71 1.87 1.94 2.1 ;
		LAYER M1 ;
		RECT 1.6 1.03 1.94 1.87 ;
		LAYER M1 ;
		RECT 3.45 1.57 3.68 2.1 ;
		LAYER M1 ;
		RECT 5.36 1.93 5.7 2.1 ;
		LAYER M1 ;
		RECT 6.08 1.93 6.42 2.27 ;
		LAYER M1 ;
		RECT 6.65 1.57 6.88 4.245 ;
		LAYER M1 ;
		RECT 7.37 4.43 7.71 5.27 ;
		LAYER M1 ;
		RECT 8.92 5.98 11.04 6.21 ;
		LAYER M1 ;
		RECT 8.92 5.55 9.15 5.98 ;
		LAYER M1 ;
		RECT 8.81 4.43 9.15 5.55 ;
		LAYER M1 ;
		RECT 9.51 4.695 9.85 5.535 ;
		LAYER M1 ;
		RECT 10.23 4.695 10.57 5.535 ;
		LAYER M1 ;
		RECT 7.37 3.965 7.6 4.43 ;
		LAYER M1 ;
		RECT 9.515 3.965 9.745 4.695 ;
		LAYER M1 ;
		RECT 7.22 3.735 10.105 3.965 ;
		LAYER M1 ;
		RECT 7.22 2.745 7.45 3.735 ;
		LAYER M1 ;
		RECT 7.11 1.905 7.45 2.745 ;
		LAYER M1 ;
		RECT 9.875 2.805 10.105 3.735 ;
		LAYER M1 ;
		RECT 10.34 3.355 10.57 4.695 ;
		LAYER M1 ;
		RECT 10.81 3.95 11.04 5.98 ;
		LAYER M1 ;
		RECT 11.27 4.41 11.61 5.935 ;
		LAYER M1 ;
		RECT 14.03 5.61 14.37 5.72 ;
		LAYER M1 ;
		RECT 12.99 5.38 14.37 5.61 ;
		LAYER M1 ;
		RECT 12.99 4.41 13.22 5.38 ;
		LAYER M1 ;
		RECT 11.27 4.185 13.22 4.41 ;
		LAYER M1 ;
		RECT 13.45 4.39 13.79 4.73 ;
		LAYER M1 ;
		RECT 11.38 4.18 13.22 4.185 ;
		LAYER M1 ;
		RECT 10.81 3.72 12.52 3.95 ;
		LAYER M1 ;
		RECT 12.18 3.61 12.52 3.72 ;
		LAYER M1 ;
		RECT 10.34 3.125 11.925 3.355 ;
		LAYER M1 ;
		RECT 11.51 3.015 11.925 3.125 ;
		LAYER M1 ;
		RECT 9.875 2.575 11.205 2.805 ;
		LAYER M1 ;
		RECT 9.935 2.37 10.275 2.575 ;
		LAYER M1 ;
		RECT 10.975 2.405 11.205 2.575 ;
		LAYER M1 ;
		RECT 11.695 2.405 11.925 3.015 ;
		LAYER M1 ;
		RECT 10.975 2.065 11.315 2.405 ;
		LAYER M1 ;
		RECT 11.695 2.065 12.035 2.405 ;
		LAYER M1 ;
		RECT 3.45 1.19 3.79 1.57 ;
		LAYER M1 ;
		RECT 5.32 1.34 6.88 1.57 ;
		LAYER M1 ;
		RECT 5.32 1.19 6.18 1.34 ;
		LAYER M1 ;
		RECT 12.265 1.835 12.495 3.61 ;
		LAYER M1 ;
		RECT 9.025 1.565 9.365 1.705 ;
		LAYER M1 ;
		RECT 8.505 1.335 9.365 1.565 ;
		LAYER M1 ;
		RECT 8.505 1.225 8.845 1.335 ;
		LAYER M1 ;
		RECT 10.935 1.605 12.495 1.835 ;
		LAYER M1 ;
		RECT 10.935 1.185 11.275 1.605 ;
		LAYER M1 ;
		RECT 12.265 1.12 12.495 1.605 ;
		LAYER M1 ;
		RECT 12.835 2.06 13.065 4.18 ;
		LAYER M1 ;
		RECT 13.56 3.375 13.79 4.39 ;
		LAYER M1 ;
		RECT 14.85 3.64 15.19 3.7 ;
		LAYER M1 ;
		RECT 13.295 3.035 13.79 3.375 ;
		LAYER M1 ;
		RECT 13.56 2.855 13.79 3.035 ;
		LAYER M1 ;
		RECT 14.165 3.41 15.19 3.64 ;
		LAYER M1 ;
		RECT 13.56 2.515 13.925 2.855 ;
		LAYER M1 ;
		RECT 14.165 2.06 14.395 3.41 ;
		LAYER M1 ;
		RECT 14.85 3.36 15.19 3.41 ;
		LAYER M1 ;
		RECT 12.835 1.83 14.395 2.06 ;
		LAYER M1 ;
		RECT 12.835 1.6 13.065 1.83 ;
		LAYER M1 ;
		RECT 14.165 1.6 14.395 1.83 ;
		LAYER M1 ;
		RECT 12.155 0.78 12.495 1.12 ;
		LAYER M1 ;
		RECT 12.725 1.06 13.065 1.6 ;
		LAYER M1 ;
		RECT 14.165 1.06 14.505 1.6 ;
	END
END MMI_SFFPB
MACRO MMI_SFFRB
	CLASS CORE ;
	FOREIGN MMI_SFFRB 0 0 ;
	SIZE 16.28 BY 7.4 ;
	SYMMETRY X Y ;
	SITE CORE1 ;
	PIN d
		DIRECTION input ;
		USE SIGNAL ;
		PORT
			LAYER M1 ;
			RECT 1.625 3.105 2.075 3.555 ;
		END
		AntennaGateArea 0.4968 ;
	END d
	PIN GND
		DIRECTION inout ;
		USE GROUND ;
		PORT
			LAYER M1 ;
			RECT 0.94 0.5 1.28 2.175 ;
			LAYER M1 ;
			RECT 3.32 0.5 3.66 1.795 ;
			LAYER M1 ;
			RECT 6.32 1.5 6.7 1.84 ;
			LAYER M1 ;
			RECT 6.335 0.5 6.675 1.5 ;
			LAYER M1 ;
			RECT 7.88 0.5 8.22 2.28 ;
			LAYER M1 ;
			RECT 10.53 0.5 10.87 1.875 ;
			LAYER M1 ;
			RECT 13.085 0.5 13.425 2.64 ;
			LAYER M1 ;
			RECT 14.97 0.5 15.31 3.205 ;
			LAYER M1 ;
			RECT 0 -0.5 16.28 0.5 ;
		END
	END GND
	PIN q
		DIRECTION output ;
		USE SIGNAL ;
		PORT
			LAYER M1 ;
			RECT 15.69 2.365 16.03 6.67 ;
		END
		AntennaDiffArea 1.3248 ;
	END q
	PIN s_en
		DIRECTION input ;
		USE SIGNAL ;
		PORT
			LAYER M1 ;
			RECT 0.885 3.5 1.335 3.555 ;
			LAYER M1 ;
			RECT 0.66 3.425 1.335 3.5 ;
			LAYER M1 ;
			RECT 0.645 3.195 1.335 3.425 ;
			LAYER M1 ;
			RECT 0.66 3.16 1.335 3.195 ;
			LAYER M1 ;
			RECT 0.885 3.105 1.335 3.16 ;
		END
		AntennaGateArea 0.738 ;
	END s_en
	PIN s_in
		DIRECTION input ;
		USE SIGNAL ;
		PORT
			LAYER M1 ;
			RECT 2.365 3.105 2.815 3.555 ;
		END
		AntennaGateArea 0.2484 ;
	END s_in
	PIN VDD
		DIRECTION inout ;
		USE POWER ;
		PORT
			LAYER M1 ;
			RECT 0 6.9 16.28 7.9 ;
			LAYER M1 ;
			RECT 0.94 4.91 1.28 6.9 ;
			LAYER M1 ;
			RECT 3.28 4.91 3.62 6.9 ;
			LAYER M1 ;
			RECT 6.12 5.24 6.46 6.9 ;
			LAYER M1 ;
			RECT 7.58 4.56 7.92 6.9 ;
			LAYER M1 ;
			RECT 10.58 4.985 10.92 6.9 ;
			LAYER M1 ;
			RECT 13.235 4.91 13.575 6.9 ;
			LAYER M1 ;
			RECT 14.97 4.91 15.31 6.9 ;
		END
	END VDD
	PIN clk
		DIRECTION input ;
		USE CLOCK ;
		PORT
			LAYER M1 ;
			RECT 6.52 4.21 6.86 4.55 ;
			LAYER M1 ;
			RECT 6.63 3.43 6.86 4.21 ;
			LAYER M1 ;
			RECT 7.545 3.445 7.995 3.555 ;
			LAYER M1 ;
			RECT 7.34 3.43 7.995 3.445 ;
			LAYER M1 ;
			RECT 6.63 3.375 7.995 3.43 ;
			LAYER M1 ;
			RECT 6.63 3.2 9.3 3.375 ;
			LAYER M1 ;
			RECT 7.34 3.145 9.3 3.2 ;
			LAYER M1 ;
			RECT 7.34 3.105 7.995 3.145 ;
			LAYER M1 ;
			RECT 8.96 3.035 9.3 3.145 ;
		END
		AntennaGateArea 0.6408 ;
	END clk
	PIN clrb
		DIRECTION input ;
		USE SIGNAL ;
		PORT
			LAYER M1 ;
			RECT 3.56 3.555 3.9 3.56 ;
			LAYER M1 ;
			RECT 3.56 3.22 4.295 3.555 ;
			LAYER M1 ;
			RECT 3.845 3.105 4.295 3.22 ;
		END
		AntennaGateArea 0.7128 ;
	END clrb
	OBS
		LAYER M1 ;
		RECT 0.18 4.91 0.52 6.03 ;
		LAYER M1 ;
		RECT 2.09 4.91 2.43 6.67 ;
		LAYER M1 ;
		RECT 3.98 5.635 4.32 6.475 ;
		LAYER M1 ;
		RECT 4.7 5.635 5.04 6.475 ;
		LAYER M1 ;
		RECT 0.18 4.015 0.41 4.91 ;
		LAYER M1 ;
		RECT 2.15 4.625 2.38 4.91 ;
		LAYER M1 ;
		RECT 3.98 4.625 4.21 5.635 ;
		LAYER M1 ;
		RECT 2.15 4.395 4.21 4.625 ;
		LAYER M1 ;
		RECT 2.37 4.015 2.71 4.165 ;
		LAYER M1 ;
		RECT 0.18 3.785 2.71 4.015 ;
		LAYER M1 ;
		RECT 0.18 2.685 0.41 3.785 ;
		LAYER M1 ;
		RECT 3.05 2.875 3.28 4.395 ;
		LAYER M1 ;
		RECT 4.81 2.875 5.04 5.635 ;
		LAYER M1 ;
		RECT 5.4 5.24 5.74 6.36 ;
		LAYER M1 ;
		RECT 5.49 4.12 5.72 5.24 ;
		LAYER M1 ;
		RECT 6.88 5.01 7.22 6.075 ;
		LAYER M1 ;
		RECT 6.06 4.78 7.35 5.01 ;
		LAYER M1 ;
		RECT 5.49 3.78 5.83 4.12 ;
		LAYER M1 ;
		RECT 1.18 2.685 1.52 2.745 ;
		LAYER M1 ;
		RECT 0.18 2.455 1.52 2.685 ;
		LAYER M1 ;
		RECT 0.18 2.175 0.41 2.455 ;
		LAYER M1 ;
		RECT 1.18 2.405 1.52 2.455 ;
		LAYER M1 ;
		RECT 2.2 2.645 4.47 2.875 ;
		LAYER M1 ;
		RECT 2.2 2.175 2.43 2.645 ;
		LAYER M1 ;
		RECT 4.13 2.535 4.47 2.645 ;
		LAYER M1 ;
		RECT 4.81 2.535 5.19 2.875 ;
		LAYER M1 ;
		RECT 0.18 1.655 0.52 2.175 ;
		LAYER M1 ;
		RECT 2.09 1.335 2.43 2.175 ;
		LAYER M1 ;
		RECT 4.81 1.955 5.04 2.535 ;
		LAYER M1 ;
		RECT 4.81 1.71 5.37 1.955 ;
		LAYER M1 ;
		RECT 4.04 1.38 4.38 1.71 ;
		LAYER M1 ;
		RECT 5.03 1.615 5.37 1.71 ;
		LAYER M1 ;
		RECT 5.6 1.38 5.83 3.78 ;
		LAYER M1 ;
		RECT 6.06 3.215 6.29 4.78 ;
		LAYER M1 ;
		RECT 7.12 4.325 7.35 4.78 ;
		LAYER M1 ;
		RECT 8.21 6.19 10.01 6.42 ;
		LAYER M1 ;
		RECT 8.21 4.325 8.44 6.19 ;
		LAYER M1 ;
		RECT 9.67 6.08 10.01 6.19 ;
		LAYER M1 ;
		RECT 8.73 5.61 10.305 5.84 ;
		LAYER M1 ;
		RECT 8.73 4.56 9.07 5.61 ;
		LAYER M1 ;
		RECT 9.43 4.985 9.77 5.325 ;
		LAYER M1 ;
		RECT 7.12 4.095 8.44 4.325 ;
		LAYER M1 ;
		RECT 8.84 3.835 9.07 4.56 ;
		LAYER M1 ;
		RECT 9.54 4.295 9.77 4.985 ;
		LAYER M1 ;
		RECT 10.075 4.755 10.305 5.61 ;
		LAYER M1 ;
		RECT 11.28 4.91 11.62 5.75 ;
		LAYER M1 ;
		RECT 12 4.91 12.34 5.75 ;
		LAYER M1 ;
		RECT 13.955 4.91 14.295 5.75 ;
		LAYER M1 ;
		RECT 11.28 4.755 11.51 4.91 ;
		LAYER M1 ;
		RECT 10.075 4.525 11.51 4.755 ;
		LAYER M1 ;
		RECT 10.945 4.34 11.51 4.525 ;
		LAYER M1 ;
		RECT 12.11 4.515 12.34 4.91 ;
		LAYER M1 ;
		RECT 14.065 4.515 14.295 4.91 ;
		LAYER M1 ;
		RECT 15.04 4.515 15.38 4.58 ;
		LAYER M1 ;
		RECT 9.54 4.065 10.375 4.295 ;
		LAYER M1 ;
		RECT 10.035 4.015 10.375 4.065 ;
		LAYER M1 ;
		RECT 8.84 3.605 9.775 3.835 ;
		LAYER M1 ;
		RECT 10.035 3.785 10.855 4.015 ;
		LAYER M1 ;
		RECT 6.06 2.875 6.4 3.215 ;
		LAYER M1 ;
		RECT 6.06 2.56 6.29 2.875 ;
		LAYER M1 ;
		RECT 9.545 2.8 9.775 3.605 ;
		LAYER M1 ;
		RECT 10.05 2.8 10.39 2.945 ;
		LAYER M1 ;
		RECT 7.27 2.57 10.39 2.8 ;
		LAYER M1 ;
		RECT 6.06 2.33 6.7 2.56 ;
		LAYER M1 ;
		RECT 6.32 2.22 6.7 2.33 ;
		LAYER M1 ;
		RECT 7.27 2.28 7.5 2.57 ;
		LAYER M1 ;
		RECT 7.16 1.9 7.5 2.28 ;
		LAYER M1 ;
		RECT 4.04 1.15 5.83 1.38 ;
		LAYER M1 ;
		RECT 8.71 2.11 8.94 2.57 ;
		LAYER M1 ;
		RECT 10.625 2.34 10.855 3.785 ;
		LAYER M1 ;
		RECT 11.28 2.64 11.51 4.34 ;
		LAYER M1 ;
		RECT 12 4.285 12.34 4.515 ;
		LAYER M1 ;
		RECT 12.705 4.285 15.38 4.515 ;
		LAYER M1 ;
		RECT 12 3.745 12.23 4.285 ;
		LAYER M1 ;
		RECT 12.705 3.985 13.045 4.285 ;
		LAYER M1 ;
		RECT 13.815 3.745 14.155 3.87 ;
		LAYER M1 ;
		RECT 12 3.515 14.155 3.745 ;
		LAYER M1 ;
		RECT 12 2.64 12.23 3.515 ;
		LAYER M1 ;
		RECT 14.395 2.64 14.625 4.285 ;
		LAYER M1 ;
		RECT 15.04 4.24 15.38 4.285 ;
		LAYER M1 ;
		RECT 9.49 2.11 10.855 2.34 ;
		LAYER M1 ;
		RECT 11.17 2.3 11.51 2.64 ;
		LAYER M1 ;
		RECT 11.89 2.3 12.23 2.64 ;
		LAYER M1 ;
		RECT 8.68 1.73 9.02 2.11 ;
		LAYER M1 ;
		RECT 9.49 1.875 9.72 2.11 ;
		LAYER M1 ;
		RECT 9.38 1.535 9.72 1.875 ;
		LAYER M1 ;
		RECT 14.235 2.26 14.625 2.64 ;
		LAYER M1 ;
		RECT 14.235 1.48 14.575 2.26 ;
	END
END MMI_SFFRB
MACRO MMI_SFFSB
	CLASS CORE ;
	FOREIGN MMI_SFFSB 0 0 ;
	SIZE 17.76 BY 7.4 ;
	SYMMETRY X Y ;
	SITE CORE1 ;
	PIN d
		DIRECTION input ;
		USE SIGNAL ;
		PORT
			LAYER M1 ;
			RECT 1.79 3.435 2.13 3.465 ;
			LAYER M1 ;
			RECT 2.365 3.435 2.815 3.555 ;
			LAYER M1 ;
			RECT 1.79 3.205 2.815 3.435 ;
			LAYER M1 ;
			RECT 1.79 3.125 2.13 3.205 ;
			LAYER M1 ;
			RECT 2.365 3.105 2.815 3.205 ;
		END
		AntennaGateArea 0.4968 ;
	END d
	PIN GND
		DIRECTION inout ;
		USE GROUND ;
		PORT
			LAYER M1 ;
			RECT 7.905 1.905 8.6 2.745 ;
			LAYER M1 ;
			RECT 0.9 0.5 1.24 1.82 ;
			LAYER M1 ;
			RECT 2.75 0.5 3.09 1.87 ;
			LAYER M1 ;
			RECT 4.6 0.5 4.94 1.57 ;
			LAYER M1 ;
			RECT 7.905 0.5 8.245 1.905 ;
			LAYER M1 ;
			RECT 10.215 0.5 10.555 1.705 ;
			LAYER M1 ;
			RECT 13.445 0.5 13.785 1.6 ;
			LAYER M1 ;
			RECT 14.735 0.5 15.075 2.855 ;
			LAYER M1 ;
			RECT 16.495 0.5 16.835 1.8 ;
			LAYER M1 ;
			RECT 0 -0.5 17.76 0.5 ;
		END
	END GND
	PIN q
		DIRECTION output ;
		USE SIGNAL ;
		PORT
			LAYER M1 ;
			RECT 16.84 4.73 17.18 6.15 ;
			LAYER M1 ;
			RECT 16.84 4.39 17.19 4.73 ;
			LAYER M1 ;
			RECT 16.96 3.555 17.19 4.39 ;
			LAYER M1 ;
			RECT 16.96 3.11 17.56 3.555 ;
			LAYER M1 ;
			RECT 17.265 1.8 17.495 3.11 ;
			LAYER M1 ;
			RECT 17.215 0.96 17.555 1.8 ;
		END
		AntennaDiffArea 1.3248 ;
	END q
	PIN s_in
		DIRECTION input ;
		USE SIGNAL ;
		PORT
			LAYER M1 ;
			RECT 3.845 3.105 4.295 3.555 ;
		END
		AntennaGateArea 0.2484 ;
	END s_in
	PIN s_en
		DIRECTION input ;
		USE SIGNAL ;
		PORT
			LAYER M1 ;
			RECT 0.885 3.5 1.335 3.555 ;
			LAYER M1 ;
			RECT 0.66 3.16 1.335 3.5 ;
			LAYER M1 ;
			RECT 0.885 3.105 1.335 3.16 ;
		END
		AntennaGateArea 1.0404 ;
	END s_en
	PIN VDD
		DIRECTION inout ;
		USE POWER ;
		PORT
			LAYER M1 ;
			RECT 0 6.9 17.76 7.9 ;
			LAYER M1 ;
			RECT 0.94 4.91 1.28 6.9 ;
			LAYER M1 ;
			RECT 3.28 4.91 3.62 6.9 ;
			LAYER M1 ;
			RECT 6.65 4.705 6.99 6.9 ;
			LAYER M1 ;
			RECT 8.09 4.43 8.43 6.9 ;
			LAYER M1 ;
			RECT 12.42 4.66 12.76 6.9 ;
			LAYER M1 ;
			RECT 14.64 4.39 14.98 6.9 ;
			LAYER M1 ;
			RECT 16.12 4.39 16.46 6.9 ;
		END
	END VDD
	PIN s_out
		DIRECTION output ;
		USE SIGNAL ;
		PORT
			LAYER M1 ;
			RECT 15.36 4.39 15.7 5.15 ;
			LAYER M1 ;
			RECT 15.47 3.555 15.7 4.39 ;
			LAYER M1 ;
			RECT 15.47 3.17 16.135 3.555 ;
			LAYER M1 ;
			RECT 15.645 3.105 16.135 3.17 ;
			LAYER M1 ;
			RECT 15.685 2.305 15.915 3.105 ;
			LAYER M1 ;
			RECT 15.415 2.075 15.915 2.305 ;
			LAYER M1 ;
			RECT 15.415 1.8 15.645 2.075 ;
			LAYER M1 ;
			RECT 15.305 1.04 15.645 1.8 ;
		END
		AntennaDiffArea 0.8568 ;
	END s_out
	PIN setb
		DIRECTION input ;
		USE SIGNAL ;
		PORT
			LAYER M1 ;
			RECT 8.025 3.435 8.365 3.5 ;
			LAYER M1 ;
			RECT 8.025 3.385 9.355 3.435 ;
			LAYER M1 ;
			RECT 8.025 3.205 9.645 3.385 ;
			LAYER M1 ;
			RECT 8.025 3.16 8.365 3.205 ;
			LAYER M1 ;
			RECT 9.125 3.045 9.645 3.205 ;
			LAYER M1 ;
			RECT 9.125 2.815 9.355 3.045 ;
			LAYER M1 ;
			RECT 9.025 2.365 9.475 2.815 ;
		END
		AntennaGateArea 0.6552 ;
	END setb
	PIN clk
		DIRECTION input ;
		USE CLOCK ;
		PORT
			LAYER M1 ;
			RECT 5.325 3.495 5.775 3.555 ;
			LAYER M1 ;
			RECT 4.94 3.155 5.775 3.495 ;
			LAYER M1 ;
			RECT 5.325 3.105 5.775 3.155 ;
		END
		AntennaGateArea 0.6408 ;
	END clk
	OBS
		LAYER M1 ;
		RECT 0.18 4.91 0.52 6.03 ;
		LAYER M1 ;
		RECT 2.09 4.91 2.43 6.67 ;
		LAYER M1 ;
		RECT 5.7 6.405 6.04 6.555 ;
		LAYER M1 ;
		RECT 4.11 6.175 6.32 6.405 ;
		LAYER M1 ;
		RECT 4.11 5.75 4.34 6.175 ;
		LAYER M1 ;
		RECT 4 4.91 4.34 5.75 ;
		LAYER M1 ;
		RECT 4.7 4.93 5.04 5.77 ;
		LAYER M1 ;
		RECT 5.42 4.93 5.76 5.77 ;
		LAYER M1 ;
		RECT 0.18 4.22 0.41 4.91 ;
		LAYER M1 ;
		RECT 2.185 4.68 2.415 4.91 ;
		LAYER M1 ;
		RECT 4.7 4.68 4.93 4.93 ;
		LAYER M1 ;
		RECT 2.185 4.45 4.93 4.68 ;
		LAYER M1 ;
		RECT 0.18 3.99 2.71 4.22 ;
		LAYER M1 ;
		RECT 0.18 1.82 0.41 3.99 ;
		LAYER M1 ;
		RECT 2.37 3.88 2.71 3.99 ;
		LAYER M1 ;
		RECT 3.08 2.33 3.31 4.45 ;
		LAYER M1 ;
		RECT 5.53 4.015 5.76 4.93 ;
		LAYER M1 ;
		RECT 6.09 4.475 6.32 6.175 ;
		LAYER M1 ;
		RECT 7.38 5.85 7.72 6.19 ;
		LAYER M1 ;
		RECT 7.435 5.27 7.665 5.85 ;
		LAYER M1 ;
		RECT 6.09 4.245 6.88 4.475 ;
		LAYER M1 ;
		RECT 5.53 3.785 6.355 4.015 ;
		LAYER M1 ;
		RECT 6.125 3.265 6.355 3.785 ;
		LAYER M1 ;
		RECT 6.08 2.925 6.42 3.265 ;
		LAYER M1 ;
		RECT 1.71 2.1 5.7 2.33 ;
		LAYER M1 ;
		RECT 6.125 2.27 6.355 2.925 ;
		LAYER M1 ;
		RECT 1.71 1.87 1.94 2.1 ;
		LAYER M1 ;
		RECT 0.18 1.3 0.52 1.82 ;
		LAYER M1 ;
		RECT 0.18 1.18 0.41 1.3 ;
		LAYER M1 ;
		RECT 1.6 1.03 1.94 1.87 ;
		LAYER M1 ;
		RECT 3.45 1.57 3.68 2.1 ;
		LAYER M1 ;
		RECT 5.36 1.93 5.7 2.1 ;
		LAYER M1 ;
		RECT 6.08 1.93 6.42 2.27 ;
		LAYER M1 ;
		RECT 6.65 1.57 6.88 4.245 ;
		LAYER M1 ;
		RECT 7.37 4.43 7.71 5.27 ;
		LAYER M1 ;
		RECT 8.92 5.98 11.04 6.21 ;
		LAYER M1 ;
		RECT 8.92 5.55 9.15 5.98 ;
		LAYER M1 ;
		RECT 8.81 4.43 9.15 5.55 ;
		LAYER M1 ;
		RECT 9.51 4.695 9.85 5.535 ;
		LAYER M1 ;
		RECT 10.23 4.695 10.57 5.535 ;
		LAYER M1 ;
		RECT 7.37 3.965 7.6 4.43 ;
		LAYER M1 ;
		RECT 9.515 3.965 9.745 4.695 ;
		LAYER M1 ;
		RECT 7.22 3.735 10.105 3.965 ;
		LAYER M1 ;
		RECT 7.22 2.745 7.45 3.735 ;
		LAYER M1 ;
		RECT 7.11 1.905 7.45 2.745 ;
		LAYER M1 ;
		RECT 9.875 2.805 10.105 3.735 ;
		LAYER M1 ;
		RECT 10.34 3.355 10.57 4.695 ;
		LAYER M1 ;
		RECT 10.81 3.95 11.04 5.98 ;
		LAYER M1 ;
		RECT 11.27 4.41 11.61 5.935 ;
		LAYER M1 ;
		RECT 14.03 5.61 14.37 5.72 ;
		LAYER M1 ;
		RECT 12.99 5.38 14.37 5.61 ;
		LAYER M1 ;
		RECT 12.99 4.41 13.22 5.38 ;
		LAYER M1 ;
		RECT 11.27 4.185 13.22 4.41 ;
		LAYER M1 ;
		RECT 13.45 4.39 13.79 4.73 ;
		LAYER M1 ;
		RECT 11.38 4.18 13.22 4.185 ;
		LAYER M1 ;
		RECT 10.81 3.72 12.52 3.95 ;
		LAYER M1 ;
		RECT 12.18 3.61 12.52 3.72 ;
		LAYER M1 ;
		RECT 10.34 3.125 11.925 3.355 ;
		LAYER M1 ;
		RECT 11.51 3.015 11.925 3.125 ;
		LAYER M1 ;
		RECT 9.875 2.575 11.205 2.805 ;
		LAYER M1 ;
		RECT 9.935 2.37 10.275 2.575 ;
		LAYER M1 ;
		RECT 10.975 2.405 11.205 2.575 ;
		LAYER M1 ;
		RECT 11.695 2.405 11.925 3.015 ;
		LAYER M1 ;
		RECT 10.975 2.065 11.315 2.405 ;
		LAYER M1 ;
		RECT 11.695 2.065 12.035 2.405 ;
		LAYER M1 ;
		RECT 3.45 1.19 3.79 1.57 ;
		LAYER M1 ;
		RECT 5.32 1.34 6.88 1.57 ;
		LAYER M1 ;
		RECT 5.32 1.19 6.18 1.34 ;
		LAYER M1 ;
		RECT 12.265 1.835 12.495 3.61 ;
		LAYER M1 ;
		RECT 9.025 1.565 9.365 1.705 ;
		LAYER M1 ;
		RECT 8.505 1.335 9.365 1.565 ;
		LAYER M1 ;
		RECT 8.505 1.225 8.845 1.335 ;
		LAYER M1 ;
		RECT 10.935 1.605 12.495 1.835 ;
		LAYER M1 ;
		RECT 10.935 1.185 11.275 1.605 ;
		LAYER M1 ;
		RECT 12.265 1.12 12.495 1.605 ;
		LAYER M1 ;
		RECT 12.835 2.06 13.065 4.18 ;
		LAYER M1 ;
		RECT 13.56 3.375 13.79 4.39 ;
		LAYER M1 ;
		RECT 13.295 3.035 13.79 3.375 ;
		LAYER M1 ;
		RECT 14.495 3.365 14.835 3.475 ;
		LAYER M1 ;
		RECT 13.56 2.855 13.79 3.035 ;
		LAYER M1 ;
		RECT 14.165 3.135 14.835 3.365 ;
		LAYER M1 ;
		RECT 13.56 2.515 13.925 2.855 ;
		LAYER M1 ;
		RECT 14.165 2.06 14.395 3.135 ;
		LAYER M1 ;
		RECT 12.835 1.83 14.395 2.06 ;
		LAYER M1 ;
		RECT 12.835 1.6 13.065 1.83 ;
		LAYER M1 ;
		RECT 14.165 1.6 14.395 1.83 ;
		LAYER M1 ;
		RECT 12.155 0.78 12.495 1.12 ;
		LAYER M1 ;
		RECT 12.725 1.06 13.065 1.6 ;
		LAYER M1 ;
		RECT 14.165 1.06 14.505 1.6 ;
	END
END MMI_SFFSB
MACRO MMI_TSBUFC
	CLASS CORE ;
	FOREIGN MMI_TSBUFC 0 0 ;
	SIZE 5.18 BY 7.4 ;
	SYMMETRY X Y ;
	SITE CORE1 ;
	PIN out
		DIRECTION output ;
		USE SIGNAL ;
		PORT
			LAYER M1 ;
			RECT 3.84 4.43 4.18 6.19 ;
			LAYER M1 ;
			RECT 3.93 3.555 4.16 4.43 ;
			LAYER M1 ;
			RECT 3.845 3.105 4.25 3.555 ;
			LAYER M1 ;
			RECT 3.93 2.555 4.16 3.105 ;
			LAYER M1 ;
			RECT 3.84 1.715 4.18 2.555 ;
		END
		AntennaDiffArea 1.4904 ;
	END out
	PIN GND
		DIRECTION inout ;
		USE GROUND ;
		PORT
			LAYER M1 ;
			RECT 0.94 0.5 1.28 2.285 ;
			LAYER M1 ;
			RECT 3.12 0.5 3.46 2.555 ;
			LAYER M1 ;
			RECT 4.56 0.5 4.9 2.555 ;
			LAYER M1 ;
			RECT 0 -0.5 5.18 0.5 ;
		END
	END GND
	PIN enb
		DIRECTION input ;
		USE SIGNAL ;
		PORT
			LAYER M1 ;
			RECT 0.885 3.5 1.335 3.555 ;
			LAYER M1 ;
			RECT 0.64 3.16 1.335 3.5 ;
			LAYER M1 ;
			RECT 0.885 3.105 1.335 3.16 ;
		END
		AntennaGateArea 0.2268 ;
	END enb
	PIN VDD
		DIRECTION inout ;
		USE POWER ;
		PORT
			LAYER M1 ;
			RECT 0 6.9 5.18 7.9 ;
			LAYER M1 ;
			RECT 1.66 4.53 2 6.9 ;
			LAYER M1 ;
			RECT 3.12 4.43 3.46 6.9 ;
			LAYER M1 ;
			RECT 4.56 4.43 4.9 6.9 ;
		END
	END VDD
	PIN en
		DIRECTION input ;
		USE SIGNAL ;
		PORT
			LAYER M1 ;
			RECT 3.105 3.49 3.555 3.555 ;
			LAYER M1 ;
			RECT 2.89 3.15 3.555 3.49 ;
			LAYER M1 ;
			RECT 3.105 3.105 3.555 3.15 ;
		END
		AntennaGateArea 0.2268 ;
	END en
	PIN in
		DIRECTION input ;
		USE SIGNAL ;
		PORT
			LAYER M1 ;
			RECT 1.625 3.5 2.075 3.555 ;
			LAYER M1 ;
			RECT 1.565 3.16 2.075 3.5 ;
			LAYER M1 ;
			RECT 1.625 3.105 2.075 3.16 ;
		END
		AntennaGateArea 0.4536 ;
	END in
	OBS
		LAYER M1 ;
		RECT 0.18 4.53 0.52 5.29 ;
		LAYER M1 ;
		RECT 0.94 4.53 1.28 6.13 ;
		LAYER M1 ;
		RECT 2.42 4.53 2.76 5.29 ;
		LAYER M1 ;
		RECT 0.18 2.755 0.41 4.53 ;
		LAYER M1 ;
		RECT 1.05 4.135 1.28 4.53 ;
		LAYER M1 ;
		RECT 2.42 4.135 2.65 4.53 ;
		LAYER M1 ;
		RECT 3.185 4.135 3.525 4.19 ;
		LAYER M1 ;
		RECT 1.05 3.905 3.525 4.135 ;
		LAYER M1 ;
		RECT 1.66 2.755 1.89 2.76 ;
		LAYER M1 ;
		RECT 0.18 2.525 1.89 2.755 ;
		LAYER M1 ;
		RECT 0.18 2.285 0.41 2.525 ;
		LAYER M1 ;
		RECT 1.66 2.285 1.89 2.525 ;
		LAYER M1 ;
		RECT 2.42 2.285 2.65 3.905 ;
		LAYER M1 ;
		RECT 3.185 3.85 3.525 3.905 ;
		LAYER M1 ;
		RECT 0.18 1.945 0.52 2.285 ;
		LAYER M1 ;
		RECT 1.66 1.525 2 2.285 ;
		LAYER M1 ;
		RECT 2.42 1.945 2.76 2.285 ;
		LAYER M1 ;
		RECT 1.77 1.36 2 1.525 ;
		LAYER M1 ;
		RECT 1.77 1.13 2.85 1.36 ;
		LAYER M1 ;
		RECT 2.51 1.02 2.85 1.13 ;
	END
END MMI_TSBUFC
MACRO MMI_TSBUFE
	CLASS CORE ;
	FOREIGN MMI_TSBUFE 0 0 ;
	SIZE 8.88 BY 7.4 ;
	SYMMETRY X Y ;
	SITE CORE1 ;
	PIN out
		DIRECTION output ;
		USE SIGNAL ;
		PORT
			LAYER M1 ;
			RECT 3.82 4.525 4.16 6.67 ;
			LAYER M1 ;
			RECT 5.26 4.65 5.6 6.67 ;
			LAYER M1 ;
			RECT 6.7 4.65 7.04 6.67 ;
			LAYER M1 ;
			RECT 5.26 4.525 7.04 4.65 ;
			LAYER M1 ;
			RECT 3.82 4.295 7.04 4.525 ;
			LAYER M1 ;
			RECT 6.17 3.555 6.51 4.295 ;
			LAYER M1 ;
			RECT 6.065 3.135 6.515 3.555 ;
			LAYER M1 ;
			RECT 4.48 2.905 7.7 3.135 ;
			LAYER M1 ;
			RECT 4.48 1.82 4.82 2.905 ;
			LAYER M1 ;
			RECT 5.92 1.82 6.26 2.905 ;
			LAYER M1 ;
			RECT 7.36 1.82 7.7 2.905 ;
		END
		AntennaDiffArea 5.9616 ;
	END out
	PIN GND
		DIRECTION inout ;
		USE GROUND ;
		PORT
			LAYER M1 ;
			RECT 0.18 0.5 0.52 2.36 ;
			LAYER M1 ;
			RECT 1.62 0.5 1.96 2.36 ;
			LAYER M1 ;
			RECT 3.76 1.55 4.1 2.965 ;
			LAYER M1 ;
			RECT 5.2 1.55 5.54 2.16 ;
			LAYER M1 ;
			RECT 3.76 1.32 5.54 1.55 ;
			LAYER M1 ;
			RECT 5.2 0.5 5.54 1.32 ;
			LAYER M1 ;
			RECT 6.64 0.5 6.98 2.16 ;
			LAYER M1 ;
			RECT 8.08 0.5 8.42 2.965 ;
			LAYER M1 ;
			RECT 0 -0.5 8.88 0.5 ;
		END
	END GND
	PIN enb
		DIRECTION input ;
		USE SIGNAL ;
		PORT
			LAYER M1 ;
			RECT 0.885 3.105 1.335 3.555 ;
		END
		AntennaGateArea 0.5832 ;
	END enb
	PIN VDD
		DIRECTION inout ;
		USE POWER ;
		PORT
			LAYER M1 ;
			RECT 0 6.9 8.88 7.9 ;
			LAYER M1 ;
			RECT 1.62 4.935 1.96 6.9 ;
			LAYER M1 ;
			RECT 3.1 4.915 3.44 6.9 ;
			LAYER M1 ;
			RECT 4.54 4.915 4.88 6.9 ;
			LAYER M1 ;
			RECT 5.98 4.915 6.32 6.9 ;
			LAYER M1 ;
			RECT 7.42 4.295 7.76 6.9 ;
		END
	END VDD
	PIN en
		DIRECTION input ;
		USE SIGNAL ;
		PORT
			LAYER M1 ;
			RECT 2.365 3.105 2.815 3.555 ;
		END
		AntennaGateArea 0.5832 ;
	END en
	PIN in
		DIRECTION input ;
		USE SIGNAL ;
		PORT
			LAYER M1 ;
			RECT 1.625 3.105 2.075 3.555 ;
		END
		AntennaGateArea 1.1664 ;
	END in
	OBS
		LAYER M1 ;
		RECT 0.18 4.295 0.52 6.215 ;
		LAYER M1 ;
		RECT 0.9 4.525 1.24 6.215 ;
		LAYER M1 ;
		RECT 2.34 4.525 2.68 6.215 ;
		LAYER M1 ;
		RECT 0.9 4.295 3.4 4.525 ;
		LAYER M1 ;
		RECT 0.24 2.825 0.47 4.295 ;
		LAYER M1 ;
		RECT 3.17 3.825 3.4 4.295 ;
		LAYER M1 ;
		RECT 4.355 3.825 5.635 3.935 ;
		LAYER M1 ;
		RECT 3.17 3.595 5.635 3.825 ;
		LAYER M1 ;
		RECT 0.24 2.595 2.62 2.825 ;
		LAYER M1 ;
		RECT 0.95 2.36 1.18 2.595 ;
		LAYER M1 ;
		RECT 2.39 2.36 2.62 2.595 ;
		LAYER M1 ;
		RECT 3.17 2.36 3.4 3.595 ;
		LAYER M1 ;
		RECT 0.9 1.2 1.24 2.36 ;
		LAYER M1 ;
		RECT 2.34 1.2 2.68 2.36 ;
		LAYER M1 ;
		RECT 3.06 1.2 3.4 2.36 ;
		LAYER M1 ;
		RECT 2.4 0.97 2.63 1.2 ;
		LAYER M1 ;
		RECT 3.925 0.97 4.735 1.075 ;
		LAYER M1 ;
		RECT 2.4 0.74 4.735 0.97 ;
		LAYER M1 ;
		RECT 3.925 0.735 4.735 0.74 ;
	END
END MMI_TSBUFE
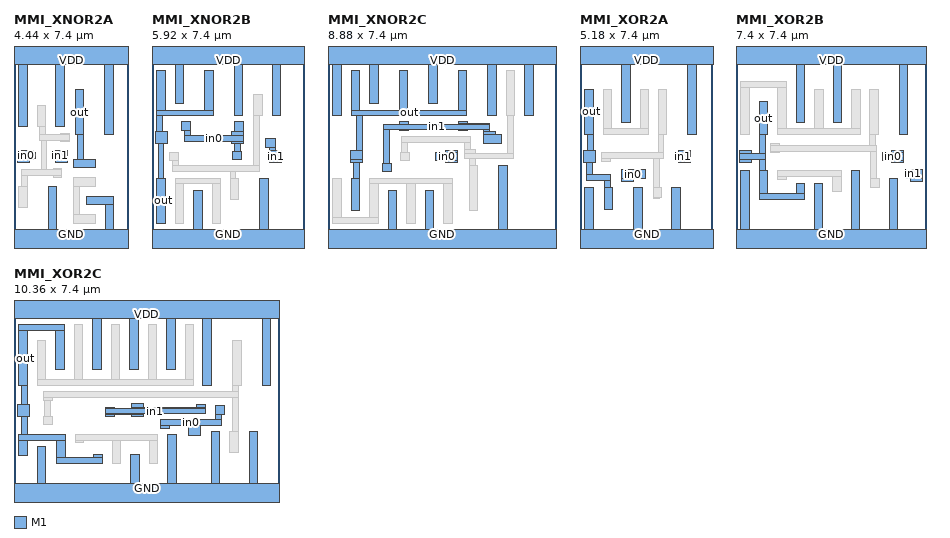
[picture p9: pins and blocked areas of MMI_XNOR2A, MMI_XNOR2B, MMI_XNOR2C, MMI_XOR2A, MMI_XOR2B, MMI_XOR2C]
MACRO MMI_XNOR2A
	CLASS CORE ;
	FOREIGN MMI_XNOR2A 0 0 ;
	SIZE 4.44 BY 7.4 ;
	SYMMETRY X Y ;
	SITE CORE1 ;
	PIN out
		DIRECTION output ;
		USE SIGNAL ;
		PORT
			LAYER M1 ;
			RECT 2.38 4.18 2.72 5.94 ;
			LAYER M1 ;
			RECT 2.47 3.23 2.7 4.18 ;
			LAYER M1 ;
			RECT 2.325 2.89 3.165 3.23 ;
		END
		AntennaDiffArea 1.4168 ;
	END out
	PIN in1
		DIRECTION input ;
		USE SIGNAL ;
		PORT
			LAYER M1 ;
			RECT 1.625 3.55 2.075 3.555 ;
			LAYER M1 ;
			RECT 1.515 3.21 2.075 3.55 ;
			LAYER M1 ;
			RECT 1.625 3.105 2.075 3.21 ;
		END
		AntennaGateArea 0.828 ;
	END in1
	PIN GND
		DIRECTION inout ;
		USE GROUND ;
		PORT
			LAYER M1 ;
			RECT 1.33 0.5 1.67 2.175 ;
			LAYER M1 ;
			RECT 2.825 1.45 3.885 1.79 ;
			LAYER M1 ;
			RECT 3.545 0.5 3.885 1.45 ;
			LAYER M1 ;
			RECT 0 -0.5 4.44 0.5 ;
		END
	END GND
	PIN VDD
		DIRECTION inout ;
		USE POWER ;
		PORT
			LAYER M1 ;
			RECT 0 6.9 4.44 7.9 ;
			LAYER M1 ;
			RECT 0.18 4.48 0.52 6.9 ;
			LAYER M1 ;
			RECT 1.62 4.48 1.96 6.9 ;
			LAYER M1 ;
			RECT 3.53 4.18 3.87 6.9 ;
		END
	END VDD
	PIN in0
		DIRECTION input ;
		USE SIGNAL ;
		PORT
			LAYER M1 ;
			RECT 0.145 3.55 0.595 3.555 ;
			LAYER M1 ;
			RECT 0.145 3.495 0.76 3.55 ;
			LAYER M1 ;
			RECT 0.145 3.265 0.825 3.495 ;
			LAYER M1 ;
			RECT 0.145 3.21 0.76 3.265 ;
			LAYER M1 ;
			RECT 0.145 3.105 0.595 3.21 ;
		END
		AntennaGateArea 0.828 ;
	END in0
	OBS
		LAYER M1 ;
		RECT 0.9 4.48 1.24 5.32 ;
		LAYER M1 ;
		RECT 1.01 4.185 1.24 4.48 ;
		LAYER M1 ;
		RECT 1.81 4.185 2.15 4.24 ;
		LAYER M1 ;
		RECT 1.01 3.955 2.15 4.185 ;
		LAYER M1 ;
		RECT 1.055 2.805 1.285 3.955 ;
		LAYER M1 ;
		RECT 1.81 3.9 2.15 3.955 ;
		LAYER M1 ;
		RECT 1.52 2.805 1.86 2.86 ;
		LAYER M1 ;
		RECT 0.29 2.575 1.86 2.805 ;
		LAYER M1 ;
		RECT 0.29 2.175 0.52 2.575 ;
		LAYER M1 ;
		RECT 1.52 2.52 1.86 2.575 ;
		LAYER M1 ;
		RECT 0.18 1.335 0.52 2.175 ;
		LAYER M1 ;
		RECT 2.325 2.17 3.165 2.51 ;
		LAYER M1 ;
		RECT 2.325 1.07 2.555 2.17 ;
		LAYER M1 ;
		RECT 2.325 0.73 3.165 1.07 ;
	END
END MMI_XNOR2A
MACRO MMI_XNOR2B
	CLASS CORE ;
	FOREIGN MMI_XNOR2B 0 0 ;
	SIZE 5.92 BY 7.4 ;
	SYMMETRY X Y ;
	SITE CORE1 ;
	PIN out
		DIRECTION output ;
		USE SIGNAL ;
		PORT
			LAYER M1 ;
			RECT 0.18 5.14 0.52 6.67 ;
			LAYER M1 ;
			RECT 2.05 5.14 2.39 6.67 ;
			LAYER M1 ;
			RECT 0.18 4.91 2.39 5.14 ;
			LAYER M1 ;
			RECT 0.18 4.295 0.41 4.91 ;
			LAYER M1 ;
			RECT 0.145 3.845 0.595 4.295 ;
			LAYER M1 ;
			RECT 0.235 2.49 0.465 3.845 ;
			LAYER M1 ;
			RECT 0.18 0.73 0.52 2.49 ;
		END
		AntennaDiffArea 2.76 ;
	END out
	PIN in1
		DIRECTION input ;
		USE SIGNAL ;
		PORT
			LAYER M1 ;
			RECT 4.425 3.695 4.815 4.035 ;
			LAYER M1 ;
			RECT 4.585 3.555 4.815 3.695 ;
			LAYER M1 ;
			RECT 4.585 3.105 5.035 3.555 ;
		END
		AntennaGateArea 1.3248 ;
	END in1
	PIN GND
		DIRECTION inout ;
		USE GROUND ;
		PORT
			LAYER M1 ;
			RECT 1.62 0.5 1.96 2.01 ;
			LAYER M1 ;
			RECT 4.19 0.5 4.53 2.49 ;
			LAYER M1 ;
			RECT 0 -0.5 5.92 0.5 ;
		END
	END GND
	PIN VDD
		DIRECTION inout ;
		USE POWER ;
		PORT
			LAYER M1 ;
			RECT 0 6.9 5.92 7.9 ;
			LAYER M1 ;
			RECT 0.9 5.39 1.24 6.9 ;
			LAYER M1 ;
			RECT 3.2 4.91 3.54 6.9 ;
			LAYER M1 ;
			RECT 4.68 4.91 5.02 6.9 ;
		END
	END VDD
	PIN in0
		DIRECTION input ;
		USE SIGNAL ;
		PORT
			LAYER M1 ;
			RECT 1.14 4.335 1.48 4.675 ;
			LAYER M1 ;
			RECT 1.25 4.135 1.48 4.335 ;
			LAYER M1 ;
			RECT 3.205 4.295 3.545 4.675 ;
			LAYER M1 ;
			RECT 3.105 4.135 3.555 4.295 ;
			LAYER M1 ;
			RECT 1.25 3.905 3.555 4.135 ;
			LAYER M1 ;
			RECT 3.105 3.845 3.555 3.905 ;
			LAYER M1 ;
			RECT 3.23 3.54 3.46 3.845 ;
			LAYER M1 ;
			RECT 3.145 3.2 3.485 3.54 ;
		END
		AntennaGateArea 1.3248 ;
	END in0
	OBS
		LAYER M1 ;
		RECT 3.96 4.91 4.3 5.75 ;
		LAYER M1 ;
		RECT 0.695 3.16 1.035 3.5 ;
		LAYER M1 ;
		RECT 0.805 2.965 1.035 3.16 ;
		LAYER M1 ;
		RECT 3.96 2.965 4.19 4.91 ;
		LAYER M1 ;
		RECT 0.805 2.735 4.19 2.965 ;
		LAYER M1 ;
		RECT 3.04 2.49 3.27 2.735 ;
		LAYER M1 ;
		RECT 0.9 2.26 2.68 2.49 ;
		LAYER M1 ;
		RECT 0.9 0.73 1.24 2.26 ;
		LAYER M1 ;
		RECT 2.34 0.73 2.68 2.26 ;
		LAYER M1 ;
		RECT 3.04 1.65 3.38 2.49 ;
	END
END MMI_XNOR2B
MACRO MMI_XNOR2C
	CLASS CORE ;
	FOREIGN MMI_XNOR2C 0 0 ;
	SIZE 8.88 BY 7.4 ;
	SYMMETRY X Y ;
	SITE CORE1 ;
	PIN out
		DIRECTION output ;
		USE SIGNAL ;
		PORT
			LAYER M1 ;
			RECT 0.9 5.14 1.24 6.67 ;
			LAYER M1 ;
			RECT 2.77 5.14 3.11 6.67 ;
			LAYER M1 ;
			RECT 5.07 5.14 5.41 6.67 ;
			LAYER M1 ;
			RECT 0.9 4.91 5.41 5.14 ;
			LAYER M1 ;
			RECT 1.125 3.555 1.355 4.91 ;
			LAYER M1 ;
			RECT 0.885 3.215 1.355 3.555 ;
			LAYER M1 ;
			RECT 0.885 3.105 1.335 3.215 ;
			LAYER M1 ;
			RECT 1.01 2.49 1.24 3.105 ;
			LAYER M1 ;
			RECT 0.9 1.21 1.24 2.49 ;
		END
		AntennaDiffArea 3.9744 ;
	END out
	PIN in1
		DIRECTION input ;
		USE SIGNAL ;
		PORT
			LAYER M1 ;
			RECT 2.795 4.595 3.135 4.68 ;
			LAYER M1 ;
			RECT 5.095 4.6 5.435 4.68 ;
			LAYER M1 ;
			RECT 5.095 4.595 6.295 4.6 ;
			LAYER M1 ;
			RECT 2.175 4.37 6.295 4.595 ;
			LAYER M1 ;
			RECT 2.175 4.365 5.435 4.37 ;
			LAYER M1 ;
			RECT 2.175 3.07 2.405 4.365 ;
			LAYER M1 ;
			RECT 2.795 4.34 3.135 4.365 ;
			LAYER M1 ;
			RECT 5.095 4.34 5.435 4.365 ;
			LAYER M1 ;
			RECT 6.065 4.295 6.295 4.37 ;
			LAYER M1 ;
			RECT 6.065 4.185 6.515 4.295 ;
			LAYER M1 ;
			RECT 6.065 3.845 6.75 4.185 ;
			LAYER M1 ;
			RECT 2.13 2.73 2.47 3.07 ;
		END
		AntennaGateArea 2.6496 ;
	END in1
	PIN GND
		DIRECTION inout ;
		USE GROUND ;
		PORT
			LAYER M1 ;
			RECT 2.34 0.5 2.68 2.01 ;
			LAYER M1 ;
			RECT 3.78 0.5 4.12 2.01 ;
			LAYER M1 ;
			RECT 6.65 0.5 6.99 2.995 ;
			LAYER M1 ;
			RECT 0 -0.5 8.88 0.5 ;
		END
	END GND
	PIN VDD
		DIRECTION inout ;
		USE POWER ;
		PORT
			LAYER M1 ;
			RECT 0 6.9 8.88 7.9 ;
			LAYER M1 ;
			RECT 0.18 4.91 0.52 6.9 ;
			LAYER M1 ;
			RECT 1.62 5.39 1.96 6.9 ;
			LAYER M1 ;
			RECT 3.92 5.39 4.26 6.9 ;
			LAYER M1 ;
			RECT 6.22 4.91 6.56 6.9 ;
			LAYER M1 ;
			RECT 7.66 4.91 8 6.9 ;
		END
	END VDD
	PIN in0
		DIRECTION input ;
		USE SIGNAL ;
		PORT
			LAYER M1 ;
			RECT 4.585 3.5 5.035 3.555 ;
			LAYER M1 ;
			RECT 4.205 3.16 5.035 3.5 ;
			LAYER M1 ;
			RECT 4.585 3.105 5.035 3.16 ;
		END
		AntennaGateArea 2.6496 ;
	END in0
	OBS
		LAYER M1 ;
		RECT 6.94 4.91 7.28 6.67 ;
		LAYER M1 ;
		RECT 2.865 3.88 5.565 4.11 ;
		LAYER M1 ;
		RECT 2.865 3.5 3.095 3.88 ;
		LAYER M1 ;
		RECT 5.335 3.585 5.565 3.88 ;
		LAYER M1 ;
		RECT 2.815 3.16 3.155 3.5 ;
		LAYER M1 ;
		RECT 5.335 3.465 5.73 3.585 ;
		LAYER M1 ;
		RECT 6.99 3.465 7.22 4.91 ;
		LAYER M1 ;
		RECT 5.335 3.235 7.22 3.465 ;
		LAYER M1 ;
		RECT 5.5 2.995 5.73 3.235 ;
		LAYER M1 ;
		RECT 0.18 0.96 0.52 2.49 ;
		LAYER M1 ;
		RECT 1.62 2.26 4.845 2.49 ;
		LAYER M1 ;
		RECT 1.62 0.96 1.96 2.26 ;
		LAYER M1 ;
		RECT 0.18 0.73 1.96 0.96 ;
		LAYER M1 ;
		RECT 3.06 0.73 3.4 2.26 ;
		LAYER M1 ;
		RECT 4.505 0.73 4.845 2.26 ;
		LAYER M1 ;
		RECT 5.5 1.235 5.84 2.995 ;
	END
END MMI_XNOR2C
MACRO MMI_XOR2A
	CLASS CORE ;
	FOREIGN MMI_XOR2A 0 0 ;
	SIZE 5.18 BY 7.4 ;
	SYMMETRY X Y ;
	SITE CORE1 ;
	PIN out
		DIRECTION output ;
		USE SIGNAL ;
		PORT
			LAYER M1 ;
			RECT 0.18 4.185 0.52 5.945 ;
			LAYER M1 ;
			RECT 0.29 3.555 0.52 4.185 ;
			LAYER M1 ;
			RECT 0.145 3.105 0.595 3.555 ;
			LAYER M1 ;
			RECT 0.26 2.615 0.49 3.105 ;
			LAYER M1 ;
			RECT 0.26 2.385 1.17 2.615 ;
			LAYER M1 ;
			RECT 0.94 2.125 1.17 2.385 ;
			LAYER M1 ;
			RECT 0.94 1.285 1.28 2.125 ;
		END
		AntennaDiffArea 1.3708 ;
	END out
	PIN in1
		DIRECTION input ;
		USE SIGNAL ;
		PORT
			LAYER M1 ;
			RECT 3.845 3.5 4.295 3.555 ;
			LAYER M1 ;
			RECT 3.71 3.16 4.295 3.5 ;
			LAYER M1 ;
			RECT 3.845 3.105 4.295 3.16 ;
		END
		AntennaGateArea 0.9108 ;
	END in1
	PIN GND
		DIRECTION inout ;
		USE GROUND ;
		PORT
			LAYER M1 ;
			RECT 0.18 0.5 0.52 2.125 ;
			LAYER M1 ;
			RECT 2.09 0.5 2.43 2.125 ;
			LAYER M1 ;
			RECT 3.57 0.5 3.91 2.125 ;
			LAYER M1 ;
			RECT 0 -0.5 5.18 0.5 ;
		END
	END GND
	PIN VDD
		DIRECTION inout ;
		USE POWER ;
		PORT
			LAYER M1 ;
			RECT 0 6.9 5.18 7.9 ;
			LAYER M1 ;
			RECT 1.62 4.665 1.96 6.9 ;
			LAYER M1 ;
			RECT 4.19 4.185 4.53 6.9 ;
		END
	END VDD
	PIN in0
		DIRECTION input ;
		USE SIGNAL ;
		PORT
			LAYER M1 ;
			RECT 2.2 2.81 2.54 2.82 ;
			LAYER M1 ;
			RECT 1.625 2.48 2.54 2.81 ;
			LAYER M1 ;
			RECT 1.625 2.47 2.38 2.48 ;
			LAYER M1 ;
			RECT 1.625 2.365 2.075 2.47 ;
		END
		AntennaGateArea 0.9108 ;
	END in0
	OBS
		LAYER M1 ;
		RECT 0.9 4.415 1.24 5.945 ;
		LAYER M1 ;
		RECT 2.34 4.415 2.68 5.945 ;
		LAYER M1 ;
		RECT 0.9 4.185 2.68 4.415 ;
		LAYER M1 ;
		RECT 3.04 4.185 3.38 5.945 ;
		LAYER M1 ;
		RECT 0.84 3.48 1.18 3.49 ;
		LAYER M1 ;
		RECT 3.04 3.48 3.27 4.185 ;
		LAYER M1 ;
		RECT 0.84 3.25 3.27 3.48 ;
		LAYER M1 ;
		RECT 0.84 3.15 1.18 3.25 ;
		LAYER M1 ;
		RECT 2.85 2.125 3.08 3.25 ;
		LAYER M1 ;
		RECT 2.85 1.745 3.19 2.125 ;
		LAYER M1 ;
		RECT 2.85 1.71 3.08 1.745 ;
	END
END MMI_XOR2A
MACRO MMI_XOR2B
	CLASS CORE ;
	FOREIGN MMI_XOR2B 0 0 ;
	SIZE 7.4 BY 7.4 ;
	SYMMETRY X Y ;
	SITE CORE1 ;
	PIN out
		DIRECTION output ;
		USE SIGNAL ;
		PORT
			LAYER M1 ;
			RECT 0.9 4.18 1.24 5.46 ;
			LAYER M1 ;
			RECT 0.145 3.445 0.595 3.555 ;
			LAYER M1 ;
			RECT 0.9 3.445 1.13 4.18 ;
			LAYER M1 ;
			RECT 0.145 3.215 1.13 3.445 ;
			LAYER M1 ;
			RECT 0.145 3.105 0.595 3.215 ;
			LAYER M1 ;
			RECT 0.9 2.79 1.13 3.215 ;
			LAYER M1 ;
			RECT 0.9 1.88 1.24 2.79 ;
			LAYER M1 ;
			RECT 2.34 1.88 2.68 2.29 ;
			LAYER M1 ;
			RECT 0.9 1.65 2.68 1.88 ;
		END
		AntennaDiffArea 1.932 ;
	END out
	PIN in1
		DIRECTION input ;
		USE SIGNAL ;
		PORT
			LAYER M1 ;
			RECT 6.55 2.815 6.89 2.84 ;
			LAYER M1 ;
			RECT 6.55 2.5 7.255 2.815 ;
			LAYER M1 ;
			RECT 6.61 2.47 7.255 2.5 ;
			LAYER M1 ;
			RECT 6.805 2.365 7.255 2.47 ;
		END
		AntennaGateArea 1.4076 ;
	END in1
	PIN GND
		DIRECTION inout ;
		USE GROUND ;
		PORT
			LAYER M1 ;
			RECT 0.18 0.5 0.52 2.79 ;
			LAYER M1 ;
			RECT 3.04 0.5 3.38 2.29 ;
			LAYER M1 ;
			RECT 4.48 0.5 4.82 2.79 ;
			LAYER M1 ;
			RECT 5.96 0.5 6.3 2.49 ;
			LAYER M1 ;
			RECT 0 -0.5 7.4 0.5 ;
		END
	END GND
	PIN VDD
		DIRECTION inout ;
		USE POWER ;
		PORT
			LAYER M1 ;
			RECT 0 6.9 7.4 7.9 ;
			LAYER M1 ;
			RECT 2.34 4.66 2.68 6.9 ;
			LAYER M1 ;
			RECT 3.78 4.66 4.12 6.9 ;
			LAYER M1 ;
			RECT 6.35 4.18 6.69 6.9 ;
		END
	END VDD
	PIN in0
		DIRECTION input ;
		USE SIGNAL ;
		PORT
			LAYER M1 ;
			RECT 6.065 3.5 6.515 3.555 ;
			LAYER M1 ;
			RECT 5.7 3.16 6.515 3.5 ;
			LAYER M1 ;
			RECT 6.065 3.105 6.515 3.16 ;
		END
		AntennaGateArea 1.4076 ;
	END in0
	OBS
		LAYER M1 ;
		RECT 0.18 6.01 1.96 6.24 ;
		LAYER M1 ;
		RECT 0.18 4.18 0.52 6.01 ;
		LAYER M1 ;
		RECT 1.62 4.41 1.96 6.01 ;
		LAYER M1 ;
		RECT 3.06 4.41 3.4 5.94 ;
		LAYER M1 ;
		RECT 4.5 4.41 4.84 5.94 ;
		LAYER M1 ;
		RECT 1.62 4.18 4.84 4.41 ;
		LAYER M1 ;
		RECT 5.2 4.18 5.54 5.94 ;
		LAYER M1 ;
		RECT 1.36 3.77 1.7 3.825 ;
		LAYER M1 ;
		RECT 5.2 3.77 5.43 4.18 ;
		LAYER M1 ;
		RECT 1.36 3.54 5.47 3.77 ;
		LAYER M1 ;
		RECT 1.36 3.485 1.7 3.54 ;
		LAYER M1 ;
		RECT 1.62 2.56 4.1 2.79 ;
		LAYER M1 ;
		RECT 1.62 2.45 1.96 2.56 ;
		LAYER M1 ;
		RECT 3.76 1.95 4.1 2.56 ;
		LAYER M1 ;
		RECT 5.24 2.49 5.47 3.54 ;
		LAYER M1 ;
		RECT 5.24 2.11 5.58 2.49 ;
	END
END MMI_XOR2B
MACRO MMI_XOR2C
	CLASS CORE ;
	FOREIGN MMI_XOR2C 0 0 ;
	SIZE 10.36 BY 7.4 ;
	SYMMETRY X Y ;
	SITE CORE1 ;
	PIN out
		DIRECTION output ;
		USE SIGNAL ;
		PORT
			LAYER M1 ;
			RECT 0.18 6.44 1.96 6.67 ;
			LAYER M1 ;
			RECT 0.18 4.295 0.52 6.44 ;
			LAYER M1 ;
			RECT 1.62 4.915 1.96 6.44 ;
			LAYER M1 ;
			RECT 0.29 3.555 0.52 4.295 ;
			LAYER M1 ;
			RECT 0.145 3.105 0.595 3.555 ;
			LAYER M1 ;
			RECT 0.29 2.41 0.52 3.105 ;
			LAYER M1 ;
			RECT 0.18 2.18 2 2.41 ;
			LAYER M1 ;
			RECT 0.18 1.57 0.52 2.18 ;
			LAYER M1 ;
			RECT 1.66 1.495 2 2.18 ;
			LAYER M1 ;
			RECT 3.1 1.495 3.44 1.605 ;
			LAYER M1 ;
			RECT 1.66 1.265 3.44 1.495 ;
		END
		AntennaDiffArea 4.2872 ;
	END out
	PIN in1
		DIRECTION input ;
		USE SIGNAL ;
		PORT
			LAYER M1 ;
			RECT 4.585 3.445 5.035 3.59 ;
			LAYER M1 ;
			RECT 7.11 3.445 7.45 3.555 ;
			LAYER M1 ;
			RECT 3.555 3.39 3.895 3.445 ;
			LAYER M1 ;
			RECT 4.585 3.39 7.45 3.445 ;
			LAYER M1 ;
			RECT 3.555 3.215 7.45 3.39 ;
			LAYER M1 ;
			RECT 3.555 3.16 5.035 3.215 ;
			LAYER M1 ;
			RECT 3.555 3.105 3.895 3.16 ;
			LAYER M1 ;
			RECT 4.585 3.105 5.035 3.16 ;
		END
		AntennaGateArea 2.8152 ;
	END in1
	PIN GND
		DIRECTION inout ;
		USE GROUND ;
		PORT
			LAYER M1 ;
			RECT 0.9 0.5 1.24 1.91 ;
			LAYER M1 ;
			RECT 4.54 0.5 4.88 1.605 ;
			LAYER M1 ;
			RECT 5.98 0.5 6.32 2.41 ;
			LAYER M1 ;
			RECT 7.68 0.5 8.02 2.515 ;
			LAYER M1 ;
			RECT 9.16 0.5 9.5 2.515 ;
			LAYER M1 ;
			RECT 0 -0.5 10.36 0.5 ;
		END
	END GND
	PIN VDD
		DIRECTION inout ;
		USE POWER ;
		PORT
			LAYER M1 ;
			RECT 0 6.9 10.36 7.9 ;
			LAYER M1 ;
			RECT 3.06 4.915 3.4 6.9 ;
			LAYER M1 ;
			RECT 4.5 4.915 4.84 6.9 ;
			LAYER M1 ;
			RECT 5.94 4.915 6.28 6.9 ;
			LAYER M1 ;
			RECT 7.36 4.295 7.7 6.9 ;
			LAYER M1 ;
			RECT 9.66 4.295 10 6.9 ;
		END
	END VDD
	PIN in0
		DIRECTION input ;
		USE SIGNAL ;
		PORT
			LAYER M1 ;
			RECT 7.86 3.185 8.2 3.525 ;
			LAYER M1 ;
			RECT 7.86 2.98 8.09 3.185 ;
			LAYER M1 ;
			RECT 5.7 2.75 8.09 2.98 ;
			LAYER M1 ;
			RECT 5.7 2.64 6.04 2.75 ;
			LAYER M1 ;
			RECT 6.79 2.34 7.255 2.75 ;
		END
		AntennaGateArea 2.8152 ;
	END in0
	OBS
		LAYER M1 ;
		RECT 0.9 4.525 1.24 6.045 ;
		LAYER M1 ;
		RECT 2.34 4.525 2.68 6.67 ;
		LAYER M1 ;
		RECT 3.78 4.525 4.12 6.67 ;
		LAYER M1 ;
		RECT 5.22 4.525 5.56 6.67 ;
		LAYER M1 ;
		RECT 6.66 4.525 7 6.67 ;
		LAYER M1 ;
		RECT 0.9 4.295 7 4.525 ;
		LAYER M1 ;
		RECT 8.51 4.295 8.85 6.055 ;
		LAYER M1 ;
		RECT 8.51 4.055 8.74 4.295 ;
		LAYER M1 ;
		RECT 1.14 3.825 8.74 4.055 ;
		LAYER M1 ;
		RECT 1.14 3.715 1.48 3.825 ;
		LAYER M1 ;
		RECT 1.195 3.11 1.425 3.715 ;
		LAYER M1 ;
		RECT 1.14 2.77 1.48 3.11 ;
		LAYER M1 ;
		RECT 2.38 2.18 5.6 2.41 ;
		LAYER M1 ;
		RECT 2.38 2.065 2.72 2.18 ;
		LAYER M1 ;
		RECT 3.82 1.265 4.16 2.18 ;
		LAYER M1 ;
		RECT 5.26 1.265 5.6 2.18 ;
		LAYER M1 ;
		RECT 8.51 2.515 8.74 3.825 ;
		LAYER M1 ;
		RECT 8.4 1.675 8.74 2.515 ;
	END
END MMI_XOR2C
END LIBRARY
